###############################################################
#  Generated by:      Cadence Innovus 20.13-s083_1
#  OS:                Linux x86_64(Host ID iron-502-26)
#  Generated on:      Tue Nov 22 18:44:17 2022
#  Design:            user_proj_example
#  Command:           write_lef_abstract -specifyTopLayer 5 -PGPinLayers {5 6} -extractBlockObs -stripePin results/user_proj_example.lef
###############################################################

VERSION 5.8 ;

BUSBITCHARS "[]" ;
DIVIDERCHAR "/" ;

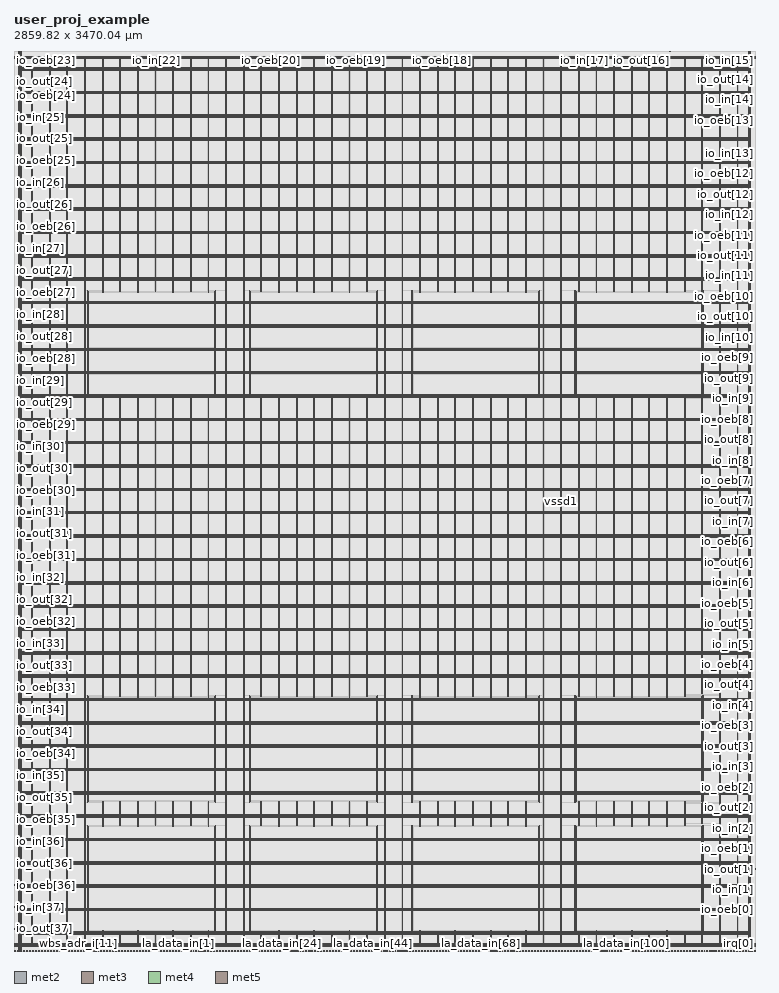
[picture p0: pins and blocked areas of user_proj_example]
MACRO user_proj_example
  CLASS BLOCK ;
  SIZE 2859.820000 BY 3470.040000 ;
  FOREIGN user_proj_example 0.000000 0.000000 ;
  ORIGIN 0 0 ;
  SYMMETRY X Y R90 ;
  PIN la_data_in[127]
    DIRECTION INPUT ;
    USE SIGNAL ;
    PORT
      LAYER met2 ;
        RECT 2830.540000 0.000000 2830.680000 0.485000 ;
    END
  END la_data_in[127]
  PIN la_data_in[126]
    DIRECTION INPUT ;
    USE SIGNAL ;
    PORT
      LAYER met2 ;
        RECT 2813.060000 0.000000 2813.200000 0.485000 ;
    END
  END la_data_in[126]
  PIN la_data_in[125]
    DIRECTION INPUT ;
    USE SIGNAL ;
    PORT
      LAYER met2 ;
        RECT 2796.040000 0.000000 2796.180000 0.485000 ;
    END
  END la_data_in[125]
  PIN la_data_in[124]
    DIRECTION INPUT ;
    USE SIGNAL ;
    PORT
      LAYER met2 ;
        RECT 2778.560000 0.000000 2778.700000 0.485000 ;
    END
  END la_data_in[124]
  PIN la_data_in[123]
    DIRECTION INPUT ;
    USE SIGNAL ;
    PORT
      LAYER met2 ;
        RECT 2761.080000 0.000000 2761.220000 0.485000 ;
    END
  END la_data_in[123]
  PIN la_data_in[122]
    DIRECTION INPUT ;
    USE SIGNAL ;
    PORT
      LAYER met2 ;
        RECT 2743.600000 0.000000 2743.740000 0.485000 ;
    END
  END la_data_in[122]
  PIN la_data_in[121]
    DIRECTION INPUT ;
    USE SIGNAL ;
    PORT
      LAYER met2 ;
        RECT 2726.120000 0.000000 2726.260000 0.485000 ;
    END
  END la_data_in[121]
  PIN la_data_in[120]
    DIRECTION INPUT ;
    USE SIGNAL ;
    PORT
      LAYER met2 ;
        RECT 2708.640000 0.000000 2708.780000 0.485000 ;
    END
  END la_data_in[120]
  PIN la_data_in[119]
    DIRECTION INPUT ;
    USE SIGNAL ;
    PORT
      LAYER met2 ;
        RECT 2691.160000 0.000000 2691.300000 0.485000 ;
    END
  END la_data_in[119]
  PIN la_data_in[118]
    DIRECTION INPUT ;
    USE SIGNAL ;
    PORT
      LAYER met2 ;
        RECT 2673.680000 0.000000 2673.820000 0.485000 ;
    END
  END la_data_in[118]
  PIN la_data_in[117]
    DIRECTION INPUT ;
    USE SIGNAL ;
    PORT
      LAYER met2 ;
        RECT 2656.200000 0.000000 2656.340000 0.485000 ;
    END
  END la_data_in[117]
  PIN la_data_in[116]
    DIRECTION INPUT ;
    USE SIGNAL ;
    PORT
      LAYER met2 ;
        RECT 2638.720000 0.000000 2638.860000 0.485000 ;
    END
  END la_data_in[116]
  PIN la_data_in[115]
    DIRECTION INPUT ;
    USE SIGNAL ;
    PORT
      LAYER met2 ;
        RECT 2621.700000 0.000000 2621.840000 0.485000 ;
    END
  END la_data_in[115]
  PIN la_data_in[114]
    DIRECTION INPUT ;
    USE SIGNAL ;
    PORT
      LAYER met2 ;
        RECT 2604.220000 0.000000 2604.360000 0.485000 ;
    END
  END la_data_in[114]
  PIN la_data_in[113]
    DIRECTION INPUT ;
    USE SIGNAL ;
    PORT
      LAYER met2 ;
        RECT 2586.740000 0.000000 2586.880000 0.485000 ;
    END
  END la_data_in[113]
  PIN la_data_in[112]
    DIRECTION INPUT ;
    USE SIGNAL ;
    PORT
      LAYER met2 ;
        RECT 2569.260000 0.000000 2569.400000 0.485000 ;
    END
  END la_data_in[112]
  PIN la_data_in[111]
    DIRECTION INPUT ;
    USE SIGNAL ;
    PORT
      LAYER met2 ;
        RECT 2551.780000 0.000000 2551.920000 0.485000 ;
    END
  END la_data_in[111]
  PIN la_data_in[110]
    DIRECTION INPUT ;
    USE SIGNAL ;
    PORT
      LAYER met2 ;
        RECT 2534.300000 0.000000 2534.440000 0.485000 ;
    END
  END la_data_in[110]
  PIN la_data_in[109]
    DIRECTION INPUT ;
    USE SIGNAL ;
    PORT
      LAYER met2 ;
        RECT 2516.820000 0.000000 2516.960000 0.485000 ;
    END
  END la_data_in[109]
  PIN la_data_in[108]
    DIRECTION INPUT ;
    USE SIGNAL ;
    PORT
      LAYER met2 ;
        RECT 2499.340000 0.000000 2499.480000 0.485000 ;
    END
  END la_data_in[108]
  PIN la_data_in[107]
    DIRECTION INPUT ;
    USE SIGNAL ;
    PORT
      LAYER met2 ;
        RECT 2481.860000 0.000000 2482.000000 0.485000 ;
    END
  END la_data_in[107]
  PIN la_data_in[106]
    DIRECTION INPUT ;
    USE SIGNAL ;
    PORT
      LAYER met2 ;
        RECT 2464.380000 0.000000 2464.520000 0.485000 ;
    END
  END la_data_in[106]
  PIN la_data_in[105]
    DIRECTION INPUT ;
    USE SIGNAL ;
    PORT
      LAYER met2 ;
        RECT 2446.900000 0.000000 2447.040000 0.485000 ;
    END
  END la_data_in[105]
  PIN la_data_in[104]
    DIRECTION INPUT ;
    USE SIGNAL ;
    PORT
      LAYER met2 ;
        RECT 2429.880000 0.000000 2430.020000 0.485000 ;
    END
  END la_data_in[104]
  PIN la_data_in[103]
    DIRECTION INPUT ;
    USE SIGNAL ;
    PORT
      LAYER met2 ;
        RECT 2412.400000 0.000000 2412.540000 0.485000 ;
    END
  END la_data_in[103]
  PIN la_data_in[102]
    DIRECTION INPUT ;
    USE SIGNAL ;
    PORT
      LAYER met2 ;
        RECT 2394.920000 0.000000 2395.060000 0.485000 ;
    END
  END la_data_in[102]
  PIN la_data_in[101]
    DIRECTION INPUT ;
    USE SIGNAL ;
    PORT
      LAYER met2 ;
        RECT 2377.440000 0.000000 2377.580000 0.485000 ;
    END
  END la_data_in[101]
  PIN la_data_in[100]
    DIRECTION INPUT ;
    USE SIGNAL ;
    PORT
      LAYER met2 ;
        RECT 2359.960000 0.000000 2360.100000 0.485000 ;
    END
  END la_data_in[100]
  PIN la_data_in[99]
    DIRECTION INPUT ;
    USE SIGNAL ;
    PORT
      LAYER met2 ;
        RECT 2342.480000 0.000000 2342.620000 0.485000 ;
    END
  END la_data_in[99]
  PIN la_data_in[98]
    DIRECTION INPUT ;
    USE SIGNAL ;
    PORT
      LAYER met2 ;
        RECT 2325.000000 0.000000 2325.140000 0.485000 ;
    END
  END la_data_in[98]
  PIN la_data_in[97]
    DIRECTION INPUT ;
    USE SIGNAL ;
    PORT
      LAYER met2 ;
        RECT 2307.520000 0.000000 2307.660000 0.485000 ;
    END
  END la_data_in[97]
  PIN la_data_in[96]
    DIRECTION INPUT ;
    USE SIGNAL ;
    PORT
      LAYER met2 ;
        RECT 2290.040000 0.000000 2290.180000 0.485000 ;
    END
  END la_data_in[96]
  PIN la_data_in[95]
    DIRECTION INPUT ;
    USE SIGNAL ;
    PORT
      LAYER met2 ;
        RECT 2272.560000 0.000000 2272.700000 0.485000 ;
    END
  END la_data_in[95]
  PIN la_data_in[94]
    DIRECTION INPUT ;
    USE SIGNAL ;
    PORT
      LAYER met2 ;
        RECT 2255.540000 0.000000 2255.680000 0.485000 ;
    END
  END la_data_in[94]
  PIN la_data_in[93]
    DIRECTION INPUT ;
    USE SIGNAL ;
    PORT
      LAYER met2 ;
        RECT 2238.060000 0.000000 2238.200000 0.485000 ;
    END
  END la_data_in[93]
  PIN la_data_in[92]
    DIRECTION INPUT ;
    USE SIGNAL ;
    PORT
      LAYER met2 ;
        RECT 2220.580000 0.000000 2220.720000 0.485000 ;
    END
  END la_data_in[92]
  PIN la_data_in[91]
    DIRECTION INPUT ;
    USE SIGNAL ;
    PORT
      LAYER met2 ;
        RECT 2203.100000 0.000000 2203.240000 0.485000 ;
    END
  END la_data_in[91]
  PIN la_data_in[90]
    DIRECTION INPUT ;
    USE SIGNAL ;
    PORT
      LAYER met2 ;
        RECT 2185.620000 0.000000 2185.760000 0.485000 ;
    END
  END la_data_in[90]
  PIN la_data_in[89]
    DIRECTION INPUT ;
    USE SIGNAL ;
    PORT
      LAYER met2 ;
        RECT 2168.140000 0.000000 2168.280000 0.485000 ;
    END
  END la_data_in[89]
  PIN la_data_in[88]
    DIRECTION INPUT ;
    USE SIGNAL ;
    PORT
      LAYER met2 ;
        RECT 2150.660000 0.000000 2150.800000 0.485000 ;
    END
  END la_data_in[88]
  PIN la_data_in[87]
    DIRECTION INPUT ;
    USE SIGNAL ;
    PORT
      LAYER met2 ;
        RECT 2133.180000 0.000000 2133.320000 0.485000 ;
    END
  END la_data_in[87]
  PIN la_data_in[86]
    DIRECTION INPUT ;
    USE SIGNAL ;
    PORT
      LAYER met2 ;
        RECT 2115.700000 0.000000 2115.840000 0.485000 ;
    END
  END la_data_in[86]
  PIN la_data_in[85]
    DIRECTION INPUT ;
    USE SIGNAL ;
    PORT
      LAYER met2 ;
        RECT 2098.220000 0.000000 2098.360000 0.485000 ;
    END
  END la_data_in[85]
  PIN la_data_in[84]
    DIRECTION INPUT ;
    USE SIGNAL ;
    PORT
      LAYER met2 ;
        RECT 2081.200000 0.000000 2081.340000 0.485000 ;
    END
  END la_data_in[84]
  PIN la_data_in[83]
    DIRECTION INPUT ;
    USE SIGNAL ;
    PORT
      LAYER met2 ;
        RECT 2063.720000 0.000000 2063.860000 0.485000 ;
    END
  END la_data_in[83]
  PIN la_data_in[82]
    DIRECTION INPUT ;
    USE SIGNAL ;
    PORT
      LAYER met2 ;
        RECT 2046.240000 0.000000 2046.380000 0.485000 ;
    END
  END la_data_in[82]
  PIN la_data_in[81]
    DIRECTION INPUT ;
    USE SIGNAL ;
    PORT
      LAYER met2 ;
        RECT 2028.760000 0.000000 2028.900000 0.485000 ;
    END
  END la_data_in[81]
  PIN la_data_in[80]
    DIRECTION INPUT ;
    USE SIGNAL ;
    PORT
      LAYER met2 ;
        RECT 2011.280000 0.000000 2011.420000 0.485000 ;
    END
  END la_data_in[80]
  PIN la_data_in[79]
    DIRECTION INPUT ;
    USE SIGNAL ;
    PORT
      LAYER met2 ;
        RECT 1993.800000 0.000000 1993.940000 0.485000 ;
    END
  END la_data_in[79]
  PIN la_data_in[78]
    DIRECTION INPUT ;
    USE SIGNAL ;
    PORT
      LAYER met2 ;
        RECT 1976.320000 0.000000 1976.460000 0.485000 ;
    END
  END la_data_in[78]
  PIN la_data_in[77]
    DIRECTION INPUT ;
    USE SIGNAL ;
    PORT
      LAYER met2 ;
        RECT 1958.840000 0.000000 1958.980000 0.485000 ;
    END
  END la_data_in[77]
  PIN la_data_in[76]
    DIRECTION INPUT ;
    USE SIGNAL ;
    PORT
      LAYER met2 ;
        RECT 1941.360000 0.000000 1941.500000 0.485000 ;
    END
  END la_data_in[76]
  PIN la_data_in[75]
    DIRECTION INPUT ;
    USE SIGNAL ;
    PORT
      LAYER met2 ;
        RECT 1923.880000 0.000000 1924.020000 0.485000 ;
    END
  END la_data_in[75]
  PIN la_data_in[74]
    DIRECTION INPUT ;
    USE SIGNAL ;
    PORT
      LAYER met2 ;
        RECT 1906.400000 0.000000 1906.540000 0.485000 ;
    END
  END la_data_in[74]
  PIN la_data_in[73]
    DIRECTION INPUT ;
    USE SIGNAL ;
    PORT
      LAYER met2 ;
        RECT 1889.380000 0.000000 1889.520000 0.485000 ;
    END
  END la_data_in[73]
  PIN la_data_in[72]
    DIRECTION INPUT ;
    USE SIGNAL ;
    PORT
      LAYER met2 ;
        RECT 1871.900000 0.000000 1872.040000 0.485000 ;
    END
  END la_data_in[72]
  PIN la_data_in[71]
    DIRECTION INPUT ;
    USE SIGNAL ;
    PORT
      LAYER met2 ;
        RECT 1854.420000 0.000000 1854.560000 0.485000 ;
    END
  END la_data_in[71]
  PIN la_data_in[70]
    DIRECTION INPUT ;
    USE SIGNAL ;
    PORT
      LAYER met2 ;
        RECT 1836.940000 0.000000 1837.080000 0.485000 ;
    END
  END la_data_in[70]
  PIN la_data_in[69]
    DIRECTION INPUT ;
    USE SIGNAL ;
    PORT
      LAYER met2 ;
        RECT 1819.460000 0.000000 1819.600000 0.485000 ;
    END
  END la_data_in[69]
  PIN la_data_in[68]
    DIRECTION INPUT ;
    USE SIGNAL ;
    PORT
      LAYER met2 ;
        RECT 1801.980000 0.000000 1802.120000 0.485000 ;
    END
  END la_data_in[68]
  PIN la_data_in[67]
    DIRECTION INPUT ;
    USE SIGNAL ;
    PORT
      LAYER met2 ;
        RECT 1784.500000 0.000000 1784.640000 0.485000 ;
    END
  END la_data_in[67]
  PIN la_data_in[66]
    DIRECTION INPUT ;
    USE SIGNAL ;
    PORT
      LAYER met2 ;
        RECT 1767.020000 0.000000 1767.160000 0.485000 ;
    END
  END la_data_in[66]
  PIN la_data_in[65]
    DIRECTION INPUT ;
    USE SIGNAL ;
    PORT
      LAYER met2 ;
        RECT 1749.540000 0.000000 1749.680000 0.485000 ;
    END
  END la_data_in[65]
  PIN la_data_in[64]
    DIRECTION INPUT ;
    USE SIGNAL ;
    PORT
      LAYER met2 ;
        RECT 1732.060000 0.000000 1732.200000 0.485000 ;
    END
  END la_data_in[64]
  PIN la_data_in[63]
    DIRECTION INPUT ;
    USE SIGNAL ;
    PORT
      LAYER met2 ;
        RECT 1715.040000 0.000000 1715.180000 0.485000 ;
    END
  END la_data_in[63]
  PIN la_data_in[62]
    DIRECTION INPUT ;
    USE SIGNAL ;
    PORT
      LAYER met2 ;
        RECT 1697.560000 0.000000 1697.700000 0.485000 ;
    END
  END la_data_in[62]
  PIN la_data_in[61]
    DIRECTION INPUT ;
    USE SIGNAL ;
    PORT
      LAYER met2 ;
        RECT 1680.080000 0.000000 1680.220000 0.485000 ;
    END
  END la_data_in[61]
  PIN la_data_in[60]
    DIRECTION INPUT ;
    USE SIGNAL ;
    PORT
      LAYER met2 ;
        RECT 1662.600000 0.000000 1662.740000 0.485000 ;
    END
  END la_data_in[60]
  PIN la_data_in[59]
    DIRECTION INPUT ;
    USE SIGNAL ;
    PORT
      LAYER met2 ;
        RECT 1645.120000 0.000000 1645.260000 0.485000 ;
    END
  END la_data_in[59]
  PIN la_data_in[58]
    DIRECTION INPUT ;
    USE SIGNAL ;
    PORT
      LAYER met2 ;
        RECT 1627.640000 0.000000 1627.780000 0.485000 ;
    END
  END la_data_in[58]
  PIN la_data_in[57]
    DIRECTION INPUT ;
    USE SIGNAL ;
    PORT
      LAYER met2 ;
        RECT 1610.160000 0.000000 1610.300000 0.485000 ;
    END
  END la_data_in[57]
  PIN la_data_in[56]
    DIRECTION INPUT ;
    USE SIGNAL ;
    PORT
      LAYER met2 ;
        RECT 1592.680000 0.000000 1592.820000 0.485000 ;
    END
  END la_data_in[56]
  PIN la_data_in[55]
    DIRECTION INPUT ;
    USE SIGNAL ;
    PORT
      LAYER met2 ;
        RECT 1575.200000 0.000000 1575.340000 0.485000 ;
    END
  END la_data_in[55]
  PIN la_data_in[54]
    DIRECTION INPUT ;
    USE SIGNAL ;
    PORT
      LAYER met2 ;
        RECT 1557.720000 0.000000 1557.860000 0.485000 ;
    END
  END la_data_in[54]
  PIN la_data_in[53]
    DIRECTION INPUT ;
    USE SIGNAL ;
    PORT
      LAYER met2 ;
        RECT 1540.700000 0.000000 1540.840000 0.485000 ;
    END
  END la_data_in[53]
  PIN la_data_in[52]
    DIRECTION INPUT ;
    USE SIGNAL ;
    PORT
      LAYER met2 ;
        RECT 1523.220000 0.000000 1523.360000 0.485000 ;
    END
  END la_data_in[52]
  PIN la_data_in[51]
    DIRECTION INPUT ;
    USE SIGNAL ;
    PORT
      LAYER met2 ;
        RECT 1505.740000 0.000000 1505.880000 0.485000 ;
    END
  END la_data_in[51]
  PIN la_data_in[50]
    DIRECTION INPUT ;
    USE SIGNAL ;
    PORT
      LAYER met2 ;
        RECT 1488.260000 0.000000 1488.400000 0.485000 ;
    END
  END la_data_in[50]
  PIN la_data_in[49]
    DIRECTION INPUT ;
    USE SIGNAL ;
    PORT
      LAYER met2 ;
        RECT 1470.780000 0.000000 1470.920000 0.485000 ;
    END
  END la_data_in[49]
  PIN la_data_in[48]
    DIRECTION INPUT ;
    USE SIGNAL ;
    PORT
      LAYER met2 ;
        RECT 1453.300000 0.000000 1453.440000 0.485000 ;
    END
  END la_data_in[48]
  PIN la_data_in[47]
    DIRECTION INPUT ;
    USE SIGNAL ;
    PORT
      LAYER met2 ;
        RECT 1435.820000 0.000000 1435.960000 0.485000 ;
    END
  END la_data_in[47]
  PIN la_data_in[46]
    DIRECTION INPUT ;
    USE SIGNAL ;
    PORT
      LAYER met2 ;
        RECT 1418.340000 0.000000 1418.480000 0.485000 ;
    END
  END la_data_in[46]
  PIN la_data_in[45]
    DIRECTION INPUT ;
    USE SIGNAL ;
    PORT
      LAYER met2 ;
        RECT 1400.860000 0.000000 1401.000000 0.485000 ;
    END
  END la_data_in[45]
  PIN la_data_in[44]
    DIRECTION INPUT ;
    USE SIGNAL ;
    PORT
      LAYER met2 ;
        RECT 1383.380000 0.000000 1383.520000 0.485000 ;
    END
  END la_data_in[44]
  PIN la_data_in[43]
    DIRECTION INPUT ;
    USE SIGNAL ;
    PORT
      LAYER met2 ;
        RECT 1366.360000 0.000000 1366.500000 0.485000 ;
    END
  END la_data_in[43]
  PIN la_data_in[42]
    DIRECTION INPUT ;
    USE SIGNAL ;
    PORT
      LAYER met2 ;
        RECT 1348.880000 0.000000 1349.020000 0.485000 ;
    END
  END la_data_in[42]
  PIN la_data_in[41]
    DIRECTION INPUT ;
    USE SIGNAL ;
    PORT
      LAYER met2 ;
        RECT 1331.400000 0.000000 1331.540000 0.485000 ;
    END
  END la_data_in[41]
  PIN la_data_in[40]
    DIRECTION INPUT ;
    USE SIGNAL ;
    PORT
      LAYER met2 ;
        RECT 1313.920000 0.000000 1314.060000 0.485000 ;
    END
  END la_data_in[40]
  PIN la_data_in[39]
    DIRECTION INPUT ;
    USE SIGNAL ;
    PORT
      LAYER met2 ;
        RECT 1296.440000 0.000000 1296.580000 0.485000 ;
    END
  END la_data_in[39]
  PIN la_data_in[38]
    DIRECTION INPUT ;
    USE SIGNAL ;
    PORT
      LAYER met2 ;
        RECT 1278.960000 0.000000 1279.100000 0.485000 ;
    END
  END la_data_in[38]
  PIN la_data_in[37]
    DIRECTION INPUT ;
    USE SIGNAL ;
    PORT
      LAYER met2 ;
        RECT 1261.480000 0.000000 1261.620000 0.485000 ;
    END
  END la_data_in[37]
  PIN la_data_in[36]
    DIRECTION INPUT ;
    USE SIGNAL ;
    PORT
      LAYER met2 ;
        RECT 1244.000000 0.000000 1244.140000 0.485000 ;
    END
  END la_data_in[36]
  PIN la_data_in[35]
    DIRECTION INPUT ;
    USE SIGNAL ;
    PORT
      LAYER met2 ;
        RECT 1226.520000 0.000000 1226.660000 0.485000 ;
    END
  END la_data_in[35]
  PIN la_data_in[34]
    DIRECTION INPUT ;
    USE SIGNAL ;
    PORT
      LAYER met2 ;
        RECT 1209.040000 0.000000 1209.180000 0.485000 ;
    END
  END la_data_in[34]
  PIN la_data_in[33]
    DIRECTION INPUT ;
    USE SIGNAL ;
    PORT
      LAYER met2 ;
        RECT 1192.020000 0.000000 1192.160000 0.485000 ;
    END
  END la_data_in[33]
  PIN la_data_in[32]
    DIRECTION INPUT ;
    USE SIGNAL ;
    PORT
      LAYER met2 ;
        RECT 1174.540000 0.000000 1174.680000 0.485000 ;
    END
  END la_data_in[32]
  PIN la_data_in[31]
    DIRECTION INPUT ;
    USE SIGNAL ;
    PORT
      LAYER met2 ;
        RECT 1157.060000 0.000000 1157.200000 0.485000 ;
    END
  END la_data_in[31]
  PIN la_data_in[30]
    DIRECTION INPUT ;
    USE SIGNAL ;
    PORT
      LAYER met2 ;
        RECT 1139.580000 0.000000 1139.720000 0.485000 ;
    END
  END la_data_in[30]
  PIN la_data_in[29]
    DIRECTION INPUT ;
    USE SIGNAL ;
    PORT
      LAYER met2 ;
        RECT 1122.100000 0.000000 1122.240000 0.485000 ;
    END
  END la_data_in[29]
  PIN la_data_in[28]
    DIRECTION INPUT ;
    USE SIGNAL ;
    PORT
      LAYER met2 ;
        RECT 1104.620000 0.000000 1104.760000 0.485000 ;
    END
  END la_data_in[28]
  PIN la_data_in[27]
    DIRECTION INPUT ;
    USE SIGNAL ;
    PORT
      LAYER met2 ;
        RECT 1087.140000 0.000000 1087.280000 0.485000 ;
    END
  END la_data_in[27]
  PIN la_data_in[26]
    DIRECTION INPUT ;
    USE SIGNAL ;
    PORT
      LAYER met2 ;
        RECT 1069.660000 0.000000 1069.800000 0.485000 ;
    END
  END la_data_in[26]
  PIN la_data_in[25]
    DIRECTION INPUT ;
    USE SIGNAL ;
    PORT
      LAYER met2 ;
        RECT 1052.180000 0.000000 1052.320000 0.485000 ;
    END
  END la_data_in[25]
  PIN la_data_in[24]
    DIRECTION INPUT ;
    USE SIGNAL ;
    PORT
      LAYER met2 ;
        RECT 1034.700000 0.000000 1034.840000 0.485000 ;
    END
  END la_data_in[24]
  PIN la_data_in[23]
    DIRECTION INPUT ;
    USE SIGNAL ;
    PORT
      LAYER met2 ;
        RECT 1017.220000 0.000000 1017.360000 0.485000 ;
    END
  END la_data_in[23]
  PIN la_data_in[22]
    DIRECTION INPUT ;
    USE SIGNAL ;
    PORT
      LAYER met2 ;
        RECT 1000.200000 0.000000 1000.340000 0.485000 ;
    END
  END la_data_in[22]
  PIN la_data_in[21]
    DIRECTION INPUT ;
    USE SIGNAL ;
    PORT
      LAYER met2 ;
        RECT 982.720000 0.000000 982.860000 0.485000 ;
    END
  END la_data_in[21]
  PIN la_data_in[20]
    DIRECTION INPUT ;
    USE SIGNAL ;
    PORT
      LAYER met2 ;
        RECT 965.240000 0.000000 965.380000 0.485000 ;
    END
  END la_data_in[20]
  PIN la_data_in[19]
    DIRECTION INPUT ;
    USE SIGNAL ;
    PORT
      LAYER met2 ;
        RECT 947.760000 0.000000 947.900000 0.485000 ;
    END
  END la_data_in[19]
  PIN la_data_in[18]
    DIRECTION INPUT ;
    USE SIGNAL ;
    PORT
      LAYER met2 ;
        RECT 930.280000 0.000000 930.420000 0.485000 ;
    END
  END la_data_in[18]
  PIN la_data_in[17]
    DIRECTION INPUT ;
    USE SIGNAL ;
    PORT
      LAYER met2 ;
        RECT 912.800000 0.000000 912.940000 0.485000 ;
    END
  END la_data_in[17]
  PIN la_data_in[16]
    DIRECTION INPUT ;
    USE SIGNAL ;
    PORT
      LAYER met2 ;
        RECT 895.320000 0.000000 895.460000 0.485000 ;
    END
  END la_data_in[16]
  PIN la_data_in[15]
    DIRECTION INPUT ;
    USE SIGNAL ;
    PORT
      LAYER met2 ;
        RECT 877.840000 0.000000 877.980000 0.485000 ;
    END
  END la_data_in[15]
  PIN la_data_in[14]
    DIRECTION INPUT ;
    USE SIGNAL ;
    PORT
      LAYER met2 ;
        RECT 860.360000 0.000000 860.500000 0.485000 ;
    END
  END la_data_in[14]
  PIN la_data_in[13]
    DIRECTION INPUT ;
    USE SIGNAL ;
    PORT
      LAYER met2 ;
        RECT 842.880000 0.000000 843.020000 0.485000 ;
    END
  END la_data_in[13]
  PIN la_data_in[12]
    DIRECTION INPUT ;
    USE SIGNAL ;
    PORT
      LAYER met2 ;
        RECT 825.860000 0.000000 826.000000 0.485000 ;
    END
  END la_data_in[12]
  PIN la_data_in[11]
    DIRECTION INPUT ;
    USE SIGNAL ;
    PORT
      LAYER met2 ;
        RECT 808.380000 0.000000 808.520000 0.485000 ;
    END
  END la_data_in[11]
  PIN la_data_in[10]
    DIRECTION INPUT ;
    USE SIGNAL ;
    PORT
      LAYER met2 ;
        RECT 790.900000 0.000000 791.040000 0.485000 ;
    END
  END la_data_in[10]
  PIN la_data_in[9]
    DIRECTION INPUT ;
    USE SIGNAL ;
    PORT
      LAYER met2 ;
        RECT 773.420000 0.000000 773.560000 0.485000 ;
    END
  END la_data_in[9]
  PIN la_data_in[8]
    DIRECTION INPUT ;
    USE SIGNAL ;
    PORT
      LAYER met2 ;
        RECT 755.940000 0.000000 756.080000 0.485000 ;
    END
  END la_data_in[8]
  PIN la_data_in[7]
    DIRECTION INPUT ;
    USE SIGNAL ;
    PORT
      LAYER met2 ;
        RECT 738.460000 0.000000 738.600000 0.485000 ;
    END
  END la_data_in[7]
  PIN la_data_in[6]
    DIRECTION INPUT ;
    USE SIGNAL ;
    PORT
      LAYER met2 ;
        RECT 720.980000 0.000000 721.120000 0.485000 ;
    END
  END la_data_in[6]
  PIN la_data_in[5]
    DIRECTION INPUT ;
    USE SIGNAL ;
    PORT
      LAYER met2 ;
        RECT 703.500000 0.000000 703.640000 0.485000 ;
    END
  END la_data_in[5]
  PIN la_data_in[4]
    DIRECTION INPUT ;
    USE SIGNAL ;
    PORT
      LAYER met2 ;
        RECT 686.020000 0.000000 686.160000 0.485000 ;
    END
  END la_data_in[4]
  PIN la_data_in[3]
    DIRECTION INPUT ;
    USE SIGNAL ;
    PORT
      LAYER met2 ;
        RECT 668.540000 0.000000 668.680000 0.485000 ;
    END
  END la_data_in[3]
  PIN la_data_in[2]
    DIRECTION INPUT ;
    USE SIGNAL ;
    PORT
      LAYER met2 ;
        RECT 651.520000 0.000000 651.660000 0.485000 ;
    END
  END la_data_in[2]
  PIN la_data_in[1]
    DIRECTION INPUT ;
    USE SIGNAL ;
    ANTENNAPARTIALMETALAREA 4.1103 LAYER met2  ;
    ANTENNAPARTIALMETALSIDEAREA 20.4435 LAYER met2  ;
    ANTENNAMODEL OXIDE1 ;
    ANTENNAGATEAREA 0.126 LAYER met2  ;
    ANTENNAMAXAREACAR 46.0325 LAYER met2  ;
    ANTENNAMAXSIDEAREACAR 224.643 LAYER met2  ;
    ANTENNAMAXCUTCAR 0.407937 LAYER via2  ;
    PORT
      LAYER met2 ;
        RECT 634.040000 0.000000 634.180000 0.485000 ;
    END
  END la_data_in[1]
  PIN la_data_in[0]
    DIRECTION INPUT ;
    USE SIGNAL ;
    PORT
      LAYER met2 ;
        RECT 616.560000 0.000000 616.700000 0.485000 ;
    END
  END la_data_in[0]
  PIN la_data_out[127]
    DIRECTION OUTPUT ;
    USE SIGNAL ;
    ANTENNADIFFAREA 0.336 LAYER met2  ;
    ANTENNAPARTIALMETALAREA 4.0627 LAYER met2  ;
    ANTENNAPARTIALMETALSIDEAREA 20.2055 LAYER met2  ;
    PORT
      LAYER met2 ;
        RECT 2836.520000 0.000000 2836.660000 0.485000 ;
    END
  END la_data_out[127]
  PIN la_data_out[126]
    DIRECTION OUTPUT ;
    USE SIGNAL ;
    ANTENNADIFFAREA 0.336 LAYER met2  ;
    ANTENNAPARTIALMETALAREA 4.4435 LAYER met2  ;
    ANTENNAPARTIALMETALSIDEAREA 22.1095 LAYER met2  ;
    PORT
      LAYER met2 ;
        RECT 2819.040000 0.000000 2819.180000 0.485000 ;
    END
  END la_data_out[126]
  PIN la_data_out[125]
    DIRECTION OUTPUT ;
    USE SIGNAL ;
    ANTENNADIFFAREA 0.336 LAYER met2  ;
    ANTENNAPARTIALMETALAREA 4.4435 LAYER met2  ;
    ANTENNAPARTIALMETALSIDEAREA 22.1095 LAYER met2  ;
    PORT
      LAYER met2 ;
        RECT 2801.560000 0.000000 2801.700000 0.485000 ;
    END
  END la_data_out[125]
  PIN la_data_out[124]
    DIRECTION OUTPUT ;
    USE SIGNAL ;
    ANTENNADIFFAREA 0.336 LAYER met2  ;
    ANTENNAPARTIALMETALAREA 4.4435 LAYER met2  ;
    ANTENNAPARTIALMETALSIDEAREA 22.1095 LAYER met2  ;
    PORT
      LAYER met2 ;
        RECT 2784.080000 0.000000 2784.220000 0.485000 ;
    END
  END la_data_out[124]
  PIN la_data_out[123]
    DIRECTION OUTPUT ;
    USE SIGNAL ;
    ANTENNADIFFAREA 0.336 LAYER met2  ;
    ANTENNAPARTIALMETALAREA 4.0627 LAYER met2  ;
    ANTENNAPARTIALMETALSIDEAREA 20.2055 LAYER met2  ;
    PORT
      LAYER met2 ;
        RECT 2766.600000 0.000000 2766.740000 0.485000 ;
    END
  END la_data_out[123]
  PIN la_data_out[122]
    DIRECTION OUTPUT ;
    USE SIGNAL ;
    ANTENNADIFFAREA 0.336 LAYER met2  ;
    ANTENNAPARTIALMETALAREA 4.0627 LAYER met2  ;
    ANTENNAPARTIALMETALSIDEAREA 20.2055 LAYER met2  ;
    PORT
      LAYER met2 ;
        RECT 2749.120000 0.000000 2749.260000 0.485000 ;
    END
  END la_data_out[122]
  PIN la_data_out[121]
    DIRECTION OUTPUT ;
    USE SIGNAL ;
    ANTENNADIFFAREA 0.336 LAYER met2  ;
    ANTENNAPARTIALMETALAREA 4.4435 LAYER met2  ;
    ANTENNAPARTIALMETALSIDEAREA 22.1095 LAYER met2  ;
    PORT
      LAYER met2 ;
        RECT 2732.100000 0.000000 2732.240000 0.485000 ;
    END
  END la_data_out[121]
  PIN la_data_out[120]
    DIRECTION OUTPUT ;
    USE SIGNAL ;
    ANTENNADIFFAREA 0.336 LAYER met2  ;
    ANTENNAPARTIALMETALAREA 4.0627 LAYER met2  ;
    ANTENNAPARTIALMETALSIDEAREA 20.2055 LAYER met2  ;
    PORT
      LAYER met2 ;
        RECT 2714.620000 0.000000 2714.760000 0.485000 ;
    END
  END la_data_out[120]
  PIN la_data_out[119]
    DIRECTION OUTPUT ;
    USE SIGNAL ;
    ANTENNADIFFAREA 0.336 LAYER met2  ;
    ANTENNAPARTIALMETALAREA 4.4435 LAYER met2  ;
    ANTENNAPARTIALMETALSIDEAREA 22.1095 LAYER met2  ;
    PORT
      LAYER met2 ;
        RECT 2697.140000 0.000000 2697.280000 0.485000 ;
    END
  END la_data_out[119]
  PIN la_data_out[118]
    DIRECTION OUTPUT ;
    USE SIGNAL ;
    ANTENNADIFFAREA 0.336 LAYER met2  ;
    ANTENNAPARTIALMETALAREA 4.4435 LAYER met2  ;
    ANTENNAPARTIALMETALSIDEAREA 22.1095 LAYER met2  ;
    PORT
      LAYER met2 ;
        RECT 2679.660000 0.000000 2679.800000 0.485000 ;
    END
  END la_data_out[118]
  PIN la_data_out[117]
    DIRECTION OUTPUT ;
    USE SIGNAL ;
    ANTENNADIFFAREA 0.336 LAYER met2  ;
    ANTENNAPARTIALMETALAREA 4.0627 LAYER met2  ;
    ANTENNAPARTIALMETALSIDEAREA 20.2055 LAYER met2  ;
    PORT
      LAYER met2 ;
        RECT 2662.180000 0.000000 2662.320000 0.485000 ;
    END
  END la_data_out[117]
  PIN la_data_out[116]
    DIRECTION OUTPUT ;
    USE SIGNAL ;
    ANTENNADIFFAREA 0.336 LAYER met2  ;
    ANTENNAPARTIALMETALAREA 4.0627 LAYER met2  ;
    ANTENNAPARTIALMETALSIDEAREA 20.2055 LAYER met2  ;
    PORT
      LAYER met2 ;
        RECT 2644.700000 0.000000 2644.840000 0.485000 ;
    END
  END la_data_out[116]
  PIN la_data_out[115]
    DIRECTION OUTPUT ;
    USE SIGNAL ;
    ANTENNADIFFAREA 0.336 LAYER met2  ;
    ANTENNAPARTIALMETALAREA 4.0627 LAYER met2  ;
    ANTENNAPARTIALMETALSIDEAREA 20.2055 LAYER met2  ;
    PORT
      LAYER met2 ;
        RECT 2627.220000 0.000000 2627.360000 0.485000 ;
    END
  END la_data_out[115]
  PIN la_data_out[114]
    DIRECTION OUTPUT ;
    USE SIGNAL ;
    ANTENNADIFFAREA 0.336 LAYER met2  ;
    ANTENNAPARTIALMETALAREA 4.0627 LAYER met2  ;
    ANTENNAPARTIALMETALSIDEAREA 20.2055 LAYER met2  ;
    PORT
      LAYER met2 ;
        RECT 2609.740000 0.000000 2609.880000 0.485000 ;
    END
  END la_data_out[114]
  PIN la_data_out[113]
    DIRECTION OUTPUT ;
    USE SIGNAL ;
    ANTENNADIFFAREA 0.336 LAYER met2  ;
    ANTENNAPARTIALMETALAREA 4.0627 LAYER met2  ;
    ANTENNAPARTIALMETALSIDEAREA 20.2055 LAYER met2  ;
    PORT
      LAYER met2 ;
        RECT 2592.260000 0.000000 2592.400000 0.485000 ;
    END
  END la_data_out[113]
  PIN la_data_out[112]
    DIRECTION OUTPUT ;
    USE SIGNAL ;
    ANTENNADIFFAREA 0.336 LAYER met2  ;
    ANTENNAPARTIALMETALAREA 4.0627 LAYER met2  ;
    ANTENNAPARTIALMETALSIDEAREA 20.2055 LAYER met2  ;
    PORT
      LAYER met2 ;
        RECT 2574.780000 0.000000 2574.920000 0.485000 ;
    END
  END la_data_out[112]
  PIN la_data_out[111]
    DIRECTION OUTPUT ;
    USE SIGNAL ;
    ANTENNADIFFAREA 0.336 LAYER met2  ;
    ANTENNAPARTIALMETALAREA 4.0627 LAYER met2  ;
    ANTENNAPARTIALMETALSIDEAREA 20.2055 LAYER met2  ;
    PORT
      LAYER met2 ;
        RECT 2557.760000 0.000000 2557.900000 0.485000 ;
    END
  END la_data_out[111]
  PIN la_data_out[110]
    DIRECTION OUTPUT ;
    USE SIGNAL ;
    ANTENNADIFFAREA 0.336 LAYER met2  ;
    ANTENNAPARTIALMETALAREA 4.0627 LAYER met2  ;
    ANTENNAPARTIALMETALSIDEAREA 20.2055 LAYER met2  ;
    PORT
      LAYER met2 ;
        RECT 2540.280000 0.000000 2540.420000 0.485000 ;
    END
  END la_data_out[110]
  PIN la_data_out[109]
    DIRECTION OUTPUT ;
    USE SIGNAL ;
    ANTENNADIFFAREA 0.336 LAYER met2  ;
    ANTENNAPARTIALMETALAREA 4.0627 LAYER met2  ;
    ANTENNAPARTIALMETALSIDEAREA 20.2055 LAYER met2  ;
    PORT
      LAYER met2 ;
        RECT 2522.800000 0.000000 2522.940000 0.485000 ;
    END
  END la_data_out[109]
  PIN la_data_out[108]
    DIRECTION OUTPUT ;
    USE SIGNAL ;
    ANTENNADIFFAREA 0.336 LAYER met2  ;
    ANTENNAPARTIALMETALAREA 4.0627 LAYER met2  ;
    ANTENNAPARTIALMETALSIDEAREA 20.2055 LAYER met2  ;
    PORT
      LAYER met2 ;
        RECT 2505.320000 0.000000 2505.460000 0.485000 ;
    END
  END la_data_out[108]
  PIN la_data_out[107]
    DIRECTION OUTPUT ;
    USE SIGNAL ;
    ANTENNADIFFAREA 0.336 LAYER met2  ;
    ANTENNAPARTIALMETALAREA 4.0627 LAYER met2  ;
    ANTENNAPARTIALMETALSIDEAREA 20.2055 LAYER met2  ;
    PORT
      LAYER met2 ;
        RECT 2487.840000 0.000000 2487.980000 0.485000 ;
    END
  END la_data_out[107]
  PIN la_data_out[106]
    DIRECTION OUTPUT ;
    USE SIGNAL ;
    ANTENNADIFFAREA 0.336 LAYER met2  ;
    ANTENNAPARTIALMETALAREA 4.0627 LAYER met2  ;
    ANTENNAPARTIALMETALSIDEAREA 20.2055 LAYER met2  ;
    PORT
      LAYER met2 ;
        RECT 2470.360000 0.000000 2470.500000 0.485000 ;
    END
  END la_data_out[106]
  PIN la_data_out[105]
    DIRECTION OUTPUT ;
    USE SIGNAL ;
    ANTENNADIFFAREA 0.336 LAYER met2  ;
    ANTENNAPARTIALMETALAREA 4.0627 LAYER met2  ;
    ANTENNAPARTIALMETALSIDEAREA 20.2055 LAYER met2  ;
    PORT
      LAYER met2 ;
        RECT 2452.880000 0.000000 2453.020000 0.485000 ;
    END
  END la_data_out[105]
  PIN la_data_out[104]
    DIRECTION OUTPUT ;
    USE SIGNAL ;
    ANTENNADIFFAREA 0.336 LAYER met2  ;
    ANTENNAPARTIALMETALAREA 4.0627 LAYER met2  ;
    ANTENNAPARTIALMETALSIDEAREA 20.2055 LAYER met2  ;
    PORT
      LAYER met2 ;
        RECT 2435.400000 0.000000 2435.540000 0.485000 ;
    END
  END la_data_out[104]
  PIN la_data_out[103]
    DIRECTION OUTPUT ;
    USE SIGNAL ;
    ANTENNADIFFAREA 0.336 LAYER met2  ;
    ANTENNAPARTIALMETALAREA 4.0627 LAYER met2  ;
    ANTENNAPARTIALMETALSIDEAREA 20.2055 LAYER met2  ;
    PORT
      LAYER met2 ;
        RECT 2417.920000 0.000000 2418.060000 0.485000 ;
    END
  END la_data_out[103]
  PIN la_data_out[102]
    DIRECTION OUTPUT ;
    USE SIGNAL ;
    ANTENNADIFFAREA 0.336 LAYER met2  ;
    ANTENNAPARTIALMETALAREA 4.0627 LAYER met2  ;
    ANTENNAPARTIALMETALSIDEAREA 20.2055 LAYER met2  ;
    PORT
      LAYER met2 ;
        RECT 2400.440000 0.000000 2400.580000 0.485000 ;
    END
  END la_data_out[102]
  PIN la_data_out[101]
    DIRECTION OUTPUT ;
    USE SIGNAL ;
    ANTENNADIFFAREA 0.336 LAYER met2  ;
    ANTENNAPARTIALMETALAREA 4.1271 LAYER met2  ;
    ANTENNAPARTIALMETALSIDEAREA 20.5275 LAYER met2  ;
    PORT
      LAYER met2 ;
        RECT 2383.420000 0.000000 2383.560000 0.485000 ;
    END
  END la_data_out[101]
  PIN la_data_out[100]
    DIRECTION OUTPUT ;
    USE SIGNAL ;
    ANTENNADIFFAREA 0.336 LAYER met2  ;
    ANTENNAPARTIALMETALAREA 4.0627 LAYER met2  ;
    ANTENNAPARTIALMETALSIDEAREA 20.2055 LAYER met2  ;
    PORT
      LAYER met2 ;
        RECT 2365.940000 0.000000 2366.080000 0.485000 ;
    END
  END la_data_out[100]
  PIN la_data_out[99]
    DIRECTION OUTPUT ;
    USE SIGNAL ;
    ANTENNADIFFAREA 0.336 LAYER met2  ;
    ANTENNAPARTIALMETALAREA 4.0627 LAYER met2  ;
    ANTENNAPARTIALMETALSIDEAREA 20.2055 LAYER met2  ;
    PORT
      LAYER met2 ;
        RECT 2348.460000 0.000000 2348.600000 0.485000 ;
    END
  END la_data_out[99]
  PIN la_data_out[98]
    DIRECTION OUTPUT ;
    USE SIGNAL ;
    ANTENNADIFFAREA 0.336 LAYER met2  ;
    ANTENNAPARTIALMETALAREA 4.0627 LAYER met2  ;
    ANTENNAPARTIALMETALSIDEAREA 20.2055 LAYER met2  ;
    PORT
      LAYER met2 ;
        RECT 2330.980000 0.000000 2331.120000 0.485000 ;
    END
  END la_data_out[98]
  PIN la_data_out[97]
    DIRECTION OUTPUT ;
    USE SIGNAL ;
    ANTENNADIFFAREA 0.336 LAYER met2  ;
    ANTENNAPARTIALMETALAREA 4.0627 LAYER met2  ;
    ANTENNAPARTIALMETALSIDEAREA 20.2055 LAYER met2  ;
    PORT
      LAYER met2 ;
        RECT 2313.500000 0.000000 2313.640000 0.485000 ;
    END
  END la_data_out[97]
  PIN la_data_out[96]
    DIRECTION OUTPUT ;
    USE SIGNAL ;
    ANTENNADIFFAREA 0.336 LAYER met2  ;
    ANTENNAPARTIALMETALAREA 4.0627 LAYER met2  ;
    ANTENNAPARTIALMETALSIDEAREA 20.2055 LAYER met2  ;
    PORT
      LAYER met2 ;
        RECT 2296.020000 0.000000 2296.160000 0.485000 ;
    END
  END la_data_out[96]
  PIN la_data_out[95]
    DIRECTION OUTPUT ;
    USE SIGNAL ;
    ANTENNADIFFAREA 0.336 LAYER met2  ;
    ANTENNAPARTIALMETALAREA 4.0627 LAYER met2  ;
    ANTENNAPARTIALMETALSIDEAREA 20.2055 LAYER met2  ;
    PORT
      LAYER met2 ;
        RECT 2278.540000 0.000000 2278.680000 0.485000 ;
    END
  END la_data_out[95]
  PIN la_data_out[94]
    DIRECTION OUTPUT ;
    USE SIGNAL ;
    ANTENNADIFFAREA 0.336 LAYER met2  ;
    ANTENNAPARTIALMETALAREA 4.0627 LAYER met2  ;
    ANTENNAPARTIALMETALSIDEAREA 20.2055 LAYER met2  ;
    PORT
      LAYER met2 ;
        RECT 2261.060000 0.000000 2261.200000 0.485000 ;
    END
  END la_data_out[94]
  PIN la_data_out[93]
    DIRECTION OUTPUT ;
    USE SIGNAL ;
    ANTENNADIFFAREA 0.336 LAYER met2  ;
    ANTENNAPARTIALMETALAREA 4.0627 LAYER met2  ;
    ANTENNAPARTIALMETALSIDEAREA 20.2055 LAYER met2  ;
    PORT
      LAYER met2 ;
        RECT 2243.580000 0.000000 2243.720000 0.485000 ;
    END
  END la_data_out[93]
  PIN la_data_out[92]
    DIRECTION OUTPUT ;
    USE SIGNAL ;
    ANTENNADIFFAREA 0.336 LAYER met2  ;
    ANTENNAPARTIALMETALAREA 4.0627 LAYER met2  ;
    ANTENNAPARTIALMETALSIDEAREA 20.2055 LAYER met2  ;
    PORT
      LAYER met2 ;
        RECT 2226.100000 0.000000 2226.240000 0.485000 ;
    END
  END la_data_out[92]
  PIN la_data_out[91]
    DIRECTION OUTPUT ;
    USE SIGNAL ;
    ANTENNADIFFAREA 0.336 LAYER met2  ;
    ANTENNAPARTIALMETALAREA 4.0627 LAYER met2  ;
    ANTENNAPARTIALMETALSIDEAREA 20.2055 LAYER met2  ;
    PORT
      LAYER met2 ;
        RECT 2208.620000 0.000000 2208.760000 0.485000 ;
    END
  END la_data_out[91]
  PIN la_data_out[90]
    DIRECTION OUTPUT ;
    USE SIGNAL ;
    ANTENNADIFFAREA 0.336 LAYER met2  ;
    ANTENNAPARTIALMETALAREA 4.0627 LAYER met2  ;
    ANTENNAPARTIALMETALSIDEAREA 20.2055 LAYER met2  ;
    PORT
      LAYER met2 ;
        RECT 2191.600000 0.000000 2191.740000 0.485000 ;
    END
  END la_data_out[90]
  PIN la_data_out[89]
    DIRECTION OUTPUT ;
    USE SIGNAL ;
    ANTENNADIFFAREA 0.336 LAYER met2  ;
    ANTENNAPARTIALMETALAREA 4.0627 LAYER met2  ;
    ANTENNAPARTIALMETALSIDEAREA 20.2055 LAYER met2  ;
    PORT
      LAYER met2 ;
        RECT 2174.120000 0.000000 2174.260000 0.485000 ;
    END
  END la_data_out[89]
  PIN la_data_out[88]
    DIRECTION OUTPUT ;
    USE SIGNAL ;
    ANTENNADIFFAREA 0.336 LAYER met2  ;
    ANTENNAPARTIALMETALAREA 4.4435 LAYER met2  ;
    ANTENNAPARTIALMETALSIDEAREA 22.1095 LAYER met2  ;
    PORT
      LAYER met2 ;
        RECT 2156.640000 0.000000 2156.780000 0.485000 ;
    END
  END la_data_out[88]
  PIN la_data_out[87]
    DIRECTION OUTPUT ;
    USE SIGNAL ;
    ANTENNADIFFAREA 0.336 LAYER met2  ;
    ANTENNAPARTIALMETALAREA 4.4435 LAYER met2  ;
    ANTENNAPARTIALMETALSIDEAREA 22.1095 LAYER met2  ;
    PORT
      LAYER met2 ;
        RECT 2139.160000 0.000000 2139.300000 0.485000 ;
    END
  END la_data_out[87]
  PIN la_data_out[86]
    DIRECTION OUTPUT ;
    USE SIGNAL ;
    ANTENNADIFFAREA 0.336 LAYER met2  ;
    ANTENNAPARTIALMETALAREA 4.0627 LAYER met2  ;
    ANTENNAPARTIALMETALSIDEAREA 20.2055 LAYER met2  ;
    PORT
      LAYER met2 ;
        RECT 2121.680000 0.000000 2121.820000 0.485000 ;
    END
  END la_data_out[86]
  PIN la_data_out[85]
    DIRECTION OUTPUT ;
    USE SIGNAL ;
    ANTENNADIFFAREA 0.336 LAYER met2  ;
    ANTENNAPARTIALMETALAREA 4.4435 LAYER met2  ;
    ANTENNAPARTIALMETALSIDEAREA 22.1095 LAYER met2  ;
    PORT
      LAYER met2 ;
        RECT 2104.200000 0.000000 2104.340000 0.485000 ;
    END
  END la_data_out[85]
  PIN la_data_out[84]
    DIRECTION OUTPUT ;
    USE SIGNAL ;
    ANTENNADIFFAREA 0.336 LAYER met2  ;
    ANTENNAPARTIALMETALAREA 4.0627 LAYER met2  ;
    ANTENNAPARTIALMETALSIDEAREA 20.2055 LAYER met2  ;
    PORT
      LAYER met2 ;
        RECT 2086.720000 0.000000 2086.860000 0.485000 ;
    END
  END la_data_out[84]
  PIN la_data_out[83]
    DIRECTION OUTPUT ;
    USE SIGNAL ;
    ANTENNADIFFAREA 0.336 LAYER met2  ;
    ANTENNAPARTIALMETALAREA 4.4435 LAYER met2  ;
    ANTENNAPARTIALMETALSIDEAREA 22.1095 LAYER met2  ;
    PORT
      LAYER met2 ;
        RECT 2069.240000 0.000000 2069.380000 0.485000 ;
    END
  END la_data_out[83]
  PIN la_data_out[82]
    DIRECTION OUTPUT ;
    USE SIGNAL ;
    ANTENNADIFFAREA 0.336 LAYER met2  ;
    ANTENNAPARTIALMETALAREA 4.0627 LAYER met2  ;
    ANTENNAPARTIALMETALSIDEAREA 20.2055 LAYER met2  ;
    PORT
      LAYER met2 ;
        RECT 2051.760000 0.000000 2051.900000 0.485000 ;
    END
  END la_data_out[82]
  PIN la_data_out[81]
    DIRECTION OUTPUT ;
    USE SIGNAL ;
    ANTENNADIFFAREA 0.336 LAYER met2  ;
    ANTENNAPARTIALMETALAREA 4.0627 LAYER met2  ;
    ANTENNAPARTIALMETALSIDEAREA 20.2055 LAYER met2  ;
    PORT
      LAYER met2 ;
        RECT 2034.280000 0.000000 2034.420000 0.485000 ;
    END
  END la_data_out[81]
  PIN la_data_out[80]
    DIRECTION OUTPUT ;
    USE SIGNAL ;
    ANTENNADIFFAREA 0.336 LAYER met2  ;
    ANTENNAPARTIALMETALAREA 4.0627 LAYER met2  ;
    ANTENNAPARTIALMETALSIDEAREA 20.2055 LAYER met2  ;
    PORT
      LAYER met2 ;
        RECT 2017.260000 0.000000 2017.400000 0.485000 ;
    END
  END la_data_out[80]
  PIN la_data_out[79]
    DIRECTION OUTPUT ;
    USE SIGNAL ;
    ANTENNADIFFAREA 0.336 LAYER met2  ;
    ANTENNAPARTIALMETALAREA 4.0627 LAYER met2  ;
    ANTENNAPARTIALMETALSIDEAREA 20.2055 LAYER met2  ;
    PORT
      LAYER met2 ;
        RECT 1999.780000 0.000000 1999.920000 0.485000 ;
    END
  END la_data_out[79]
  PIN la_data_out[78]
    DIRECTION OUTPUT ;
    USE SIGNAL ;
    ANTENNADIFFAREA 0.336 LAYER met2  ;
    ANTENNAPARTIALMETALAREA 4.0627 LAYER met2  ;
    ANTENNAPARTIALMETALSIDEAREA 20.2055 LAYER met2  ;
    PORT
      LAYER met2 ;
        RECT 1982.300000 0.000000 1982.440000 0.485000 ;
    END
  END la_data_out[78]
  PIN la_data_out[77]
    DIRECTION OUTPUT ;
    USE SIGNAL ;
    ANTENNADIFFAREA 0.336 LAYER met2  ;
    ANTENNAPARTIALMETALAREA 4.0627 LAYER met2  ;
    ANTENNAPARTIALMETALSIDEAREA 20.2055 LAYER met2  ;
    PORT
      LAYER met2 ;
        RECT 1964.820000 0.000000 1964.960000 0.485000 ;
    END
  END la_data_out[77]
  PIN la_data_out[76]
    DIRECTION OUTPUT ;
    USE SIGNAL ;
    ANTENNADIFFAREA 0.336 LAYER met2  ;
    ANTENNAPARTIALMETALAREA 4.0627 LAYER met2  ;
    ANTENNAPARTIALMETALSIDEAREA 20.2055 LAYER met2  ;
    PORT
      LAYER met2 ;
        RECT 1947.340000 0.000000 1947.480000 0.485000 ;
    END
  END la_data_out[76]
  PIN la_data_out[75]
    DIRECTION OUTPUT ;
    USE SIGNAL ;
    ANTENNADIFFAREA 0.336 LAYER met2  ;
    ANTENNAPARTIALMETALAREA 4.0627 LAYER met2  ;
    ANTENNAPARTIALMETALSIDEAREA 20.2055 LAYER met2  ;
    PORT
      LAYER met2 ;
        RECT 1929.860000 0.000000 1930.000000 0.485000 ;
    END
  END la_data_out[75]
  PIN la_data_out[74]
    DIRECTION OUTPUT ;
    USE SIGNAL ;
    ANTENNADIFFAREA 0.336 LAYER met2  ;
    ANTENNAPARTIALMETALAREA 4.0627 LAYER met2  ;
    ANTENNAPARTIALMETALSIDEAREA 20.2055 LAYER met2  ;
    PORT
      LAYER met2 ;
        RECT 1912.380000 0.000000 1912.520000 0.485000 ;
    END
  END la_data_out[74]
  PIN la_data_out[73]
    DIRECTION OUTPUT ;
    USE SIGNAL ;
    ANTENNADIFFAREA 0.336 LAYER met2  ;
    ANTENNAPARTIALMETALAREA 4.0627 LAYER met2  ;
    ANTENNAPARTIALMETALSIDEAREA 20.2055 LAYER met2  ;
    PORT
      LAYER met2 ;
        RECT 1894.900000 0.000000 1895.040000 0.485000 ;
    END
  END la_data_out[73]
  PIN la_data_out[72]
    DIRECTION OUTPUT ;
    USE SIGNAL ;
    ANTENNADIFFAREA 0.336 LAYER met2  ;
    ANTENNAPARTIALMETALAREA 4.0627 LAYER met2  ;
    ANTENNAPARTIALMETALSIDEAREA 20.2055 LAYER met2  ;
    PORT
      LAYER met2 ;
        RECT 1877.420000 0.000000 1877.560000 0.485000 ;
    END
  END la_data_out[72]
  PIN la_data_out[71]
    DIRECTION OUTPUT ;
    USE SIGNAL ;
    ANTENNADIFFAREA 0.336 LAYER met2  ;
    ANTENNAPARTIALMETALAREA 4.0627 LAYER met2  ;
    ANTENNAPARTIALMETALSIDEAREA 20.2055 LAYER met2  ;
    PORT
      LAYER met2 ;
        RECT 1859.940000 0.000000 1860.080000 0.485000 ;
    END
  END la_data_out[71]
  PIN la_data_out[70]
    DIRECTION OUTPUT ;
    USE SIGNAL ;
    ANTENNADIFFAREA 0.336 LAYER met2  ;
    ANTENNAPARTIALMETALAREA 4.0627 LAYER met2  ;
    ANTENNAPARTIALMETALSIDEAREA 20.2055 LAYER met2  ;
    PORT
      LAYER met2 ;
        RECT 1842.920000 0.000000 1843.060000 0.485000 ;
    END
  END la_data_out[70]
  PIN la_data_out[69]
    DIRECTION OUTPUT ;
    USE SIGNAL ;
    ANTENNADIFFAREA 0.336 LAYER met2  ;
    ANTENNAPARTIALMETALAREA 4.0627 LAYER met2  ;
    ANTENNAPARTIALMETALSIDEAREA 20.2055 LAYER met2  ;
    PORT
      LAYER met2 ;
        RECT 1825.440000 0.000000 1825.580000 0.485000 ;
    END
  END la_data_out[69]
  PIN la_data_out[68]
    DIRECTION OUTPUT ;
    USE SIGNAL ;
    ANTENNADIFFAREA 0.336 LAYER met2  ;
    ANTENNAPARTIALMETALAREA 4.0627 LAYER met2  ;
    ANTENNAPARTIALMETALSIDEAREA 20.2055 LAYER met2  ;
    PORT
      LAYER met2 ;
        RECT 1807.960000 0.000000 1808.100000 0.485000 ;
    END
  END la_data_out[68]
  PIN la_data_out[67]
    DIRECTION OUTPUT ;
    USE SIGNAL ;
    ANTENNADIFFAREA 0.336 LAYER met2  ;
    ANTENNAPARTIALMETALAREA 4.0627 LAYER met2  ;
    ANTENNAPARTIALMETALSIDEAREA 20.2055 LAYER met2  ;
    PORT
      LAYER met2 ;
        RECT 1790.480000 0.000000 1790.620000 0.485000 ;
    END
  END la_data_out[67]
  PIN la_data_out[66]
    DIRECTION OUTPUT ;
    USE SIGNAL ;
    ANTENNADIFFAREA 0.336 LAYER met2  ;
    ANTENNAPARTIALMETALAREA 4.0627 LAYER met2  ;
    ANTENNAPARTIALMETALSIDEAREA 20.2055 LAYER met2  ;
    PORT
      LAYER met2 ;
        RECT 1773.000000 0.000000 1773.140000 0.485000 ;
    END
  END la_data_out[66]
  PIN la_data_out[65]
    DIRECTION OUTPUT ;
    USE SIGNAL ;
    ANTENNADIFFAREA 0.336 LAYER met2  ;
    ANTENNAPARTIALMETALAREA 4.0627 LAYER met2  ;
    ANTENNAPARTIALMETALSIDEAREA 20.2055 LAYER met2  ;
    PORT
      LAYER met2 ;
        RECT 1755.520000 0.000000 1755.660000 0.485000 ;
    END
  END la_data_out[65]
  PIN la_data_out[64]
    DIRECTION OUTPUT ;
    USE SIGNAL ;
    ANTENNADIFFAREA 0.336 LAYER met2  ;
    ANTENNAPARTIALMETALAREA 4.0627 LAYER met2  ;
    ANTENNAPARTIALMETALSIDEAREA 20.2055 LAYER met2  ;
    PORT
      LAYER met2 ;
        RECT 1738.040000 0.000000 1738.180000 0.485000 ;
    END
  END la_data_out[64]
  PIN la_data_out[63]
    DIRECTION OUTPUT ;
    USE SIGNAL ;
    ANTENNADIFFAREA 0.336 LAYER met2  ;
    ANTENNAPARTIALMETALAREA 4.0627 LAYER met2  ;
    ANTENNAPARTIALMETALSIDEAREA 20.2055 LAYER met2  ;
    PORT
      LAYER met2 ;
        RECT 1720.560000 0.000000 1720.700000 0.485000 ;
    END
  END la_data_out[63]
  PIN la_data_out[62]
    DIRECTION OUTPUT ;
    USE SIGNAL ;
    ANTENNADIFFAREA 0.336 LAYER met2  ;
    ANTENNAPARTIALMETALAREA 4.1271 LAYER met2  ;
    ANTENNAPARTIALMETALSIDEAREA 20.5275 LAYER met2  ;
    PORT
      LAYER met2 ;
        RECT 1703.080000 0.000000 1703.220000 0.485000 ;
    END
  END la_data_out[62]
  PIN la_data_out[61]
    DIRECTION OUTPUT ;
    USE SIGNAL ;
    ANTENNADIFFAREA 0.336 LAYER met2  ;
    ANTENNAPARTIALMETALAREA 4.0627 LAYER met2  ;
    ANTENNAPARTIALMETALSIDEAREA 20.2055 LAYER met2  ;
    PORT
      LAYER met2 ;
        RECT 1685.600000 0.000000 1685.740000 0.485000 ;
    END
  END la_data_out[61]
  PIN la_data_out[60]
    DIRECTION OUTPUT ;
    USE SIGNAL ;
    ANTENNADIFFAREA 0.336 LAYER met2  ;
    ANTENNAPARTIALMETALAREA 4.0627 LAYER met2  ;
    ANTENNAPARTIALMETALSIDEAREA 20.2055 LAYER met2  ;
    PORT
      LAYER met2 ;
        RECT 1668.120000 0.000000 1668.260000 0.485000 ;
    END
  END la_data_out[60]
  PIN la_data_out[59]
    DIRECTION OUTPUT ;
    USE SIGNAL ;
    ANTENNADIFFAREA 0.336 LAYER met2  ;
    ANTENNAPARTIALMETALAREA 4.0627 LAYER met2  ;
    ANTENNAPARTIALMETALSIDEAREA 20.2055 LAYER met2  ;
    PORT
      LAYER met2 ;
        RECT 1651.100000 0.000000 1651.240000 0.485000 ;
    END
  END la_data_out[59]
  PIN la_data_out[58]
    DIRECTION OUTPUT ;
    USE SIGNAL ;
    ANTENNADIFFAREA 0.336 LAYER met2  ;
    ANTENNAPARTIALMETALAREA 4.0627 LAYER met2  ;
    ANTENNAPARTIALMETALSIDEAREA 20.2055 LAYER met2  ;
    PORT
      LAYER met2 ;
        RECT 1633.620000 0.000000 1633.760000 0.485000 ;
    END
  END la_data_out[58]
  PIN la_data_out[57]
    DIRECTION OUTPUT ;
    USE SIGNAL ;
    ANTENNADIFFAREA 0.336 LAYER met2  ;
    ANTENNAPARTIALMETALAREA 4.0627 LAYER met2  ;
    ANTENNAPARTIALMETALSIDEAREA 20.2055 LAYER met2  ;
    PORT
      LAYER met2 ;
        RECT 1616.140000 0.000000 1616.280000 0.485000 ;
    END
  END la_data_out[57]
  PIN la_data_out[56]
    DIRECTION OUTPUT ;
    USE SIGNAL ;
    ANTENNADIFFAREA 0.336 LAYER met2  ;
    ANTENNAPARTIALMETALAREA 4.0627 LAYER met2  ;
    ANTENNAPARTIALMETALSIDEAREA 20.2055 LAYER met2  ;
    PORT
      LAYER met2 ;
        RECT 1598.660000 0.000000 1598.800000 0.485000 ;
    END
  END la_data_out[56]
  PIN la_data_out[55]
    DIRECTION OUTPUT ;
    USE SIGNAL ;
    ANTENNADIFFAREA 0.336 LAYER met2  ;
    ANTENNAPARTIALMETALAREA 4.0627 LAYER met2  ;
    ANTENNAPARTIALMETALSIDEAREA 20.2055 LAYER met2  ;
    PORT
      LAYER met2 ;
        RECT 1581.180000 0.000000 1581.320000 0.485000 ;
    END
  END la_data_out[55]
  PIN la_data_out[54]
    DIRECTION OUTPUT ;
    USE SIGNAL ;
    ANTENNADIFFAREA 0.336 LAYER met2  ;
    ANTENNAPARTIALMETALAREA 4.0627 LAYER met2  ;
    ANTENNAPARTIALMETALSIDEAREA 20.2055 LAYER met2  ;
    PORT
      LAYER met2 ;
        RECT 1563.700000 0.000000 1563.840000 0.485000 ;
    END
  END la_data_out[54]
  PIN la_data_out[53]
    DIRECTION OUTPUT ;
    USE SIGNAL ;
    ANTENNADIFFAREA 0.336 LAYER met2  ;
    ANTENNAPARTIALMETALAREA 4.0627 LAYER met2  ;
    ANTENNAPARTIALMETALSIDEAREA 20.2055 LAYER met2  ;
    PORT
      LAYER met2 ;
        RECT 1546.220000 0.000000 1546.360000 0.485000 ;
    END
  END la_data_out[53]
  PIN la_data_out[52]
    DIRECTION OUTPUT ;
    USE SIGNAL ;
    ANTENNADIFFAREA 0.336 LAYER met2  ;
    ANTENNAPARTIALMETALAREA 4.4435 LAYER met2  ;
    ANTENNAPARTIALMETALSIDEAREA 22.1095 LAYER met2  ;
    PORT
      LAYER met2 ;
        RECT 1528.740000 0.000000 1528.880000 0.485000 ;
    END
  END la_data_out[52]
  PIN la_data_out[51]
    DIRECTION OUTPUT ;
    USE SIGNAL ;
    ANTENNADIFFAREA 0.336 LAYER met2  ;
    ANTENNAPARTIALMETALAREA 4.4435 LAYER met2  ;
    ANTENNAPARTIALMETALSIDEAREA 22.1095 LAYER met2  ;
    PORT
      LAYER met2 ;
        RECT 1511.260000 0.000000 1511.400000 0.485000 ;
    END
  END la_data_out[51]
  PIN la_data_out[50]
    DIRECTION OUTPUT ;
    USE SIGNAL ;
    ANTENNADIFFAREA 0.336 LAYER met2  ;
    ANTENNAPARTIALMETALAREA 4.0627 LAYER met2  ;
    ANTENNAPARTIALMETALSIDEAREA 20.2055 LAYER met2  ;
    PORT
      LAYER met2 ;
        RECT 1493.780000 0.000000 1493.920000 0.485000 ;
    END
  END la_data_out[50]
  PIN la_data_out[49]
    DIRECTION OUTPUT ;
    USE SIGNAL ;
    ANTENNADIFFAREA 0.336 LAYER met2  ;
    ANTENNAPARTIALMETALAREA 4.4435 LAYER met2  ;
    ANTENNAPARTIALMETALSIDEAREA 22.1095 LAYER met2  ;
    PORT
      LAYER met2 ;
        RECT 1476.760000 0.000000 1476.900000 0.485000 ;
    END
  END la_data_out[49]
  PIN la_data_out[48]
    DIRECTION OUTPUT ;
    USE SIGNAL ;
    ANTENNADIFFAREA 0.336 LAYER met2  ;
    ANTENNAPARTIALMETALAREA 4.4435 LAYER met2  ;
    ANTENNAPARTIALMETALSIDEAREA 22.1095 LAYER met2  ;
    PORT
      LAYER met2 ;
        RECT 1459.280000 0.000000 1459.420000 0.485000 ;
    END
  END la_data_out[48]
  PIN la_data_out[47]
    DIRECTION OUTPUT ;
    USE SIGNAL ;
    ANTENNADIFFAREA 0.336 LAYER met2  ;
    ANTENNAPARTIALMETALAREA 4.4435 LAYER met2  ;
    ANTENNAPARTIALMETALSIDEAREA 22.1095 LAYER met2  ;
    PORT
      LAYER met2 ;
        RECT 1441.800000 0.000000 1441.940000 0.485000 ;
    END
  END la_data_out[47]
  PIN la_data_out[46]
    DIRECTION OUTPUT ;
    USE SIGNAL ;
    ANTENNADIFFAREA 0.336 LAYER met2  ;
    ANTENNAPARTIALMETALAREA 4.4435 LAYER met2  ;
    ANTENNAPARTIALMETALSIDEAREA 22.1095 LAYER met2  ;
    PORT
      LAYER met2 ;
        RECT 1424.320000 0.000000 1424.460000 0.485000 ;
    END
  END la_data_out[46]
  PIN la_data_out[45]
    DIRECTION OUTPUT ;
    USE SIGNAL ;
    ANTENNADIFFAREA 0.336 LAYER met2  ;
    ANTENNAPARTIALMETALAREA 4.0627 LAYER met2  ;
    ANTENNAPARTIALMETALSIDEAREA 20.2055 LAYER met2  ;
    PORT
      LAYER met2 ;
        RECT 1406.840000 0.000000 1406.980000 0.485000 ;
    END
  END la_data_out[45]
  PIN la_data_out[44]
    DIRECTION OUTPUT ;
    USE SIGNAL ;
    ANTENNADIFFAREA 0.336 LAYER met2  ;
    ANTENNAPARTIALMETALAREA 4.0627 LAYER met2  ;
    ANTENNAPARTIALMETALSIDEAREA 20.2055 LAYER met2  ;
    PORT
      LAYER met2 ;
        RECT 1389.360000 0.000000 1389.500000 0.485000 ;
    END
  END la_data_out[44]
  PIN la_data_out[43]
    DIRECTION OUTPUT ;
    USE SIGNAL ;
    ANTENNADIFFAREA 0.336 LAYER met2  ;
    ANTENNAPARTIALMETALAREA 4.0627 LAYER met2  ;
    ANTENNAPARTIALMETALSIDEAREA 20.2055 LAYER met2  ;
    PORT
      LAYER met2 ;
        RECT 1371.880000 0.000000 1372.020000 0.485000 ;
    END
  END la_data_out[43]
  PIN la_data_out[42]
    DIRECTION OUTPUT ;
    USE SIGNAL ;
    ANTENNADIFFAREA 0.336 LAYER met2  ;
    ANTENNAPARTIALMETALAREA 4.0627 LAYER met2  ;
    ANTENNAPARTIALMETALSIDEAREA 20.2055 LAYER met2  ;
    PORT
      LAYER met2 ;
        RECT 1354.400000 0.000000 1354.540000 0.485000 ;
    END
  END la_data_out[42]
  PIN la_data_out[41]
    DIRECTION OUTPUT ;
    USE SIGNAL ;
    ANTENNADIFFAREA 0.336 LAYER met2  ;
    ANTENNAPARTIALMETALAREA 4.0627 LAYER met2  ;
    ANTENNAPARTIALMETALSIDEAREA 20.2055 LAYER met2  ;
    PORT
      LAYER met2 ;
        RECT 1336.920000 0.000000 1337.060000 0.485000 ;
    END
  END la_data_out[41]
  PIN la_data_out[40]
    DIRECTION OUTPUT ;
    USE SIGNAL ;
    ANTENNADIFFAREA 0.336 LAYER met2  ;
    ANTENNAPARTIALMETALAREA 4.0627 LAYER met2  ;
    ANTENNAPARTIALMETALSIDEAREA 20.2055 LAYER met2  ;
    PORT
      LAYER met2 ;
        RECT 1319.440000 0.000000 1319.580000 0.485000 ;
    END
  END la_data_out[40]
  PIN la_data_out[39]
    DIRECTION OUTPUT ;
    USE SIGNAL ;
    ANTENNADIFFAREA 0.336 LAYER met2  ;
    ANTENNAPARTIALMETALAREA 4.0627 LAYER met2  ;
    ANTENNAPARTIALMETALSIDEAREA 20.2055 LAYER met2  ;
    PORT
      LAYER met2 ;
        RECT 1302.420000 0.000000 1302.560000 0.485000 ;
    END
  END la_data_out[39]
  PIN la_data_out[38]
    DIRECTION OUTPUT ;
    USE SIGNAL ;
    ANTENNADIFFAREA 0.336 LAYER met2  ;
    ANTENNAPARTIALMETALAREA 4.0627 LAYER met2  ;
    ANTENNAPARTIALMETALSIDEAREA 20.2055 LAYER met2  ;
    PORT
      LAYER met2 ;
        RECT 1284.940000 0.000000 1285.080000 0.485000 ;
    END
  END la_data_out[38]
  PIN la_data_out[37]
    DIRECTION OUTPUT ;
    USE SIGNAL ;
    ANTENNADIFFAREA 0.336 LAYER met2  ;
    ANTENNAPARTIALMETALAREA 4.0627 LAYER met2  ;
    ANTENNAPARTIALMETALSIDEAREA 20.2055 LAYER met2  ;
    PORT
      LAYER met2 ;
        RECT 1267.460000 0.000000 1267.600000 0.485000 ;
    END
  END la_data_out[37]
  PIN la_data_out[36]
    DIRECTION OUTPUT ;
    USE SIGNAL ;
    ANTENNADIFFAREA 0.336 LAYER met2  ;
    ANTENNAPARTIALMETALAREA 4.0627 LAYER met2  ;
    ANTENNAPARTIALMETALSIDEAREA 20.2055 LAYER met2  ;
    PORT
      LAYER met2 ;
        RECT 1249.980000 0.000000 1250.120000 0.485000 ;
    END
  END la_data_out[36]
  PIN la_data_out[35]
    DIRECTION OUTPUT ;
    USE SIGNAL ;
    ANTENNADIFFAREA 0.336 LAYER met2  ;
    ANTENNAPARTIALMETALAREA 4.0627 LAYER met2  ;
    ANTENNAPARTIALMETALSIDEAREA 20.2055 LAYER met2  ;
    PORT
      LAYER met2 ;
        RECT 1232.500000 0.000000 1232.640000 0.485000 ;
    END
  END la_data_out[35]
  PIN la_data_out[34]
    DIRECTION OUTPUT ;
    USE SIGNAL ;
    ANTENNADIFFAREA 0.336 LAYER met2  ;
    ANTENNAPARTIALMETALAREA 4.0627 LAYER met2  ;
    ANTENNAPARTIALMETALSIDEAREA 20.2055 LAYER met2  ;
    PORT
      LAYER met2 ;
        RECT 1215.020000 0.000000 1215.160000 0.485000 ;
    END
  END la_data_out[34]
  PIN la_data_out[33]
    DIRECTION OUTPUT ;
    USE SIGNAL ;
    ANTENNADIFFAREA 0.336 LAYER met2  ;
    ANTENNAPARTIALMETALAREA 4.0627 LAYER met2  ;
    ANTENNAPARTIALMETALSIDEAREA 20.2055 LAYER met2  ;
    PORT
      LAYER met2 ;
        RECT 1197.540000 0.000000 1197.680000 0.485000 ;
    END
  END la_data_out[33]
  PIN la_data_out[32]
    DIRECTION OUTPUT ;
    USE SIGNAL ;
    ANTENNADIFFAREA 0.336 LAYER met2  ;
    ANTENNAPARTIALMETALAREA 4.0627 LAYER met2  ;
    ANTENNAPARTIALMETALSIDEAREA 20.2055 LAYER met2  ;
    PORT
      LAYER met2 ;
        RECT 1180.060000 0.000000 1180.200000 0.485000 ;
    END
  END la_data_out[32]
  PIN la_data_out[31]
    DIRECTION OUTPUT ;
    USE SIGNAL ;
    ANTENNADIFFAREA 0.336 LAYER met2  ;
    ANTENNAPARTIALMETALAREA 4.0627 LAYER met2  ;
    ANTENNAPARTIALMETALSIDEAREA 20.2055 LAYER met2  ;
    PORT
      LAYER met2 ;
        RECT 1162.580000 0.000000 1162.720000 0.485000 ;
    END
  END la_data_out[31]
  PIN la_data_out[30]
    DIRECTION OUTPUT ;
    USE SIGNAL ;
    ANTENNADIFFAREA 0.336 LAYER met2  ;
    ANTENNAPARTIALMETALAREA 4.0627 LAYER met2  ;
    ANTENNAPARTIALMETALSIDEAREA 20.2055 LAYER met2  ;
    PORT
      LAYER met2 ;
        RECT 1145.100000 0.000000 1145.240000 0.485000 ;
    END
  END la_data_out[30]
  PIN la_data_out[29]
    DIRECTION OUTPUT ;
    USE SIGNAL ;
    ANTENNADIFFAREA 0.336 LAYER met2  ;
    ANTENNAPARTIALMETALAREA 4.0627 LAYER met2  ;
    ANTENNAPARTIALMETALSIDEAREA 20.2055 LAYER met2  ;
    PORT
      LAYER met2 ;
        RECT 1128.080000 0.000000 1128.220000 0.485000 ;
    END
  END la_data_out[29]
  PIN la_data_out[28]
    DIRECTION OUTPUT ;
    USE SIGNAL ;
    ANTENNADIFFAREA 0.336 LAYER met2  ;
    ANTENNAPARTIALMETALAREA 4.0627 LAYER met2  ;
    ANTENNAPARTIALMETALSIDEAREA 20.2055 LAYER met2  ;
    PORT
      LAYER met2 ;
        RECT 1110.600000 0.000000 1110.740000 0.485000 ;
    END
  END la_data_out[28]
  PIN la_data_out[27]
    DIRECTION OUTPUT ;
    USE SIGNAL ;
    ANTENNADIFFAREA 0.336 LAYER met2  ;
    ANTENNAPARTIALMETALAREA 4.0627 LAYER met2  ;
    ANTENNAPARTIALMETALSIDEAREA 20.2055 LAYER met2  ;
    PORT
      LAYER met2 ;
        RECT 1093.120000 0.000000 1093.260000 0.485000 ;
    END
  END la_data_out[27]
  PIN la_data_out[26]
    DIRECTION OUTPUT ;
    USE SIGNAL ;
    ANTENNADIFFAREA 0.336 LAYER met2  ;
    ANTENNAPARTIALMETALAREA 4.0627 LAYER met2  ;
    ANTENNAPARTIALMETALSIDEAREA 20.2055 LAYER met2  ;
    PORT
      LAYER met2 ;
        RECT 1075.640000 0.000000 1075.780000 0.485000 ;
    END
  END la_data_out[26]
  PIN la_data_out[25]
    DIRECTION OUTPUT ;
    USE SIGNAL ;
    ANTENNADIFFAREA 0.336 LAYER met2  ;
    ANTENNAPARTIALMETALAREA 4.0627 LAYER met2  ;
    ANTENNAPARTIALMETALSIDEAREA 20.2055 LAYER met2  ;
    PORT
      LAYER met2 ;
        RECT 1058.160000 0.000000 1058.300000 0.485000 ;
    END
  END la_data_out[25]
  PIN la_data_out[24]
    DIRECTION OUTPUT ;
    USE SIGNAL ;
    ANTENNADIFFAREA 0.336 LAYER met2  ;
    ANTENNAPARTIALMETALAREA 4.0627 LAYER met2  ;
    ANTENNAPARTIALMETALSIDEAREA 20.2055 LAYER met2  ;
    PORT
      LAYER met2 ;
        RECT 1040.680000 0.000000 1040.820000 0.485000 ;
    END
  END la_data_out[24]
  PIN la_data_out[23]
    DIRECTION OUTPUT ;
    USE SIGNAL ;
    ANTENNADIFFAREA 0.336 LAYER met2  ;
    ANTENNAPARTIALMETALAREA 4.1271 LAYER met2  ;
    ANTENNAPARTIALMETALSIDEAREA 20.5275 LAYER met2  ;
    PORT
      LAYER met2 ;
        RECT 1023.200000 0.000000 1023.340000 0.485000 ;
    END
  END la_data_out[23]
  PIN la_data_out[22]
    DIRECTION OUTPUT ;
    USE SIGNAL ;
    ANTENNADIFFAREA 0.336 LAYER met2  ;
    ANTENNAPARTIALMETALAREA 4.0627 LAYER met2  ;
    ANTENNAPARTIALMETALSIDEAREA 20.2055 LAYER met2  ;
    PORT
      LAYER met2 ;
        RECT 1005.720000 0.000000 1005.860000 0.485000 ;
    END
  END la_data_out[22]
  PIN la_data_out[21]
    DIRECTION OUTPUT ;
    USE SIGNAL ;
    ANTENNADIFFAREA 0.336 LAYER met2  ;
    ANTENNAPARTIALMETALAREA 4.0627 LAYER met2  ;
    ANTENNAPARTIALMETALSIDEAREA 20.2055 LAYER met2  ;
    PORT
      LAYER met2 ;
        RECT 988.240000 0.000000 988.380000 0.485000 ;
    END
  END la_data_out[21]
  PIN la_data_out[20]
    DIRECTION OUTPUT ;
    USE SIGNAL ;
    ANTENNADIFFAREA 0.336 LAYER met2  ;
    ANTENNAPARTIALMETALAREA 4.0627 LAYER met2  ;
    ANTENNAPARTIALMETALSIDEAREA 20.2055 LAYER met2  ;
    PORT
      LAYER met2 ;
        RECT 970.760000 0.000000 970.900000 0.485000 ;
    END
  END la_data_out[20]
  PIN la_data_out[19]
    DIRECTION OUTPUT ;
    USE SIGNAL ;
    ANTENNADIFFAREA 0.336 LAYER met2  ;
    ANTENNAPARTIALMETALAREA 4.0627 LAYER met2  ;
    ANTENNAPARTIALMETALSIDEAREA 20.2055 LAYER met2  ;
    PORT
      LAYER met2 ;
        RECT 953.740000 0.000000 953.880000 0.485000 ;
    END
  END la_data_out[19]
  PIN la_data_out[18]
    DIRECTION OUTPUT ;
    USE SIGNAL ;
    ANTENNADIFFAREA 0.336 LAYER met2  ;
    ANTENNAPARTIALMETALAREA 4.0627 LAYER met2  ;
    ANTENNAPARTIALMETALSIDEAREA 20.2055 LAYER met2  ;
    PORT
      LAYER met2 ;
        RECT 936.260000 0.000000 936.400000 0.485000 ;
    END
  END la_data_out[18]
  PIN la_data_out[17]
    DIRECTION OUTPUT ;
    USE SIGNAL ;
    ANTENNADIFFAREA 0.336 LAYER met2  ;
    ANTENNAPARTIALMETALAREA 4.0627 LAYER met2  ;
    ANTENNAPARTIALMETALSIDEAREA 20.2055 LAYER met2  ;
    PORT
      LAYER met2 ;
        RECT 918.780000 0.000000 918.920000 0.485000 ;
    END
  END la_data_out[17]
  PIN la_data_out[16]
    DIRECTION OUTPUT ;
    USE SIGNAL ;
    ANTENNADIFFAREA 0.336 LAYER met2  ;
    ANTENNAPARTIALMETALAREA 4.4435 LAYER met2  ;
    ANTENNAPARTIALMETALSIDEAREA 22.1095 LAYER met2  ;
    PORT
      LAYER met2 ;
        RECT 901.300000 0.000000 901.440000 0.485000 ;
    END
  END la_data_out[16]
  PIN la_data_out[15]
    DIRECTION OUTPUT ;
    USE SIGNAL ;
    ANTENNADIFFAREA 0.336 LAYER met2  ;
    ANTENNAPARTIALMETALAREA 4.5079 LAYER met2  ;
    ANTENNAPARTIALMETALSIDEAREA 22.4315 LAYER met2  ;
    PORT
      LAYER met2 ;
        RECT 883.820000 0.000000 883.960000 0.485000 ;
    END
  END la_data_out[15]
  PIN la_data_out[14]
    DIRECTION OUTPUT ;
    USE SIGNAL ;
    ANTENNADIFFAREA 0.336 LAYER met2  ;
    ANTENNAPARTIALMETALAREA 4.4435 LAYER met2  ;
    ANTENNAPARTIALMETALSIDEAREA 22.1095 LAYER met2  ;
    PORT
      LAYER met2 ;
        RECT 866.340000 0.000000 866.480000 0.485000 ;
    END
  END la_data_out[14]
  PIN la_data_out[13]
    DIRECTION OUTPUT ;
    USE SIGNAL ;
    ANTENNADIFFAREA 0.336 LAYER met2  ;
    ANTENNAPARTIALMETALAREA 4.4435 LAYER met2  ;
    ANTENNAPARTIALMETALSIDEAREA 22.1095 LAYER met2  ;
    PORT
      LAYER met2 ;
        RECT 848.860000 0.000000 849.000000 0.485000 ;
    END
  END la_data_out[13]
  PIN la_data_out[12]
    DIRECTION OUTPUT ;
    USE SIGNAL ;
    ANTENNADIFFAREA 0.336 LAYER met2  ;
    ANTENNAPARTIALMETALAREA 4.4435 LAYER met2  ;
    ANTENNAPARTIALMETALSIDEAREA 22.1095 LAYER met2  ;
    PORT
      LAYER met2 ;
        RECT 831.380000 0.000000 831.520000 0.485000 ;
    END
  END la_data_out[12]
  PIN la_data_out[11]
    DIRECTION OUTPUT ;
    USE SIGNAL ;
    ANTENNADIFFAREA 0.336 LAYER met2  ;
    ANTENNAPARTIALMETALAREA 4.4435 LAYER met2  ;
    ANTENNAPARTIALMETALSIDEAREA 22.1095 LAYER met2  ;
    PORT
      LAYER met2 ;
        RECT 813.900000 0.000000 814.040000 0.485000 ;
    END
  END la_data_out[11]
  PIN la_data_out[10]
    DIRECTION OUTPUT ;
    USE SIGNAL ;
    ANTENNADIFFAREA 0.336 LAYER met2  ;
    ANTENNAPARTIALMETALAREA 4.4435 LAYER met2  ;
    ANTENNAPARTIALMETALSIDEAREA 22.1095 LAYER met2  ;
    PORT
      LAYER met2 ;
        RECT 796.420000 0.000000 796.560000 0.485000 ;
    END
  END la_data_out[10]
  PIN la_data_out[9]
    DIRECTION OUTPUT ;
    USE SIGNAL ;
    ANTENNADIFFAREA 0.336 LAYER met2  ;
    ANTENNAPARTIALMETALAREA 4.0627 LAYER met2  ;
    ANTENNAPARTIALMETALSIDEAREA 20.2055 LAYER met2  ;
    PORT
      LAYER met2 ;
        RECT 778.940000 0.000000 779.080000 0.485000 ;
    END
  END la_data_out[9]
  PIN la_data_out[8]
    DIRECTION OUTPUT ;
    USE SIGNAL ;
    ANTENNADIFFAREA 0.336 LAYER met2  ;
    ANTENNAPARTIALMETALAREA 4.0627 LAYER met2  ;
    ANTENNAPARTIALMETALSIDEAREA 20.2055 LAYER met2  ;
    PORT
      LAYER met2 ;
        RECT 761.920000 0.000000 762.060000 0.485000 ;
    END
  END la_data_out[8]
  PIN la_data_out[7]
    DIRECTION OUTPUT ;
    USE SIGNAL ;
    ANTENNADIFFAREA 0.336 LAYER met2  ;
    ANTENNAPARTIALMETALAREA 4.0627 LAYER met2  ;
    ANTENNAPARTIALMETALSIDEAREA 20.2055 LAYER met2  ;
    PORT
      LAYER met2 ;
        RECT 744.440000 0.000000 744.580000 0.485000 ;
    END
  END la_data_out[7]
  PIN la_data_out[6]
    DIRECTION OUTPUT ;
    USE SIGNAL ;
    ANTENNADIFFAREA 0.336 LAYER met2  ;
    ANTENNAPARTIALMETALAREA 4.0627 LAYER met2  ;
    ANTENNAPARTIALMETALSIDEAREA 20.2055 LAYER met2  ;
    PORT
      LAYER met2 ;
        RECT 726.960000 0.000000 727.100000 0.485000 ;
    END
  END la_data_out[6]
  PIN la_data_out[5]
    DIRECTION OUTPUT ;
    USE SIGNAL ;
    ANTENNADIFFAREA 0.336 LAYER met2  ;
    ANTENNAPARTIALMETALAREA 4.0627 LAYER met2  ;
    ANTENNAPARTIALMETALSIDEAREA 20.2055 LAYER met2  ;
    PORT
      LAYER met2 ;
        RECT 709.480000 0.000000 709.620000 0.485000 ;
    END
  END la_data_out[5]
  PIN la_data_out[4]
    DIRECTION OUTPUT ;
    USE SIGNAL ;
    ANTENNADIFFAREA 0.336 LAYER met2  ;
    ANTENNAPARTIALMETALAREA 4.0627 LAYER met2  ;
    ANTENNAPARTIALMETALSIDEAREA 20.2055 LAYER met2  ;
    PORT
      LAYER met2 ;
        RECT 692.000000 0.000000 692.140000 0.485000 ;
    END
  END la_data_out[4]
  PIN la_data_out[3]
    DIRECTION OUTPUT ;
    USE SIGNAL ;
    ANTENNADIFFAREA 0.336 LAYER met2  ;
    ANTENNAPARTIALMETALAREA 4.0627 LAYER met2  ;
    ANTENNAPARTIALMETALSIDEAREA 20.2055 LAYER met2  ;
    PORT
      LAYER met2 ;
        RECT 674.520000 0.000000 674.660000 0.485000 ;
    END
  END la_data_out[3]
  PIN la_data_out[2]
    DIRECTION OUTPUT ;
    USE SIGNAL ;
    ANTENNADIFFAREA 0.336 LAYER met2  ;
    ANTENNAPARTIALMETALAREA 4.0627 LAYER met2  ;
    ANTENNAPARTIALMETALSIDEAREA 20.2055 LAYER met2  ;
    PORT
      LAYER met2 ;
        RECT 657.040000 0.000000 657.180000 0.485000 ;
    END
  END la_data_out[2]
  PIN la_data_out[1]
    DIRECTION OUTPUT ;
    USE SIGNAL ;
    ANTENNADIFFAREA 0.336 LAYER met2  ;
    ANTENNAPARTIALMETALAREA 4.0627 LAYER met2  ;
    ANTENNAPARTIALMETALSIDEAREA 20.2055 LAYER met2  ;
    PORT
      LAYER met2 ;
        RECT 639.560000 0.000000 639.700000 0.485000 ;
    END
  END la_data_out[1]
  PIN la_data_out[0]
    DIRECTION OUTPUT ;
    USE SIGNAL ;
    ANTENNADIFFAREA 0.336 LAYER met2  ;
    ANTENNAPARTIALMETALAREA 4.0627 LAYER met2  ;
    ANTENNAPARTIALMETALSIDEAREA 20.2055 LAYER met2  ;
    PORT
      LAYER met2 ;
        RECT 622.080000 0.000000 622.220000 0.485000 ;
    END
  END la_data_out[0]
  PIN la_oenb[127]
    DIRECTION INPUT ;
    USE SIGNAL ;
    PORT
      LAYER met2 ;
        RECT 2842.500000 0.000000 2842.640000 0.485000 ;
    END
  END la_oenb[127]
  PIN la_oenb[126]
    DIRECTION INPUT ;
    USE SIGNAL ;
    PORT
      LAYER met2 ;
        RECT 2825.020000 0.000000 2825.160000 0.485000 ;
    END
  END la_oenb[126]
  PIN la_oenb[125]
    DIRECTION INPUT ;
    USE SIGNAL ;
    PORT
      LAYER met2 ;
        RECT 2807.540000 0.000000 2807.680000 0.485000 ;
    END
  END la_oenb[125]
  PIN la_oenb[124]
    DIRECTION INPUT ;
    USE SIGNAL ;
    PORT
      LAYER met2 ;
        RECT 2790.060000 0.000000 2790.200000 0.485000 ;
    END
  END la_oenb[124]
  PIN la_oenb[123]
    DIRECTION INPUT ;
    USE SIGNAL ;
    PORT
      LAYER met2 ;
        RECT 2772.580000 0.000000 2772.720000 0.485000 ;
    END
  END la_oenb[123]
  PIN la_oenb[122]
    DIRECTION INPUT ;
    USE SIGNAL ;
    PORT
      LAYER met2 ;
        RECT 2755.100000 0.000000 2755.240000 0.485000 ;
    END
  END la_oenb[122]
  PIN la_oenb[121]
    DIRECTION INPUT ;
    USE SIGNAL ;
    PORT
      LAYER met2 ;
        RECT 2737.620000 0.000000 2737.760000 0.485000 ;
    END
  END la_oenb[121]
  PIN la_oenb[120]
    DIRECTION INPUT ;
    USE SIGNAL ;
    PORT
      LAYER met2 ;
        RECT 2720.140000 0.000000 2720.280000 0.485000 ;
    END
  END la_oenb[120]
  PIN la_oenb[119]
    DIRECTION INPUT ;
    USE SIGNAL ;
    PORT
      LAYER met2 ;
        RECT 2702.660000 0.000000 2702.800000 0.485000 ;
    END
  END la_oenb[119]
  PIN la_oenb[118]
    DIRECTION INPUT ;
    USE SIGNAL ;
    PORT
      LAYER met2 ;
        RECT 2685.180000 0.000000 2685.320000 0.485000 ;
    END
  END la_oenb[118]
  PIN la_oenb[117]
    DIRECTION INPUT ;
    USE SIGNAL ;
    PORT
      LAYER met2 ;
        RECT 2668.160000 0.000000 2668.300000 0.485000 ;
    END
  END la_oenb[117]
  PIN la_oenb[116]
    DIRECTION INPUT ;
    USE SIGNAL ;
    PORT
      LAYER met2 ;
        RECT 2650.680000 0.000000 2650.820000 0.485000 ;
    END
  END la_oenb[116]
  PIN la_oenb[115]
    DIRECTION INPUT ;
    USE SIGNAL ;
    PORT
      LAYER met2 ;
        RECT 2633.200000 0.000000 2633.340000 0.485000 ;
    END
  END la_oenb[115]
  PIN la_oenb[114]
    DIRECTION INPUT ;
    USE SIGNAL ;
    PORT
      LAYER met2 ;
        RECT 2615.720000 0.000000 2615.860000 0.485000 ;
    END
  END la_oenb[114]
  PIN la_oenb[113]
    DIRECTION INPUT ;
    USE SIGNAL ;
    PORT
      LAYER met2 ;
        RECT 2598.240000 0.000000 2598.380000 0.485000 ;
    END
  END la_oenb[113]
  PIN la_oenb[112]
    DIRECTION INPUT ;
    USE SIGNAL ;
    PORT
      LAYER met2 ;
        RECT 2580.760000 0.000000 2580.900000 0.485000 ;
    END
  END la_oenb[112]
  PIN la_oenb[111]
    DIRECTION INPUT ;
    USE SIGNAL ;
    PORT
      LAYER met2 ;
        RECT 2563.280000 0.000000 2563.420000 0.485000 ;
    END
  END la_oenb[111]
  PIN la_oenb[110]
    DIRECTION INPUT ;
    USE SIGNAL ;
    PORT
      LAYER met2 ;
        RECT 2545.800000 0.000000 2545.940000 0.485000 ;
    END
  END la_oenb[110]
  PIN la_oenb[109]
    DIRECTION INPUT ;
    USE SIGNAL ;
    PORT
      LAYER met2 ;
        RECT 2528.320000 0.000000 2528.460000 0.485000 ;
    END
  END la_oenb[109]
  PIN la_oenb[108]
    DIRECTION INPUT ;
    USE SIGNAL ;
    PORT
      LAYER met2 ;
        RECT 2510.840000 0.000000 2510.980000 0.485000 ;
    END
  END la_oenb[108]
  PIN la_oenb[107]
    DIRECTION INPUT ;
    USE SIGNAL ;
    PORT
      LAYER met2 ;
        RECT 2493.820000 0.000000 2493.960000 0.485000 ;
    END
  END la_oenb[107]
  PIN la_oenb[106]
    DIRECTION INPUT ;
    USE SIGNAL ;
    PORT
      LAYER met2 ;
        RECT 2476.340000 0.000000 2476.480000 0.485000 ;
    END
  END la_oenb[106]
  PIN la_oenb[105]
    DIRECTION INPUT ;
    USE SIGNAL ;
    PORT
      LAYER met2 ;
        RECT 2458.860000 0.000000 2459.000000 0.485000 ;
    END
  END la_oenb[105]
  PIN la_oenb[104]
    DIRECTION INPUT ;
    USE SIGNAL ;
    PORT
      LAYER met2 ;
        RECT 2441.380000 0.000000 2441.520000 0.485000 ;
    END
  END la_oenb[104]
  PIN la_oenb[103]
    DIRECTION INPUT ;
    USE SIGNAL ;
    PORT
      LAYER met2 ;
        RECT 2423.900000 0.000000 2424.040000 0.485000 ;
    END
  END la_oenb[103]
  PIN la_oenb[102]
    DIRECTION INPUT ;
    USE SIGNAL ;
    PORT
      LAYER met2 ;
        RECT 2406.420000 0.000000 2406.560000 0.485000 ;
    END
  END la_oenb[102]
  PIN la_oenb[101]
    DIRECTION INPUT ;
    USE SIGNAL ;
    PORT
      LAYER met2 ;
        RECT 2388.940000 0.000000 2389.080000 0.485000 ;
    END
  END la_oenb[101]
  PIN la_oenb[100]
    DIRECTION INPUT ;
    USE SIGNAL ;
    PORT
      LAYER met2 ;
        RECT 2371.460000 0.000000 2371.600000 0.485000 ;
    END
  END la_oenb[100]
  PIN la_oenb[99]
    DIRECTION INPUT ;
    USE SIGNAL ;
    PORT
      LAYER met2 ;
        RECT 2353.980000 0.000000 2354.120000 0.485000 ;
    END
  END la_oenb[99]
  PIN la_oenb[98]
    DIRECTION INPUT ;
    USE SIGNAL ;
    PORT
      LAYER met2 ;
        RECT 2336.500000 0.000000 2336.640000 0.485000 ;
    END
  END la_oenb[98]
  PIN la_oenb[97]
    DIRECTION INPUT ;
    USE SIGNAL ;
    PORT
      LAYER met2 ;
        RECT 2319.480000 0.000000 2319.620000 0.485000 ;
    END
  END la_oenb[97]
  PIN la_oenb[96]
    DIRECTION INPUT ;
    USE SIGNAL ;
    PORT
      LAYER met2 ;
        RECT 2302.000000 0.000000 2302.140000 0.485000 ;
    END
  END la_oenb[96]
  PIN la_oenb[95]
    DIRECTION INPUT ;
    USE SIGNAL ;
    PORT
      LAYER met2 ;
        RECT 2284.520000 0.000000 2284.660000 0.485000 ;
    END
  END la_oenb[95]
  PIN la_oenb[94]
    DIRECTION INPUT ;
    USE SIGNAL ;
    PORT
      LAYER met2 ;
        RECT 2267.040000 0.000000 2267.180000 0.485000 ;
    END
  END la_oenb[94]
  PIN la_oenb[93]
    DIRECTION INPUT ;
    USE SIGNAL ;
    PORT
      LAYER met2 ;
        RECT 2249.560000 0.000000 2249.700000 0.485000 ;
    END
  END la_oenb[93]
  PIN la_oenb[92]
    DIRECTION INPUT ;
    USE SIGNAL ;
    PORT
      LAYER met2 ;
        RECT 2232.080000 0.000000 2232.220000 0.485000 ;
    END
  END la_oenb[92]
  PIN la_oenb[91]
    DIRECTION INPUT ;
    USE SIGNAL ;
    PORT
      LAYER met2 ;
        RECT 2214.600000 0.000000 2214.740000 0.485000 ;
    END
  END la_oenb[91]
  PIN la_oenb[90]
    DIRECTION INPUT ;
    USE SIGNAL ;
    PORT
      LAYER met2 ;
        RECT 2197.120000 0.000000 2197.260000 0.485000 ;
    END
  END la_oenb[90]
  PIN la_oenb[89]
    DIRECTION INPUT ;
    USE SIGNAL ;
    PORT
      LAYER met2 ;
        RECT 2179.640000 0.000000 2179.780000 0.485000 ;
    END
  END la_oenb[89]
  PIN la_oenb[88]
    DIRECTION INPUT ;
    USE SIGNAL ;
    PORT
      LAYER met2 ;
        RECT 2162.160000 0.000000 2162.300000 0.485000 ;
    END
  END la_oenb[88]
  PIN la_oenb[87]
    DIRECTION INPUT ;
    USE SIGNAL ;
    PORT
      LAYER met2 ;
        RECT 2144.680000 0.000000 2144.820000 0.485000 ;
    END
  END la_oenb[87]
  PIN la_oenb[86]
    DIRECTION INPUT ;
    USE SIGNAL ;
    PORT
      LAYER met2 ;
        RECT 2127.660000 0.000000 2127.800000 0.485000 ;
    END
  END la_oenb[86]
  PIN la_oenb[85]
    DIRECTION INPUT ;
    USE SIGNAL ;
    PORT
      LAYER met2 ;
        RECT 2110.180000 0.000000 2110.320000 0.485000 ;
    END
  END la_oenb[85]
  PIN la_oenb[84]
    DIRECTION INPUT ;
    USE SIGNAL ;
    PORT
      LAYER met2 ;
        RECT 2092.700000 0.000000 2092.840000 0.485000 ;
    END
  END la_oenb[84]
  PIN la_oenb[83]
    DIRECTION INPUT ;
    USE SIGNAL ;
    PORT
      LAYER met2 ;
        RECT 2075.220000 0.000000 2075.360000 0.485000 ;
    END
  END la_oenb[83]
  PIN la_oenb[82]
    DIRECTION INPUT ;
    USE SIGNAL ;
    PORT
      LAYER met2 ;
        RECT 2057.740000 0.000000 2057.880000 0.485000 ;
    END
  END la_oenb[82]
  PIN la_oenb[81]
    DIRECTION INPUT ;
    USE SIGNAL ;
    PORT
      LAYER met2 ;
        RECT 2040.260000 0.000000 2040.400000 0.485000 ;
    END
  END la_oenb[81]
  PIN la_oenb[80]
    DIRECTION INPUT ;
    USE SIGNAL ;
    PORT
      LAYER met2 ;
        RECT 2022.780000 0.000000 2022.920000 0.485000 ;
    END
  END la_oenb[80]
  PIN la_oenb[79]
    DIRECTION INPUT ;
    USE SIGNAL ;
    PORT
      LAYER met2 ;
        RECT 2005.300000 0.000000 2005.440000 0.485000 ;
    END
  END la_oenb[79]
  PIN la_oenb[78]
    DIRECTION INPUT ;
    USE SIGNAL ;
    PORT
      LAYER met2 ;
        RECT 1987.820000 0.000000 1987.960000 0.485000 ;
    END
  END la_oenb[78]
  PIN la_oenb[77]
    DIRECTION INPUT ;
    USE SIGNAL ;
    PORT
      LAYER met2 ;
        RECT 1970.340000 0.000000 1970.480000 0.485000 ;
    END
  END la_oenb[77]
  PIN la_oenb[76]
    DIRECTION INPUT ;
    USE SIGNAL ;
    PORT
      LAYER met2 ;
        RECT 1953.320000 0.000000 1953.460000 0.485000 ;
    END
  END la_oenb[76]
  PIN la_oenb[75]
    DIRECTION INPUT ;
    USE SIGNAL ;
    PORT
      LAYER met2 ;
        RECT 1935.840000 0.000000 1935.980000 0.485000 ;
    END
  END la_oenb[75]
  PIN la_oenb[74]
    DIRECTION INPUT ;
    USE SIGNAL ;
    PORT
      LAYER met2 ;
        RECT 1918.360000 0.000000 1918.500000 0.485000 ;
    END
  END la_oenb[74]
  PIN la_oenb[73]
    DIRECTION INPUT ;
    USE SIGNAL ;
    PORT
      LAYER met2 ;
        RECT 1900.880000 0.000000 1901.020000 0.485000 ;
    END
  END la_oenb[73]
  PIN la_oenb[72]
    DIRECTION INPUT ;
    USE SIGNAL ;
    PORT
      LAYER met2 ;
        RECT 1883.400000 0.000000 1883.540000 0.485000 ;
    END
  END la_oenb[72]
  PIN la_oenb[71]
    DIRECTION INPUT ;
    USE SIGNAL ;
    PORT
      LAYER met2 ;
        RECT 1865.920000 0.000000 1866.060000 0.485000 ;
    END
  END la_oenb[71]
  PIN la_oenb[70]
    DIRECTION INPUT ;
    USE SIGNAL ;
    PORT
      LAYER met2 ;
        RECT 1848.440000 0.000000 1848.580000 0.485000 ;
    END
  END la_oenb[70]
  PIN la_oenb[69]
    DIRECTION INPUT ;
    USE SIGNAL ;
    PORT
      LAYER met2 ;
        RECT 1830.960000 0.000000 1831.100000 0.485000 ;
    END
  END la_oenb[69]
  PIN la_oenb[68]
    DIRECTION INPUT ;
    USE SIGNAL ;
    PORT
      LAYER met2 ;
        RECT 1813.480000 0.000000 1813.620000 0.485000 ;
    END
  END la_oenb[68]
  PIN la_oenb[67]
    DIRECTION INPUT ;
    USE SIGNAL ;
    PORT
      LAYER met2 ;
        RECT 1796.000000 0.000000 1796.140000 0.485000 ;
    END
  END la_oenb[67]
  PIN la_oenb[66]
    DIRECTION INPUT ;
    USE SIGNAL ;
    PORT
      LAYER met2 ;
        RECT 1778.980000 0.000000 1779.120000 0.485000 ;
    END
  END la_oenb[66]
  PIN la_oenb[65]
    DIRECTION INPUT ;
    USE SIGNAL ;
    PORT
      LAYER met2 ;
        RECT 1761.500000 0.000000 1761.640000 0.485000 ;
    END
  END la_oenb[65]
  PIN la_oenb[64]
    DIRECTION INPUT ;
    USE SIGNAL ;
    PORT
      LAYER met2 ;
        RECT 1744.020000 0.000000 1744.160000 0.485000 ;
    END
  END la_oenb[64]
  PIN la_oenb[63]
    DIRECTION INPUT ;
    USE SIGNAL ;
    PORT
      LAYER met2 ;
        RECT 1726.540000 0.000000 1726.680000 0.485000 ;
    END
  END la_oenb[63]
  PIN la_oenb[62]
    DIRECTION INPUT ;
    USE SIGNAL ;
    PORT
      LAYER met2 ;
        RECT 1709.060000 0.000000 1709.200000 0.485000 ;
    END
  END la_oenb[62]
  PIN la_oenb[61]
    DIRECTION INPUT ;
    USE SIGNAL ;
    PORT
      LAYER met2 ;
        RECT 1691.580000 0.000000 1691.720000 0.485000 ;
    END
  END la_oenb[61]
  PIN la_oenb[60]
    DIRECTION INPUT ;
    USE SIGNAL ;
    PORT
      LAYER met2 ;
        RECT 1674.100000 0.000000 1674.240000 0.485000 ;
    END
  END la_oenb[60]
  PIN la_oenb[59]
    DIRECTION INPUT ;
    USE SIGNAL ;
    PORT
      LAYER met2 ;
        RECT 1656.620000 0.000000 1656.760000 0.485000 ;
    END
  END la_oenb[59]
  PIN la_oenb[58]
    DIRECTION INPUT ;
    USE SIGNAL ;
    PORT
      LAYER met2 ;
        RECT 1639.140000 0.000000 1639.280000 0.485000 ;
    END
  END la_oenb[58]
  PIN la_oenb[57]
    DIRECTION INPUT ;
    USE SIGNAL ;
    PORT
      LAYER met2 ;
        RECT 1621.660000 0.000000 1621.800000 0.485000 ;
    END
  END la_oenb[57]
  PIN la_oenb[56]
    DIRECTION INPUT ;
    USE SIGNAL ;
    PORT
      LAYER met2 ;
        RECT 1604.640000 0.000000 1604.780000 0.485000 ;
    END
  END la_oenb[56]
  PIN la_oenb[55]
    DIRECTION INPUT ;
    USE SIGNAL ;
    PORT
      LAYER met2 ;
        RECT 1587.160000 0.000000 1587.300000 0.485000 ;
    END
  END la_oenb[55]
  PIN la_oenb[54]
    DIRECTION INPUT ;
    USE SIGNAL ;
    PORT
      LAYER met2 ;
        RECT 1569.680000 0.000000 1569.820000 0.485000 ;
    END
  END la_oenb[54]
  PIN la_oenb[53]
    DIRECTION INPUT ;
    USE SIGNAL ;
    PORT
      LAYER met2 ;
        RECT 1552.200000 0.000000 1552.340000 0.485000 ;
    END
  END la_oenb[53]
  PIN la_oenb[52]
    DIRECTION INPUT ;
    USE SIGNAL ;
    PORT
      LAYER met2 ;
        RECT 1534.720000 0.000000 1534.860000 0.485000 ;
    END
  END la_oenb[52]
  PIN la_oenb[51]
    DIRECTION INPUT ;
    USE SIGNAL ;
    PORT
      LAYER met2 ;
        RECT 1517.240000 0.000000 1517.380000 0.485000 ;
    END
  END la_oenb[51]
  PIN la_oenb[50]
    DIRECTION INPUT ;
    USE SIGNAL ;
    PORT
      LAYER met2 ;
        RECT 1499.760000 0.000000 1499.900000 0.485000 ;
    END
  END la_oenb[50]
  PIN la_oenb[49]
    DIRECTION INPUT ;
    USE SIGNAL ;
    PORT
      LAYER met2 ;
        RECT 1482.280000 0.000000 1482.420000 0.485000 ;
    END
  END la_oenb[49]
  PIN la_oenb[48]
    DIRECTION INPUT ;
    USE SIGNAL ;
    PORT
      LAYER met2 ;
        RECT 1464.800000 0.000000 1464.940000 0.485000 ;
    END
  END la_oenb[48]
  PIN la_oenb[47]
    DIRECTION INPUT ;
    USE SIGNAL ;
    PORT
      LAYER met2 ;
        RECT 1447.320000 0.000000 1447.460000 0.485000 ;
    END
  END la_oenb[47]
  PIN la_oenb[46]
    DIRECTION INPUT ;
    USE SIGNAL ;
    PORT
      LAYER met2 ;
        RECT 1430.300000 0.000000 1430.440000 0.485000 ;
    END
  END la_oenb[46]
  PIN la_oenb[45]
    DIRECTION INPUT ;
    USE SIGNAL ;
    PORT
      LAYER met2 ;
        RECT 1412.820000 0.000000 1412.960000 0.485000 ;
    END
  END la_oenb[45]
  PIN la_oenb[44]
    DIRECTION INPUT ;
    USE SIGNAL ;
    PORT
      LAYER met2 ;
        RECT 1395.340000 0.000000 1395.480000 0.485000 ;
    END
  END la_oenb[44]
  PIN la_oenb[43]
    DIRECTION INPUT ;
    USE SIGNAL ;
    PORT
      LAYER met2 ;
        RECT 1377.860000 0.000000 1378.000000 0.485000 ;
    END
  END la_oenb[43]
  PIN la_oenb[42]
    DIRECTION INPUT ;
    USE SIGNAL ;
    PORT
      LAYER met2 ;
        RECT 1360.380000 0.000000 1360.520000 0.485000 ;
    END
  END la_oenb[42]
  PIN la_oenb[41]
    DIRECTION INPUT ;
    USE SIGNAL ;
    PORT
      LAYER met2 ;
        RECT 1342.900000 0.000000 1343.040000 0.485000 ;
    END
  END la_oenb[41]
  PIN la_oenb[40]
    DIRECTION INPUT ;
    USE SIGNAL ;
    PORT
      LAYER met2 ;
        RECT 1325.420000 0.000000 1325.560000 0.485000 ;
    END
  END la_oenb[40]
  PIN la_oenb[39]
    DIRECTION INPUT ;
    USE SIGNAL ;
    PORT
      LAYER met2 ;
        RECT 1307.940000 0.000000 1308.080000 0.485000 ;
    END
  END la_oenb[39]
  PIN la_oenb[38]
    DIRECTION INPUT ;
    USE SIGNAL ;
    PORT
      LAYER met2 ;
        RECT 1290.460000 0.000000 1290.600000 0.485000 ;
    END
  END la_oenb[38]
  PIN la_oenb[37]
    DIRECTION INPUT ;
    USE SIGNAL ;
    PORT
      LAYER met2 ;
        RECT 1272.980000 0.000000 1273.120000 0.485000 ;
    END
  END la_oenb[37]
  PIN la_oenb[36]
    DIRECTION INPUT ;
    USE SIGNAL ;
    PORT
      LAYER met2 ;
        RECT 1255.500000 0.000000 1255.640000 0.485000 ;
    END
  END la_oenb[36]
  PIN la_oenb[35]
    DIRECTION INPUT ;
    USE SIGNAL ;
    PORT
      LAYER met2 ;
        RECT 1238.480000 0.000000 1238.620000 0.485000 ;
    END
  END la_oenb[35]
  PIN la_oenb[34]
    DIRECTION INPUT ;
    USE SIGNAL ;
    PORT
      LAYER met2 ;
        RECT 1221.000000 0.000000 1221.140000 0.485000 ;
    END
  END la_oenb[34]
  PIN la_oenb[33]
    DIRECTION INPUT ;
    USE SIGNAL ;
    PORT
      LAYER met2 ;
        RECT 1203.520000 0.000000 1203.660000 0.485000 ;
    END
  END la_oenb[33]
  PIN la_oenb[32]
    DIRECTION INPUT ;
    USE SIGNAL ;
    PORT
      LAYER met2 ;
        RECT 1186.040000 0.000000 1186.180000 0.485000 ;
    END
  END la_oenb[32]
  PIN la_oenb[31]
    DIRECTION INPUT ;
    USE SIGNAL ;
    PORT
      LAYER met2 ;
        RECT 1168.560000 0.000000 1168.700000 0.485000 ;
    END
  END la_oenb[31]
  PIN la_oenb[30]
    DIRECTION INPUT ;
    USE SIGNAL ;
    PORT
      LAYER met2 ;
        RECT 1151.080000 0.000000 1151.220000 0.485000 ;
    END
  END la_oenb[30]
  PIN la_oenb[29]
    DIRECTION INPUT ;
    USE SIGNAL ;
    PORT
      LAYER met2 ;
        RECT 1133.600000 0.000000 1133.740000 0.485000 ;
    END
  END la_oenb[29]
  PIN la_oenb[28]
    DIRECTION INPUT ;
    USE SIGNAL ;
    PORT
      LAYER met2 ;
        RECT 1116.120000 0.000000 1116.260000 0.485000 ;
    END
  END la_oenb[28]
  PIN la_oenb[27]
    DIRECTION INPUT ;
    USE SIGNAL ;
    PORT
      LAYER met2 ;
        RECT 1098.640000 0.000000 1098.780000 0.485000 ;
    END
  END la_oenb[27]
  PIN la_oenb[26]
    DIRECTION INPUT ;
    USE SIGNAL ;
    PORT
      LAYER met2 ;
        RECT 1081.160000 0.000000 1081.300000 0.485000 ;
    END
  END la_oenb[26]
  PIN la_oenb[25]
    DIRECTION INPUT ;
    USE SIGNAL ;
    PORT
      LAYER met2 ;
        RECT 1064.140000 0.000000 1064.280000 0.485000 ;
    END
  END la_oenb[25]
  PIN la_oenb[24]
    DIRECTION INPUT ;
    USE SIGNAL ;
    PORT
      LAYER met2 ;
        RECT 1046.660000 0.000000 1046.800000 0.485000 ;
    END
  END la_oenb[24]
  PIN la_oenb[23]
    DIRECTION INPUT ;
    USE SIGNAL ;
    PORT
      LAYER met2 ;
        RECT 1029.180000 0.000000 1029.320000 0.485000 ;
    END
  END la_oenb[23]
  PIN la_oenb[22]
    DIRECTION INPUT ;
    USE SIGNAL ;
    PORT
      LAYER met2 ;
        RECT 1011.700000 0.000000 1011.840000 0.485000 ;
    END
  END la_oenb[22]
  PIN la_oenb[21]
    DIRECTION INPUT ;
    USE SIGNAL ;
    PORT
      LAYER met2 ;
        RECT 994.220000 0.000000 994.360000 0.485000 ;
    END
  END la_oenb[21]
  PIN la_oenb[20]
    DIRECTION INPUT ;
    USE SIGNAL ;
    PORT
      LAYER met2 ;
        RECT 976.740000 0.000000 976.880000 0.485000 ;
    END
  END la_oenb[20]
  PIN la_oenb[19]
    DIRECTION INPUT ;
    USE SIGNAL ;
    PORT
      LAYER met2 ;
        RECT 959.260000 0.000000 959.400000 0.485000 ;
    END
  END la_oenb[19]
  PIN la_oenb[18]
    DIRECTION INPUT ;
    USE SIGNAL ;
    PORT
      LAYER met2 ;
        RECT 941.780000 0.000000 941.920000 0.485000 ;
    END
  END la_oenb[18]
  PIN la_oenb[17]
    DIRECTION INPUT ;
    USE SIGNAL ;
    PORT
      LAYER met2 ;
        RECT 924.300000 0.000000 924.440000 0.485000 ;
    END
  END la_oenb[17]
  PIN la_oenb[16]
    DIRECTION INPUT ;
    USE SIGNAL ;
    PORT
      LAYER met2 ;
        RECT 906.820000 0.000000 906.960000 0.485000 ;
    END
  END la_oenb[16]
  PIN la_oenb[15]
    DIRECTION INPUT ;
    USE SIGNAL ;
    PORT
      LAYER met2 ;
        RECT 889.800000 0.000000 889.940000 0.485000 ;
    END
  END la_oenb[15]
  PIN la_oenb[14]
    DIRECTION INPUT ;
    USE SIGNAL ;
    PORT
      LAYER met2 ;
        RECT 872.320000 0.000000 872.460000 0.485000 ;
    END
  END la_oenb[14]
  PIN la_oenb[13]
    DIRECTION INPUT ;
    USE SIGNAL ;
    PORT
      LAYER met2 ;
        RECT 854.840000 0.000000 854.980000 0.485000 ;
    END
  END la_oenb[13]
  PIN la_oenb[12]
    DIRECTION INPUT ;
    USE SIGNAL ;
    PORT
      LAYER met2 ;
        RECT 837.360000 0.000000 837.500000 0.485000 ;
    END
  END la_oenb[12]
  PIN la_oenb[11]
    DIRECTION INPUT ;
    USE SIGNAL ;
    PORT
      LAYER met2 ;
        RECT 819.880000 0.000000 820.020000 0.485000 ;
    END
  END la_oenb[11]
  PIN la_oenb[10]
    DIRECTION INPUT ;
    USE SIGNAL ;
    PORT
      LAYER met2 ;
        RECT 802.400000 0.000000 802.540000 0.485000 ;
    END
  END la_oenb[10]
  PIN la_oenb[9]
    DIRECTION INPUT ;
    USE SIGNAL ;
    PORT
      LAYER met2 ;
        RECT 784.920000 0.000000 785.060000 0.485000 ;
    END
  END la_oenb[9]
  PIN la_oenb[8]
    DIRECTION INPUT ;
    USE SIGNAL ;
    PORT
      LAYER met2 ;
        RECT 767.440000 0.000000 767.580000 0.485000 ;
    END
  END la_oenb[8]
  PIN la_oenb[7]
    DIRECTION INPUT ;
    USE SIGNAL ;
    PORT
      LAYER met2 ;
        RECT 749.960000 0.000000 750.100000 0.485000 ;
    END
  END la_oenb[7]
  PIN la_oenb[6]
    DIRECTION INPUT ;
    USE SIGNAL ;
    PORT
      LAYER met2 ;
        RECT 732.480000 0.000000 732.620000 0.485000 ;
    END
  END la_oenb[6]
  PIN la_oenb[5]
    DIRECTION INPUT ;
    USE SIGNAL ;
    PORT
      LAYER met2 ;
        RECT 715.000000 0.000000 715.140000 0.485000 ;
    END
  END la_oenb[5]
  PIN la_oenb[4]
    DIRECTION INPUT ;
    USE SIGNAL ;
    PORT
      LAYER met2 ;
        RECT 697.980000 0.000000 698.120000 0.485000 ;
    END
  END la_oenb[4]
  PIN la_oenb[3]
    DIRECTION INPUT ;
    USE SIGNAL ;
    PORT
      LAYER met2 ;
        RECT 680.500000 0.000000 680.640000 0.485000 ;
    END
  END la_oenb[3]
  PIN la_oenb[2]
    DIRECTION INPUT ;
    USE SIGNAL ;
    PORT
      LAYER met2 ;
        RECT 663.020000 0.000000 663.160000 0.485000 ;
    END
  END la_oenb[2]
  PIN la_oenb[1]
    DIRECTION INPUT ;
    USE SIGNAL ;
    ANTENNAPARTIALMETALAREA 4.2223 LAYER met2  ;
    ANTENNAPARTIALMETALSIDEAREA 21.0035 LAYER met2  ;
    ANTENNAMODEL OXIDE1 ;
    ANTENNAGATEAREA 0.2475 LAYER met2  ;
    ANTENNAMAXAREACAR 18.1366 LAYER met2  ;
    ANTENNAMAXSIDEAREACAR 88.5212 LAYER met2  ;
    ANTENNAMAXCUTCAR 0.207677 LAYER via2  ;
    PORT
      LAYER met2 ;
        RECT 645.540000 0.000000 645.680000 0.485000 ;
    END
  END la_oenb[1]
  PIN la_oenb[0]
    DIRECTION INPUT ;
    USE SIGNAL ;
    PORT
      LAYER met2 ;
        RECT 628.060000 0.000000 628.200000 0.485000 ;
    END
  END la_oenb[0]
  PIN io_in[37]
    DIRECTION INPUT ;
    USE SIGNAL ;
    PORT
      LAYER met3 ;
        RECT 0.000000 169.490000 0.800000 169.790000 ;
    END
  END io_in[37]
  PIN io_in[36]
    DIRECTION INPUT ;
    USE SIGNAL ;
    PORT
      LAYER met3 ;
        RECT 0.000000 423.250000 0.800000 423.550000 ;
    END
  END io_in[36]
  PIN io_in[35]
    DIRECTION INPUT ;
    USE SIGNAL ;
    PORT
      LAYER met3 ;
        RECT 0.000000 677.010000 0.800000 677.310000 ;
    END
  END io_in[35]
  PIN io_in[34]
    DIRECTION INPUT ;
    USE SIGNAL ;
    PORT
      LAYER met3 ;
        RECT 0.000000 930.770000 0.800000 931.070000 ;
    END
  END io_in[34]
  PIN io_in[33]
    DIRECTION INPUT ;
    USE SIGNAL ;
    PORT
      LAYER met3 ;
        RECT 0.000000 1184.530000 0.800000 1184.830000 ;
    END
  END io_in[33]
  PIN io_in[32]
    DIRECTION INPUT ;
    USE SIGNAL ;
    PORT
      LAYER met3 ;
        RECT 0.000000 1438.900000 0.800000 1439.200000 ;
    END
  END io_in[32]
  PIN io_in[31]
    DIRECTION INPUT ;
    USE SIGNAL ;
    PORT
      LAYER met3 ;
        RECT 0.000000 1692.660000 0.800000 1692.960000 ;
    END
  END io_in[31]
  PIN io_in[30]
    DIRECTION INPUT ;
    USE SIGNAL ;
    PORT
      LAYER met3 ;
        RECT 0.000000 1946.420000 0.800000 1946.720000 ;
    END
  END io_in[30]
  PIN io_in[29]
    DIRECTION INPUT ;
    USE SIGNAL ;
    PORT
      LAYER met3 ;
        RECT 0.000000 2200.180000 0.800000 2200.480000 ;
    END
  END io_in[29]
  PIN io_in[28]
    DIRECTION INPUT ;
    USE SIGNAL ;
    PORT
      LAYER met3 ;
        RECT 0.000000 2453.940000 0.800000 2454.240000 ;
    END
  END io_in[28]
  PIN io_in[27]
    DIRECTION INPUT ;
    USE SIGNAL ;
    PORT
      LAYER met3 ;
        RECT 0.000000 2707.700000 0.800000 2708.000000 ;
    END
  END io_in[27]
  PIN io_in[26]
    DIRECTION INPUT ;
    USE SIGNAL ;
    PORT
      LAYER met3 ;
        RECT 0.000000 2961.460000 0.800000 2961.760000 ;
    END
  END io_in[26]
  PIN io_in[25]
    DIRECTION INPUT ;
    USE SIGNAL ;
    PORT
      LAYER met3 ;
        RECT 0.000000 3215.220000 0.800000 3215.520000 ;
    END
  END io_in[25]
  PIN io_in[24]
    DIRECTION INPUT ;
    USE SIGNAL ;
    PORT
      LAYER met3 ;
        RECT 0.000000 3469.590000 0.800000 3469.890000 ;
    END
  END io_in[24]
  PIN io_in[23]
    DIRECTION INPUT ;
    USE SIGNAL ;
    PORT
      LAYER met2 ;
        RECT 220.040000 3469.555000 220.180000 3470.040000 ;
    END
  END io_in[23]
  PIN io_in[22]
    DIRECTION INPUT ;
    USE SIGNAL ;
    PORT
      LAYER met2 ;
        RECT 549.860000 3469.555000 550.000000 3470.040000 ;
    END
  END io_in[22]
  PIN io_in[21]
    DIRECTION INPUT ;
    USE SIGNAL ;
    PORT
      LAYER met2 ;
        RECT 879.680000 3469.555000 879.820000 3470.040000 ;
    END
  END io_in[21]
  PIN io_in[20]
    DIRECTION INPUT ;
    USE SIGNAL ;
    PORT
      LAYER met2 ;
        RECT 1209.500000 3469.555000 1209.640000 3470.040000 ;
    END
  END io_in[20]
  PIN io_in[19]
    DIRECTION INPUT ;
    USE SIGNAL ;
    PORT
      LAYER met2 ;
        RECT 1539.780000 3469.555000 1539.920000 3470.040000 ;
    END
  END io_in[19]
  PIN io_in[18]
    DIRECTION INPUT ;
    USE SIGNAL ;
    PORT
      LAYER met2 ;
        RECT 1869.600000 3469.555000 1869.740000 3470.040000 ;
    END
  END io_in[18]
  PIN io_in[17]
    DIRECTION INPUT ;
    USE SIGNAL ;
    PORT
      LAYER met2 ;
        RECT 2199.420000 3469.555000 2199.560000 3470.040000 ;
    END
  END io_in[17]
  PIN io_in[16]
    DIRECTION INPUT ;
    USE SIGNAL ;
    PORT
      LAYER met2 ;
        RECT 2529.240000 3469.555000 2529.380000 3470.040000 ;
    END
  END io_in[16]
  PIN io_in[15]
    DIRECTION INPUT ;
    USE SIGNAL ;
    PORT
      LAYER met2 ;
        RECT 2859.060000 3469.555000 2859.200000 3470.040000 ;
    END
  END io_in[15]
  PIN io_in[14]
    DIRECTION INPUT ;
    USE SIGNAL ;
    PORT
      LAYER met3 ;
        RECT 2859.020000 3312.210000 2859.820000 3312.510000 ;
    END
  END io_in[14]
  PIN io_in[13]
    DIRECTION INPUT ;
    USE SIGNAL ;
    PORT
      LAYER met3 ;
        RECT 2859.020000 3075.530000 2859.820000 3075.830000 ;
    END
  END io_in[13]
  PIN io_in[12]
    DIRECTION INPUT ;
    USE SIGNAL ;
    PORT
      LAYER met3 ;
        RECT 2859.020000 2838.850000 2859.820000 2839.150000 ;
    END
  END io_in[12]
  PIN io_in[11]
    DIRECTION INPUT ;
    USE SIGNAL ;
    PORT
      LAYER met3 ;
        RECT 2859.020000 2602.780000 2859.820000 2603.080000 ;
    END
  END io_in[11]
  PIN io_in[10]
    DIRECTION INPUT ;
    USE SIGNAL ;
    PORT
      LAYER met3 ;
        RECT 2859.020000 2366.100000 2859.820000 2366.400000 ;
    END
  END io_in[10]
  PIN io_in[9]
    DIRECTION INPUT ;
    USE SIGNAL ;
    PORT
      LAYER met3 ;
        RECT 2859.020000 2129.420000 2859.820000 2129.720000 ;
    END
  END io_in[9]
  PIN io_in[8]
    DIRECTION INPUT ;
    USE SIGNAL ;
    PORT
      LAYER met3 ;
        RECT 2859.020000 1892.740000 2859.820000 1893.040000 ;
    END
  END io_in[8]
  PIN io_in[7]
    DIRECTION INPUT ;
    USE SIGNAL ;
    PORT
      LAYER met3 ;
        RECT 2859.020000 1656.670000 2859.820000 1656.970000 ;
    END
  END io_in[7]
  PIN io_in[6]
    DIRECTION INPUT ;
    USE SIGNAL ;
    PORT
      LAYER met3 ;
        RECT 2859.020000 1419.990000 2859.820000 1420.290000 ;
    END
  END io_in[6]
  PIN io_in[5]
    DIRECTION INPUT ;
    USE SIGNAL ;
    PORT
      LAYER met3 ;
        RECT 2859.020000 1183.310000 2859.820000 1183.610000 ;
    END
  END io_in[5]
  PIN io_in[4]
    DIRECTION INPUT ;
    USE SIGNAL ;
    PORT
      LAYER met3 ;
        RECT 2859.020000 946.630000 2859.820000 946.930000 ;
    END
  END io_in[4]
  PIN io_in[3]
    DIRECTION INPUT ;
    USE SIGNAL ;
    PORT
      LAYER met3 ;
        RECT 2859.020000 710.560000 2859.820000 710.860000 ;
    END
  END io_in[3]
  PIN io_in[2]
    DIRECTION INPUT ;
    USE SIGNAL ;
    PORT
      LAYER met3 ;
        RECT 2859.020000 473.880000 2859.820000 474.180000 ;
    END
  END io_in[2]
  PIN io_in[1]
    DIRECTION INPUT ;
    USE SIGNAL ;
    PORT
      LAYER met3 ;
        RECT 2859.020000 237.200000 2859.820000 237.500000 ;
    END
  END io_in[1]
  PIN io_in[0]
    DIRECTION INPUT ;
    USE SIGNAL ;
    PORT
      LAYER met3 ;
        RECT 2859.020000 0.520000 2859.820000 0.820000 ;
    END
  END io_in[0]
  PIN io_out[37]
    DIRECTION OUTPUT ;
    USE SIGNAL ;
    ANTENNADIFFAREA 0.336 LAYER met3  ;
    ANTENNAPARTIALMETALAREA 0.1644 LAYER met3  ;
    ANTENNAPARTIALMETALSIDEAREA 0.872 LAYER met3  ;
    PORT
      LAYER met3 ;
        RECT 0.000000 84.700000 0.800000 85.000000 ;
    END
  END io_out[37]
  PIN io_out[36]
    DIRECTION OUTPUT ;
    USE SIGNAL ;
    ANTENNADIFFAREA 0.336 LAYER met3  ;
    ANTENNAPARTIALMETALAREA 8.5824 LAYER met3  ;
    ANTENNAPARTIALMETALSIDEAREA 45.768 LAYER met3  ;
    PORT
      LAYER met3 ;
        RECT 0.000000 338.460000 0.800000 338.760000 ;
    END
  END io_out[36]
  PIN io_out[35]
    DIRECTION OUTPUT ;
    USE SIGNAL ;
    ANTENNADIFFAREA 0.336 LAYER met3  ;
    ANTENNAPARTIALMETALAREA 0.1644 LAYER met3  ;
    ANTENNAPARTIALMETALSIDEAREA 0.872 LAYER met3  ;
    PORT
      LAYER met3 ;
        RECT 0.000000 592.220000 0.800000 592.520000 ;
    END
  END io_out[35]
  PIN io_out[34]
    DIRECTION OUTPUT ;
    USE SIGNAL ;
    ANTENNADIFFAREA 0.336 LAYER met3  ;
    ANTENNAPARTIALMETALAREA 8.4444 LAYER met3  ;
    ANTENNAPARTIALMETALSIDEAREA 45.032 LAYER met3  ;
    PORT
      LAYER met3 ;
        RECT 0.000000 846.590000 0.800000 846.890000 ;
    END
  END io_out[34]
  PIN io_out[33]
    DIRECTION OUTPUT ;
    USE SIGNAL ;
    ANTENNADIFFAREA 0.336 LAYER met3  ;
    ANTENNAPARTIALMETALAREA 8.7204 LAYER met3  ;
    ANTENNAPARTIALMETALSIDEAREA 46.504 LAYER met3  ;
    PORT
      LAYER met3 ;
        RECT 0.000000 1100.350000 0.800000 1100.650000 ;
    END
  END io_out[33]
  PIN io_out[32]
    DIRECTION OUTPUT ;
    USE SIGNAL ;
    ANTENNADIFFAREA 0.336 LAYER met3  ;
    ANTENNAPARTIALMETALAREA 8.5824 LAYER met3  ;
    ANTENNAPARTIALMETALSIDEAREA 45.768 LAYER met3  ;
    PORT
      LAYER met3 ;
        RECT 0.000000 1354.110000 0.800000 1354.410000 ;
    END
  END io_out[32]
  PIN io_out[31]
    DIRECTION OUTPUT ;
    USE SIGNAL ;
    ANTENNADIFFAREA 0.336 LAYER met3  ;
    ANTENNAPARTIALMETALAREA 8.7204 LAYER met3  ;
    ANTENNAPARTIALMETALSIDEAREA 46.504 LAYER met3  ;
    PORT
      LAYER met3 ;
        RECT 0.000000 1607.870000 0.800000 1608.170000 ;
    END
  END io_out[31]
  PIN io_out[30]
    DIRECTION OUTPUT ;
    USE SIGNAL ;
    ANTENNADIFFAREA 0.336 LAYER met3  ;
    ANTENNAPARTIALMETALAREA 3.2004 LAYER met3  ;
    ANTENNAPARTIALMETALSIDEAREA 17.064 LAYER met3  ;
    PORT
      LAYER met3 ;
        RECT 0.000000 1861.630000 0.800000 1861.930000 ;
    END
  END io_out[30]
  PIN io_out[29]
    DIRECTION OUTPUT ;
    USE SIGNAL ;
    ANTENNADIFFAREA 0.336 LAYER met3  ;
    ANTENNAPARTIALMETALAREA 0.1644 LAYER met3  ;
    ANTENNAPARTIALMETALSIDEAREA 0.872 LAYER met3  ;
    PORT
      LAYER met3 ;
        RECT 0.000000 2115.390000 0.800000 2115.690000 ;
    END
  END io_out[29]
  PIN io_out[28]
    DIRECTION OUTPUT ;
    USE SIGNAL ;
    ANTENNADIFFAREA 0.336 LAYER met3  ;
    ANTENNAPARTIALMETALAREA 8.5824 LAYER met3  ;
    ANTENNAPARTIALMETALSIDEAREA 45.768 LAYER met3  ;
    PORT
      LAYER met3 ;
        RECT 0.000000 2369.150000 0.800000 2369.450000 ;
    END
  END io_out[28]
  PIN io_out[27]
    DIRECTION OUTPUT ;
    USE SIGNAL ;
    ANTENNADIFFAREA 0.336 LAYER met3  ;
    ANTENNAPARTIALMETALAREA 8.7204 LAYER met3  ;
    ANTENNAPARTIALMETALSIDEAREA 46.504 LAYER met3  ;
    PORT
      LAYER met3 ;
        RECT 0.000000 2622.910000 0.800000 2623.210000 ;
    END
  END io_out[27]
  PIN io_out[26]
    DIRECTION OUTPUT ;
    USE SIGNAL ;
    ANTENNADIFFAREA 0.336 LAYER met3  ;
    ANTENNAPARTIALMETALAREA 8.5824 LAYER met3  ;
    ANTENNAPARTIALMETALSIDEAREA 45.768 LAYER met3  ;
    PORT
      LAYER met3 ;
        RECT 0.000000 2877.280000 0.800000 2877.580000 ;
    END
  END io_out[26]
  PIN io_out[25]
    DIRECTION OUTPUT ;
    USE SIGNAL ;
    ANTENNADIFFAREA 0.336 LAYER met3  ;
    ANTENNAPARTIALMETALAREA 8.5824 LAYER met3  ;
    ANTENNAPARTIALMETALSIDEAREA 45.768 LAYER met3  ;
    PORT
      LAYER met3 ;
        RECT 0.000000 3131.040000 0.800000 3131.340000 ;
    END
  END io_out[25]
  PIN io_out[24]
    DIRECTION OUTPUT ;
    USE SIGNAL ;
    ANTENNADIFFAREA 0.336 LAYER met3  ;
    ANTENNAPARTIALMETALAREA 8.5824 LAYER met3  ;
    ANTENNAPARTIALMETALSIDEAREA 45.768 LAYER met3  ;
    PORT
      LAYER met3 ;
        RECT 0.000000 3384.800000 0.800000 3385.100000 ;
    END
  END io_out[24]
  PIN io_out[23]
    DIRECTION OUTPUT ;
    USE SIGNAL ;
    ANTENNADIFFAREA 0.336 LAYER met2  ;
    ANTENNAPARTIALMETALAREA 4.7291 LAYER met2  ;
    ANTENNAPARTIALMETALSIDEAREA 23.5375 LAYER met2  ;
    PORT
      LAYER met2 ;
        RECT 110.100000 3469.555000 110.240000 3470.040000 ;
    END
  END io_out[23]
  PIN io_out[22]
    DIRECTION OUTPUT ;
    USE SIGNAL ;
    ANTENNADIFFAREA 0.336 LAYER met2  ;
    ANTENNAPARTIALMETALAREA 4.7291 LAYER met2  ;
    ANTENNAPARTIALMETALSIDEAREA 23.5375 LAYER met2  ;
    PORT
      LAYER met2 ;
        RECT 439.920000 3469.555000 440.060000 3470.040000 ;
    END
  END io_out[22]
  PIN io_out[21]
    DIRECTION OUTPUT ;
    USE SIGNAL ;
    ANTENNADIFFAREA 0.336 LAYER met2  ;
    ANTENNAPARTIALMETALAREA 4.7291 LAYER met2  ;
    ANTENNAPARTIALMETALSIDEAREA 23.5375 LAYER met2  ;
    PORT
      LAYER met2 ;
        RECT 769.740000 3469.555000 769.880000 3470.040000 ;
    END
  END io_out[21]
  PIN io_out[20]
    DIRECTION OUTPUT ;
    USE SIGNAL ;
    ANTENNADIFFAREA 0.336 LAYER met2  ;
    ANTENNAPARTIALMETALAREA 4.7291 LAYER met2  ;
    ANTENNAPARTIALMETALSIDEAREA 23.5375 LAYER met2  ;
    PORT
      LAYER met2 ;
        RECT 1099.560000 3469.555000 1099.700000 3470.040000 ;
    END
  END io_out[20]
  PIN io_out[19]
    DIRECTION OUTPUT ;
    USE SIGNAL ;
    ANTENNADIFFAREA 0.336 LAYER met2  ;
    ANTENNAPARTIALMETALAREA 4.6703 LAYER met2  ;
    ANTENNAPARTIALMETALSIDEAREA 23.2435 LAYER met2  ;
    PORT
      LAYER met2 ;
        RECT 1429.380000 3469.555000 1429.520000 3470.040000 ;
    END
  END io_out[19]
  PIN io_out[18]
    DIRECTION OUTPUT ;
    USE SIGNAL ;
    ANTENNADIFFAREA 0.336 LAYER met2  ;
    ANTENNAPARTIALMETALAREA 4.7291 LAYER met2  ;
    ANTENNAPARTIALMETALSIDEAREA 23.5375 LAYER met2  ;
    PORT
      LAYER met2 ;
        RECT 1759.660000 3469.555000 1759.800000 3470.040000 ;
    END
  END io_out[18]
  PIN io_out[17]
    DIRECTION OUTPUT ;
    USE SIGNAL ;
    ANTENNADIFFAREA 0.336 LAYER met2  ;
    ANTENNAPARTIALMETALAREA 4.3483 LAYER met2  ;
    ANTENNAPARTIALMETALSIDEAREA 21.6335 LAYER met2  ;
    PORT
      LAYER met2 ;
        RECT 2089.480000 3469.555000 2089.620000 3470.040000 ;
    END
  END io_out[17]
  PIN io_out[16]
    DIRECTION OUTPUT ;
    USE SIGNAL ;
    ANTENNADIFFAREA 0.336 LAYER met2  ;
    ANTENNAPARTIALMETALAREA 4.7291 LAYER met2  ;
    ANTENNAPARTIALMETALSIDEAREA 23.5375 LAYER met2  ;
    PORT
      LAYER met2 ;
        RECT 2419.300000 3469.555000 2419.440000 3470.040000 ;
    END
  END io_out[16]
  PIN io_out[15]
    DIRECTION OUTPUT ;
    USE SIGNAL ;
    ANTENNADIFFAREA 0.336 LAYER met2  ;
    ANTENNAPARTIALMETALAREA 4.7291 LAYER met2  ;
    ANTENNAPARTIALMETALSIDEAREA 23.5375 LAYER met2  ;
    PORT
      LAYER met2 ;
        RECT 2749.120000 3469.555000 2749.260000 3470.040000 ;
    END
  END io_out[15]
  PIN io_out[14]
    DIRECTION OUTPUT ;
    USE SIGNAL ;
    ANTENNADIFFAREA 0.336 LAYER met3  ;
    ANTENNAPARTIALMETALAREA 0.1644 LAYER met3  ;
    ANTENNAPARTIALMETALSIDEAREA 0.872 LAYER met3  ;
    PORT
      LAYER met3 ;
        RECT 2859.020000 3390.900000 2859.820000 3391.200000 ;
    END
  END io_out[14]
  PIN io_out[13]
    DIRECTION OUTPUT ;
    USE SIGNAL ;
    ANTENNADIFFAREA 0.336 LAYER met3  ;
    ANTENNAPARTIALMETALAREA 8.8584 LAYER met3  ;
    ANTENNAPARTIALMETALSIDEAREA 47.24 LAYER met3  ;
    PORT
      LAYER met3 ;
        RECT 2859.020000 3154.220000 2859.820000 3154.520000 ;
    END
  END io_out[13]
  PIN io_out[12]
    DIRECTION OUTPUT ;
    USE SIGNAL ;
    ANTENNADIFFAREA 0.336 LAYER met3  ;
    ANTENNAPARTIALMETALAREA 0.1644 LAYER met3  ;
    ANTENNAPARTIALMETALSIDEAREA 0.872 LAYER met3  ;
    PORT
      LAYER met3 ;
        RECT 2859.020000 2918.150000 2859.820000 2918.450000 ;
    END
  END io_out[12]
  PIN io_out[11]
    DIRECTION OUTPUT ;
    USE SIGNAL ;
    ANTENNADIFFAREA 0.336 LAYER met3  ;
    ANTENNAPARTIALMETALAREA 8.8584 LAYER met3  ;
    ANTENNAPARTIALMETALSIDEAREA 47.24 LAYER met3  ;
    PORT
      LAYER met3 ;
        RECT 2859.020000 2681.470000 2859.820000 2681.770000 ;
    END
  END io_out[11]
  PIN io_out[10]
    DIRECTION OUTPUT ;
    USE SIGNAL ;
    ANTENNADIFFAREA 0.336 LAYER met3  ;
    ANTENNAPARTIALMETALAREA 8.8584 LAYER met3  ;
    ANTENNAPARTIALMETALSIDEAREA 47.24 LAYER met3  ;
    PORT
      LAYER met3 ;
        RECT 2859.020000 2444.790000 2859.820000 2445.090000 ;
    END
  END io_out[10]
  PIN io_out[9]
    DIRECTION OUTPUT ;
    USE SIGNAL ;
    ANTENNADIFFAREA 0.336 LAYER met3  ;
    ANTENNAPARTIALMETALAREA 8.8584 LAYER met3  ;
    ANTENNAPARTIALMETALSIDEAREA 47.24 LAYER met3  ;
    PORT
      LAYER met3 ;
        RECT 2859.020000 2208.110000 2859.820000 2208.410000 ;
    END
  END io_out[9]
  PIN io_out[8]
    DIRECTION OUTPUT ;
    USE SIGNAL ;
    ANTENNADIFFAREA 0.336 LAYER met3  ;
    ANTENNAPARTIALMETALAREA 8.8584 LAYER met3  ;
    ANTENNAPARTIALMETALSIDEAREA 47.24 LAYER met3  ;
    PORT
      LAYER met3 ;
        RECT 2859.020000 1972.040000 2859.820000 1972.340000 ;
    END
  END io_out[8]
  PIN io_out[7]
    DIRECTION OUTPUT ;
    USE SIGNAL ;
    ANTENNADIFFAREA 0.336 LAYER met3  ;
    ANTENNAPARTIALMETALAREA 0.1644 LAYER met3  ;
    ANTENNAPARTIALMETALSIDEAREA 0.872 LAYER met3  ;
    PORT
      LAYER met3 ;
        RECT 2859.020000 1735.360000 2859.820000 1735.660000 ;
    END
  END io_out[7]
  PIN io_out[6]
    DIRECTION OUTPUT ;
    USE SIGNAL ;
    ANTENNADIFFAREA 0.336 LAYER met3  ;
    ANTENNAPARTIALMETALAREA 0.1644 LAYER met3  ;
    ANTENNAPARTIALMETALSIDEAREA 0.872 LAYER met3  ;
    PORT
      LAYER met3 ;
        RECT 2859.020000 1498.680000 2859.820000 1498.980000 ;
    END
  END io_out[6]
  PIN io_out[5]
    DIRECTION OUTPUT ;
    USE SIGNAL ;
    ANTENNADIFFAREA 0.336 LAYER met3  ;
    ANTENNAPARTIALMETALAREA 0.1644 LAYER met3  ;
    ANTENNAPARTIALMETALSIDEAREA 0.872 LAYER met3  ;
    PORT
      LAYER met3 ;
        RECT 2859.020000 1262.000000 2859.820000 1262.300000 ;
    END
  END io_out[5]
  PIN io_out[4]
    DIRECTION OUTPUT ;
    USE SIGNAL ;
    ANTENNADIFFAREA 0.336 LAYER met3  ;
    ANTENNAPARTIALMETALAREA 0.1644 LAYER met3  ;
    ANTENNAPARTIALMETALSIDEAREA 0.872 LAYER met3  ;
    PORT
      LAYER met3 ;
        RECT 2859.020000 1025.930000 2859.820000 1026.230000 ;
    END
  END io_out[4]
  PIN io_out[3]
    DIRECTION OUTPUT ;
    USE SIGNAL ;
    ANTENNADIFFAREA 0.336 LAYER met3  ;
    ANTENNAPARTIALMETALAREA 0.1644 LAYER met3  ;
    ANTENNAPARTIALMETALSIDEAREA 0.872 LAYER met3  ;
    PORT
      LAYER met3 ;
        RECT 2859.020000 789.250000 2859.820000 789.550000 ;
    END
  END io_out[3]
  PIN io_out[2]
    DIRECTION OUTPUT ;
    USE SIGNAL ;
    ANTENNADIFFAREA 0.336 LAYER met3  ;
    ANTENNAPARTIALMETALAREA 0.1644 LAYER met3  ;
    ANTENNAPARTIALMETALSIDEAREA 0.872 LAYER met3  ;
    PORT
      LAYER met3 ;
        RECT 2859.020000 552.570000 2859.820000 552.870000 ;
    END
  END io_out[2]
  PIN io_out[1]
    DIRECTION OUTPUT ;
    USE SIGNAL ;
    ANTENNADIFFAREA 0.336 LAYER met3  ;
    ANTENNAPARTIALMETALAREA 0.1644 LAYER met3  ;
    ANTENNAPARTIALMETALSIDEAREA 0.872 LAYER met3  ;
    PORT
      LAYER met3 ;
        RECT 2859.020000 315.890000 2859.820000 316.190000 ;
    END
  END io_out[1]
  PIN io_out[0]
    DIRECTION OUTPUT ;
    USE SIGNAL ;
    ANTENNADIFFAREA 0.336 LAYER met3  ;
    ANTENNAPARTIALMETALAREA 0.1644 LAYER met3  ;
    ANTENNAPARTIALMETALSIDEAREA 0.872 LAYER met3  ;
    PORT
      LAYER met3 ;
        RECT 2859.020000 79.820000 2859.820000 80.120000 ;
    END
  END io_out[0]
  PIN io_oeb[37]
    DIRECTION OUTPUT ;
    USE SIGNAL ;
    ANTENNADIFFAREA 0.336 LAYER met3  ;
    ANTENNAPARTIALMETALAREA 0.7164 LAYER met3  ;
    ANTENNAPARTIALMETALSIDEAREA 3.816 LAYER met3  ;
    PORT
      LAYER met3 ;
        RECT 0.000000 0.520000 0.800000 0.820000 ;
    END
  END io_oeb[37]
  PIN io_oeb[36]
    DIRECTION OUTPUT ;
    USE SIGNAL ;
    ANTENNADIFFAREA 0.336 LAYER met3  ;
    ANTENNAPARTIALMETALAREA 8.7204 LAYER met3  ;
    ANTENNAPARTIALMETALSIDEAREA 46.504 LAYER met3  ;
    PORT
      LAYER met3 ;
        RECT 0.000000 254.280000 0.800000 254.580000 ;
    END
  END io_oeb[36]
  PIN io_oeb[35]
    DIRECTION OUTPUT ;
    USE SIGNAL ;
    ANTENNADIFFAREA 0.336 LAYER met3  ;
    ANTENNAPARTIALMETALAREA 8.5824 LAYER met3  ;
    ANTENNAPARTIALMETALSIDEAREA 45.768 LAYER met3  ;
    PORT
      LAYER met3 ;
        RECT 0.000000 508.040000 0.800000 508.340000 ;
    END
  END io_oeb[35]
  PIN io_oeb[34]
    DIRECTION OUTPUT ;
    USE SIGNAL ;
    ANTENNADIFFAREA 0.336 LAYER met3  ;
    ANTENNAPARTIALMETALAREA 8.7204 LAYER met3  ;
    ANTENNAPARTIALMETALSIDEAREA 46.504 LAYER met3  ;
    PORT
      LAYER met3 ;
        RECT 0.000000 761.800000 0.800000 762.100000 ;
    END
  END io_oeb[34]
  PIN io_oeb[33]
    DIRECTION OUTPUT ;
    USE SIGNAL ;
    ANTENNADIFFAREA 0.336 LAYER met3  ;
    ANTENNAPARTIALMETALAREA 8.5824 LAYER met3  ;
    ANTENNAPARTIALMETALSIDEAREA 45.768 LAYER met3  ;
    PORT
      LAYER met3 ;
        RECT 0.000000 1015.560000 0.800000 1015.860000 ;
    END
  END io_oeb[33]
  PIN io_oeb[32]
    DIRECTION OUTPUT ;
    USE SIGNAL ;
    ANTENNADIFFAREA 0.336 LAYER met3  ;
    ANTENNAPARTIALMETALAREA 8.5824 LAYER met3  ;
    ANTENNAPARTIALMETALSIDEAREA 45.768 LAYER met3  ;
    PORT
      LAYER met3 ;
        RECT 0.000000 1269.320000 0.800000 1269.620000 ;
    END
  END io_oeb[32]
  PIN io_oeb[31]
    DIRECTION OUTPUT ;
    USE SIGNAL ;
    ANTENNADIFFAREA 0.336 LAYER met3  ;
    ANTENNAPARTIALMETALAREA 0.1644 LAYER met3  ;
    ANTENNAPARTIALMETALSIDEAREA 0.872 LAYER met3  ;
    PORT
      LAYER met3 ;
        RECT 0.000000 1523.080000 0.800000 1523.380000 ;
    END
  END io_oeb[31]
  PIN io_oeb[30]
    DIRECTION OUTPUT ;
    USE SIGNAL ;
    ANTENNADIFFAREA 0.336 LAYER met3  ;
    ANTENNAPARTIALMETALAREA 8.5824 LAYER met3  ;
    ANTENNAPARTIALMETALSIDEAREA 45.768 LAYER met3  ;
    PORT
      LAYER met3 ;
        RECT 0.000000 1776.840000 0.800000 1777.140000 ;
    END
  END io_oeb[30]
  PIN io_oeb[29]
    DIRECTION OUTPUT ;
    USE SIGNAL ;
    ANTENNADIFFAREA 0.336 LAYER met3  ;
    ANTENNAPARTIALMETALAREA 8.5824 LAYER met3  ;
    ANTENNAPARTIALMETALSIDEAREA 45.768 LAYER met3  ;
    PORT
      LAYER met3 ;
        RECT 0.000000 2030.600000 0.800000 2030.900000 ;
    END
  END io_oeb[29]
  PIN io_oeb[28]
    DIRECTION OUTPUT ;
    USE SIGNAL ;
    ANTENNADIFFAREA 0.336 LAYER met3  ;
    ANTENNAPARTIALMETALAREA 8.7204 LAYER met3  ;
    ANTENNAPARTIALMETALSIDEAREA 46.504 LAYER met3  ;
    PORT
      LAYER met3 ;
        RECT 0.000000 2284.970000 0.800000 2285.270000 ;
    END
  END io_oeb[28]
  PIN io_oeb[27]
    DIRECTION OUTPUT ;
    USE SIGNAL ;
    ANTENNADIFFAREA 0.336 LAYER met3  ;
    ANTENNAPARTIALMETALAREA 8.5824 LAYER met3  ;
    ANTENNAPARTIALMETALSIDEAREA 45.768 LAYER met3  ;
    PORT
      LAYER met3 ;
        RECT 0.000000 2538.730000 0.800000 2539.030000 ;
    END
  END io_oeb[27]
  PIN io_oeb[26]
    DIRECTION OUTPUT ;
    USE SIGNAL ;
    ANTENNADIFFAREA 0.336 LAYER met3  ;
    ANTENNAPARTIALMETALAREA 8.4444 LAYER met3  ;
    ANTENNAPARTIALMETALSIDEAREA 45.032 LAYER met3  ;
    PORT
      LAYER met3 ;
        RECT 0.000000 2792.490000 0.800000 2792.790000 ;
    END
  END io_oeb[26]
  PIN io_oeb[25]
    DIRECTION OUTPUT ;
    USE SIGNAL ;
    ANTENNADIFFAREA 0.336 LAYER met3  ;
    ANTENNAPARTIALMETALAREA 0.1644 LAYER met3  ;
    ANTENNAPARTIALMETALSIDEAREA 0.872 LAYER met3  ;
    PORT
      LAYER met3 ;
        RECT 0.000000 3046.250000 0.800000 3046.550000 ;
    END
  END io_oeb[25]
  PIN io_oeb[24]
    DIRECTION OUTPUT ;
    USE SIGNAL ;
    ANTENNADIFFAREA 0.336 LAYER met3  ;
    ANTENNAPARTIALMETALAREA 8.4444 LAYER met3  ;
    ANTENNAPARTIALMETALSIDEAREA 45.032 LAYER met3  ;
    PORT
      LAYER met3 ;
        RECT 0.000000 3300.010000 0.800000 3300.310000 ;
    END
  END io_oeb[24]
  PIN io_oeb[23]
    DIRECTION OUTPUT ;
    USE SIGNAL ;
    ANTENNADIFFAREA 0.336 LAYER met2  ;
    ANTENNAPARTIALMETALAREA 4.8719 LAYER met2  ;
    ANTENNAPARTIALMETALSIDEAREA 24.2515 LAYER met2  ;
    PORT
      LAYER met2 ;
        RECT 0.160000 3469.555000 0.300000 3470.040000 ;
    END
  END io_oeb[23]
  PIN io_oeb[22]
    DIRECTION OUTPUT ;
    USE SIGNAL ;
    ANTENNADIFFAREA 0.336 LAYER met2  ;
    ANTENNAPARTIALMETALAREA 4.7291 LAYER met2  ;
    ANTENNAPARTIALMETALSIDEAREA 23.5375 LAYER met2  ;
    PORT
      LAYER met2 ;
        RECT 329.980000 3469.555000 330.120000 3470.040000 ;
    END
  END io_oeb[22]
  PIN io_oeb[21]
    DIRECTION OUTPUT ;
    USE SIGNAL ;
    ANTENNADIFFAREA 0.336 LAYER met2  ;
    ANTENNAPARTIALMETALAREA 4.3483 LAYER met2  ;
    ANTENNAPARTIALMETALSIDEAREA 21.6335 LAYER met2  ;
    PORT
      LAYER met2 ;
        RECT 659.800000 3469.555000 659.940000 3470.040000 ;
    END
  END io_oeb[21]
  PIN io_oeb[20]
    DIRECTION OUTPUT ;
    USE SIGNAL ;
    ANTENNADIFFAREA 0.336 LAYER met2  ;
    ANTENNAPARTIALMETALAREA 4.7291 LAYER met2  ;
    ANTENNAPARTIALMETALSIDEAREA 23.5375 LAYER met2  ;
    PORT
      LAYER met2 ;
        RECT 989.620000 3469.555000 989.760000 3470.040000 ;
    END
  END io_oeb[20]
  PIN io_oeb[19]
    DIRECTION OUTPUT ;
    USE SIGNAL ;
    ANTENNADIFFAREA 0.336 LAYER met2  ;
    ANTENNAPARTIALMETALAREA 4.7291 LAYER met2  ;
    ANTENNAPARTIALMETALSIDEAREA 23.5375 LAYER met2  ;
    PORT
      LAYER met2 ;
        RECT 1319.440000 3469.555000 1319.580000 3470.040000 ;
    END
  END io_oeb[19]
  PIN io_oeb[18]
    DIRECTION OUTPUT ;
    USE SIGNAL ;
    ANTENNADIFFAREA 0.336 LAYER met2  ;
    ANTENNAPARTIALMETALAREA 4.7291 LAYER met2  ;
    ANTENNAPARTIALMETALSIDEAREA 23.5375 LAYER met2  ;
    PORT
      LAYER met2 ;
        RECT 1649.720000 3469.555000 1649.860000 3470.040000 ;
    END
  END io_oeb[18]
  PIN io_oeb[17]
    DIRECTION OUTPUT ;
    USE SIGNAL ;
    ANTENNADIFFAREA 0.336 LAYER met2  ;
    ANTENNAPARTIALMETALAREA 4.7291 LAYER met2  ;
    ANTENNAPARTIALMETALSIDEAREA 23.5375 LAYER met2  ;
    PORT
      LAYER met2 ;
        RECT 1979.540000 3469.555000 1979.680000 3470.040000 ;
    END
  END io_oeb[17]
  PIN io_oeb[16]
    DIRECTION OUTPUT ;
    USE SIGNAL ;
    ANTENNADIFFAREA 0.336 LAYER met2  ;
    ANTENNAPARTIALMETALAREA 4.7291 LAYER met2  ;
    ANTENNAPARTIALMETALSIDEAREA 23.5375 LAYER met2  ;
    PORT
      LAYER met2 ;
        RECT 2309.360000 3469.555000 2309.500000 3470.040000 ;
    END
  END io_oeb[16]
  PIN io_oeb[15]
    DIRECTION OUTPUT ;
    USE SIGNAL ;
    ANTENNADIFFAREA 0.336 LAYER met2  ;
    ANTENNAPARTIALMETALAREA 4.7291 LAYER met2  ;
    ANTENNAPARTIALMETALSIDEAREA 23.5375 LAYER met2  ;
    PORT
      LAYER met2 ;
        RECT 2639.180000 3469.555000 2639.320000 3470.040000 ;
    END
  END io_oeb[15]
  PIN io_oeb[14]
    DIRECTION OUTPUT ;
    USE SIGNAL ;
    ANTENNADIFFAREA 0.336 LAYER met3  ;
    ANTENNAPARTIALMETALAREA 8.8584 LAYER met3  ;
    ANTENNAPARTIALMETALSIDEAREA 47.24 LAYER met3  ;
    PORT
      LAYER met3 ;
        RECT 2859.020000 3469.590000 2859.820000 3469.890000 ;
    END
  END io_oeb[14]
  PIN io_oeb[13]
    DIRECTION OUTPUT ;
    USE SIGNAL ;
    ANTENNADIFFAREA 0.336 LAYER met3  ;
    ANTENNAPARTIALMETALAREA 8.8584 LAYER met3  ;
    ANTENNAPARTIALMETALSIDEAREA 47.24 LAYER met3  ;
    PORT
      LAYER met3 ;
        RECT 2859.020000 3233.520000 2859.820000 3233.820000 ;
    END
  END io_oeb[13]
  PIN io_oeb[12]
    DIRECTION OUTPUT ;
    USE SIGNAL ;
    ANTENNADIFFAREA 0.336 LAYER met3  ;
    ANTENNAPARTIALMETALAREA 8.8584 LAYER met3  ;
    ANTENNAPARTIALMETALSIDEAREA 47.24 LAYER met3  ;
    PORT
      LAYER met3 ;
        RECT 2859.020000 2996.840000 2859.820000 2997.140000 ;
    END
  END io_oeb[12]
  PIN io_oeb[11]
    DIRECTION OUTPUT ;
    USE SIGNAL ;
    ANTENNADIFFAREA 0.336 LAYER met3  ;
    ANTENNAPARTIALMETALAREA 8.8584 LAYER met3  ;
    ANTENNAPARTIALMETALSIDEAREA 47.24 LAYER met3  ;
    PORT
      LAYER met3 ;
        RECT 2859.020000 2760.160000 2859.820000 2760.460000 ;
    END
  END io_oeb[11]
  PIN io_oeb[10]
    DIRECTION OUTPUT ;
    USE SIGNAL ;
    ANTENNADIFFAREA 0.336 LAYER met3  ;
    ANTENNAPARTIALMETALAREA 0.1644 LAYER met3  ;
    ANTENNAPARTIALMETALSIDEAREA 0.872 LAYER met3  ;
    PORT
      LAYER met3 ;
        RECT 2859.020000 2523.480000 2859.820000 2523.780000 ;
    END
  END io_oeb[10]
  PIN io_oeb[9]
    DIRECTION OUTPUT ;
    USE SIGNAL ;
    ANTENNADIFFAREA 0.336 LAYER met3  ;
    ANTENNAPARTIALMETALAREA 0.1644 LAYER met3  ;
    ANTENNAPARTIALMETALSIDEAREA 0.872 LAYER met3  ;
    PORT
      LAYER met3 ;
        RECT 2859.020000 2287.410000 2859.820000 2287.710000 ;
    END
  END io_oeb[9]
  PIN io_oeb[8]
    DIRECTION OUTPUT ;
    USE SIGNAL ;
    ANTENNADIFFAREA 0.336 LAYER met3  ;
    ANTENNAPARTIALMETALAREA 0.1644 LAYER met3  ;
    ANTENNAPARTIALMETALSIDEAREA 0.872 LAYER met3  ;
    PORT
      LAYER met3 ;
        RECT 2859.020000 2050.730000 2859.820000 2051.030000 ;
    END
  END io_oeb[8]
  PIN io_oeb[7]
    DIRECTION OUTPUT ;
    USE SIGNAL ;
    ANTENNADIFFAREA 0.336 LAYER met3  ;
    ANTENNAPARTIALMETALAREA 0.1644 LAYER met3  ;
    ANTENNAPARTIALMETALSIDEAREA 0.872 LAYER met3  ;
    PORT
      LAYER met3 ;
        RECT 2859.020000 1814.050000 2859.820000 1814.350000 ;
    END
  END io_oeb[7]
  PIN io_oeb[6]
    DIRECTION OUTPUT ;
    USE SIGNAL ;
    ANTENNADIFFAREA 0.336 LAYER met3  ;
    ANTENNAPARTIALMETALAREA 0.1644 LAYER met3  ;
    ANTENNAPARTIALMETALSIDEAREA 0.872 LAYER met3  ;
    PORT
      LAYER met3 ;
        RECT 2859.020000 1577.370000 2859.820000 1577.670000 ;
    END
  END io_oeb[6]
  PIN io_oeb[5]
    DIRECTION OUTPUT ;
    USE SIGNAL ;
    ANTENNADIFFAREA 0.336 LAYER met3  ;
    ANTENNAPARTIALMETALAREA 8.8584 LAYER met3  ;
    ANTENNAPARTIALMETALSIDEAREA 47.24 LAYER met3  ;
    PORT
      LAYER met3 ;
        RECT 2859.020000 1341.300000 2859.820000 1341.600000 ;
    END
  END io_oeb[5]
  PIN io_oeb[4]
    DIRECTION OUTPUT ;
    USE SIGNAL ;
    ANTENNADIFFAREA 0.336 LAYER met3  ;
    ANTENNAPARTIALMETALAREA 8.8584 LAYER met3  ;
    ANTENNAPARTIALMETALSIDEAREA 47.24 LAYER met3  ;
    PORT
      LAYER met3 ;
        RECT 2859.020000 1104.620000 2859.820000 1104.920000 ;
    END
  END io_oeb[4]
  PIN io_oeb[3]
    DIRECTION OUTPUT ;
    USE SIGNAL ;
    ANTENNADIFFAREA 0.336 LAYER met3  ;
    ANTENNAPARTIALMETALAREA 8.8584 LAYER met3  ;
    ANTENNAPARTIALMETALSIDEAREA 47.24 LAYER met3  ;
    PORT
      LAYER met3 ;
        RECT 2859.020000 867.940000 2859.820000 868.240000 ;
    END
  END io_oeb[3]
  PIN io_oeb[2]
    DIRECTION OUTPUT ;
    USE SIGNAL ;
    ANTENNADIFFAREA 0.336 LAYER met3  ;
    ANTENNAPARTIALMETALAREA 8.8584 LAYER met3  ;
    ANTENNAPARTIALMETALSIDEAREA 47.24 LAYER met3  ;
    PORT
      LAYER met3 ;
        RECT 2859.020000 631.260000 2859.820000 631.560000 ;
    END
  END io_oeb[2]
  PIN io_oeb[1]
    DIRECTION OUTPUT ;
    USE SIGNAL ;
    ANTENNADIFFAREA 0.336 LAYER met3  ;
    ANTENNAPARTIALMETALAREA 0.1644 LAYER met3  ;
    ANTENNAPARTIALMETALSIDEAREA 0.872 LAYER met3  ;
    PORT
      LAYER met3 ;
        RECT 2859.020000 395.190000 2859.820000 395.490000 ;
    END
  END io_oeb[1]
  PIN io_oeb[0]
    DIRECTION OUTPUT ;
    USE SIGNAL ;
    ANTENNADIFFAREA 0.336 LAYER met3  ;
    ANTENNAPARTIALMETALAREA 8.8584 LAYER met3  ;
    ANTENNAPARTIALMETALSIDEAREA 47.24 LAYER met3  ;
    PORT
      LAYER met3 ;
        RECT 2859.020000 158.510000 2859.820000 158.810000 ;
    END
  END io_oeb[0]
  PIN irq[2]
    DIRECTION OUTPUT ;
    USE SIGNAL ;
    ANTENNADIFFAREA 0.336 LAYER met2  ;
    ANTENNAPARTIALMETALAREA 4.4435 LAYER met2  ;
    ANTENNAPARTIALMETALSIDEAREA 22.1095 LAYER met2  ;
    PORT
      LAYER met2 ;
        RECT 2859.520000 0.000000 2859.660000 0.485000 ;
    END
  END irq[2]
  PIN irq[1]
    DIRECTION OUTPUT ;
    USE SIGNAL ;
    ANTENNADIFFAREA 0.336 LAYER met2  ;
    ANTENNAPARTIALMETALAREA 4.8719 LAYER met2  ;
    ANTENNAPARTIALMETALSIDEAREA 24.2515 LAYER met2  ;
    PORT
      LAYER met2 ;
        RECT 2854.000000 0.000000 2854.140000 0.485000 ;
    END
  END irq[1]
  PIN irq[0]
    DIRECTION OUTPUT ;
    USE SIGNAL ;
    ANTENNADIFFAREA 0.336 LAYER met2  ;
    ANTENNAPARTIALMETALAREA 4.1579 LAYER met2  ;
    ANTENNAPARTIALMETALSIDEAREA 20.6815 LAYER met2  ;
    PORT
      LAYER met2 ;
        RECT 2848.020000 0.000000 2848.160000 0.485000 ;
    END
  END irq[0]
  PIN wb_clk_i
    DIRECTION INPUT ;
    USE SIGNAL ;
    ANTENNAPARTIALMETALAREA 3.8402 LAYER met2  ;
    ANTENNAPARTIALMETALSIDEAREA 19.04 LAYER met2  ;
    ANTENNAPARTIALCUTAREA 0.04 LAYER via2  ;
    ANTENNAPARTIALMETALAREA 8.6748 LAYER met3  ;
    ANTENNAPARTIALMETALSIDEAREA 46.736 LAYER met3  ;
    ANTENNAMODEL OXIDE1 ;
    ANTENNAGATEAREA 0.576 LAYER met3  ;
    ANTENNAMAXAREACAR 18.0036 LAYER met3  ;
    ANTENNAMAXSIDEAREACAR 93.6597 LAYER met3  ;
    ANTENNAMAXCUTCAR 0.158681 LAYER via3  ;
    PORT
      LAYER met2 ;
        RECT 0.160000 0.000000 0.300000 0.485000 ;
    END
  END wb_clk_i
  PIN wb_rst_i
    DIRECTION INPUT ;
    USE SIGNAL ;
    ANTENNAPARTIALMETALAREA 17.2579 LAYER met2  ;
    ANTENNAPARTIALMETALSIDEAREA 84.3535 LAYER met2  ;
    ANTENNAMODEL OXIDE1 ;
    ANTENNAGATEAREA 8.2935 LAYER met2  ;
    ANTENNAMAXAREACAR 22.1735 LAYER met2  ;
    ANTENNAMAXSIDEAREACAR 108.767 LAYER met2  ;
    ANTENNAMAXCUTCAR 0.407937 LAYER via2  ;
    PORT
      LAYER met2 ;
        RECT 6.140000 0.000000 6.280000 0.485000 ;
    END
  END wb_rst_i
  PIN wbs_stb_i
    DIRECTION INPUT ;
    USE SIGNAL ;
    ANTENNAPARTIALMETALAREA 4.0627 LAYER met2  ;
    ANTENNAPARTIALMETALSIDEAREA 20.2055 LAYER met2  ;
    ANTENNAMODEL OXIDE1 ;
    ANTENNAGATEAREA 0.2475 LAYER met2  ;
    ANTENNAMAXAREACAR 25.2923 LAYER met2  ;
    ANTENNAMAXSIDEAREACAR 120.303 LAYER met2  ;
    ANTENNAMAXCUTCAR 0.207677 LAYER via2  ;
    PORT
      LAYER met2 ;
        RECT 23.620000 0.000000 23.760000 0.485000 ;
    END
  END wbs_stb_i
  PIN wbs_cyc_i
    DIRECTION INPUT ;
    USE SIGNAL ;
    ANTENNAPARTIALMETALAREA 4.1103 LAYER met2  ;
    ANTENNAPARTIALMETALSIDEAREA 20.4435 LAYER met2  ;
    ANTENNAMODEL OXIDE1 ;
    ANTENNAGATEAREA 0.2475 LAYER met2  ;
    ANTENNAMAXAREACAR 28.641 LAYER met2  ;
    ANTENNAMAXSIDEAREACAR 141.236 LAYER met2  ;
    ANTENNAMAXCUTCAR 0.207677 LAYER via2  ;
    PORT
      LAYER met2 ;
        RECT 17.640000 0.000000 17.780000 0.485000 ;
    END
  END wbs_cyc_i
  PIN wbs_we_i
    DIRECTION INPUT ;
    USE SIGNAL ;
    ANTENNAPARTIALMETALAREA 5.6487 LAYER met2  ;
    ANTENNAPARTIALMETALSIDEAREA 28.0175 LAYER met2  ;
    ANTENNAMODEL OXIDE1 ;
    ANTENNAGATEAREA 0.3735 LAYER met2  ;
    ANTENNAMAXAREACAR 85.9479 LAYER met2  ;
    ANTENNAMAXSIDEAREACAR 423.747 LAYER met2  ;
    ANTENNAMAXCUTCAR 0.407937 LAYER via2  ;
    PORT
      LAYER met2 ;
        RECT 29.600000 0.000000 29.740000 0.485000 ;
    END
  END wbs_we_i
  PIN wbs_sel_i[3]
    DIRECTION INPUT ;
    USE SIGNAL ;
    PORT
      LAYER met2 ;
        RECT 122.520000 0.000000 122.660000 0.485000 ;
    END
  END wbs_sel_i[3]
  PIN wbs_sel_i[2]
    DIRECTION INPUT ;
    USE SIGNAL ;
    PORT
      LAYER met2 ;
        RECT 99.060000 0.000000 99.200000 0.485000 ;
    END
  END wbs_sel_i[2]
  PIN wbs_sel_i[1]
    DIRECTION INPUT ;
    USE SIGNAL ;
    PORT
      LAYER met2 ;
        RECT 76.060000 0.000000 76.200000 0.485000 ;
    END
  END wbs_sel_i[1]
  PIN wbs_sel_i[0]
    DIRECTION INPUT ;
    USE SIGNAL ;
    PORT
      LAYER met2 ;
        RECT 52.600000 0.000000 52.740000 0.485000 ;
    END
  END wbs_sel_i[0]
  PIN wbs_dat_i[31]
    DIRECTION INPUT ;
    USE SIGNAL ;
    ANTENNAPARTIALMETALAREA 10.6516 LAYER met2  ;
    ANTENNAPARTIALMETALSIDEAREA 52.871 LAYER met2  ;
    ANTENNAMODEL OXIDE1 ;
    ANTENNAGATEAREA 0.702 LAYER met2  ;
    ANTENNAMAXAREACAR 46.1113 LAYER met2  ;
    ANTENNAMAXSIDEAREACAR 226.18 LAYER met2  ;
    ANTENNAPARTIALCUTAREA 0.04 LAYER via2  ;
    ANTENNAMAXCUTCAR 0.643488 LAYER via2  ;
    ANTENNAPARTIALMETALAREA 0.2509 LAYER met3  ;
    ANTENNAPARTIALMETALSIDEAREA 1.808 LAYER met3  ;
    ANTENNAGATEAREA 0.702 LAYER met3  ;
    ANTENNAMAXAREACAR 46.4687 LAYER met3  ;
    ANTENNAMAXSIDEAREACAR 228.755 LAYER met3  ;
    ANTENNAPARTIALCUTAREA 0.04 LAYER via3  ;
    ANTENNAMAXCUTCAR 0.700468 LAYER via3  ;
    ANTENNAPARTIALMETALAREA 2.1932 LAYER met4  ;
    ANTENNAPARTIALMETALSIDEAREA 11.848 LAYER met4  ;
    ANTENNAGATEAREA 0.702 LAYER met4  ;
    ANTENNAMAXAREACAR 49.5929 LAYER met4  ;
    ANTENNAMAXSIDEAREACAR 245.633 LAYER met4  ;
    ANTENNAMAXCUTCAR 0.700468 LAYER via4  ;
    PORT
      LAYER met2 ;
        RECT 604.600000 0.000000 604.740000 0.485000 ;
    END
  END wbs_dat_i[31]
  PIN wbs_dat_i[30]
    DIRECTION INPUT ;
    USE SIGNAL ;
    ANTENNAPARTIALMETALAREA 10.644 LAYER met2  ;
    ANTENNAPARTIALMETALSIDEAREA 52.941 LAYER met2  ;
    ANTENNAMODEL OXIDE1 ;
    ANTENNAGATEAREA 0.159 LAYER met2  ;
    ANTENNAMAXAREACAR 81.6318 LAYER met2  ;
    ANTENNAMAXSIDEAREACAR 402.443 LAYER met2  ;
    ANTENNAPARTIALCUTAREA 0.04 LAYER via2  ;
    ANTENNAMAXCUTCAR 0.716352 LAYER via2  ;
    ANTENNAPARTIALMETALAREA 0.26895 LAYER met3  ;
    ANTENNAPARTIALMETALSIDEAREA 1.832 LAYER met3  ;
    ANTENNAGATEAREA 0.159 LAYER met3  ;
    ANTENNAMAXAREACAR 83.3233 LAYER met3  ;
    ANTENNAMAXSIDEAREACAR 413.965 LAYER met3  ;
    ANTENNAPARTIALCUTAREA 0.04 LAYER via3  ;
    ANTENNAMAXCUTCAR 0.967925 LAYER via3  ;
    ANTENNAPARTIALMETALAREA 2.1692 LAYER met4  ;
    ANTENNAPARTIALMETALSIDEAREA 11.72 LAYER met4  ;
    ANTENNAGATEAREA 0.159 LAYER met4  ;
    ANTENNAMAXAREACAR 96.966 LAYER met4  ;
    ANTENNAMAXSIDEAREACAR 487.676 LAYER met4  ;
    ANTENNAMAXCUTCAR 0.967925 LAYER via4  ;
    PORT
      LAYER met2 ;
        RECT 587.580000 0.000000 587.720000 0.485000 ;
    END
  END wbs_dat_i[30]
  PIN wbs_dat_i[29]
    DIRECTION INPUT ;
    USE SIGNAL ;
    ANTENNAPARTIALMETALAREA 9.8594 LAYER met2  ;
    ANTENNAPARTIALMETALSIDEAREA 49.028 LAYER met2  ;
    ANTENNAMODEL OXIDE1 ;
    ANTENNAGATEAREA 0.159 LAYER met2  ;
    ANTENNAMAXAREACAR 63.6003 LAYER met2  ;
    ANTENNAMAXSIDEAREACAR 313.028 LAYER met2  ;
    ANTENNAPARTIALCUTAREA 0.04 LAYER via2  ;
    ANTENNAMAXCUTCAR 0.574843 LAYER via2  ;
    ANTENNAPARTIALMETALAREA 0.255 LAYER met3  ;
    ANTENNAPARTIALMETALSIDEAREA 1.808 LAYER met3  ;
    ANTENNAGATEAREA 0.159 LAYER met3  ;
    ANTENNAMAXAREACAR 65.2041 LAYER met3  ;
    ANTENNAMAXSIDEAREACAR 324.399 LAYER met3  ;
    ANTENNAPARTIALCUTAREA 0.04 LAYER via3  ;
    ANTENNAMAXCUTCAR 0.826415 LAYER via3  ;
    ANTENNAPARTIALMETALAREA 4.6802 LAYER met4  ;
    ANTENNAPARTIALMETALSIDEAREA 25.112 LAYER met4  ;
    ANTENNAGATEAREA 0.159 LAYER met4  ;
    ANTENNAMAXAREACAR 94.6393 LAYER met4  ;
    ANTENNAMAXSIDEAREACAR 482.336 LAYER met4  ;
    ANTENNAMAXCUTCAR 0.826415 LAYER via4  ;
    PORT
      LAYER met2 ;
        RECT 570.100000 0.000000 570.240000 0.485000 ;
    END
  END wbs_dat_i[29]
  PIN wbs_dat_i[28]
    DIRECTION INPUT ;
    USE SIGNAL ;
    ANTENNAPARTIALMETALAREA 9.4008 LAYER met2  ;
    ANTENNAPARTIALMETALSIDEAREA 46.725 LAYER met2  ;
    ANTENNAMODEL OXIDE1 ;
    ANTENNAGATEAREA 0.495 LAYER met2  ;
    ANTENNAMAXAREACAR 21.46 LAYER met2  ;
    ANTENNAMAXSIDEAREACAR 105.899 LAYER met2  ;
    ANTENNAPARTIALCUTAREA 0.04 LAYER via2  ;
    ANTENNAMAXCUTCAR 0.230101 LAYER via2  ;
    ANTENNAPARTIALMETALAREA 0.255 LAYER met3  ;
    ANTENNAPARTIALMETALSIDEAREA 1.808 LAYER met3  ;
    ANTENNAGATEAREA 0.495 LAYER met3  ;
    ANTENNAMAXAREACAR 21.9752 LAYER met3  ;
    ANTENNAMAXSIDEAREACAR 109.552 LAYER met3  ;
    ANTENNAPARTIALCUTAREA 0.04 LAYER via3  ;
    ANTENNAMAXCUTCAR 0.310909 LAYER via3  ;
    ANTENNAPARTIALMETALAREA 4.7342 LAYER met4  ;
    ANTENNAPARTIALMETALSIDEAREA 25.4 LAYER met4  ;
    ANTENNAGATEAREA 0.495 LAYER met4  ;
    ANTENNAMAXAREACAR 31.5392 LAYER met4  ;
    ANTENNAMAXSIDEAREACAR 160.865 LAYER met4  ;
    ANTENNAMAXCUTCAR 0.310909 LAYER via4  ;
    PORT
      LAYER met2 ;
        RECT 552.620000 0.000000 552.760000 0.485000 ;
    END
  END wbs_dat_i[28]
  PIN wbs_dat_i[27]
    DIRECTION INPUT ;
    USE SIGNAL ;
    ANTENNAPARTIALMETALAREA 10.3248 LAYER met2  ;
    ANTENNAPARTIALMETALSIDEAREA 51.345 LAYER met2  ;
    ANTENNAMODEL OXIDE1 ;
    ANTENNAGATEAREA 0.159 LAYER met2  ;
    ANTENNAMAXAREACAR 84.094 LAYER met2  ;
    ANTENNAMAXSIDEAREACAR 414.33 LAYER met2  ;
    ANTENNAPARTIALCUTAREA 0.04 LAYER via2  ;
    ANTENNAMAXCUTCAR 0.716352 LAYER via2  ;
    ANTENNAPARTIALMETALAREA 0.255 LAYER met3  ;
    ANTENNAPARTIALMETALSIDEAREA 1.808 LAYER met3  ;
    ANTENNAGATEAREA 0.159 LAYER met3  ;
    ANTENNAMAXAREACAR 85.6978 LAYER met3  ;
    ANTENNAMAXSIDEAREACAR 425.701 LAYER met3  ;
    ANTENNAPARTIALCUTAREA 0.04 LAYER via3  ;
    ANTENNAMAXCUTCAR 0.967925 LAYER via3  ;
    ANTENNAPARTIALMETALAREA 3.2942 LAYER met4  ;
    ANTENNAPARTIALMETALSIDEAREA 17.72 LAYER met4  ;
    ANTENNAGATEAREA 0.159 LAYER met4  ;
    ANTENNAMAXAREACAR 106.416 LAYER met4  ;
    ANTENNAMAXSIDEAREACAR 537.148 LAYER met4  ;
    ANTENNAMAXCUTCAR 0.967925 LAYER via4  ;
    PORT
      LAYER met2 ;
        RECT 535.140000 0.000000 535.280000 0.485000 ;
    END
  END wbs_dat_i[27]
  PIN wbs_dat_i[26]
    DIRECTION INPUT ;
    USE SIGNAL ;
    ANTENNAPARTIALMETALAREA 9.9888 LAYER met2  ;
    ANTENNAPARTIALMETALSIDEAREA 49.665 LAYER met2  ;
    ANTENNAMODEL OXIDE1 ;
    ANTENNAGATEAREA 0.576 LAYER met2  ;
    ANTENNAMAXAREACAR 27.0087 LAYER met2  ;
    ANTENNAMAXSIDEAREACAR 131.804 LAYER met2  ;
    ANTENNAPARTIALCUTAREA 0.04 LAYER via2  ;
    ANTENNAMAXCUTCAR 0.247917 LAYER via2  ;
    ANTENNAPARTIALMETALAREA 0.538 LAYER met3  ;
    ANTENNAPARTIALMETALSIDEAREA 3.336 LAYER met3  ;
    ANTENNAGATEAREA 0.576 LAYER met3  ;
    ANTENNAMAXAREACAR 27.9427 LAYER met3  ;
    ANTENNAMAXSIDEAREACAR 137.595 LAYER met3  ;
    ANTENNAPARTIALCUTAREA 0.04 LAYER via3  ;
    ANTENNAMAXCUTCAR 0.317361 LAYER via3  ;
    ANTENNAPARTIALMETALAREA 3.3692 LAYER met4  ;
    ANTENNAPARTIALMETALSIDEAREA 18.12 LAYER met4  ;
    ANTENNAGATEAREA 0.576 LAYER met4  ;
    ANTENNAMAXAREACAR 33.792 LAYER met4  ;
    ANTENNAMAXSIDEAREACAR 169.054 LAYER met4  ;
    ANTENNAMAXCUTCAR 0.317361 LAYER via4  ;
    PORT
      LAYER met2 ;
        RECT 517.660000 0.000000 517.800000 0.485000 ;
    END
  END wbs_dat_i[26]
  PIN wbs_dat_i[25]
    DIRECTION INPUT ;
    USE SIGNAL ;
    ANTENNAPARTIALMETALAREA 10.8112 LAYER met2  ;
    ANTENNAPARTIALMETALSIDEAREA 53.669 LAYER met2  ;
    ANTENNAMODEL OXIDE1 ;
    ANTENNAGATEAREA 0.576 LAYER met2  ;
    ANTENNAMAXAREACAR 19.8446 LAYER met2  ;
    ANTENNAMAXSIDEAREACAR 95.8134 LAYER met2  ;
    ANTENNAPARTIALCUTAREA 0.04 LAYER via2  ;
    ANTENNAMAXCUTCAR 0.158681 LAYER via2  ;
    ANTENNAPARTIALMETALAREA 0.952 LAYER met3  ;
    ANTENNAPARTIALMETALSIDEAREA 5.544 LAYER met3  ;
    ANTENNAGATEAREA 0.576 LAYER met3  ;
    ANTENNAMAXAREACAR 21.4974 LAYER met3  ;
    ANTENNAMAXSIDEAREACAR 105.438 LAYER met3  ;
    ANTENNAPARTIALCUTAREA 0.04 LAYER via3  ;
    ANTENNAMAXCUTCAR 0.228125 LAYER via3  ;
    ANTENNAPARTIALMETALAREA 2.0372 LAYER met4  ;
    ANTENNAPARTIALMETALSIDEAREA 11.016 LAYER met4  ;
    ANTENNAGATEAREA 0.576 LAYER met4  ;
    ANTENNAMAXAREACAR 25.0342 LAYER met4  ;
    ANTENNAMAXSIDEAREACAR 124.563 LAYER met4  ;
    ANTENNAMAXCUTCAR 0.228125 LAYER via4  ;
    PORT
      LAYER met2 ;
        RECT 500.180000 0.000000 500.320000 0.485000 ;
    END
  END wbs_dat_i[25]
  PIN wbs_dat_i[24]
    DIRECTION INPUT ;
    USE SIGNAL ;
    ANTENNAPARTIALMETALAREA 11.4216 LAYER met2  ;
    ANTENNAPARTIALMETALSIDEAREA 56.721 LAYER met2  ;
    ANTENNAMODEL OXIDE1 ;
    ANTENNAGATEAREA 0.159 LAYER met2  ;
    ANTENNAMAXAREACAR 74.9437 LAYER met2  ;
    ANTENNAMAXSIDEAREACAR 363.198 LAYER met2  ;
    ANTENNAPARTIALCUTAREA 0.04 LAYER via2  ;
    ANTENNAMAXCUTCAR 0.574843 LAYER via2  ;
    ANTENNAPARTIALMETALAREA 0.331 LAYER met3  ;
    ANTENNAPARTIALMETALSIDEAREA 2.232 LAYER met3  ;
    ANTENNAGATEAREA 0.159 LAYER met3  ;
    ANTENNAMAXAREACAR 77.0255 LAYER met3  ;
    ANTENNAMAXSIDEAREACAR 377.236 LAYER met3  ;
    ANTENNAPARTIALCUTAREA 0.04 LAYER via3  ;
    ANTENNAMAXCUTCAR 0.826415 LAYER via3  ;
    ANTENNAPARTIALMETALAREA 1.1762 LAYER met4  ;
    ANTENNAPARTIALMETALSIDEAREA 6.424 LAYER met4  ;
    ANTENNAGATEAREA 0.159 LAYER met4  ;
    ANTENNAMAXAREACAR 84.423 LAYER met4  ;
    ANTENNAMAXSIDEAREACAR 417.638 LAYER met4  ;
    ANTENNAMAXCUTCAR 0.826415 LAYER via4  ;
    PORT
      LAYER met2 ;
        RECT 482.700000 0.000000 482.840000 0.485000 ;
    END
  END wbs_dat_i[24]
  PIN wbs_dat_i[23]
    DIRECTION INPUT ;
    USE SIGNAL ;
    ANTENNAPARTIALMETALAREA 9.5224 LAYER met2  ;
    ANTENNAPARTIALMETALSIDEAREA 47.215 LAYER met2  ;
    ANTENNAMODEL OXIDE1 ;
    ANTENNAGATEAREA 0.576 LAYER met2  ;
    ANTENNAMAXAREACAR 24.6972 LAYER met2  ;
    ANTENNAMAXSIDEAREACAR 120.711 LAYER met2  ;
    ANTENNAPARTIALCUTAREA 0.04 LAYER via2  ;
    ANTENNAMAXCUTCAR 0.197743 LAYER via2  ;
    ANTENNAPARTIALMETALAREA 0.255 LAYER met3  ;
    ANTENNAPARTIALMETALSIDEAREA 1.808 LAYER met3  ;
    ANTENNAGATEAREA 0.576 LAYER met3  ;
    ANTENNAMAXAREACAR 25.1399 LAYER met3  ;
    ANTENNAMAXSIDEAREACAR 123.85 LAYER met3  ;
    ANTENNAPARTIALCUTAREA 0.04 LAYER via3  ;
    ANTENNAMAXCUTCAR 0.267188 LAYER via3  ;
    ANTENNAPARTIALMETALAREA 4.8602 LAYER met4  ;
    ANTENNAPARTIALMETALSIDEAREA 26.072 LAYER met4  ;
    ANTENNAGATEAREA 0.576 LAYER met4  ;
    ANTENNAMAXAREACAR 33.5778 LAYER met4  ;
    ANTENNAMAXSIDEAREACAR 169.114 LAYER met4  ;
    ANTENNAMAXCUTCAR 0.267188 LAYER via4  ;
    PORT
      LAYER met2 ;
        RECT 465.220000 0.000000 465.360000 0.485000 ;
    END
  END wbs_dat_i[23]
  PIN wbs_dat_i[22]
    DIRECTION INPUT ;
    USE SIGNAL ;
    ANTENNAPARTIALMETALAREA 10.8468 LAYER met2  ;
    ANTENNAPARTIALMETALSIDEAREA 53.837 LAYER met2  ;
    ANTENNAMODEL OXIDE1 ;
    ANTENNAGATEAREA 0.159 LAYER met2  ;
    ANTENNAMAXAREACAR 130.398 LAYER met2  ;
    ANTENNAMAXSIDEAREACAR 645.11 LAYER met2  ;
    ANTENNAPARTIALCUTAREA 0.04 LAYER via2  ;
    ANTENNAMAXCUTCAR 0.716352 LAYER via2  ;
    ANTENNAPARTIALMETALAREA 0.255 LAYER met3  ;
    ANTENNAPARTIALMETALSIDEAREA 1.808 LAYER met3  ;
    ANTENNAGATEAREA 0.159 LAYER met3  ;
    ANTENNAMAXAREACAR 132.002 LAYER met3  ;
    ANTENNAMAXSIDEAREACAR 656.481 LAYER met3  ;
    ANTENNAPARTIALCUTAREA 0.04 LAYER via3  ;
    ANTENNAMAXCUTCAR 0.967925 LAYER via3  ;
    ANTENNAPARTIALMETALAREA 2.1662 LAYER met4  ;
    ANTENNAPARTIALMETALSIDEAREA 11.704 LAYER met4  ;
    ANTENNAGATEAREA 0.159 LAYER met4  ;
    ANTENNAMAXAREACAR 145.626 LAYER met4  ;
    ANTENNAMAXSIDEAREACAR 730.091 LAYER met4  ;
    ANTENNAMAXCUTCAR 0.967925 LAYER via4  ;
    PORT
      LAYER met2 ;
        RECT 447.740000 0.000000 447.880000 0.485000 ;
    END
  END wbs_dat_i[22]
  PIN wbs_dat_i[21]
    DIRECTION INPUT ;
    USE SIGNAL ;
    ANTENNAPARTIALMETALAREA 9.5972 LAYER met2  ;
    ANTENNAPARTIALMETALSIDEAREA 47.74 LAYER met2  ;
    ANTENNAPARTIALCUTAREA 0.04 LAYER via2  ;
    ANTENNAPARTIALMETALAREA 1.2325 LAYER met3  ;
    ANTENNAPARTIALMETALSIDEAREA 6.992 LAYER met3  ;
    ANTENNAMODEL OXIDE1 ;
    ANTENNAGATEAREA 0.159 LAYER met3  ;
    ANTENNAMAXAREACAR 10.6456 LAYER met3  ;
    ANTENNAMAXSIDEAREACAR 54.0881 LAYER met3  ;
    ANTENNAPARTIALCUTAREA 0.04 LAYER via3  ;
    ANTENNAMAXCUTCAR 0.826415 LAYER via3  ;
    ANTENNAPARTIALMETALAREA 4.6802 LAYER met4  ;
    ANTENNAPARTIALMETALSIDEAREA 25.112 LAYER met4  ;
    ANTENNAGATEAREA 0.159 LAYER met4  ;
    ANTENNAMAXAREACAR 40.0808 LAYER met4  ;
    ANTENNAMAXSIDEAREACAR 212.025 LAYER met4  ;
    ANTENNAMAXCUTCAR 0.826415 LAYER via4  ;
    PORT
      LAYER met2 ;
        RECT 430.260000 0.000000 430.400000 0.485000 ;
    END
  END wbs_dat_i[21]
  PIN wbs_dat_i[20]
    DIRECTION INPUT ;
    USE SIGNAL ;
    ANTENNAPARTIALMETALAREA 9.2964 LAYER met2  ;
    ANTENNAPARTIALMETALSIDEAREA 46.095 LAYER met2  ;
    ANTENNAMODEL OXIDE1 ;
    ANTENNAGATEAREA 0.159 LAYER met2  ;
    ANTENNAMAXAREACAR 60.0594 LAYER met2  ;
    ANTENNAMAXSIDEAREACAR 294.582 LAYER met2  ;
    ANTENNAPARTIALCUTAREA 0.04 LAYER via2  ;
    ANTENNAMAXCUTCAR 0.574843 LAYER via2  ;
    ANTENNAPARTIALMETALAREA 0.255 LAYER met3  ;
    ANTENNAPARTIALMETALSIDEAREA 1.808 LAYER met3  ;
    ANTENNAGATEAREA 0.159 LAYER met3  ;
    ANTENNAMAXAREACAR 61.6632 LAYER met3  ;
    ANTENNAMAXSIDEAREACAR 305.953 LAYER met3  ;
    ANTENNAPARTIALCUTAREA 0.04 LAYER via3  ;
    ANTENNAMAXCUTCAR 0.826415 LAYER via3  ;
    ANTENNAPARTIALMETALAREA 4.7282 LAYER met4  ;
    ANTENNAPARTIALMETALSIDEAREA 25.368 LAYER met4  ;
    ANTENNAGATEAREA 0.159 LAYER met4  ;
    ANTENNAMAXAREACAR 91.4003 LAYER met4  ;
    ANTENNAMAXSIDEAREACAR 465.5 LAYER met4  ;
    ANTENNAMAXCUTCAR 0.826415 LAYER via4  ;
    PORT
      LAYER met2 ;
        RECT 413.240000 0.000000 413.380000 0.485000 ;
    END
  END wbs_dat_i[20]
  PIN wbs_dat_i[19]
    DIRECTION INPUT ;
    USE SIGNAL ;
    ANTENNAPARTIALMETALAREA 10.718 LAYER met2  ;
    ANTENNAPARTIALMETALSIDEAREA 53.193 LAYER met2  ;
    ANTENNAMODEL OXIDE1 ;
    ANTENNAGATEAREA 0.159 LAYER met2  ;
    ANTENNAMAXAREACAR 75.8664 LAYER met2  ;
    ANTENNAMAXSIDEAREACAR 369.849 LAYER met2  ;
    ANTENNAPARTIALCUTAREA 0.04 LAYER via2  ;
    ANTENNAMAXCUTCAR 0.716352 LAYER via2  ;
    ANTENNAPARTIALMETALAREA 0.255 LAYER met3  ;
    ANTENNAPARTIALMETALSIDEAREA 1.808 LAYER met3  ;
    ANTENNAGATEAREA 0.159 LAYER met3  ;
    ANTENNAMAXAREACAR 77.4701 LAYER met3  ;
    ANTENNAMAXSIDEAREACAR 381.22 LAYER met3  ;
    ANTENNAPARTIALCUTAREA 0.04 LAYER via3  ;
    ANTENNAMAXCUTCAR 0.967925 LAYER via3  ;
    ANTENNAPARTIALMETALAREA 2.1962 LAYER met4  ;
    ANTENNAPARTIALMETALSIDEAREA 11.864 LAYER met4  ;
    ANTENNAGATEAREA 0.159 LAYER met4  ;
    ANTENNAMAXAREACAR 91.2827 LAYER met4  ;
    ANTENNAMAXSIDEAREACAR 455.836 LAYER met4  ;
    ANTENNAMAXCUTCAR 0.967925 LAYER via4  ;
    PORT
      LAYER met2 ;
        RECT 395.760000 0.000000 395.900000 0.485000 ;
    END
  END wbs_dat_i[19]
  PIN wbs_dat_i[18]
    DIRECTION INPUT ;
    USE SIGNAL ;
    ANTENNAPARTIALMETALAREA 11.192 LAYER met2  ;
    ANTENNAPARTIALMETALSIDEAREA 55.573 LAYER met2  ;
    ANTENNAMODEL OXIDE1 ;
    ANTENNAGATEAREA 0.159 LAYER met2  ;
    ANTENNAMAXAREACAR 71.9814 LAYER met2  ;
    ANTENNAMAXSIDEAREACAR 354.192 LAYER met2  ;
    ANTENNAPARTIALCUTAREA 0.04 LAYER via2  ;
    ANTENNAMAXCUTCAR 0.574843 LAYER via2  ;
    ANTENNAPARTIALMETALAREA 0.255 LAYER met3  ;
    ANTENNAPARTIALMETALSIDEAREA 1.808 LAYER met3  ;
    ANTENNAGATEAREA 0.159 LAYER met3  ;
    ANTENNAMAXAREACAR 73.5852 LAYER met3  ;
    ANTENNAMAXSIDEAREACAR 365.563 LAYER met3  ;
    ANTENNAPARTIALCUTAREA 0.04 LAYER via3  ;
    ANTENNAMAXCUTCAR 0.826415 LAYER via3  ;
    ANTENNAPARTIALMETALAREA 2.2202 LAYER met4  ;
    ANTENNAPARTIALMETALSIDEAREA 11.992 LAYER met4  ;
    ANTENNAGATEAREA 0.159 LAYER met4  ;
    ANTENNAMAXAREACAR 87.5487 LAYER met4  ;
    ANTENNAMAXSIDEAREACAR 440.984 LAYER met4  ;
    ANTENNAMAXCUTCAR 0.826415 LAYER via4  ;
    PORT
      LAYER met2 ;
        RECT 378.280000 0.000000 378.420000 0.485000 ;
    END
  END wbs_dat_i[18]
  PIN wbs_dat_i[17]
    DIRECTION INPUT ;
    USE SIGNAL ;
    ANTENNAPARTIALMETALAREA 11.0212 LAYER met2  ;
    ANTENNAPARTIALMETALSIDEAREA 54.719 LAYER met2  ;
    ANTENNAMODEL OXIDE1 ;
    ANTENNAGATEAREA 0.159 LAYER met2  ;
    ANTENNAMAXAREACAR 70.9072 LAYER met2  ;
    ANTENNAMAXSIDEAREACAR 348.821 LAYER met2  ;
    ANTENNAPARTIALCUTAREA 0.04 LAYER via2  ;
    ANTENNAMAXCUTCAR 0.574843 LAYER via2  ;
    ANTENNAPARTIALMETALAREA 0.469 LAYER met3  ;
    ANTENNAPARTIALMETALSIDEAREA 2.968 LAYER met3  ;
    ANTENNAGATEAREA 0.159 LAYER met3  ;
    ANTENNAMAXAREACAR 73.8569 LAYER met3  ;
    ANTENNAMAXSIDEAREACAR 367.487 LAYER met3  ;
    ANTENNAPARTIALCUTAREA 0.04 LAYER via3  ;
    ANTENNAMAXCUTCAR 0.826415 LAYER via3  ;
    ANTENNAPARTIALMETALAREA 2.2442 LAYER met4  ;
    ANTENNAPARTIALMETALSIDEAREA 12.12 LAYER met4  ;
    ANTENNAGATEAREA 0.159 LAYER met4  ;
    ANTENNAMAXAREACAR 87.9714 LAYER met4  ;
    ANTENNAMAXSIDEAREACAR 443.714 LAYER met4  ;
    ANTENNAMAXCUTCAR 0.826415 LAYER via4  ;
    PORT
      LAYER met2 ;
        RECT 360.800000 0.000000 360.940000 0.485000 ;
    END
  END wbs_dat_i[17]
  PIN wbs_dat_i[16]
    DIRECTION INPUT ;
    USE SIGNAL ;
    ANTENNAPARTIALMETALAREA 10.5564 LAYER met2  ;
    ANTENNAPARTIALMETALSIDEAREA 52.395 LAYER met2  ;
    ANTENNAMODEL OXIDE1 ;
    ANTENNAGATEAREA 0.159 LAYER met2  ;
    ANTENNAMAXAREACAR 67.984 LAYER met2  ;
    ANTENNAMAXSIDEAREACAR 334.204 LAYER met2  ;
    ANTENNAPARTIALCUTAREA 0.04 LAYER via2  ;
    ANTENNAMAXCUTCAR 0.574843 LAYER via2  ;
    ANTENNAPARTIALMETALAREA 0.255 LAYER met3  ;
    ANTENNAPARTIALMETALSIDEAREA 1.808 LAYER met3  ;
    ANTENNAGATEAREA 0.159 LAYER met3  ;
    ANTENNAMAXAREACAR 69.5877 LAYER met3  ;
    ANTENNAMAXSIDEAREACAR 345.575 LAYER met3  ;
    ANTENNAPARTIALCUTAREA 0.04 LAYER via3  ;
    ANTENNAMAXCUTCAR 0.826415 LAYER via3  ;
    ANTENNAPARTIALMETALAREA 2.2682 LAYER met4  ;
    ANTENNAPARTIALMETALSIDEAREA 12.248 LAYER met4  ;
    ANTENNAGATEAREA 0.159 LAYER met4  ;
    ANTENNAMAXAREACAR 83.8531 LAYER met4  ;
    ANTENNAMAXSIDEAREACAR 422.607 LAYER met4  ;
    ANTENNAMAXCUTCAR 0.826415 LAYER via4  ;
    PORT
      LAYER met2 ;
        RECT 343.320000 0.000000 343.460000 0.485000 ;
    END
  END wbs_dat_i[16]
  PIN wbs_dat_i[15]
    DIRECTION INPUT ;
    USE SIGNAL ;
    ANTENNAPARTIALMETALAREA 10.716 LAYER met2  ;
    ANTENNAPARTIALMETALSIDEAREA 53.193 LAYER met2  ;
    ANTENNAMODEL OXIDE1 ;
    ANTENNAGATEAREA 0.159 LAYER met2  ;
    ANTENNAMAXAREACAR 69.7066 LAYER met2  ;
    ANTENNAMAXSIDEAREACAR 342.393 LAYER met2  ;
    ANTENNAPARTIALCUTAREA 0.04 LAYER via2  ;
    ANTENNAMAXCUTCAR 0.574843 LAYER via2  ;
    ANTENNAPARTIALMETALAREA 0.255 LAYER met3  ;
    ANTENNAPARTIALMETALSIDEAREA 1.808 LAYER met3  ;
    ANTENNAGATEAREA 0.159 LAYER met3  ;
    ANTENNAMAXAREACAR 71.3104 LAYER met3  ;
    ANTENNAMAXSIDEAREACAR 353.764 LAYER met3  ;
    ANTENNAPARTIALCUTAREA 0.04 LAYER via3  ;
    ANTENNAMAXCUTCAR 0.826415 LAYER via3  ;
    ANTENNAPARTIALMETALAREA 2.2982 LAYER met4  ;
    ANTENNAPARTIALMETALSIDEAREA 12.408 LAYER met4  ;
    ANTENNAGATEAREA 0.159 LAYER met4  ;
    ANTENNAMAXAREACAR 85.7645 LAYER met4  ;
    ANTENNAMAXSIDEAREACAR 431.802 LAYER met4  ;
    ANTENNAMAXCUTCAR 0.826415 LAYER via4  ;
    PORT
      LAYER met2 ;
        RECT 325.840000 0.000000 325.980000 0.485000 ;
    END
  END wbs_dat_i[15]
  PIN wbs_dat_i[14]
    DIRECTION INPUT ;
    USE SIGNAL ;
    ANTENNAPARTIALMETALAREA 10.0991 LAYER met2  ;
    ANTENNAPARTIALMETALSIDEAREA 50.1515 LAYER met2  ;
    ANTENNAMODEL OXIDE1 ;
    ANTENNAGATEAREA 0.3555 LAYER met2  ;
    ANTENNAMAXAREACAR 45.3883 LAYER met2  ;
    ANTENNAMAXSIDEAREACAR 217.174 LAYER met2  ;
    ANTENNAMAXCUTCAR 0.46478 LAYER via2  ;
    PORT
      LAYER met2 ;
        RECT 308.360000 0.000000 308.500000 0.485000 ;
    END
  END wbs_dat_i[14]
  PIN wbs_dat_i[13]
    DIRECTION INPUT ;
    USE SIGNAL ;
    ANTENNAPARTIALMETALAREA 9.8998 LAYER met2  ;
    ANTENNAPARTIALMETALSIDEAREA 49.112 LAYER met2  ;
    ANTENNAMODEL OXIDE1 ;
    ANTENNAGATEAREA 0.159 LAYER met2  ;
    ANTENNAMAXAREACAR 63.8544 LAYER met2  ;
    ANTENNAMAXSIDEAREACAR 313.557 LAYER met2  ;
    ANTENNAPARTIALCUTAREA 0.04 LAYER via2  ;
    ANTENNAMAXCUTCAR 0.574843 LAYER via2  ;
    ANTENNAPARTIALMETALAREA 0.814 LAYER met3  ;
    ANTENNAPARTIALMETALSIDEAREA 4.808 LAYER met3  ;
    ANTENNAGATEAREA 0.159 LAYER met3  ;
    ANTENNAMAXAREACAR 68.9739 LAYER met3  ;
    ANTENNAMAXSIDEAREACAR 343.796 LAYER met3  ;
    ANTENNAPARTIALCUTAREA 0.04 LAYER via3  ;
    ANTENNAMAXCUTCAR 0.826415 LAYER via3  ;
    ANTENNAPARTIALMETALAREA 3.5822 LAYER met4  ;
    ANTENNAPARTIALMETALSIDEAREA 19.256 LAYER met4  ;
    ANTENNAGATEAREA 0.159 LAYER met4  ;
    ANTENNAMAXAREACAR 91.5035 LAYER met4  ;
    ANTENNAMAXSIDEAREACAR 464.903 LAYER met4  ;
    ANTENNAMAXCUTCAR 0.826415 LAYER via4  ;
    PORT
      LAYER met2 ;
        RECT 290.880000 0.000000 291.020000 0.485000 ;
    END
  END wbs_dat_i[13]
  PIN wbs_dat_i[12]
    DIRECTION INPUT ;
    USE SIGNAL ;
    ANTENNAPARTIALMETALAREA 9.2775 LAYER met2  ;
    ANTENNAPARTIALMETALSIDEAREA 46.1615 LAYER met2  ;
    ANTENNAMODEL OXIDE1 ;
    ANTENNAGATEAREA 0.3555 LAYER met2  ;
    ANTENNAMAXAREACAR 27.3835 LAYER met2  ;
    ANTENNAMAXSIDEAREACAR 132.858 LAYER met2  ;
    ANTENNAMAXCUTCAR 0.144585 LAYER via2  ;
    PORT
      LAYER met2 ;
        RECT 273.400000 0.000000 273.540000 0.485000 ;
    END
  END wbs_dat_i[12]
  PIN wbs_dat_i[11]
    DIRECTION INPUT ;
    USE SIGNAL ;
    ANTENNAPARTIALMETALAREA 8.9821 LAYER met2  ;
    ANTENNAPARTIALMETALSIDEAREA 44.5235 LAYER met2  ;
    ANTENNAMODEL OXIDE1 ;
    ANTENNAGATEAREA 0.159 LAYER met2  ;
    ANTENNAMAXAREACAR 58.0827 LAYER met2  ;
    ANTENNAMAXSIDEAREACAR 284.698 LAYER met2  ;
    ANTENNAPARTIALCUTAREA 0.04 LAYER via2  ;
    ANTENNAMAXCUTCAR 0.574843 LAYER via2  ;
    ANTENNAPARTIALMETALAREA 1.021 LAYER met3  ;
    ANTENNAPARTIALMETALSIDEAREA 5.912 LAYER met3  ;
    ANTENNAGATEAREA 0.159 LAYER met3  ;
    ANTENNAMAXAREACAR 64.5041 LAYER met3  ;
    ANTENNAMAXSIDEAREACAR 321.88 LAYER met3  ;
    ANTENNAPARTIALCUTAREA 0.04 LAYER via3  ;
    ANTENNAMAXCUTCAR 0.826415 LAYER via3  ;
    ANTENNAPARTIALMETALAREA 6.2222 LAYER met4  ;
    ANTENNAPARTIALMETALSIDEAREA 33.336 LAYER met4  ;
    ANTENNAGATEAREA 0.159 LAYER met4  ;
    ANTENNAMAXAREACAR 103.637 LAYER met4  ;
    ANTENNAMAXSIDEAREACAR 531.541 LAYER met4  ;
    ANTENNAMAXCUTCAR 0.826415 LAYER via4  ;
    PORT
      LAYER met2 ;
        RECT 255.920000 0.000000 256.060000 0.485000 ;
    END
  END wbs_dat_i[11]
  PIN wbs_dat_i[10]
    DIRECTION INPUT ;
    USE SIGNAL ;
    ANTENNAPARTIALMETALAREA 9.7563 LAYER met2  ;
    ANTENNAPARTIALMETALSIDEAREA 48.5555 LAYER met2  ;
    ANTENNAMODEL OXIDE1 ;
    ANTENNAGATEAREA 0.3555 LAYER met2  ;
    ANTENNAMAXAREACAR 28.7743 LAYER met2  ;
    ANTENNAMAXSIDEAREACAR 139.179 LAYER met2  ;
    ANTENNAMAXCUTCAR 0.144585 LAYER via2  ;
    PORT
      LAYER met2 ;
        RECT 238.440000 0.000000 238.580000 0.485000 ;
    END
  END wbs_dat_i[10]
  PIN wbs_dat_i[9]
    DIRECTION INPUT ;
    USE SIGNAL ;
    ANTENNAPARTIALMETALAREA 9.6351 LAYER met2  ;
    ANTENNAPARTIALMETALSIDEAREA 47.8415 LAYER met2  ;
    ANTENNAMODEL OXIDE1 ;
    ANTENNAGATEAREA 0.3555 LAYER met2  ;
    ANTENNAMAXAREACAR 29.4133 LAYER met2  ;
    ANTENNAMAXSIDEAREACAR 142.421 LAYER met2  ;
    ANTENNAMAXCUTCAR 0.32327 LAYER via2  ;
    PORT
      LAYER met2 ;
        RECT 221.420000 0.000000 221.560000 0.485000 ;
    END
  END wbs_dat_i[9]
  PIN wbs_dat_i[8]
    DIRECTION INPUT ;
    USE SIGNAL ;
    ANTENNAPARTIALMETALAREA 9.8182 LAYER met2  ;
    ANTENNAPARTIALMETALSIDEAREA 48.93 LAYER met2  ;
    ANTENNAPARTIALCUTAREA 0.04 LAYER via2  ;
    ANTENNAPARTIALMETALAREA 0.255 LAYER met3  ;
    ANTENNAPARTIALMETALSIDEAREA 1.808 LAYER met3  ;
    ANTENNAPARTIALCUTAREA 0.04 LAYER via3  ;
    ANTENNADIFFAREA 0.8694 LAYER met4  ;
    ANTENNAPARTIALMETALAREA 3.6438 LAYER met4  ;
    ANTENNAPARTIALMETALSIDEAREA 19.904 LAYER met4  ;
    ANTENNAMODEL OXIDE1 ;
    ANTENNAGATEAREA 0.3555 LAYER met4  ;
    ANTENNAMAXAREACAR 167.251 LAYER met4  ;
    ANTENNAMAXSIDEAREACAR 787.988 LAYER met4  ;
    ANTENNAMAXCUTCAR 0.689815 LAYER via4  ;
    PORT
      LAYER met2 ;
        RECT 203.940000 0.000000 204.080000 0.485000 ;
    END
  END wbs_dat_i[8]
  PIN wbs_dat_i[7]
    DIRECTION INPUT ;
    USE SIGNAL ;
    ANTENNAPARTIALMETALAREA 10.2863 LAYER met2  ;
    ANTENNAPARTIALMETALSIDEAREA 50.8515 LAYER met2  ;
    ANTENNAMODEL OXIDE1 ;
    ANTENNAGATEAREA 0.3555 LAYER met2  ;
    ANTENNAMAXAREACAR 32.1414 LAYER met2  ;
    ANTENNAMAXSIDEAREACAR 156.08 LAYER met2  ;
    ANTENNAMAXCUTCAR 0.376081 LAYER via2  ;
    PORT
      LAYER met2 ;
        RECT 186.460000 0.000000 186.600000 0.485000 ;
    END
  END wbs_dat_i[7]
  PIN wbs_dat_i[6]
    DIRECTION INPUT ;
    USE SIGNAL ;
    ANTENNAPARTIALMETALAREA 9.2423 LAYER met2  ;
    ANTENNAPARTIALMETALSIDEAREA 45.8675 LAYER met2  ;
    ANTENNAMODEL OXIDE1 ;
    ANTENNAGATEAREA 0.3555 LAYER met2  ;
    ANTENNAMAXAREACAR 29.4216 LAYER met2  ;
    ANTENNAMAXSIDEAREACAR 137.951 LAYER met2  ;
    ANTENNAMAXCUTCAR 0.376081 LAYER via2  ;
    PORT
      LAYER met2 ;
        RECT 168.980000 0.000000 169.120000 0.485000 ;
    END
  END wbs_dat_i[6]
  PIN wbs_dat_i[5]
    DIRECTION INPUT ;
    USE SIGNAL ;
    ANTENNAPARTIALMETALAREA 1.3283 LAYER met2  ;
    ANTENNAPARTIALMETALSIDEAREA 6.4155 LAYER met2  ;
    ANTENNAMODEL OXIDE1 ;
    ANTENNAGATEAREA 0.1965 LAYER met2  ;
    ANTENNAMAXAREACAR 9.20611 LAYER met2  ;
    ANTENNAMAXSIDEAREACAR 38.4529 LAYER met2  ;
    ANTENNAMAXCUTCAR 0.261578 LAYER via2  ;
    PORT
      LAYER met2 ;
        RECT 151.500000 0.000000 151.640000 0.485000 ;
    END
  END wbs_dat_i[5]
  PIN wbs_dat_i[4]
    DIRECTION INPUT ;
    USE SIGNAL ;
    ANTENNAPARTIALMETALAREA 4.1843 LAYER met2  ;
    ANTENNAPARTIALMETALSIDEAREA 20.6955 LAYER met2  ;
    ANTENNAMODEL OXIDE1 ;
    ANTENNAGATEAREA 0.1965 LAYER met2  ;
    ANTENNAMAXAREACAR 23.4865 LAYER met2  ;
    ANTENNAMAXSIDEAREACAR 110.198 LAYER met2  ;
    ANTENNAMAXCUTCAR 0.261578 LAYER via2  ;
    PORT
      LAYER met2 ;
        RECT 134.020000 0.000000 134.160000 0.485000 ;
    END
  END wbs_dat_i[4]
  PIN wbs_dat_i[3]
    DIRECTION INPUT ;
    USE SIGNAL ;
    ANTENNAPARTIALMETALAREA 24.1871 LAYER met2  ;
    ANTENNAPARTIALMETALSIDEAREA 120.474 LAYER met2  ;
    ANTENNAMODEL OXIDE1 ;
    ANTENNAGATEAREA 0.3555 LAYER met2  ;
    ANTENNAMAXAREACAR 71.8038 LAYER met2  ;
    ANTENNAMAXSIDEAREACAR 353.334 LAYER met2  ;
    ANTENNAMAXCUTCAR 0.46478 LAYER via2  ;
    PORT
      LAYER met2 ;
        RECT 111.020000 0.000000 111.160000 0.485000 ;
    END
  END wbs_dat_i[3]
  PIN wbs_dat_i[2]
    DIRECTION INPUT ;
    USE SIGNAL ;
    ANTENNAPARTIALMETALAREA 8.7831 LAYER met2  ;
    ANTENNAPARTIALMETALSIDEAREA 43.5715 LAYER met2  ;
    ANTENNAMODEL OXIDE1 ;
    ANTENNAGATEAREA 0.159 LAYER met2  ;
    ANTENNAMAXAREACAR 60.3852 LAYER met2  ;
    ANTENNAMAXSIDEAREACAR 296.057 LAYER met2  ;
    ANTENNAMAXCUTCAR 0.32327 LAYER via2  ;
    PORT
      LAYER met2 ;
        RECT 87.560000 0.000000 87.700000 0.485000 ;
    END
  END wbs_dat_i[2]
  PIN wbs_dat_i[1]
    DIRECTION INPUT ;
    USE SIGNAL ;
    ANTENNAPARTIALMETALAREA 7.2014 LAYER met2  ;
    ANTENNAPARTIALMETALSIDEAREA 35.728 LAYER met2  ;
    ANTENNAPARTIALCUTAREA 0.04 LAYER via2  ;
    ANTENNAPARTIALMETALAREA 2.0508 LAYER met3  ;
    ANTENNAPARTIALMETALSIDEAREA 11.408 LAYER met3  ;
    ANTENNAMODEL OXIDE1 ;
    ANTENNAGATEAREA 0.315 LAYER met3  ;
    ANTENNAMAXAREACAR 8.9254 LAYER met3  ;
    ANTENNAMAXSIDEAREACAR 44.6381 LAYER met3  ;
    ANTENNAMAXCUTCAR 0.290159 LAYER via3  ;
    PORT
      LAYER met2 ;
        RECT 64.100000 0.000000 64.240000 0.485000 ;
    END
  END wbs_dat_i[1]
  PIN wbs_dat_i[0]
    DIRECTION INPUT ;
    USE SIGNAL ;
    ANTENNAPARTIALMETALAREA 10.5799 LAYER met2  ;
    ANTENNAPARTIALMETALSIDEAREA 52.4475 LAYER met2  ;
    ANTENNAMODEL OXIDE1 ;
    ANTENNAGATEAREA 0.393 LAYER met2  ;
    ANTENNAMAXAREACAR 33.3316 LAYER met2  ;
    ANTENNAMAXSIDEAREACAR 162.719 LAYER met2  ;
    ANTENNAMAXCUTCAR 0.261578 LAYER via2  ;
    PORT
      LAYER met2 ;
        RECT 41.100000 0.000000 41.240000 0.485000 ;
    END
  END wbs_dat_i[0]
  PIN wbs_adr_i[31]
    DIRECTION INPUT ;
    USE SIGNAL ;
    ANTENNAPARTIALMETALAREA 4.4699 LAYER met2  ;
    ANTENNAPARTIALMETALSIDEAREA 22.1235 LAYER met2  ;
    ANTENNAMODEL OXIDE1 ;
    ANTENNAGATEAREA 0.2475 LAYER met2  ;
    ANTENNAMAXAREACAR 31.8044 LAYER met2  ;
    ANTENNAMAXSIDEAREACAR 151.883 LAYER met2  ;
    ANTENNAMAXCUTCAR 0.207677 LAYER via2  ;
    PORT
      LAYER met2 ;
        RECT 599.080000 0.000000 599.220000 0.485000 ;
    END
  END wbs_adr_i[31]
  PIN wbs_adr_i[30]
    DIRECTION INPUT ;
    USE SIGNAL ;
    ANTENNAPARTIALMETALAREA 1.5187 LAYER met2  ;
    ANTENNAPARTIALMETALSIDEAREA 7.3675 LAYER met2  ;
    ANTENNAMODEL OXIDE1 ;
    ANTENNAGATEAREA 0.2475 LAYER met2  ;
    ANTENNAMAXAREACAR 8.39879 LAYER met2  ;
    ANTENNAMAXSIDEAREACAR 34.5455 LAYER met2  ;
    ANTENNAMAXCUTCAR 0.207677 LAYER via2  ;
    PORT
      LAYER met2 ;
        RECT 581.600000 0.000000 581.740000 0.485000 ;
    END
  END wbs_adr_i[30]
  PIN wbs_adr_i[29]
    DIRECTION INPUT ;
    USE SIGNAL ;
    ANTENNAPARTIALMETALAREA 4.1103 LAYER met2  ;
    ANTENNAPARTIALMETALSIDEAREA 20.4435 LAYER met2  ;
    ANTENNAMODEL OXIDE1 ;
    ANTENNAGATEAREA 0.2475 LAYER met2  ;
    ANTENNAMAXAREACAR 30.2022 LAYER met2  ;
    ANTENNAMAXSIDEAREACAR 149.042 LAYER met2  ;
    ANTENNAMAXCUTCAR 0.207677 LAYER via2  ;
    PORT
      LAYER met2 ;
        RECT 564.120000 0.000000 564.260000 0.485000 ;
    END
  END wbs_adr_i[29]
  PIN wbs_adr_i[28]
    DIRECTION INPUT ;
    USE SIGNAL ;
    ANTENNAPARTIALMETALAREA 4.0627 LAYER met2  ;
    ANTENNAPARTIALMETALSIDEAREA 20.2055 LAYER met2  ;
    ANTENNAMODEL OXIDE1 ;
    ANTENNAGATEAREA 0.2475 LAYER met2  ;
    ANTENNAMAXAREACAR 21.0846 LAYER met2  ;
    ANTENNAMAXSIDEAREACAR 100.473 LAYER met2  ;
    ANTENNAMAXCUTCAR 0.207677 LAYER via2  ;
    PORT
      LAYER met2 ;
        RECT 546.640000 0.000000 546.780000 0.485000 ;
    END
  END wbs_adr_i[28]
  PIN wbs_adr_i[27]
    DIRECTION INPUT ;
    USE SIGNAL ;
    ANTENNAPARTIALMETALAREA 4.1843 LAYER met2  ;
    ANTENNAPARTIALMETALSIDEAREA 20.6955 LAYER met2  ;
    ANTENNAMODEL OXIDE1 ;
    ANTENNAGATEAREA 0.2475 LAYER met2  ;
    ANTENNAMAXAREACAR 18.1855 LAYER met2  ;
    ANTENNAMAXSIDEAREACAR 87.4424 LAYER met2  ;
    ANTENNAMAXCUTCAR 0.207677 LAYER via2  ;
    PORT
      LAYER met2 ;
        RECT 529.160000 0.000000 529.300000 0.485000 ;
    END
  END wbs_adr_i[27]
  PIN wbs_adr_i[26]
    DIRECTION INPUT ;
    USE SIGNAL ;
    ANTENNAPARTIALMETALAREA 4.2055 LAYER met2  ;
    ANTENNAPARTIALMETALSIDEAREA 20.9195 LAYER met2  ;
    ANTENNAMODEL OXIDE1 ;
    ANTENNAGATEAREA 0.2475 LAYER met2  ;
    ANTENNAMAXAREACAR 27.5859 LAYER met2  ;
    ANTENNAMAXSIDEAREACAR 129.749 LAYER met2  ;
    ANTENNAMAXCUTCAR 0.207677 LAYER via2  ;
    PORT
      LAYER met2 ;
        RECT 511.680000 0.000000 511.820000 0.485000 ;
    END
  END wbs_adr_i[26]
  PIN wbs_adr_i[25]
    DIRECTION INPUT ;
    USE SIGNAL ;
    ANTENNAPARTIALMETALAREA 4.3819 LAYER met2  ;
    ANTENNAPARTIALMETALSIDEAREA 21.8015 LAYER met2  ;
    ANTENNAMODEL OXIDE1 ;
    ANTENNAGATEAREA 0.2475 LAYER met2  ;
    ANTENNAMAXAREACAR 20.5245 LAYER met2  ;
    ANTENNAMAXSIDEAREACAR 95.3737 LAYER met2  ;
    ANTENNAMAXCUTCAR 0.207677 LAYER via2  ;
    PORT
      LAYER met2 ;
        RECT 494.200000 0.000000 494.340000 0.485000 ;
    END
  END wbs_adr_i[25]
  PIN wbs_adr_i[24]
    DIRECTION INPUT ;
    USE SIGNAL ;
    ANTENNAPARTIALMETALAREA 4.3271 LAYER met2  ;
    ANTENNAPARTIALMETALSIDEAREA 21.4095 LAYER met2  ;
    ANTENNAMODEL OXIDE1 ;
    ANTENNAGATEAREA 0.2475 LAYER met2  ;
    ANTENNAMAXAREACAR 19.4525 LAYER met2  ;
    ANTENNAMAXSIDEAREACAR 90.396 LAYER met2  ;
    ANTENNAMAXCUTCAR 0.207677 LAYER via2  ;
    PORT
      LAYER met2 ;
        RECT 476.720000 0.000000 476.860000 0.485000 ;
    END
  END wbs_adr_i[24]
  PIN wbs_adr_i[23]
    DIRECTION INPUT ;
    USE SIGNAL ;
    ANTENNAPARTIALMETALAREA 4.0627 LAYER met2  ;
    ANTENNAPARTIALMETALSIDEAREA 20.2055 LAYER met2  ;
    ANTENNAMODEL OXIDE1 ;
    ANTENNAGATEAREA 0.2475 LAYER met2  ;
    ANTENNAMAXAREACAR 30.036 LAYER met2  ;
    ANTENNAMAXSIDEAREACAR 145.228 LAYER met2  ;
    ANTENNAMAXCUTCAR 0.207677 LAYER via2  ;
    PORT
      LAYER met2 ;
        RECT 459.700000 0.000000 459.840000 0.485000 ;
    END
  END wbs_adr_i[23]
  PIN wbs_adr_i[22]
    DIRECTION INPUT ;
    USE SIGNAL ;
    ANTENNAPARTIALMETALAREA 4.2055 LAYER met2  ;
    ANTENNAPARTIALMETALSIDEAREA 20.9195 LAYER met2  ;
    ANTENNAMODEL OXIDE1 ;
    ANTENNAGATEAREA 0.2475 LAYER met2  ;
    ANTENNAMAXAREACAR 21.6332 LAYER met2  ;
    ANTENNAMAXSIDEAREACAR 100.917 LAYER met2  ;
    ANTENNAMAXCUTCAR 0.207677 LAYER via2  ;
    PORT
      LAYER met2 ;
        RECT 442.220000 0.000000 442.360000 0.485000 ;
    END
  END wbs_adr_i[22]
  PIN wbs_adr_i[21]
    DIRECTION INPUT ;
    USE SIGNAL ;
    ANTENNAPARTIALMETALAREA 4.2055 LAYER met2  ;
    ANTENNAPARTIALMETALSIDEAREA 20.9195 LAYER met2  ;
    ANTENNAMODEL OXIDE1 ;
    ANTENNAGATEAREA 0.2475 LAYER met2  ;
    ANTENNAMAXAREACAR 26.3297 LAYER met2  ;
    ANTENNAMAXSIDEAREACAR 124.986 LAYER met2  ;
    ANTENNAMAXCUTCAR 0.207677 LAYER via2  ;
    PORT
      LAYER met2 ;
        RECT 424.740000 0.000000 424.880000 0.485000 ;
    END
  END wbs_adr_i[21]
  PIN wbs_adr_i[20]
    DIRECTION INPUT ;
    USE SIGNAL ;
    ANTENNAPARTIALMETALAREA 4.9935 LAYER met2  ;
    ANTENNAPARTIALMETALSIDEAREA 24.7415 LAYER met2  ;
    ANTENNAMODEL OXIDE1 ;
    ANTENNAGATEAREA 0.2475 LAYER met2  ;
    ANTENNAMAXAREACAR 22.4505 LAYER met2  ;
    ANTENNAMAXSIDEAREACAR 106.747 LAYER met2  ;
    ANTENNAMAXCUTCAR 0.207677 LAYER via2  ;
    PORT
      LAYER met2 ;
        RECT 407.260000 0.000000 407.400000 0.485000 ;
    END
  END wbs_adr_i[20]
  PIN wbs_adr_i[19]
    DIRECTION INPUT ;
    USE SIGNAL ;
    ANTENNAPARTIALMETALAREA 4.9935 LAYER met2  ;
    ANTENNAPARTIALMETALSIDEAREA 24.7415 LAYER met2  ;
    ANTENNAMODEL OXIDE1 ;
    ANTENNAGATEAREA 0.2475 LAYER met2  ;
    ANTENNAMAXAREACAR 23.2311 LAYER met2  ;
    ANTENNAMAXSIDEAREACAR 110.651 LAYER met2  ;
    ANTENNAMAXCUTCAR 0.207677 LAYER via2  ;
    PORT
      LAYER met2 ;
        RECT 389.780000 0.000000 389.920000 0.485000 ;
    END
  END wbs_adr_i[19]
  PIN wbs_adr_i[18]
    DIRECTION INPUT ;
    USE SIGNAL ;
    ANTENNAPARTIALMETALAREA 4.0627 LAYER met2  ;
    ANTENNAPARTIALMETALSIDEAREA 20.2055 LAYER met2  ;
    ANTENNAMODEL OXIDE1 ;
    ANTENNAGATEAREA 0.2475 LAYER met2  ;
    ANTENNAMAXAREACAR 32.1131 LAYER met2  ;
    ANTENNAMAXSIDEAREACAR 153.398 LAYER met2  ;
    ANTENNAMAXCUTCAR 0.207677 LAYER via2  ;
    PORT
      LAYER met2 ;
        RECT 372.300000 0.000000 372.440000 0.485000 ;
    END
  END wbs_adr_i[18]
  PIN wbs_adr_i[17]
    DIRECTION INPUT ;
    USE SIGNAL ;
    ANTENNAPARTIALMETALAREA 4.3607 LAYER met2  ;
    ANTENNAPARTIALMETALSIDEAREA 21.5775 LAYER met2  ;
    ANTENNAMODEL OXIDE1 ;
    ANTENNAGATEAREA 0.2475 LAYER met2  ;
    ANTENNAMAXAREACAR 19.5883 LAYER met2  ;
    ANTENNAMAXSIDEAREACAR 91.0747 LAYER met2  ;
    ANTENNAMAXCUTCAR 0.207677 LAYER via2  ;
    PORT
      LAYER met2 ;
        RECT 354.820000 0.000000 354.960000 0.485000 ;
    END
  END wbs_adr_i[17]
  PIN wbs_adr_i[16]
    DIRECTION INPUT ;
    USE SIGNAL ;
    ANTENNAPARTIALMETALAREA 4.1103 LAYER met2  ;
    ANTENNAPARTIALMETALSIDEAREA 20.4435 LAYER met2  ;
    ANTENNAMODEL OXIDE1 ;
    ANTENNAGATEAREA 0.2475 LAYER met2  ;
    ANTENNAMAXAREACAR 39.8432 LAYER met2  ;
    ANTENNAMAXSIDEAREACAR 192.554 LAYER met2  ;
    ANTENNAMAXCUTCAR 0.207677 LAYER via2  ;
    PORT
      LAYER met2 ;
        RECT 337.340000 0.000000 337.480000 0.485000 ;
    END
  END wbs_adr_i[16]
  PIN wbs_adr_i[15]
    DIRECTION INPUT ;
    USE SIGNAL ;
    ANTENNAPARTIALMETALAREA 4.2867 LAYER met2  ;
    ANTENNAPARTIALMETALSIDEAREA 21.3255 LAYER met2  ;
    ANTENNAMODEL OXIDE1 ;
    ANTENNAGATEAREA 0.2475 LAYER met2  ;
    ANTENNAMAXAREACAR 27.6432 LAYER met2  ;
    ANTENNAMAXSIDEAREACAR 133.265 LAYER met2  ;
    ANTENNAMAXCUTCAR 0.207677 LAYER via2  ;
    PORT
      LAYER met2 ;
        RECT 319.860000 0.000000 320.000000 0.485000 ;
    END
  END wbs_adr_i[15]
  PIN wbs_adr_i[14]
    DIRECTION INPUT ;
    USE SIGNAL ;
    ANTENNAPARTIALMETALAREA 4.1579 LAYER met2  ;
    ANTENNAPARTIALMETALSIDEAREA 20.6815 LAYER met2  ;
    ANTENNAMODEL OXIDE1 ;
    ANTENNAGATEAREA 0.2475 LAYER met2  ;
    ANTENNAMAXAREACAR 19.5686 LAYER met2  ;
    ANTENNAMAXSIDEAREACAR 90.5939 LAYER met2  ;
    ANTENNAMAXCUTCAR 0.207677 LAYER via2  ;
    PORT
      LAYER met2 ;
        RECT 302.380000 0.000000 302.520000 0.485000 ;
    END
  END wbs_adr_i[14]
  PIN wbs_adr_i[13]
    DIRECTION INPUT ;
    USE SIGNAL ;
    ANTENNAPARTIALMETALAREA 4.2055 LAYER met2  ;
    ANTENNAPARTIALMETALSIDEAREA 20.9195 LAYER met2  ;
    ANTENNAMODEL OXIDE1 ;
    ANTENNAGATEAREA 0.2475 LAYER met2  ;
    ANTENNAMAXAREACAR 32.375 LAYER met2  ;
    ANTENNAMAXSIDEAREACAR 154.626 LAYER met2  ;
    ANTENNAMAXCUTCAR 0.207677 LAYER via2  ;
    PORT
      LAYER met2 ;
        RECT 285.360000 0.000000 285.500000 0.485000 ;
    END
  END wbs_adr_i[13]
  PIN wbs_adr_i[12]
    DIRECTION INPUT ;
    USE SIGNAL ;
    ANTENNAPARTIALMETALAREA 4.0891 LAYER met2  ;
    ANTENNAPARTIALMETALSIDEAREA 20.2195 LAYER met2  ;
    ANTENNAMODEL OXIDE1 ;
    ANTENNAGATEAREA 0.2475 LAYER met2  ;
    ANTENNAMAXAREACAR 18.7842 LAYER met2  ;
    ANTENNAMAXSIDEAREACAR 86.4727 LAYER met2  ;
    ANTENNAMAXCUTCAR 0.207677 LAYER via2  ;
    PORT
      LAYER met2 ;
        RECT 267.880000 0.000000 268.020000 0.485000 ;
    END
  END wbs_adr_i[12]
  PIN wbs_adr_i[11]
    DIRECTION INPUT ;
    USE SIGNAL ;
    ANTENNAPARTIALMETALAREA 4.0627 LAYER met2  ;
    ANTENNAPARTIALMETALSIDEAREA 20.2055 LAYER met2  ;
    ANTENNAMODEL OXIDE1 ;
    ANTENNAGATEAREA 0.2475 LAYER met2  ;
    ANTENNAMAXAREACAR 44.9835 LAYER met2  ;
    ANTENNAMAXSIDEAREACAR 217.669 LAYER met2  ;
    ANTENNAMAXCUTCAR 0.207677 LAYER via2  ;
    PORT
      LAYER met2 ;
        RECT 250.400000 0.000000 250.540000 0.485000 ;
    END
  END wbs_adr_i[11]
  PIN wbs_adr_i[10]
    DIRECTION INPUT ;
    USE SIGNAL ;
    ANTENNAPARTIALMETALAREA 4.9714 LAYER met2  ;
    ANTENNAPARTIALMETALSIDEAREA 24.696 LAYER met2  ;
    ANTENNAPARTIALCUTAREA 0.04 LAYER via2  ;
    ANTENNAPARTIALMETALAREA 9.5928 LAYER met3  ;
    ANTENNAPARTIALMETALSIDEAREA 51.632 LAYER met3  ;
    ANTENNAMODEL OXIDE1 ;
    ANTENNAGATEAREA 0.7425 LAYER met3  ;
    ANTENNAMAXAREACAR 17.8117 LAYER met3  ;
    ANTENNAMAXSIDEAREACAR 90.0249 LAYER met3  ;
    ANTENNAMAXCUTCAR 0.261549 LAYER via3  ;
    PORT
      LAYER met2 ;
        RECT 232.920000 0.000000 233.060000 0.485000 ;
    END
  END wbs_adr_i[10]
  PIN wbs_adr_i[9]
    DIRECTION INPUT ;
    USE SIGNAL ;
    ANTENNAPARTIALMETALAREA 4.8983 LAYER met2  ;
    ANTENNAPARTIALMETALSIDEAREA 24.2655 LAYER met2  ;
    ANTENNAMODEL OXIDE1 ;
    ANTENNAGATEAREA 0.495 LAYER met2  ;
    ANTENNAMAXAREACAR 34.3679 LAYER met2  ;
    ANTENNAMAXSIDEAREACAR 169.623 LAYER met2  ;
    ANTENNAMAXCUTCAR 0.298586 LAYER via2  ;
    PORT
      LAYER met2 ;
        RECT 215.440000 0.000000 215.580000 0.485000 ;
    END
  END wbs_adr_i[9]
  PIN wbs_adr_i[8]
    DIRECTION INPUT ;
    USE SIGNAL ;
    ANTENNAPARTIALMETALAREA 5.2051 LAYER met2  ;
    ANTENNAPARTIALMETALSIDEAREA 25.9175 LAYER met2  ;
    ANTENNAMODEL OXIDE1 ;
    ANTENNAGATEAREA 0.315 LAYER met2  ;
    ANTENNAMAXAREACAR 24.5857 LAYER met2  ;
    ANTENNAMAXSIDEAREACAR 116.546 LAYER met2  ;
    ANTENNAMAXCUTCAR 0.163175 LAYER via2  ;
    PORT
      LAYER met2 ;
        RECT 197.960000 0.000000 198.100000 0.485000 ;
    END
  END wbs_adr_i[8]
  PIN wbs_adr_i[7]
    DIRECTION INPUT ;
    USE SIGNAL ;
    ANTENNAPARTIALMETALAREA 6.3123 LAYER met2  ;
    ANTENNAPARTIALMETALSIDEAREA 31.3355 LAYER met2  ;
    ANTENNAMODEL OXIDE1 ;
    ANTENNAGATEAREA 0.495 LAYER met2  ;
    ANTENNAMAXAREACAR 56.5994 LAYER met2  ;
    ANTENNAMAXSIDEAREACAR 279.458 LAYER met2  ;
    ANTENNAMAXCUTCAR 0.298586 LAYER via2  ;
    PORT
      LAYER met2 ;
        RECT 180.480000 0.000000 180.620000 0.485000 ;
    END
  END wbs_adr_i[7]
  PIN wbs_adr_i[6]
    DIRECTION INPUT ;
    USE SIGNAL ;
    ANTENNAPARTIALMETALAREA 5.5859 LAYER met2  ;
    ANTENNAPARTIALMETALSIDEAREA 27.8215 LAYER met2  ;
    ANTENNAMODEL OXIDE1 ;
    ANTENNAGATEAREA 0.315 LAYER met2  ;
    ANTENNAMAXAREACAR 21.3483 LAYER met2  ;
    ANTENNAMAXSIDEAREACAR 103.289 LAYER met2  ;
    ANTENNAMAXCUTCAR 0.163175 LAYER via2  ;
    PORT
      LAYER met2 ;
        RECT 163.000000 0.000000 163.140000 0.485000 ;
    END
  END wbs_adr_i[6]
  PIN wbs_adr_i[5]
    DIRECTION INPUT ;
    USE SIGNAL ;
    ANTENNAPARTIALMETALAREA 7.9307 LAYER met2  ;
    ANTENNAPARTIALMETALSIDEAREA 39.4275 LAYER met2  ;
    ANTENNAMODEL OXIDE1 ;
    ANTENNAGATEAREA 0.495 LAYER met2  ;
    ANTENNAMAXAREACAR 19.0131 LAYER met2  ;
    ANTENNAMAXSIDEAREACAR 88.1657 LAYER met2  ;
    ANTENNAMAXCUTCAR 0.162222 LAYER via2  ;
    PORT
      LAYER met2 ;
        RECT 145.520000 0.000000 145.660000 0.485000 ;
    END
  END wbs_adr_i[5]
  PIN wbs_adr_i[4]
    DIRECTION INPUT ;
    USE SIGNAL ;
    ANTENNAPARTIALMETALAREA 7.5719 LAYER met2  ;
    ANTENNAPARTIALMETALSIDEAREA 37.3975 LAYER met2  ;
    ANTENNAMODEL OXIDE1 ;
    ANTENNAGATEAREA 0.441 LAYER met2  ;
    ANTENNAMAXAREACAR 25.9627 LAYER met2  ;
    ANTENNAMAXSIDEAREACAR 116.54 LAYER met2  ;
    ANTENNAMAXCUTCAR 0.586508 LAYER via2  ;
    PORT
      LAYER met2 ;
        RECT 128.040000 0.000000 128.180000 0.485000 ;
    END
  END wbs_adr_i[4]
  PIN wbs_adr_i[3]
    DIRECTION INPUT ;
    USE SIGNAL ;
    ANTENNAPARTIALMETALAREA 8.6143 LAYER met2  ;
    ANTENNAPARTIALMETALSIDEAREA 42.6195 LAYER met2  ;
    ANTENNAMODEL OXIDE1 ;
    ANTENNAGATEAREA 0.621 LAYER met2  ;
    ANTENNAMAXAREACAR 21.1534 LAYER met2  ;
    ANTENNAMAXSIDEAREACAR 92.7574 LAYER met2  ;
    ANTENNAMAXCUTCAR 0.586508 LAYER via2  ;
    PORT
      LAYER met2 ;
        RECT 105.040000 0.000000 105.180000 0.485000 ;
    END
  END wbs_adr_i[3]
  PIN wbs_adr_i[2]
    DIRECTION INPUT ;
    USE SIGNAL ;
    ANTENNAPARTIALMETALAREA 9.2471 LAYER met2  ;
    ANTENNAPARTIALMETALSIDEAREA 45.7835 LAYER met2  ;
    ANTENNAMODEL OXIDE1 ;
    ANTENNAGATEAREA 0.936 LAYER met2  ;
    ANTENNAMAXAREACAR 17.5152 LAYER met2  ;
    ANTENNAMAXSIDEAREACAR 83.7798 LAYER met2  ;
    ANTENNAMAXCUTCAR 0.407937 LAYER via2  ;
    PORT
      LAYER met2 ;
        RECT 81.580000 0.000000 81.720000 0.485000 ;
    END
  END wbs_adr_i[2]
  PIN wbs_adr_i[1]
    DIRECTION INPUT ;
    USE SIGNAL ;
    ANTENNAPARTIALMETALAREA 4.3607 LAYER met2  ;
    ANTENNAPARTIALMETALSIDEAREA 21.5775 LAYER met2  ;
    ANTENNAMODEL OXIDE1 ;
    ANTENNAGATEAREA 0.2475 LAYER met2  ;
    ANTENNAMAXAREACAR 18.6966 LAYER met2  ;
    ANTENNAMAXSIDEAREACAR 90.2707 LAYER met2  ;
    ANTENNAMAXCUTCAR 0.207677 LAYER via2  ;
    PORT
      LAYER met2 ;
        RECT 58.580000 0.000000 58.720000 0.485000 ;
    END
  END wbs_adr_i[1]
  PIN wbs_adr_i[0]
    DIRECTION INPUT ;
    USE SIGNAL ;
    ANTENNAPARTIALMETALAREA 1.4235 LAYER met2  ;
    ANTENNAPARTIALMETALSIDEAREA 6.8915 LAYER met2  ;
    ANTENNAMODEL OXIDE1 ;
    ANTENNAGATEAREA 0.2475 LAYER met2  ;
    ANTENNAMAXAREACAR 7.39556 LAYER met2  ;
    ANTENNAMAXSIDEAREACAR 31.3859 LAYER met2  ;
    ANTENNAMAXCUTCAR 0.207677 LAYER via2  ;
    PORT
      LAYER met2 ;
        RECT 35.120000 0.000000 35.260000 0.485000 ;
    END
  END wbs_adr_i[0]
  PIN wbs_ack_o
    DIRECTION OUTPUT ;
    USE SIGNAL ;
    ANTENNADIFFAREA 0.429 LAYER met2  ;
    ANTENNAPARTIALMETALAREA 5.8237 LAYER met2  ;
    ANTENNAPARTIALMETALSIDEAREA 28.8925 LAYER met2  ;
    ANTENNAMODEL OXIDE1 ;
    ANTENNAGATEAREA 0.495 LAYER met2  ;
    ANTENNAMAXAREACAR 91.4467 LAYER met2  ;
    ANTENNAMAXSIDEAREACAR 452.544 LAYER met2  ;
    ANTENNAMAXCUTCAR 0.298586 LAYER via2  ;
    PORT
      LAYER met2 ;
        RECT 12.120000 0.000000 12.260000 0.485000 ;
    END
  END wbs_ack_o
  PIN wbs_dat_o[31]
    DIRECTION OUTPUT ;
    USE SIGNAL ;
    ANTENNADIFFAREA 0.429 LAYER met2  ;
    ANTENNAPARTIALMETALAREA 4.8719 LAYER met2  ;
    ANTENNAPARTIALMETALSIDEAREA 24.2515 LAYER met2  ;
    PORT
      LAYER met2 ;
        RECT 610.580000 0.000000 610.720000 0.485000 ;
    END
  END wbs_dat_o[31]
  PIN wbs_dat_o[30]
    DIRECTION OUTPUT ;
    USE SIGNAL ;
    ANTENNADIFFAREA 0.429 LAYER met2  ;
    ANTENNAPARTIALMETALAREA 5.2527 LAYER met2  ;
    ANTENNAPARTIALMETALSIDEAREA 26.1555 LAYER met2  ;
    PORT
      LAYER met2 ;
        RECT 593.100000 0.000000 593.240000 0.485000 ;
    END
  END wbs_dat_o[30]
  PIN wbs_dat_o[29]
    DIRECTION OUTPUT ;
    USE SIGNAL ;
    ANTENNADIFFAREA 0.429 LAYER met2  ;
    ANTENNAPARTIALMETALAREA 5.9667 LAYER met2  ;
    ANTENNAPARTIALMETALSIDEAREA 29.7255 LAYER met2  ;
    PORT
      LAYER met2 ;
        RECT 575.620000 0.000000 575.760000 0.485000 ;
    END
  END wbs_dat_o[29]
  PIN wbs_dat_o[28]
    DIRECTION OUTPUT ;
    USE SIGNAL ;
    ANTENNADIFFAREA 0.429 LAYER met2  ;
    ANTENNAPARTIALMETALAREA 6.3475 LAYER met2  ;
    ANTENNAPARTIALMETALSIDEAREA 31.6295 LAYER met2  ;
    PORT
      LAYER met2 ;
        RECT 558.140000 0.000000 558.280000 0.485000 ;
    END
  END wbs_dat_o[28]
  PIN wbs_dat_o[27]
    DIRECTION OUTPUT ;
    USE SIGNAL ;
    ANTENNADIFFAREA 0.429 LAYER met2  ;
    ANTENNAPARTIALMETALAREA 6.3475 LAYER met2  ;
    ANTENNAPARTIALMETALSIDEAREA 31.6295 LAYER met2  ;
    PORT
      LAYER met2 ;
        RECT 540.660000 0.000000 540.800000 0.485000 ;
    END
  END wbs_dat_o[27]
  PIN wbs_dat_o[26]
    DIRECTION OUTPUT ;
    USE SIGNAL ;
    ANTENNADIFFAREA 0.429 LAYER met2  ;
    ANTENNAPARTIALMETALAREA 6.0955 LAYER met2  ;
    ANTENNAPARTIALMETALSIDEAREA 30.3695 LAYER met2  ;
    PORT
      LAYER met2 ;
        RECT 523.640000 0.000000 523.780000 0.485000 ;
    END
  END wbs_dat_o[26]
  PIN wbs_dat_o[25]
    DIRECTION OUTPUT ;
    USE SIGNAL ;
    ANTENNADIFFAREA 0.429 LAYER met2  ;
    ANTENNAPARTIALMETALAREA 5.9667 LAYER met2  ;
    ANTENNAPARTIALMETALSIDEAREA 29.7255 LAYER met2  ;
    PORT
      LAYER met2 ;
        RECT 506.160000 0.000000 506.300000 0.485000 ;
    END
  END wbs_dat_o[25]
  PIN wbs_dat_o[24]
    DIRECTION OUTPUT ;
    USE SIGNAL ;
    ANTENNADIFFAREA 0.429 LAYER met2  ;
    ANTENNAPARTIALMETALAREA 5.9667 LAYER met2  ;
    ANTENNAPARTIALMETALSIDEAREA 29.7255 LAYER met2  ;
    PORT
      LAYER met2 ;
        RECT 488.680000 0.000000 488.820000 0.485000 ;
    END
  END wbs_dat_o[24]
  PIN wbs_dat_o[23]
    DIRECTION OUTPUT ;
    USE SIGNAL ;
    ANTENNADIFFAREA 0.429 LAYER met2  ;
    ANTENNAPARTIALMETALAREA 6.1599 LAYER met2  ;
    ANTENNAPARTIALMETALSIDEAREA 30.6915 LAYER met2  ;
    PORT
      LAYER met2 ;
        RECT 471.200000 0.000000 471.340000 0.485000 ;
    END
  END wbs_dat_o[23]
  PIN wbs_dat_o[22]
    DIRECTION OUTPUT ;
    USE SIGNAL ;
    ANTENNADIFFAREA 0.429 LAYER met2  ;
    ANTENNAPARTIALMETALAREA 5.9667 LAYER met2  ;
    ANTENNAPARTIALMETALSIDEAREA 29.7255 LAYER met2  ;
    PORT
      LAYER met2 ;
        RECT 453.720000 0.000000 453.860000 0.485000 ;
    END
  END wbs_dat_o[22]
  PIN wbs_dat_o[21]
    DIRECTION OUTPUT ;
    USE SIGNAL ;
    ANTENNADIFFAREA 0.429 LAYER met2  ;
    ANTENNAPARTIALMETALAREA 6.2243 LAYER met2  ;
    ANTENNAPARTIALMETALSIDEAREA 31.0135 LAYER met2  ;
    PORT
      LAYER met2 ;
        RECT 436.240000 0.000000 436.380000 0.485000 ;
    END
  END wbs_dat_o[21]
  PIN wbs_dat_o[20]
    DIRECTION OUTPUT ;
    USE SIGNAL ;
    ANTENNADIFFAREA 0.429 LAYER met2  ;
    ANTENNAPARTIALMETALAREA 5.5859 LAYER met2  ;
    ANTENNAPARTIALMETALSIDEAREA 27.8215 LAYER met2  ;
    PORT
      LAYER met2 ;
        RECT 418.760000 0.000000 418.900000 0.485000 ;
    END
  END wbs_dat_o[20]
  PIN wbs_dat_o[19]
    DIRECTION OUTPUT ;
    USE SIGNAL ;
    ANTENNADIFFAREA 0.429 LAYER met2  ;
    ANTENNAPARTIALMETALAREA 7.1215 LAYER met2  ;
    ANTENNAPARTIALMETALSIDEAREA 35.3815 LAYER met2  ;
    PORT
      LAYER met2 ;
        RECT 401.280000 0.000000 401.420000 0.485000 ;
    END
  END wbs_dat_o[19]
  PIN wbs_dat_o[18]
    DIRECTION OUTPUT ;
    USE SIGNAL ;
    ANTENNADIFFAREA 0.429 LAYER met2  ;
    ANTENNAPARTIALMETALAREA 5.9667 LAYER met2  ;
    ANTENNAPARTIALMETALSIDEAREA 29.7255 LAYER met2  ;
    PORT
      LAYER met2 ;
        RECT 383.800000 0.000000 383.940000 0.485000 ;
    END
  END wbs_dat_o[18]
  PIN wbs_dat_o[17]
    DIRECTION OUTPUT ;
    USE SIGNAL ;
    ANTENNADIFFAREA 0.429 LAYER met2  ;
    ANTENNAPARTIALMETALAREA 5.6335 LAYER met2  ;
    ANTENNAPARTIALMETALSIDEAREA 28.0595 LAYER met2  ;
    PORT
      LAYER met2 ;
        RECT 366.320000 0.000000 366.460000 0.485000 ;
    END
  END wbs_dat_o[17]
  PIN wbs_dat_o[16]
    DIRECTION OUTPUT ;
    USE SIGNAL ;
    ANTENNADIFFAREA 0.429 LAYER met2  ;
    ANTENNAPARTIALMETALAREA 4.8719 LAYER met2  ;
    ANTENNAPARTIALMETALSIDEAREA 24.2515 LAYER met2  ;
    PORT
      LAYER met2 ;
        RECT 349.300000 0.000000 349.440000 0.485000 ;
    END
  END wbs_dat_o[16]
  PIN wbs_dat_o[15]
    DIRECTION OUTPUT ;
    USE SIGNAL ;
    ANTENNADIFFAREA 0.429 LAYER met2  ;
    ANTENNAPARTIALMETALAREA 5.7147 LAYER met2  ;
    ANTENNAPARTIALMETALSIDEAREA 28.4655 LAYER met2  ;
    PORT
      LAYER met2 ;
        RECT 331.820000 0.000000 331.960000 0.485000 ;
    END
  END wbs_dat_o[15]
  PIN wbs_dat_o[14]
    DIRECTION OUTPUT ;
    USE SIGNAL ;
    ANTENNADIFFAREA 0.429 LAYER met2  ;
    ANTENNAPARTIALMETALAREA 5.9667 LAYER met2  ;
    ANTENNAPARTIALMETALSIDEAREA 29.7255 LAYER met2  ;
    PORT
      LAYER met2 ;
        RECT 314.340000 0.000000 314.480000 0.485000 ;
    END
  END wbs_dat_o[14]
  PIN wbs_dat_o[13]
    DIRECTION OUTPUT ;
    USE SIGNAL ;
    ANTENNADIFFAREA 0.429 LAYER met2  ;
    ANTENNAPARTIALMETALAREA 5.8435 LAYER met2  ;
    ANTENNAPARTIALMETALSIDEAREA 29.1095 LAYER met2  ;
    PORT
      LAYER met2 ;
        RECT 296.860000 0.000000 297.000000 0.485000 ;
    END
  END wbs_dat_o[13]
  PIN wbs_dat_o[12]
    DIRECTION OUTPUT ;
    USE SIGNAL ;
    ANTENNADIFFAREA 0.429 LAYER met2  ;
    ANTENNAPARTIALMETALAREA 5.4079 LAYER met2  ;
    ANTENNAPARTIALMETALSIDEAREA 26.8135 LAYER met2  ;
    PORT
      LAYER met2 ;
        RECT 279.380000 0.000000 279.520000 0.485000 ;
    END
  END wbs_dat_o[12]
  PIN wbs_dat_o[11]
    DIRECTION OUTPUT ;
    USE SIGNAL ;
    ANTENNAPARTIALMETALAREA 0.1099 LAYER met2  ;
    ANTENNAPARTIALMETALSIDEAREA 0.3885 LAYER met2  ;
    ANTENNAPARTIALCUTAREA 0.04 LAYER via2  ;
    ANTENNADIFFAREA 0.429 LAYER met3  ;
    ANTENNAPARTIALMETALAREA 18.3348 LAYER met3  ;
    ANTENNAPARTIALMETALSIDEAREA 98.256 LAYER met3  ;
    PORT
      LAYER met2 ;
        RECT 261.900000 0.000000 262.040000 0.485000 ;
    END
  END wbs_dat_o[11]
  PIN wbs_dat_o[10]
    DIRECTION OUTPUT ;
    USE SIGNAL ;
    ANTENNADIFFAREA 0.429 LAYER met2  ;
    ANTENNAPARTIALMETALAREA 5.8713 LAYER met2  ;
    ANTENNAPARTIALMETALSIDEAREA 29.1305 LAYER met2  ;
    PORT
      LAYER met2 ;
        RECT 244.420000 0.000000 244.560000 0.485000 ;
    END
  END wbs_dat_o[10]
  PIN wbs_dat_o[9]
    DIRECTION OUTPUT ;
    USE SIGNAL ;
    ANTENNADIFFAREA 0.429 LAYER met2  ;
    ANTENNAPARTIALMETALAREA 6.1623 LAYER met2  ;
    ANTENNAPARTIALMETALSIDEAREA 30.4675 LAYER met2  ;
    PORT
      LAYER met2 ;
        RECT 226.940000 0.000000 227.080000 0.485000 ;
    END
  END wbs_dat_o[9]
  PIN wbs_dat_o[8]
    DIRECTION OUTPUT ;
    USE SIGNAL ;
    ANTENNADIFFAREA 0.429 LAYER met2  ;
    ANTENNAPARTIALMETALAREA 5.5367 LAYER met2  ;
    ANTENNAPARTIALMETALSIDEAREA 27.4575 LAYER met2  ;
    PORT
      LAYER met2 ;
        RECT 209.460000 0.000000 209.600000 0.485000 ;
    END
  END wbs_dat_o[8]
  PIN wbs_dat_o[7]
    DIRECTION OUTPUT ;
    USE SIGNAL ;
    ANTENNADIFFAREA 0.429 LAYER met2  ;
    ANTENNAPARTIALMETALAREA 5.4555 LAYER met2  ;
    ANTENNAPARTIALMETALSIDEAREA 27.0515 LAYER met2  ;
    PORT
      LAYER met2 ;
        RECT 191.980000 0.000000 192.120000 0.485000 ;
    END
  END wbs_dat_o[7]
  PIN wbs_dat_o[6]
    DIRECTION OUTPUT ;
    USE SIGNAL ;
    ANTENNADIFFAREA 0.429 LAYER met2  ;
    ANTENNAPARTIALMETALAREA 5.4079 LAYER met2  ;
    ANTENNAPARTIALMETALSIDEAREA 26.8135 LAYER met2  ;
    PORT
      LAYER met2 ;
        RECT 174.960000 0.000000 175.100000 0.485000 ;
    END
  END wbs_dat_o[6]
  PIN wbs_dat_o[5]
    DIRECTION OUTPUT ;
    USE SIGNAL ;
    ANTENNADIFFAREA 0.429 LAYER met2  ;
    ANTENNAPARTIALMETALAREA 4.9459 LAYER met2  ;
    ANTENNAPARTIALMETALSIDEAREA 24.5035 LAYER met2  ;
    PORT
      LAYER met2 ;
        RECT 157.480000 0.000000 157.620000 0.485000 ;
    END
  END wbs_dat_o[5]
  PIN wbs_dat_o[4]
    DIRECTION OUTPUT ;
    USE SIGNAL ;
    ANTENNADIFFAREA 0.429 LAYER met2  ;
    ANTENNAPARTIALMETALAREA 6.0883 LAYER met2  ;
    ANTENNAPARTIALMETALSIDEAREA 30.2155 LAYER met2  ;
    PORT
      LAYER met2 ;
        RECT 140.000000 0.000000 140.140000 0.485000 ;
    END
  END wbs_dat_o[4]
  PIN wbs_dat_o[3]
    DIRECTION OUTPUT ;
    USE SIGNAL ;
    ANTENNADIFFAREA 0.429 LAYER met2  ;
    ANTENNAPARTIALMETALAREA 6.5239 LAYER met2  ;
    ANTENNAPARTIALMETALSIDEAREA 32.5115 LAYER met2  ;
    PORT
      LAYER met2 ;
        RECT 116.540000 0.000000 116.680000 0.485000 ;
    END
  END wbs_dat_o[3]
  PIN wbs_dat_o[2]
    DIRECTION OUTPUT ;
    USE SIGNAL ;
    ANTENNADIFFAREA 0.429 LAYER met2  ;
    ANTENNAPARTIALMETALAREA 5.3267 LAYER met2  ;
    ANTENNAPARTIALMETALSIDEAREA 26.4075 LAYER met2  ;
    PORT
      LAYER met2 ;
        RECT 93.540000 0.000000 93.680000 0.485000 ;
    END
  END wbs_dat_o[2]
  PIN wbs_dat_o[1]
    DIRECTION OUTPUT ;
    USE SIGNAL ;
    ANTENNADIFFAREA 0.429 LAYER met2  ;
    ANTENNAPARTIALMETALAREA 4.9459 LAYER met2  ;
    ANTENNAPARTIALMETALSIDEAREA 24.5035 LAYER met2  ;
    PORT
      LAYER met2 ;
        RECT 70.080000 0.000000 70.220000 0.485000 ;
    END
  END wbs_dat_o[1]
  PIN wbs_dat_o[0]
    DIRECTION OUTPUT ;
    USE SIGNAL ;
    ANTENNADIFFAREA 0.429 LAYER met2  ;
    ANTENNAPARTIALMETALAREA 5.7075 LAYER met2  ;
    ANTENNAPARTIALMETALSIDEAREA 28.3115 LAYER met2  ;
    PORT
      LAYER met2 ;
        RECT 47.080000 0.000000 47.220000 0.485000 ;
    END
  END wbs_dat_o[0]
  PIN vssd1
    DIRECTION INOUT ;
    USE GROUND ;
    PORT
      LAYER met4 ;
        RECT 2837.500000 3466.940000 2840.600000 3470.040000 ;
    END
    PORT
      LAYER met4 ;
        RECT 2837.500000 0.000000 2840.600000 3.100000 ;
    END
    PORT
      LAYER met4 ;
        RECT 19.220000 3466.940000 22.320000 3470.040000 ;
    END
    PORT
      LAYER met4 ;
        RECT 19.220000 0.000000 22.320000 3.100000 ;
    END
    PORT
      LAYER met5 ;
        RECT 2856.720000 3445.640000 2859.820000 3448.740000 ;
    END
    PORT
      LAYER met5 ;
        RECT 0.000000 3445.640000 3.100000 3448.740000 ;
    END
    PORT
      LAYER met5 ;
        RECT 2856.720000 19.260000 2859.820000 22.360000 ;
    END
    PORT
      LAYER met5 ;
        RECT 0.000000 19.260000 3.100000 22.360000 ;
    END

# P/G power stripe data as pin
    PORT
      LAYER met4 ;
        RECT 1428.000000 19.260000 1431.360000 3448.740000 ;
        RECT 19.220000 0.000000 22.320000 3470.040000 ;
        RECT 340.000000 979.300000 343.360000 2138.200000 ;
        RECT 476.000000 979.300000 479.360000 2138.200000 ;
        RECT 612.000000 979.300000 615.360000 2138.200000 ;
        RECT 748.000000 979.300000 751.360000 2138.200000 ;
        RECT 1020.000000 979.300000 1023.360000 2138.200000 ;
        RECT 1156.000000 979.300000 1159.360000 2138.200000 ;
        RECT 1292.000000 979.300000 1295.360000 2138.200000 ;
        RECT 68.000000 19.260000 71.360000 3448.740000 ;
        RECT 204.000000 19.260000 207.360000 3448.740000 ;
        RECT 884.000000 19.260000 887.360000 3448.740000 ;
        RECT 2837.500000 0.000000 2840.600000 3470.040000 ;
        RECT 2652.000000 991.200000 2655.360000 2128.640000 ;
        RECT 1564.000000 979.300000 1567.360000 2138.200000 ;
        RECT 1700.000000 979.300000 1703.360000 2138.200000 ;
        RECT 1836.000000 979.300000 1839.360000 2138.200000 ;
        RECT 1972.000000 979.300000 1975.360000 2138.200000 ;
        RECT 2244.000000 979.300000 2247.360000 2138.200000 ;
        RECT 2380.000000 979.300000 2383.360000 2138.200000 ;
        RECT 2516.000000 979.300000 2519.360000 2138.200000 ;
        RECT 2108.000000 19.260000 2111.360000 3448.740000 ;
        RECT 2788.000000 19.260000 2791.360000 3448.740000 ;
        RECT 1396.580000 576.400000 1398.380000 981.100000 ;
        RECT 911.400000 576.400000 913.200000 981.100000 ;
        RECT 771.580000 576.400000 773.380000 981.100000 ;
        RECT 286.400000 576.400000 288.200000 981.100000 ;
        RECT 286.400000 76.400000 288.200000 481.100000 ;
        RECT 340.000000 19.260000 343.360000 78.200000 ;
        RECT 476.000000 19.260000 479.360000 78.200000 ;
        RECT 340.000000 479.300000 343.360000 578.200000 ;
        RECT 476.000000 479.300000 479.360000 578.200000 ;
        RECT 1396.580000 76.400000 1398.380000 481.100000 ;
        RECT 911.400000 76.400000 913.200000 481.100000 ;
        RECT 771.580000 76.400000 773.380000 481.100000 ;
        RECT 612.000000 19.260000 615.360000 78.200000 ;
        RECT 748.000000 19.260000 751.360000 78.200000 ;
        RECT 1020.000000 19.260000 1023.360000 78.200000 ;
        RECT 1156.000000 19.260000 1159.360000 78.200000 ;
        RECT 1292.000000 19.260000 1295.360000 78.200000 ;
        RECT 748.000000 479.300000 751.360000 578.200000 ;
        RECT 612.000000 479.300000 615.360000 578.200000 ;
        RECT 1156.000000 479.300000 1159.360000 578.200000 ;
        RECT 1020.000000 479.300000 1023.360000 578.200000 ;
        RECT 1292.000000 479.300000 1295.360000 578.200000 ;
        RECT 2651.580000 576.400000 2653.380000 981.100000 ;
        RECT 2166.400000 576.400000 2168.200000 981.100000 ;
        RECT 2021.580000 576.400000 2023.380000 981.100000 ;
        RECT 1536.400000 576.400000 1538.200000 981.100000 ;
        RECT 2166.400000 76.400000 2168.200000 481.100000 ;
        RECT 2021.580000 76.400000 2023.380000 481.100000 ;
        RECT 1536.400000 76.400000 1538.200000 481.100000 ;
        RECT 1564.000000 19.260000 1567.360000 78.200000 ;
        RECT 1700.000000 19.260000 1703.360000 78.200000 ;
        RECT 1836.000000 19.260000 1839.360000 78.200000 ;
        RECT 1972.000000 19.260000 1975.360000 78.200000 ;
        RECT 2244.000000 19.260000 2247.360000 78.200000 ;
        RECT 1564.000000 479.300000 1567.360000 578.200000 ;
        RECT 1836.000000 479.300000 1839.360000 578.200000 ;
        RECT 1700.000000 479.300000 1703.360000 578.200000 ;
        RECT 1972.000000 479.300000 1975.360000 578.200000 ;
        RECT 2244.000000 479.300000 2247.360000 578.200000 ;
        RECT 2651.580000 76.400000 2653.380000 481.100000 ;
        RECT 2380.000000 19.260000 2383.360000 78.200000 ;
        RECT 2516.000000 19.260000 2519.360000 78.200000 ;
        RECT 2652.000000 19.260000 2655.360000 68.360000 ;
        RECT 2380.000000 479.300000 2383.360000 578.200000 ;
        RECT 2516.000000 479.300000 2519.360000 578.200000 ;
        RECT 2652.000000 490.720000 2655.360000 567.360000 ;
        RECT 340.000000 2539.300000 343.360000 3448.740000 ;
        RECT 476.000000 2539.300000 479.360000 3448.740000 ;
        RECT 612.000000 2539.300000 615.360000 3448.740000 ;
        RECT 748.000000 2539.300000 751.360000 3448.740000 ;
        RECT 1020.000000 2539.300000 1023.360000 3448.740000 ;
        RECT 1156.000000 2539.300000 1159.360000 3448.740000 ;
        RECT 1292.000000 2539.300000 1295.360000 3448.740000 ;
        RECT 286.400000 2136.400000 288.200000 2541.100000 ;
        RECT 1396.580000 2136.400000 1398.380000 2541.100000 ;
        RECT 911.400000 2136.400000 913.200000 2541.100000 ;
        RECT 771.580000 2136.400000 773.380000 2541.100000 ;
        RECT 2516.000000 2539.300000 2519.360000 3448.740000 ;
        RECT 2380.000000 2539.300000 2383.360000 3448.740000 ;
        RECT 2244.000000 2539.300000 2247.360000 3448.740000 ;
        RECT 1972.000000 2539.300000 1975.360000 3448.740000 ;
        RECT 1836.000000 2539.300000 1839.360000 3448.740000 ;
        RECT 2652.000000 2547.100000 2655.360000 3448.740000 ;
        RECT 1564.000000 2539.300000 1567.360000 3448.740000 ;
        RECT 1700.000000 2539.300000 1703.360000 3448.740000 ;
        RECT 2166.400000 2136.400000 2168.200000 2541.100000 ;
        RECT 2021.580000 2136.400000 2023.380000 2541.100000 ;
        RECT 1536.400000 2136.400000 1538.200000 2541.100000 ;
        RECT 2651.580000 2136.400000 2653.380000 2541.100000 ;
        RECT 291.360000 155.000000 293.100000 158.360000 ;
        RECT 291.360000 245.000000 293.100000 248.360000 ;
        RECT 291.360000 335.000000 293.100000 338.360000 ;
        RECT 291.360000 425.000000 293.100000 428.360000 ;
        RECT 291.360000 605.000000 293.100000 608.360000 ;
        RECT 291.360000 695.000000 293.100000 698.360000 ;
        RECT 291.360000 785.000000 293.100000 788.360000 ;
        RECT 766.680000 155.000000 768.420000 158.360000 ;
        RECT 916.360000 155.000000 918.100000 158.360000 ;
        RECT 766.680000 425.000000 768.420000 428.360000 ;
        RECT 766.680000 335.000000 768.420000 338.360000 ;
        RECT 766.680000 245.000000 768.420000 248.360000 ;
        RECT 916.360000 245.000000 918.100000 248.360000 ;
        RECT 916.360000 425.000000 918.100000 428.360000 ;
        RECT 916.360000 335.000000 918.100000 338.360000 ;
        RECT 1391.680000 155.000000 1393.420000 158.360000 ;
        RECT 1391.680000 425.000000 1393.420000 428.360000 ;
        RECT 1391.680000 335.000000 1393.420000 338.360000 ;
        RECT 1391.680000 245.000000 1393.420000 248.360000 ;
        RECT 766.680000 605.000000 768.420000 608.360000 ;
        RECT 916.360000 605.000000 918.100000 608.360000 ;
        RECT 766.680000 785.000000 768.420000 788.360000 ;
        RECT 766.680000 695.000000 768.420000 698.360000 ;
        RECT 916.360000 695.000000 918.100000 698.360000 ;
        RECT 916.360000 785.000000 918.100000 788.360000 ;
        RECT 1391.680000 605.000000 1393.420000 608.360000 ;
        RECT 1391.680000 785.000000 1393.420000 788.360000 ;
        RECT 1391.680000 695.000000 1393.420000 698.360000 ;
        RECT 291.360000 875.000000 293.100000 878.360000 ;
        RECT 291.360000 965.000000 293.100000 968.360000 ;
        RECT 766.680000 965.000000 768.420000 968.360000 ;
        RECT 766.680000 875.000000 768.420000 878.360000 ;
        RECT 916.360000 965.000000 918.100000 968.360000 ;
        RECT 916.360000 875.000000 918.100000 878.360000 ;
        RECT 1391.680000 965.000000 1393.420000 968.360000 ;
        RECT 1391.680000 875.000000 1393.420000 878.360000 ;
        RECT 1541.360000 155.000000 1543.100000 158.360000 ;
        RECT 1541.360000 245.000000 1543.100000 248.360000 ;
        RECT 1541.360000 335.000000 1543.100000 338.360000 ;
        RECT 1541.360000 425.000000 1543.100000 428.360000 ;
        RECT 2016.680000 155.000000 2018.420000 158.360000 ;
        RECT 2171.360000 155.000000 2173.100000 158.360000 ;
        RECT 2016.680000 245.000000 2018.420000 248.360000 ;
        RECT 2016.680000 335.000000 2018.420000 338.360000 ;
        RECT 2016.680000 425.000000 2018.420000 428.360000 ;
        RECT 2171.360000 245.000000 2173.100000 248.360000 ;
        RECT 2171.360000 335.000000 2173.100000 338.360000 ;
        RECT 2171.360000 425.000000 2173.100000 428.360000 ;
        RECT 1541.360000 605.000000 1543.100000 608.360000 ;
        RECT 1541.360000 695.000000 1543.100000 698.360000 ;
        RECT 1541.360000 785.000000 1543.100000 788.360000 ;
        RECT 2016.680000 605.000000 2018.420000 608.360000 ;
        RECT 2171.360000 605.000000 2173.100000 608.360000 ;
        RECT 2016.680000 695.000000 2018.420000 698.360000 ;
        RECT 2016.680000 785.000000 2018.420000 788.360000 ;
        RECT 2171.360000 695.000000 2173.100000 698.360000 ;
        RECT 2171.360000 785.000000 2173.100000 788.360000 ;
        RECT 2646.680000 155.000000 2648.420000 158.360000 ;
        RECT 2646.680000 245.000000 2648.420000 248.360000 ;
        RECT 2646.680000 335.000000 2648.420000 338.360000 ;
        RECT 2646.680000 425.000000 2648.420000 428.360000 ;
        RECT 2646.680000 605.000000 2648.420000 608.360000 ;
        RECT 2646.680000 695.000000 2648.420000 698.360000 ;
        RECT 2646.680000 785.000000 2648.420000 788.360000 ;
        RECT 1541.360000 875.000000 1543.100000 878.360000 ;
        RECT 1541.360000 965.000000 1543.100000 968.360000 ;
        RECT 2016.680000 875.000000 2018.420000 878.360000 ;
        RECT 2016.680000 965.000000 2018.420000 968.360000 ;
        RECT 2171.360000 875.000000 2173.100000 878.360000 ;
        RECT 2171.360000 965.000000 2173.100000 968.360000 ;
        RECT 2646.680000 875.000000 2648.420000 878.360000 ;
        RECT 2646.680000 965.000000 2648.420000 968.360000 ;
        RECT 291.360000 2225.000000 293.100000 2228.360000 ;
        RECT 291.360000 2315.000000 293.100000 2318.360000 ;
        RECT 291.360000 2405.000000 293.100000 2408.360000 ;
        RECT 291.360000 2495.000000 293.100000 2498.360000 ;
        RECT 766.680000 2315.000000 768.420000 2318.360000 ;
        RECT 766.680000 2225.000000 768.420000 2228.360000 ;
        RECT 916.360000 2225.000000 918.100000 2228.360000 ;
        RECT 916.360000 2315.000000 918.100000 2318.360000 ;
        RECT 766.680000 2405.000000 768.420000 2408.360000 ;
        RECT 766.680000 2495.000000 768.420000 2498.360000 ;
        RECT 916.360000 2405.000000 918.100000 2408.360000 ;
        RECT 916.360000 2495.000000 918.100000 2498.360000 ;
        RECT 1391.680000 2315.000000 1393.420000 2318.360000 ;
        RECT 1391.680000 2225.000000 1393.420000 2228.360000 ;
        RECT 1391.680000 2405.000000 1393.420000 2408.360000 ;
        RECT 1391.680000 2495.000000 1393.420000 2498.360000 ;
        RECT 1541.360000 2225.000000 1543.100000 2228.360000 ;
        RECT 1541.360000 2315.000000 1543.100000 2318.360000 ;
        RECT 1541.360000 2405.000000 1543.100000 2408.360000 ;
        RECT 1541.360000 2495.000000 1543.100000 2498.360000 ;
        RECT 2016.680000 2225.000000 2018.420000 2228.360000 ;
        RECT 2016.680000 2315.000000 2018.420000 2318.360000 ;
        RECT 2171.360000 2225.000000 2173.100000 2228.360000 ;
        RECT 2171.360000 2315.000000 2173.100000 2318.360000 ;
        RECT 2016.680000 2405.000000 2018.420000 2408.360000 ;
        RECT 2016.680000 2495.000000 2018.420000 2498.360000 ;
        RECT 2171.360000 2405.000000 2173.100000 2408.360000 ;
        RECT 2171.360000 2495.000000 2173.100000 2498.360000 ;
        RECT 2646.680000 2225.000000 2648.420000 2228.360000 ;
        RECT 2646.680000 2315.000000 2648.420000 2318.360000 ;
        RECT 2646.680000 2405.000000 2648.420000 2408.360000 ;
        RECT 2646.680000 2495.000000 2648.420000 2498.360000 ;
      LAYER met5 ;
        RECT 0.000000 19.260000 2859.820000 22.360000 ;
        RECT 19.220000 65.000000 2840.600000 68.360000 ;
        RECT 19.220000 155.000000 2840.600000 158.360000 ;
        RECT 19.220000 245.000000 2840.600000 248.360000 ;
        RECT 19.220000 335.000000 2840.600000 338.360000 ;
        RECT 19.220000 425.000000 2840.600000 428.360000 ;
        RECT 19.220000 515.000000 2840.600000 518.360000 ;
        RECT 19.220000 605.000000 2840.600000 608.360000 ;
        RECT 19.220000 695.000000 2840.600000 698.360000 ;
        RECT 19.220000 785.000000 2840.600000 788.360000 ;
        RECT 19.220000 875.000000 2840.600000 878.360000 ;
        RECT 19.220000 965.000000 2840.600000 968.360000 ;
        RECT 19.220000 1055.000000 2840.600000 1058.360000 ;
        RECT 19.220000 1145.000000 2840.600000 1148.360000 ;
        RECT 19.220000 1235.000000 2840.600000 1238.360000 ;
        RECT 19.220000 1325.000000 2840.600000 1328.360000 ;
        RECT 19.220000 1415.000000 2840.600000 1418.360000 ;
        RECT 19.220000 1505.000000 2840.600000 1508.360000 ;
        RECT 19.220000 1595.000000 2840.600000 1598.360000 ;
        RECT 19.220000 1685.000000 2840.600000 1688.360000 ;
        RECT 19.220000 1775.000000 2840.600000 1778.360000 ;
        RECT 19.220000 1865.000000 2840.600000 1868.360000 ;
        RECT 19.220000 1955.000000 2840.600000 1958.360000 ;
        RECT 19.220000 2045.000000 2840.600000 2048.360000 ;
        RECT 19.220000 2135.000000 2840.600000 2138.360000 ;
        RECT 19.220000 2225.000000 2840.600000 2228.360000 ;
        RECT 19.220000 2315.000000 2840.600000 2318.360000 ;
        RECT 19.220000 2405.000000 2840.600000 2408.360000 ;
        RECT 19.220000 2495.000000 2840.600000 2498.360000 ;
        RECT 19.220000 2585.000000 2840.600000 2588.360000 ;
        RECT 19.220000 3035.000000 2840.600000 3038.360000 ;
        RECT 19.220000 2675.000000 2840.600000 2678.360000 ;
        RECT 19.220000 2765.000000 2840.600000 2768.360000 ;
        RECT 19.220000 2855.000000 2840.600000 2858.360000 ;
        RECT 19.220000 2945.000000 2840.600000 2948.360000 ;
        RECT 19.220000 3125.000000 2840.600000 3128.360000 ;
        RECT 19.220000 3215.000000 2840.600000 3218.360000 ;
        RECT 19.220000 3305.000000 2840.600000 3308.360000 ;
        RECT 19.220000 3395.000000 2840.600000 3398.360000 ;
        RECT 0.000000 3445.640000 2859.820000 3448.740000 ;
    END
# end of P/G power stripe data as pin

  END vssd1
  PIN vccd1
    DIRECTION INOUT ;
    USE POWER ;
    PORT
      LAYER met4 ;
        RECT 2831.300000 3466.940000 2834.400000 3470.040000 ;
    END
    PORT
      LAYER met4 ;
        RECT 2831.300000 0.000000 2834.400000 3.100000 ;
    END
    PORT
      LAYER met4 ;
        RECT 25.420000 3466.940000 28.520000 3470.040000 ;
    END
    PORT
      LAYER met4 ;
        RECT 25.420000 0.000000 28.520000 3.100000 ;
    END
    PORT
      LAYER met5 ;
        RECT 2856.720000 3439.440000 2859.820000 3442.540000 ;
    END
    PORT
      LAYER met5 ;
        RECT 0.000000 3439.440000 3.100000 3442.540000 ;
    END
    PORT
      LAYER met5 ;
        RECT 2856.720000 25.460000 2859.820000 28.560000 ;
    END
    PORT
      LAYER met5 ;
        RECT 0.000000 25.460000 3.100000 28.560000 ;
    END

# P/G power stripe data as pin
    PORT
      LAYER met4 ;
        RECT 816.000000 25.460000 819.360000 3442.540000 ;
        RECT 272.000000 25.460000 275.360000 3442.540000 ;
        RECT 136.000000 25.460000 139.360000 3442.540000 ;
        RECT 1360.000000 982.900000 1363.360000 2134.600000 ;
        RECT 1224.000000 982.900000 1227.360000 2134.600000 ;
        RECT 25.420000 0.000000 28.520000 3470.040000 ;
        RECT 408.000000 982.900000 411.360000 2134.600000 ;
        RECT 544.000000 982.900000 547.360000 2134.600000 ;
        RECT 680.000000 982.900000 683.360000 2134.600000 ;
        RECT 952.000000 982.900000 955.360000 2134.600000 ;
        RECT 1088.000000 982.900000 1091.360000 2134.600000 ;
        RECT 2720.000000 25.460000 2723.360000 3442.540000 ;
        RECT 2040.000000 25.460000 2043.360000 3442.540000 ;
        RECT 1496.000000 25.460000 1499.360000 3442.540000 ;
        RECT 2584.000000 982.900000 2587.360000 2134.600000 ;
        RECT 2448.000000 982.900000 2451.360000 2134.600000 ;
        RECT 2312.000000 982.900000 2315.360000 2134.600000 ;
        RECT 2176.000000 982.900000 2179.360000 2134.600000 ;
        RECT 1904.000000 982.900000 1907.360000 2134.600000 ;
        RECT 1768.000000 982.900000 1771.360000 2134.600000 ;
        RECT 1632.000000 982.900000 1635.360000 2134.600000 ;
        RECT 2831.300000 0.000000 2834.400000 3470.040000 ;
        RECT 1400.180000 572.800000 1401.980000 984.700000 ;
        RECT 907.800000 572.800000 909.600000 984.700000 ;
        RECT 775.180000 572.800000 776.980000 984.700000 ;
        RECT 282.800000 572.800000 284.600000 984.700000 ;
        RECT 282.800000 72.800000 284.600000 484.700000 ;
        RECT 408.000000 25.460000 411.360000 74.600000 ;
        RECT 544.000000 25.460000 547.360000 74.600000 ;
        RECT 544.000000 482.900000 547.360000 574.600000 ;
        RECT 408.000000 482.900000 411.360000 574.600000 ;
        RECT 1400.180000 72.800000 1401.980000 484.700000 ;
        RECT 907.800000 72.800000 909.600000 484.700000 ;
        RECT 775.180000 72.800000 776.980000 484.700000 ;
        RECT 680.000000 25.460000 683.360000 74.600000 ;
        RECT 952.000000 25.460000 955.360000 74.600000 ;
        RECT 1088.000000 25.460000 1091.360000 74.600000 ;
        RECT 1224.000000 25.460000 1227.360000 74.600000 ;
        RECT 1360.000000 25.460000 1363.360000 74.600000 ;
        RECT 680.000000 482.900000 683.360000 574.600000 ;
        RECT 952.000000 482.900000 955.360000 574.600000 ;
        RECT 1088.000000 482.900000 1091.360000 574.600000 ;
        RECT 1360.000000 482.900000 1363.360000 574.600000 ;
        RECT 1224.000000 482.900000 1227.360000 574.600000 ;
        RECT 2655.180000 572.800000 2656.980000 984.700000 ;
        RECT 2162.800000 572.800000 2164.600000 984.700000 ;
        RECT 2025.180000 572.800000 2026.980000 984.700000 ;
        RECT 1532.800000 572.800000 1534.600000 984.700000 ;
        RECT 2162.800000 72.800000 2164.600000 484.700000 ;
        RECT 2025.180000 72.800000 2026.980000 484.700000 ;
        RECT 1532.800000 72.800000 1534.600000 484.700000 ;
        RECT 1632.000000 25.460000 1635.360000 74.600000 ;
        RECT 1768.000000 25.460000 1771.360000 74.600000 ;
        RECT 1904.000000 25.460000 1907.360000 74.600000 ;
        RECT 2176.000000 25.460000 2179.360000 74.600000 ;
        RECT 1632.000000 482.900000 1635.360000 574.600000 ;
        RECT 1768.000000 482.900000 1771.360000 574.600000 ;
        RECT 1904.000000 482.900000 1907.360000 574.600000 ;
        RECT 2176.000000 482.900000 2179.360000 574.600000 ;
        RECT 2655.180000 72.800000 2656.980000 484.700000 ;
        RECT 2312.000000 25.460000 2315.360000 74.600000 ;
        RECT 2448.000000 25.460000 2451.360000 74.600000 ;
        RECT 2584.000000 25.460000 2587.360000 74.600000 ;
        RECT 2448.000000 482.900000 2451.360000 574.600000 ;
        RECT 2312.000000 482.900000 2315.360000 574.600000 ;
        RECT 2584.000000 482.900000 2587.360000 574.600000 ;
        RECT 1360.000000 2542.900000 1363.360000 3442.540000 ;
        RECT 1224.000000 2542.900000 1227.360000 3442.540000 ;
        RECT 1088.000000 2542.900000 1091.360000 3442.540000 ;
        RECT 952.000000 2542.900000 955.360000 3442.540000 ;
        RECT 680.000000 2542.900000 683.360000 3442.540000 ;
        RECT 544.000000 2542.900000 547.360000 3442.540000 ;
        RECT 408.000000 2542.900000 411.360000 3442.540000 ;
        RECT 282.800000 2132.800000 284.600000 2544.700000 ;
        RECT 1400.180000 2132.800000 1401.980000 2544.700000 ;
        RECT 907.800000 2132.800000 909.600000 2544.700000 ;
        RECT 775.180000 2132.800000 776.980000 2544.700000 ;
        RECT 2584.000000 2542.900000 2587.360000 3442.540000 ;
        RECT 2448.000000 2542.900000 2451.360000 3442.540000 ;
        RECT 2312.000000 2542.900000 2315.360000 3442.540000 ;
        RECT 2176.000000 2542.900000 2179.360000 3442.540000 ;
        RECT 1904.000000 2542.900000 1907.360000 3442.540000 ;
        RECT 1768.000000 2542.900000 1771.360000 3442.540000 ;
        RECT 1632.000000 2542.900000 1635.360000 3442.540000 ;
        RECT 2162.800000 2132.800000 2164.600000 2544.700000 ;
        RECT 2025.180000 2132.800000 2026.980000 2544.700000 ;
        RECT 1532.800000 2132.800000 1534.600000 2544.700000 ;
        RECT 2655.180000 2132.800000 2656.980000 2544.700000 ;
        RECT 294.760000 431.460000 296.500000 434.820000 ;
        RECT 294.760000 161.460000 296.500000 164.820000 ;
        RECT 294.760000 251.460000 296.500000 254.820000 ;
        RECT 294.760000 341.460000 296.500000 344.820000 ;
        RECT 294.760000 611.460000 296.500000 614.820000 ;
        RECT 294.760000 701.460000 296.500000 704.820000 ;
        RECT 294.760000 791.460000 296.500000 794.820000 ;
        RECT 1388.280000 431.460000 1390.020000 434.820000 ;
        RECT 919.760000 431.460000 921.500000 434.820000 ;
        RECT 763.280000 431.460000 765.020000 434.820000 ;
        RECT 763.280000 161.460000 765.020000 164.820000 ;
        RECT 919.760000 161.460000 921.500000 164.820000 ;
        RECT 763.280000 341.460000 765.020000 344.820000 ;
        RECT 763.280000 251.460000 765.020000 254.820000 ;
        RECT 919.760000 251.460000 921.500000 254.820000 ;
        RECT 919.760000 341.460000 921.500000 344.820000 ;
        RECT 1388.280000 161.460000 1390.020000 164.820000 ;
        RECT 1388.280000 341.460000 1390.020000 344.820000 ;
        RECT 1388.280000 251.460000 1390.020000 254.820000 ;
        RECT 763.280000 611.460000 765.020000 614.820000 ;
        RECT 919.760000 611.460000 921.500000 614.820000 ;
        RECT 763.280000 791.460000 765.020000 794.820000 ;
        RECT 763.280000 701.460000 765.020000 704.820000 ;
        RECT 919.760000 701.460000 921.500000 704.820000 ;
        RECT 919.760000 791.460000 921.500000 794.820000 ;
        RECT 1388.280000 611.460000 1390.020000 614.820000 ;
        RECT 1388.280000 791.460000 1390.020000 794.820000 ;
        RECT 1388.280000 701.460000 1390.020000 704.820000 ;
        RECT 294.760000 881.460000 296.500000 884.820000 ;
        RECT 294.760000 971.390000 296.500000 972.810000 ;
        RECT 763.280000 971.390000 765.020000 972.810000 ;
        RECT 763.280000 881.460000 765.020000 884.820000 ;
        RECT 919.760000 971.390000 921.500000 972.810000 ;
        RECT 919.760000 881.460000 921.500000 884.820000 ;
        RECT 1388.280000 971.390000 1390.020000 972.810000 ;
        RECT 1388.280000 881.460000 1390.020000 884.820000 ;
        RECT 2174.760000 431.460000 2176.500000 434.820000 ;
        RECT 2013.280000 431.460000 2015.020000 434.820000 ;
        RECT 1544.760000 431.460000 1546.500000 434.820000 ;
        RECT 1544.760000 161.460000 1546.500000 164.820000 ;
        RECT 1544.760000 251.460000 1546.500000 254.820000 ;
        RECT 1544.760000 341.460000 1546.500000 344.820000 ;
        RECT 2013.280000 161.460000 2015.020000 164.820000 ;
        RECT 2174.760000 161.460000 2176.500000 164.820000 ;
        RECT 2013.280000 251.460000 2015.020000 254.820000 ;
        RECT 2013.280000 341.460000 2015.020000 344.820000 ;
        RECT 2174.760000 251.460000 2176.500000 254.820000 ;
        RECT 2174.760000 341.460000 2176.500000 344.820000 ;
        RECT 1544.760000 611.460000 1546.500000 614.820000 ;
        RECT 1544.760000 701.460000 1546.500000 704.820000 ;
        RECT 1544.760000 791.460000 1546.500000 794.820000 ;
        RECT 2013.280000 611.460000 2015.020000 614.820000 ;
        RECT 2174.760000 611.460000 2176.500000 614.820000 ;
        RECT 2013.280000 701.460000 2015.020000 704.820000 ;
        RECT 2013.280000 791.460000 2015.020000 794.820000 ;
        RECT 2174.760000 701.460000 2176.500000 704.820000 ;
        RECT 2174.760000 791.460000 2176.500000 794.820000 ;
        RECT 2643.280000 431.460000 2645.020000 434.820000 ;
        RECT 2643.280000 161.460000 2645.020000 164.820000 ;
        RECT 2643.280000 251.460000 2645.020000 254.820000 ;
        RECT 2643.280000 341.460000 2645.020000 344.820000 ;
        RECT 2643.280000 611.460000 2645.020000 614.820000 ;
        RECT 2643.280000 701.460000 2645.020000 704.820000 ;
        RECT 2643.280000 791.460000 2645.020000 794.820000 ;
        RECT 1544.760000 971.390000 1546.500000 972.810000 ;
        RECT 1544.760000 881.460000 1546.500000 884.820000 ;
        RECT 2013.280000 881.460000 2015.020000 884.820000 ;
        RECT 2013.280000 971.390000 2015.020000 972.810000 ;
        RECT 2174.760000 881.460000 2176.500000 884.820000 ;
        RECT 2174.760000 971.390000 2176.500000 972.810000 ;
        RECT 2643.280000 881.460000 2645.020000 884.820000 ;
        RECT 2643.280000 971.390000 2645.020000 972.810000 ;
        RECT 294.760000 2144.760000 296.500000 2146.180000 ;
        RECT 294.760000 2231.460000 296.500000 2234.820000 ;
        RECT 294.760000 2321.460000 296.500000 2324.820000 ;
        RECT 294.760000 2411.460000 296.500000 2414.820000 ;
        RECT 294.760000 2501.460000 296.500000 2504.820000 ;
        RECT 763.280000 2144.760000 765.020000 2146.180000 ;
        RECT 919.760000 2144.760000 921.500000 2146.180000 ;
        RECT 1388.280000 2144.760000 1390.020000 2146.180000 ;
        RECT 763.280000 2321.460000 765.020000 2324.820000 ;
        RECT 763.280000 2231.460000 765.020000 2234.820000 ;
        RECT 919.760000 2231.460000 921.500000 2234.820000 ;
        RECT 919.760000 2321.460000 921.500000 2324.820000 ;
        RECT 763.280000 2411.460000 765.020000 2414.820000 ;
        RECT 763.280000 2501.460000 765.020000 2504.820000 ;
        RECT 919.760000 2411.460000 921.500000 2414.820000 ;
        RECT 919.760000 2501.460000 921.500000 2504.820000 ;
        RECT 1388.280000 2321.460000 1390.020000 2324.820000 ;
        RECT 1388.280000 2231.460000 1390.020000 2234.820000 ;
        RECT 1388.280000 2411.460000 1390.020000 2414.820000 ;
        RECT 1388.280000 2501.460000 1390.020000 2504.820000 ;
        RECT 1544.760000 2144.760000 1546.500000 2146.180000 ;
        RECT 2013.280000 2144.760000 2015.020000 2146.180000 ;
        RECT 2174.760000 2144.760000 2176.500000 2146.180000 ;
        RECT 1544.760000 2231.460000 1546.500000 2234.820000 ;
        RECT 1544.760000 2321.460000 1546.500000 2324.820000 ;
        RECT 1544.760000 2411.460000 1546.500000 2414.820000 ;
        RECT 1544.760000 2501.460000 1546.500000 2504.820000 ;
        RECT 2013.280000 2231.460000 2015.020000 2234.820000 ;
        RECT 2013.280000 2321.460000 2015.020000 2324.820000 ;
        RECT 2174.760000 2231.460000 2176.500000 2234.820000 ;
        RECT 2174.760000 2321.460000 2176.500000 2324.820000 ;
        RECT 2013.280000 2411.460000 2015.020000 2414.820000 ;
        RECT 2013.280000 2501.460000 2015.020000 2504.820000 ;
        RECT 2174.760000 2411.460000 2176.500000 2414.820000 ;
        RECT 2174.760000 2501.460000 2176.500000 2504.820000 ;
        RECT 2643.280000 2144.760000 2645.020000 2146.180000 ;
        RECT 2643.280000 2231.460000 2645.020000 2234.820000 ;
        RECT 2643.280000 2321.460000 2645.020000 2324.820000 ;
        RECT 2643.280000 2411.460000 2645.020000 2414.820000 ;
        RECT 2643.280000 2501.460000 2645.020000 2504.820000 ;
      LAYER met5 ;
        RECT 25.420000 431.460000 2834.400000 434.820000 ;
        RECT 0.000000 25.460000 2859.820000 28.560000 ;
        RECT 25.420000 71.460000 2834.400000 74.820000 ;
        RECT 25.420000 161.460000 2834.400000 164.820000 ;
        RECT 25.420000 251.460000 2834.400000 254.820000 ;
        RECT 25.420000 341.460000 2834.400000 344.820000 ;
        RECT 25.420000 521.460000 2834.400000 524.820000 ;
        RECT 25.420000 611.460000 2834.400000 614.820000 ;
        RECT 25.420000 701.460000 2834.400000 704.820000 ;
        RECT 25.420000 791.460000 2834.400000 794.820000 ;
        RECT 25.420000 881.460000 2834.400000 884.820000 ;
        RECT 25.420000 971.460000 2834.400000 974.820000 ;
        RECT 25.420000 1061.460000 2834.400000 1064.820000 ;
        RECT 25.420000 1151.460000 2834.400000 1154.820000 ;
        RECT 25.420000 1241.460000 2834.400000 1244.820000 ;
        RECT 25.420000 1331.460000 2834.400000 1334.820000 ;
        RECT 25.420000 1421.460000 2834.400000 1424.820000 ;
        RECT 25.420000 1511.460000 2834.400000 1514.820000 ;
        RECT 25.420000 1601.460000 2834.400000 1604.820000 ;
        RECT 25.420000 1691.460000 2834.400000 1694.820000 ;
        RECT 25.420000 1781.460000 2834.400000 1784.820000 ;
        RECT 25.420000 1871.460000 2834.400000 1874.820000 ;
        RECT 25.420000 1961.460000 2834.400000 1964.820000 ;
        RECT 25.420000 2051.460000 2834.400000 2054.820000 ;
        RECT 25.420000 2141.460000 2834.400000 2144.820000 ;
        RECT 25.420000 2231.460000 2834.400000 2234.820000 ;
        RECT 25.420000 2321.460000 2834.400000 2324.820000 ;
        RECT 25.420000 2411.460000 2834.400000 2414.820000 ;
        RECT 25.420000 2501.460000 2834.400000 2504.820000 ;
        RECT 25.420000 2591.460000 2834.400000 2594.820000 ;
        RECT 25.420000 2681.460000 2834.400000 2684.820000 ;
        RECT 25.420000 2771.460000 2834.400000 2774.820000 ;
        RECT 25.420000 2861.460000 2834.400000 2864.820000 ;
        RECT 25.420000 2951.460000 2834.400000 2954.820000 ;
        RECT 25.420000 3041.460000 2834.400000 3044.820000 ;
        RECT 25.420000 3131.460000 2834.400000 3134.820000 ;
        RECT 25.420000 3221.460000 2834.400000 3224.820000 ;
        RECT 25.420000 3311.460000 2834.400000 3314.820000 ;
        RECT 25.420000 3401.460000 2834.400000 3404.820000 ;
        RECT 0.000000 3439.440000 2859.820000 3442.540000 ;
        RECT 294.760000 971.390000 296.500000 972.810000 ;
        RECT 763.280000 971.390000 765.020000 972.810000 ;
        RECT 919.760000 971.390000 921.500000 972.810000 ;
        RECT 1388.280000 971.390000 1390.020000 972.810000 ;
        RECT 1544.760000 971.390000 1546.500000 972.810000 ;
        RECT 2013.280000 971.390000 2015.020000 972.810000 ;
        RECT 2174.760000 971.390000 2176.500000 972.810000 ;
        RECT 2643.280000 971.390000 2645.020000 972.810000 ;
        RECT 294.760000 2144.760000 296.500000 2146.180000 ;
        RECT 763.280000 2144.760000 765.020000 2146.180000 ;
        RECT 919.760000 2144.760000 921.500000 2146.180000 ;
        RECT 1388.280000 2144.760000 1390.020000 2146.180000 ;
        RECT 1544.760000 2144.760000 1546.500000 2146.180000 ;
        RECT 2013.280000 2144.760000 2015.020000 2146.180000 ;
        RECT 2174.760000 2144.760000 2176.500000 2146.180000 ;
        RECT 2643.280000 2144.760000 2645.020000 2146.180000 ;
    END
# end of P/G power stripe data as pin

  END vccd1
  OBS
    LAYER li1 ;
      RECT 0.000000 0.000000 2859.820000 3470.040000 ;
    LAYER met1 ;
      RECT 0.000000 0.000000 2859.820000 3470.040000 ;
    LAYER met2 ;
      RECT 2859.480000 3469.275000 2859.820000 3470.040000 ;
      RECT 2749.540000 3469.275000 2858.780000 3470.040000 ;
      RECT 2639.600000 3469.275000 2748.840000 3470.040000 ;
      RECT 2529.660000 3469.275000 2638.900000 3470.040000 ;
      RECT 2419.720000 3469.275000 2528.960000 3470.040000 ;
      RECT 2309.780000 3469.275000 2419.020000 3470.040000 ;
      RECT 2199.840000 3469.275000 2309.080000 3470.040000 ;
      RECT 2089.900000 3469.275000 2199.140000 3470.040000 ;
      RECT 1979.960000 3469.275000 2089.200000 3470.040000 ;
      RECT 1870.020000 3469.275000 1979.260000 3470.040000 ;
      RECT 1760.080000 3469.275000 1869.320000 3470.040000 ;
      RECT 1650.140000 3469.275000 1759.380000 3470.040000 ;
      RECT 1540.200000 3469.275000 1649.440000 3470.040000 ;
      RECT 1429.800000 3469.275000 1539.500000 3470.040000 ;
      RECT 1319.860000 3469.275000 1429.100000 3470.040000 ;
      RECT 1209.920000 3469.275000 1319.160000 3470.040000 ;
      RECT 1099.980000 3469.275000 1209.220000 3470.040000 ;
      RECT 990.040000 3469.275000 1099.280000 3470.040000 ;
      RECT 880.100000 3469.275000 989.340000 3470.040000 ;
      RECT 770.160000 3469.275000 879.400000 3470.040000 ;
      RECT 660.220000 3469.275000 769.460000 3470.040000 ;
      RECT 550.280000 3469.275000 659.520000 3470.040000 ;
      RECT 440.340000 3469.275000 549.580000 3470.040000 ;
      RECT 330.400000 3469.275000 439.640000 3470.040000 ;
      RECT 220.460000 3469.275000 329.700000 3470.040000 ;
      RECT 110.520000 3469.275000 219.760000 3470.040000 ;
      RECT 0.580000 3469.275000 109.820000 3470.040000 ;
      RECT 0.000000 0.765000 2859.820000 3469.275000 ;
      RECT 2854.420000 0.000000 2859.240000 0.765000 ;
      RECT 2848.440000 0.000000 2853.720000 0.765000 ;
      RECT 2842.920000 0.000000 2847.740000 0.765000 ;
      RECT 2836.940000 0.000000 2842.220000 0.765000 ;
      RECT 2830.960000 0.000000 2836.240000 0.765000 ;
      RECT 2825.440000 0.000000 2830.260000 0.765000 ;
      RECT 2819.460000 0.000000 2824.740000 0.765000 ;
      RECT 2813.480000 0.000000 2818.760000 0.765000 ;
      RECT 2807.960000 0.000000 2812.780000 0.765000 ;
      RECT 2801.980000 0.000000 2807.260000 0.765000 ;
      RECT 2796.460000 0.000000 2801.280000 0.765000 ;
      RECT 2790.480000 0.000000 2795.760000 0.765000 ;
      RECT 2784.500000 0.000000 2789.780000 0.765000 ;
      RECT 2778.980000 0.000000 2783.800000 0.765000 ;
      RECT 2773.000000 0.000000 2778.280000 0.765000 ;
      RECT 2767.020000 0.000000 2772.300000 0.765000 ;
      RECT 2761.500000 0.000000 2766.320000 0.765000 ;
      RECT 2755.520000 0.000000 2760.800000 0.765000 ;
      RECT 2749.540000 0.000000 2754.820000 0.765000 ;
      RECT 2744.020000 0.000000 2748.840000 0.765000 ;
      RECT 2738.040000 0.000000 2743.320000 0.765000 ;
      RECT 2732.520000 0.000000 2737.340000 0.765000 ;
      RECT 2726.540000 0.000000 2731.820000 0.765000 ;
      RECT 2720.560000 0.000000 2725.840000 0.765000 ;
      RECT 2715.040000 0.000000 2719.860000 0.765000 ;
      RECT 2709.060000 0.000000 2714.340000 0.765000 ;
      RECT 2703.080000 0.000000 2708.360000 0.765000 ;
      RECT 2697.560000 0.000000 2702.380000 0.765000 ;
      RECT 2691.580000 0.000000 2696.860000 0.765000 ;
      RECT 2685.600000 0.000000 2690.880000 0.765000 ;
      RECT 2680.080000 0.000000 2684.900000 0.765000 ;
      RECT 2674.100000 0.000000 2679.380000 0.765000 ;
      RECT 2668.580000 0.000000 2673.400000 0.765000 ;
      RECT 2662.600000 0.000000 2667.880000 0.765000 ;
      RECT 2656.620000 0.000000 2661.900000 0.765000 ;
      RECT 2651.100000 0.000000 2655.920000 0.765000 ;
      RECT 2645.120000 0.000000 2650.400000 0.765000 ;
      RECT 2639.140000 0.000000 2644.420000 0.765000 ;
      RECT 2633.620000 0.000000 2638.440000 0.765000 ;
      RECT 2627.640000 0.000000 2632.920000 0.765000 ;
      RECT 2622.120000 0.000000 2626.940000 0.765000 ;
      RECT 2616.140000 0.000000 2621.420000 0.765000 ;
      RECT 2610.160000 0.000000 2615.440000 0.765000 ;
      RECT 2604.640000 0.000000 2609.460000 0.765000 ;
      RECT 2598.660000 0.000000 2603.940000 0.765000 ;
      RECT 2592.680000 0.000000 2597.960000 0.765000 ;
      RECT 2587.160000 0.000000 2591.980000 0.765000 ;
      RECT 2581.180000 0.000000 2586.460000 0.765000 ;
      RECT 2575.200000 0.000000 2580.480000 0.765000 ;
      RECT 2569.680000 0.000000 2574.500000 0.765000 ;
      RECT 2563.700000 0.000000 2568.980000 0.765000 ;
      RECT 2558.180000 0.000000 2563.000000 0.765000 ;
      RECT 2552.200000 0.000000 2557.480000 0.765000 ;
      RECT 2546.220000 0.000000 2551.500000 0.765000 ;
      RECT 2540.700000 0.000000 2545.520000 0.765000 ;
      RECT 2534.720000 0.000000 2540.000000 0.765000 ;
      RECT 2528.740000 0.000000 2534.020000 0.765000 ;
      RECT 2523.220000 0.000000 2528.040000 0.765000 ;
      RECT 2517.240000 0.000000 2522.520000 0.765000 ;
      RECT 2511.260000 0.000000 2516.540000 0.765000 ;
      RECT 2505.740000 0.000000 2510.560000 0.765000 ;
      RECT 2499.760000 0.000000 2505.040000 0.765000 ;
      RECT 2494.240000 0.000000 2499.060000 0.765000 ;
      RECT 2488.260000 0.000000 2493.540000 0.765000 ;
      RECT 2482.280000 0.000000 2487.560000 0.765000 ;
      RECT 2476.760000 0.000000 2481.580000 0.765000 ;
      RECT 2470.780000 0.000000 2476.060000 0.765000 ;
      RECT 2464.800000 0.000000 2470.080000 0.765000 ;
      RECT 2459.280000 0.000000 2464.100000 0.765000 ;
      RECT 2453.300000 0.000000 2458.580000 0.765000 ;
      RECT 2447.320000 0.000000 2452.600000 0.765000 ;
      RECT 2441.800000 0.000000 2446.620000 0.765000 ;
      RECT 2435.820000 0.000000 2441.100000 0.765000 ;
      RECT 2430.300000 0.000000 2435.120000 0.765000 ;
      RECT 2424.320000 0.000000 2429.600000 0.765000 ;
      RECT 2418.340000 0.000000 2423.620000 0.765000 ;
      RECT 2412.820000 0.000000 2417.640000 0.765000 ;
      RECT 2406.840000 0.000000 2412.120000 0.765000 ;
      RECT 2400.860000 0.000000 2406.140000 0.765000 ;
      RECT 2395.340000 0.000000 2400.160000 0.765000 ;
      RECT 2389.360000 0.000000 2394.640000 0.765000 ;
      RECT 2383.840000 0.000000 2388.660000 0.765000 ;
      RECT 2377.860000 0.000000 2383.140000 0.765000 ;
      RECT 2371.880000 0.000000 2377.160000 0.765000 ;
      RECT 2366.360000 0.000000 2371.180000 0.765000 ;
      RECT 2360.380000 0.000000 2365.660000 0.765000 ;
      RECT 2354.400000 0.000000 2359.680000 0.765000 ;
      RECT 2348.880000 0.000000 2353.700000 0.765000 ;
      RECT 2342.900000 0.000000 2348.180000 0.765000 ;
      RECT 2336.920000 0.000000 2342.200000 0.765000 ;
      RECT 2331.400000 0.000000 2336.220000 0.765000 ;
      RECT 2325.420000 0.000000 2330.700000 0.765000 ;
      RECT 2319.900000 0.000000 2324.720000 0.765000 ;
      RECT 2313.920000 0.000000 2319.200000 0.765000 ;
      RECT 2307.940000 0.000000 2313.220000 0.765000 ;
      RECT 2302.420000 0.000000 2307.240000 0.765000 ;
      RECT 2296.440000 0.000000 2301.720000 0.765000 ;
      RECT 2290.460000 0.000000 2295.740000 0.765000 ;
      RECT 2284.940000 0.000000 2289.760000 0.765000 ;
      RECT 2278.960000 0.000000 2284.240000 0.765000 ;
      RECT 2272.980000 0.000000 2278.260000 0.765000 ;
      RECT 2267.460000 0.000000 2272.280000 0.765000 ;
      RECT 2261.480000 0.000000 2266.760000 0.765000 ;
      RECT 2255.960000 0.000000 2260.780000 0.765000 ;
      RECT 2249.980000 0.000000 2255.260000 0.765000 ;
      RECT 2244.000000 0.000000 2249.280000 0.765000 ;
      RECT 2238.480000 0.000000 2243.300000 0.765000 ;
      RECT 2232.500000 0.000000 2237.780000 0.765000 ;
      RECT 2226.520000 0.000000 2231.800000 0.765000 ;
      RECT 2221.000000 0.000000 2225.820000 0.765000 ;
      RECT 2215.020000 0.000000 2220.300000 0.765000 ;
      RECT 2209.040000 0.000000 2214.320000 0.765000 ;
      RECT 2203.520000 0.000000 2208.340000 0.765000 ;
      RECT 2197.540000 0.000000 2202.820000 0.765000 ;
      RECT 2192.020000 0.000000 2196.840000 0.765000 ;
      RECT 2186.040000 0.000000 2191.320000 0.765000 ;
      RECT 2180.060000 0.000000 2185.340000 0.765000 ;
      RECT 2174.540000 0.000000 2179.360000 0.765000 ;
      RECT 2168.560000 0.000000 2173.840000 0.765000 ;
      RECT 2162.580000 0.000000 2167.860000 0.765000 ;
      RECT 2157.060000 0.000000 2161.880000 0.765000 ;
      RECT 2151.080000 0.000000 2156.360000 0.765000 ;
      RECT 2145.100000 0.000000 2150.380000 0.765000 ;
      RECT 2139.580000 0.000000 2144.400000 0.765000 ;
      RECT 2133.600000 0.000000 2138.880000 0.765000 ;
      RECT 2128.080000 0.000000 2132.900000 0.765000 ;
      RECT 2122.100000 0.000000 2127.380000 0.765000 ;
      RECT 2116.120000 0.000000 2121.400000 0.765000 ;
      RECT 2110.600000 0.000000 2115.420000 0.765000 ;
      RECT 2104.620000 0.000000 2109.900000 0.765000 ;
      RECT 2098.640000 0.000000 2103.920000 0.765000 ;
      RECT 2093.120000 0.000000 2097.940000 0.765000 ;
      RECT 2087.140000 0.000000 2092.420000 0.765000 ;
      RECT 2081.620000 0.000000 2086.440000 0.765000 ;
      RECT 2075.640000 0.000000 2080.920000 0.765000 ;
      RECT 2069.660000 0.000000 2074.940000 0.765000 ;
      RECT 2064.140000 0.000000 2068.960000 0.765000 ;
      RECT 2058.160000 0.000000 2063.440000 0.765000 ;
      RECT 2052.180000 0.000000 2057.460000 0.765000 ;
      RECT 2046.660000 0.000000 2051.480000 0.765000 ;
      RECT 2040.680000 0.000000 2045.960000 0.765000 ;
      RECT 2034.700000 0.000000 2039.980000 0.765000 ;
      RECT 2029.180000 0.000000 2034.000000 0.765000 ;
      RECT 2023.200000 0.000000 2028.480000 0.765000 ;
      RECT 2017.680000 0.000000 2022.500000 0.765000 ;
      RECT 2011.700000 0.000000 2016.980000 0.765000 ;
      RECT 2005.720000 0.000000 2011.000000 0.765000 ;
      RECT 2000.200000 0.000000 2005.020000 0.765000 ;
      RECT 1994.220000 0.000000 1999.500000 0.765000 ;
      RECT 1988.240000 0.000000 1993.520000 0.765000 ;
      RECT 1982.720000 0.000000 1987.540000 0.765000 ;
      RECT 1976.740000 0.000000 1982.020000 0.765000 ;
      RECT 1970.760000 0.000000 1976.040000 0.765000 ;
      RECT 1965.240000 0.000000 1970.060000 0.765000 ;
      RECT 1959.260000 0.000000 1964.540000 0.765000 ;
      RECT 1953.740000 0.000000 1958.560000 0.765000 ;
      RECT 1947.760000 0.000000 1953.040000 0.765000 ;
      RECT 1941.780000 0.000000 1947.060000 0.765000 ;
      RECT 1936.260000 0.000000 1941.080000 0.765000 ;
      RECT 1930.280000 0.000000 1935.560000 0.765000 ;
      RECT 1924.300000 0.000000 1929.580000 0.765000 ;
      RECT 1918.780000 0.000000 1923.600000 0.765000 ;
      RECT 1912.800000 0.000000 1918.080000 0.765000 ;
      RECT 1906.820000 0.000000 1912.100000 0.765000 ;
      RECT 1901.300000 0.000000 1906.120000 0.765000 ;
      RECT 1895.320000 0.000000 1900.600000 0.765000 ;
      RECT 1889.800000 0.000000 1894.620000 0.765000 ;
      RECT 1883.820000 0.000000 1889.100000 0.765000 ;
      RECT 1877.840000 0.000000 1883.120000 0.765000 ;
      RECT 1872.320000 0.000000 1877.140000 0.765000 ;
      RECT 1866.340000 0.000000 1871.620000 0.765000 ;
      RECT 1860.360000 0.000000 1865.640000 0.765000 ;
      RECT 1854.840000 0.000000 1859.660000 0.765000 ;
      RECT 1848.860000 0.000000 1854.140000 0.765000 ;
      RECT 1843.340000 0.000000 1848.160000 0.765000 ;
      RECT 1837.360000 0.000000 1842.640000 0.765000 ;
      RECT 1831.380000 0.000000 1836.660000 0.765000 ;
      RECT 1825.860000 0.000000 1830.680000 0.765000 ;
      RECT 1819.880000 0.000000 1825.160000 0.765000 ;
      RECT 1813.900000 0.000000 1819.180000 0.765000 ;
      RECT 1808.380000 0.000000 1813.200000 0.765000 ;
      RECT 1802.400000 0.000000 1807.680000 0.765000 ;
      RECT 1796.420000 0.000000 1801.700000 0.765000 ;
      RECT 1790.900000 0.000000 1795.720000 0.765000 ;
      RECT 1784.920000 0.000000 1790.200000 0.765000 ;
      RECT 1779.400000 0.000000 1784.220000 0.765000 ;
      RECT 1773.420000 0.000000 1778.700000 0.765000 ;
      RECT 1767.440000 0.000000 1772.720000 0.765000 ;
      RECT 1761.920000 0.000000 1766.740000 0.765000 ;
      RECT 1755.940000 0.000000 1761.220000 0.765000 ;
      RECT 1749.960000 0.000000 1755.240000 0.765000 ;
      RECT 1744.440000 0.000000 1749.260000 0.765000 ;
      RECT 1738.460000 0.000000 1743.740000 0.765000 ;
      RECT 1732.480000 0.000000 1737.760000 0.765000 ;
      RECT 1726.960000 0.000000 1731.780000 0.765000 ;
      RECT 1720.980000 0.000000 1726.260000 0.765000 ;
      RECT 1715.460000 0.000000 1720.280000 0.765000 ;
      RECT 1709.480000 0.000000 1714.760000 0.765000 ;
      RECT 1703.500000 0.000000 1708.780000 0.765000 ;
      RECT 1697.980000 0.000000 1702.800000 0.765000 ;
      RECT 1692.000000 0.000000 1697.280000 0.765000 ;
      RECT 1686.020000 0.000000 1691.300000 0.765000 ;
      RECT 1680.500000 0.000000 1685.320000 0.765000 ;
      RECT 1674.520000 0.000000 1679.800000 0.765000 ;
      RECT 1668.540000 0.000000 1673.820000 0.765000 ;
      RECT 1663.020000 0.000000 1667.840000 0.765000 ;
      RECT 1657.040000 0.000000 1662.320000 0.765000 ;
      RECT 1651.520000 0.000000 1656.340000 0.765000 ;
      RECT 1645.540000 0.000000 1650.820000 0.765000 ;
      RECT 1639.560000 0.000000 1644.840000 0.765000 ;
      RECT 1634.040000 0.000000 1638.860000 0.765000 ;
      RECT 1628.060000 0.000000 1633.340000 0.765000 ;
      RECT 1622.080000 0.000000 1627.360000 0.765000 ;
      RECT 1616.560000 0.000000 1621.380000 0.765000 ;
      RECT 1610.580000 0.000000 1615.860000 0.765000 ;
      RECT 1605.060000 0.000000 1609.880000 0.765000 ;
      RECT 1599.080000 0.000000 1604.360000 0.765000 ;
      RECT 1593.100000 0.000000 1598.380000 0.765000 ;
      RECT 1587.580000 0.000000 1592.400000 0.765000 ;
      RECT 1581.600000 0.000000 1586.880000 0.765000 ;
      RECT 1575.620000 0.000000 1580.900000 0.765000 ;
      RECT 1570.100000 0.000000 1574.920000 0.765000 ;
      RECT 1564.120000 0.000000 1569.400000 0.765000 ;
      RECT 1558.140000 0.000000 1563.420000 0.765000 ;
      RECT 1552.620000 0.000000 1557.440000 0.765000 ;
      RECT 1546.640000 0.000000 1551.920000 0.765000 ;
      RECT 1541.120000 0.000000 1545.940000 0.765000 ;
      RECT 1535.140000 0.000000 1540.420000 0.765000 ;
      RECT 1529.160000 0.000000 1534.440000 0.765000 ;
      RECT 1523.640000 0.000000 1528.460000 0.765000 ;
      RECT 1517.660000 0.000000 1522.940000 0.765000 ;
      RECT 1511.680000 0.000000 1516.960000 0.765000 ;
      RECT 1506.160000 0.000000 1510.980000 0.765000 ;
      RECT 1500.180000 0.000000 1505.460000 0.765000 ;
      RECT 1494.200000 0.000000 1499.480000 0.765000 ;
      RECT 1488.680000 0.000000 1493.500000 0.765000 ;
      RECT 1482.700000 0.000000 1487.980000 0.765000 ;
      RECT 1477.180000 0.000000 1482.000000 0.765000 ;
      RECT 1471.200000 0.000000 1476.480000 0.765000 ;
      RECT 1465.220000 0.000000 1470.500000 0.765000 ;
      RECT 1459.700000 0.000000 1464.520000 0.765000 ;
      RECT 1453.720000 0.000000 1459.000000 0.765000 ;
      RECT 1447.740000 0.000000 1453.020000 0.765000 ;
      RECT 1442.220000 0.000000 1447.040000 0.765000 ;
      RECT 1436.240000 0.000000 1441.520000 0.765000 ;
      RECT 1430.720000 0.000000 1435.540000 0.765000 ;
      RECT 1424.740000 0.000000 1430.020000 0.765000 ;
      RECT 1418.760000 0.000000 1424.040000 0.765000 ;
      RECT 1413.240000 0.000000 1418.060000 0.765000 ;
      RECT 1407.260000 0.000000 1412.540000 0.765000 ;
      RECT 1401.280000 0.000000 1406.560000 0.765000 ;
      RECT 1395.760000 0.000000 1400.580000 0.765000 ;
      RECT 1389.780000 0.000000 1395.060000 0.765000 ;
      RECT 1383.800000 0.000000 1389.080000 0.765000 ;
      RECT 1378.280000 0.000000 1383.100000 0.765000 ;
      RECT 1372.300000 0.000000 1377.580000 0.765000 ;
      RECT 1366.780000 0.000000 1371.600000 0.765000 ;
      RECT 1360.800000 0.000000 1366.080000 0.765000 ;
      RECT 1354.820000 0.000000 1360.100000 0.765000 ;
      RECT 1349.300000 0.000000 1354.120000 0.765000 ;
      RECT 1343.320000 0.000000 1348.600000 0.765000 ;
      RECT 1337.340000 0.000000 1342.620000 0.765000 ;
      RECT 1331.820000 0.000000 1336.640000 0.765000 ;
      RECT 1325.840000 0.000000 1331.120000 0.765000 ;
      RECT 1319.860000 0.000000 1325.140000 0.765000 ;
      RECT 1314.340000 0.000000 1319.160000 0.765000 ;
      RECT 1308.360000 0.000000 1313.640000 0.765000 ;
      RECT 1302.840000 0.000000 1307.660000 0.765000 ;
      RECT 1296.860000 0.000000 1302.140000 0.765000 ;
      RECT 1290.880000 0.000000 1296.160000 0.765000 ;
      RECT 1285.360000 0.000000 1290.180000 0.765000 ;
      RECT 1279.380000 0.000000 1284.660000 0.765000 ;
      RECT 1273.400000 0.000000 1278.680000 0.765000 ;
      RECT 1267.880000 0.000000 1272.700000 0.765000 ;
      RECT 1261.900000 0.000000 1267.180000 0.765000 ;
      RECT 1255.920000 0.000000 1261.200000 0.765000 ;
      RECT 1250.400000 0.000000 1255.220000 0.765000 ;
      RECT 1244.420000 0.000000 1249.700000 0.765000 ;
      RECT 1238.900000 0.000000 1243.720000 0.765000 ;
      RECT 1232.920000 0.000000 1238.200000 0.765000 ;
      RECT 1226.940000 0.000000 1232.220000 0.765000 ;
      RECT 1221.420000 0.000000 1226.240000 0.765000 ;
      RECT 1215.440000 0.000000 1220.720000 0.765000 ;
      RECT 1209.460000 0.000000 1214.740000 0.765000 ;
      RECT 1203.940000 0.000000 1208.760000 0.765000 ;
      RECT 1197.960000 0.000000 1203.240000 0.765000 ;
      RECT 1192.440000 0.000000 1197.260000 0.765000 ;
      RECT 1186.460000 0.000000 1191.740000 0.765000 ;
      RECT 1180.480000 0.000000 1185.760000 0.765000 ;
      RECT 1174.960000 0.000000 1179.780000 0.765000 ;
      RECT 1168.980000 0.000000 1174.260000 0.765000 ;
      RECT 1163.000000 0.000000 1168.280000 0.765000 ;
      RECT 1157.480000 0.000000 1162.300000 0.765000 ;
      RECT 1151.500000 0.000000 1156.780000 0.765000 ;
      RECT 1145.520000 0.000000 1150.800000 0.765000 ;
      RECT 1140.000000 0.000000 1144.820000 0.765000 ;
      RECT 1134.020000 0.000000 1139.300000 0.765000 ;
      RECT 1128.500000 0.000000 1133.320000 0.765000 ;
      RECT 1122.520000 0.000000 1127.800000 0.765000 ;
      RECT 1116.540000 0.000000 1121.820000 0.765000 ;
      RECT 1111.020000 0.000000 1115.840000 0.765000 ;
      RECT 1105.040000 0.000000 1110.320000 0.765000 ;
      RECT 1099.060000 0.000000 1104.340000 0.765000 ;
      RECT 1093.540000 0.000000 1098.360000 0.765000 ;
      RECT 1087.560000 0.000000 1092.840000 0.765000 ;
      RECT 1081.580000 0.000000 1086.860000 0.765000 ;
      RECT 1076.060000 0.000000 1080.880000 0.765000 ;
      RECT 1070.080000 0.000000 1075.360000 0.765000 ;
      RECT 1064.560000 0.000000 1069.380000 0.765000 ;
      RECT 1058.580000 0.000000 1063.860000 0.765000 ;
      RECT 1052.600000 0.000000 1057.880000 0.765000 ;
      RECT 1047.080000 0.000000 1051.900000 0.765000 ;
      RECT 1041.100000 0.000000 1046.380000 0.765000 ;
      RECT 1035.120000 0.000000 1040.400000 0.765000 ;
      RECT 1029.600000 0.000000 1034.420000 0.765000 ;
      RECT 1023.620000 0.000000 1028.900000 0.765000 ;
      RECT 1017.640000 0.000000 1022.920000 0.765000 ;
      RECT 1012.120000 0.000000 1016.940000 0.765000 ;
      RECT 1006.140000 0.000000 1011.420000 0.765000 ;
      RECT 1000.620000 0.000000 1005.440000 0.765000 ;
      RECT 994.640000 0.000000 999.920000 0.765000 ;
      RECT 988.660000 0.000000 993.940000 0.765000 ;
      RECT 983.140000 0.000000 987.960000 0.765000 ;
      RECT 977.160000 0.000000 982.440000 0.765000 ;
      RECT 971.180000 0.000000 976.460000 0.765000 ;
      RECT 965.660000 0.000000 970.480000 0.765000 ;
      RECT 959.680000 0.000000 964.960000 0.765000 ;
      RECT 954.160000 0.000000 958.980000 0.765000 ;
      RECT 948.180000 0.000000 953.460000 0.765000 ;
      RECT 942.200000 0.000000 947.480000 0.765000 ;
      RECT 936.680000 0.000000 941.500000 0.765000 ;
      RECT 930.700000 0.000000 935.980000 0.765000 ;
      RECT 924.720000 0.000000 930.000000 0.765000 ;
      RECT 919.200000 0.000000 924.020000 0.765000 ;
      RECT 913.220000 0.000000 918.500000 0.765000 ;
      RECT 907.240000 0.000000 912.520000 0.765000 ;
      RECT 901.720000 0.000000 906.540000 0.765000 ;
      RECT 895.740000 0.000000 901.020000 0.765000 ;
      RECT 890.220000 0.000000 895.040000 0.765000 ;
      RECT 884.240000 0.000000 889.520000 0.765000 ;
      RECT 878.260000 0.000000 883.540000 0.765000 ;
      RECT 872.740000 0.000000 877.560000 0.765000 ;
      RECT 866.760000 0.000000 872.040000 0.765000 ;
      RECT 860.780000 0.000000 866.060000 0.765000 ;
      RECT 855.260000 0.000000 860.080000 0.765000 ;
      RECT 849.280000 0.000000 854.560000 0.765000 ;
      RECT 843.300000 0.000000 848.580000 0.765000 ;
      RECT 837.780000 0.000000 842.600000 0.765000 ;
      RECT 831.800000 0.000000 837.080000 0.765000 ;
      RECT 826.280000 0.000000 831.100000 0.765000 ;
      RECT 820.300000 0.000000 825.580000 0.765000 ;
      RECT 814.320000 0.000000 819.600000 0.765000 ;
      RECT 808.800000 0.000000 813.620000 0.765000 ;
      RECT 802.820000 0.000000 808.100000 0.765000 ;
      RECT 796.840000 0.000000 802.120000 0.765000 ;
      RECT 791.320000 0.000000 796.140000 0.765000 ;
      RECT 785.340000 0.000000 790.620000 0.765000 ;
      RECT 779.360000 0.000000 784.640000 0.765000 ;
      RECT 773.840000 0.000000 778.660000 0.765000 ;
      RECT 767.860000 0.000000 773.140000 0.765000 ;
      RECT 762.340000 0.000000 767.160000 0.765000 ;
      RECT 756.360000 0.000000 761.640000 0.765000 ;
      RECT 750.380000 0.000000 755.660000 0.765000 ;
      RECT 744.860000 0.000000 749.680000 0.765000 ;
      RECT 738.880000 0.000000 744.160000 0.765000 ;
      RECT 732.900000 0.000000 738.180000 0.765000 ;
      RECT 727.380000 0.000000 732.200000 0.765000 ;
      RECT 721.400000 0.000000 726.680000 0.765000 ;
      RECT 715.420000 0.000000 720.700000 0.765000 ;
      RECT 709.900000 0.000000 714.720000 0.765000 ;
      RECT 703.920000 0.000000 709.200000 0.765000 ;
      RECT 698.400000 0.000000 703.220000 0.765000 ;
      RECT 692.420000 0.000000 697.700000 0.765000 ;
      RECT 686.440000 0.000000 691.720000 0.765000 ;
      RECT 680.920000 0.000000 685.740000 0.765000 ;
      RECT 674.940000 0.000000 680.220000 0.765000 ;
      RECT 668.960000 0.000000 674.240000 0.765000 ;
      RECT 663.440000 0.000000 668.260000 0.765000 ;
      RECT 657.460000 0.000000 662.740000 0.765000 ;
      RECT 651.940000 0.000000 656.760000 0.765000 ;
      RECT 645.960000 0.000000 651.240000 0.765000 ;
      RECT 639.980000 0.000000 645.260000 0.765000 ;
      RECT 634.460000 0.000000 639.280000 0.765000 ;
      RECT 628.480000 0.000000 633.760000 0.765000 ;
      RECT 622.500000 0.000000 627.780000 0.765000 ;
      RECT 616.980000 0.000000 621.800000 0.765000 ;
      RECT 611.000000 0.000000 616.280000 0.765000 ;
      RECT 605.020000 0.000000 610.300000 0.765000 ;
      RECT 599.500000 0.000000 604.320000 0.765000 ;
      RECT 593.520000 0.000000 598.800000 0.765000 ;
      RECT 588.000000 0.000000 592.820000 0.765000 ;
      RECT 582.020000 0.000000 587.300000 0.765000 ;
      RECT 576.040000 0.000000 581.320000 0.765000 ;
      RECT 570.520000 0.000000 575.340000 0.765000 ;
      RECT 564.540000 0.000000 569.820000 0.765000 ;
      RECT 558.560000 0.000000 563.840000 0.765000 ;
      RECT 553.040000 0.000000 557.860000 0.765000 ;
      RECT 547.060000 0.000000 552.340000 0.765000 ;
      RECT 541.080000 0.000000 546.360000 0.765000 ;
      RECT 535.560000 0.000000 540.380000 0.765000 ;
      RECT 529.580000 0.000000 534.860000 0.765000 ;
      RECT 524.060000 0.000000 528.880000 0.765000 ;
      RECT 518.080000 0.000000 523.360000 0.765000 ;
      RECT 512.100000 0.000000 517.380000 0.765000 ;
      RECT 506.580000 0.000000 511.400000 0.765000 ;
      RECT 500.600000 0.000000 505.880000 0.765000 ;
      RECT 494.620000 0.000000 499.900000 0.765000 ;
      RECT 489.100000 0.000000 493.920000 0.765000 ;
      RECT 483.120000 0.000000 488.400000 0.765000 ;
      RECT 477.140000 0.000000 482.420000 0.765000 ;
      RECT 471.620000 0.000000 476.440000 0.765000 ;
      RECT 465.640000 0.000000 470.920000 0.765000 ;
      RECT 460.120000 0.000000 464.940000 0.765000 ;
      RECT 454.140000 0.000000 459.420000 0.765000 ;
      RECT 448.160000 0.000000 453.440000 0.765000 ;
      RECT 442.640000 0.000000 447.460000 0.765000 ;
      RECT 436.660000 0.000000 441.940000 0.765000 ;
      RECT 430.680000 0.000000 435.960000 0.765000 ;
      RECT 425.160000 0.000000 429.980000 0.765000 ;
      RECT 419.180000 0.000000 424.460000 0.765000 ;
      RECT 413.660000 0.000000 418.480000 0.765000 ;
      RECT 407.680000 0.000000 412.960000 0.765000 ;
      RECT 401.700000 0.000000 406.980000 0.765000 ;
      RECT 396.180000 0.000000 401.000000 0.765000 ;
      RECT 390.200000 0.000000 395.480000 0.765000 ;
      RECT 384.220000 0.000000 389.500000 0.765000 ;
      RECT 378.700000 0.000000 383.520000 0.765000 ;
      RECT 372.720000 0.000000 378.000000 0.765000 ;
      RECT 366.740000 0.000000 372.020000 0.765000 ;
      RECT 361.220000 0.000000 366.040000 0.765000 ;
      RECT 355.240000 0.000000 360.520000 0.765000 ;
      RECT 349.720000 0.000000 354.540000 0.765000 ;
      RECT 343.740000 0.000000 349.020000 0.765000 ;
      RECT 337.760000 0.000000 343.040000 0.765000 ;
      RECT 332.240000 0.000000 337.060000 0.765000 ;
      RECT 326.260000 0.000000 331.540000 0.765000 ;
      RECT 320.280000 0.000000 325.560000 0.765000 ;
      RECT 314.760000 0.000000 319.580000 0.765000 ;
      RECT 308.780000 0.000000 314.060000 0.765000 ;
      RECT 302.800000 0.000000 308.080000 0.765000 ;
      RECT 297.280000 0.000000 302.100000 0.765000 ;
      RECT 291.300000 0.000000 296.580000 0.765000 ;
      RECT 285.780000 0.000000 290.600000 0.765000 ;
      RECT 279.800000 0.000000 285.080000 0.765000 ;
      RECT 273.820000 0.000000 279.100000 0.765000 ;
      RECT 268.300000 0.000000 273.120000 0.765000 ;
      RECT 262.320000 0.000000 267.600000 0.765000 ;
      RECT 256.340000 0.000000 261.620000 0.765000 ;
      RECT 250.820000 0.000000 255.640000 0.765000 ;
      RECT 244.840000 0.000000 250.120000 0.765000 ;
      RECT 238.860000 0.000000 244.140000 0.765000 ;
      RECT 233.340000 0.000000 238.160000 0.765000 ;
      RECT 227.360000 0.000000 232.640000 0.765000 ;
      RECT 221.840000 0.000000 226.660000 0.765000 ;
      RECT 215.860000 0.000000 221.140000 0.765000 ;
      RECT 209.880000 0.000000 215.160000 0.765000 ;
      RECT 204.360000 0.000000 209.180000 0.765000 ;
      RECT 198.380000 0.000000 203.660000 0.765000 ;
      RECT 192.400000 0.000000 197.680000 0.765000 ;
      RECT 186.880000 0.000000 191.700000 0.765000 ;
      RECT 180.900000 0.000000 186.180000 0.765000 ;
      RECT 175.380000 0.000000 180.200000 0.765000 ;
      RECT 169.400000 0.000000 174.680000 0.765000 ;
      RECT 163.420000 0.000000 168.700000 0.765000 ;
      RECT 157.900000 0.000000 162.720000 0.765000 ;
      RECT 151.920000 0.000000 157.200000 0.765000 ;
      RECT 145.940000 0.000000 151.220000 0.765000 ;
      RECT 140.420000 0.000000 145.240000 0.765000 ;
      RECT 134.440000 0.000000 139.720000 0.765000 ;
      RECT 128.460000 0.000000 133.740000 0.765000 ;
      RECT 122.940000 0.000000 127.760000 0.765000 ;
      RECT 116.960000 0.000000 122.240000 0.765000 ;
      RECT 111.440000 0.000000 116.260000 0.765000 ;
      RECT 105.460000 0.000000 110.740000 0.765000 ;
      RECT 99.480000 0.000000 104.760000 0.765000 ;
      RECT 93.960000 0.000000 98.780000 0.765000 ;
      RECT 87.980000 0.000000 93.260000 0.765000 ;
      RECT 82.000000 0.000000 87.280000 0.765000 ;
      RECT 76.480000 0.000000 81.300000 0.765000 ;
      RECT 70.500000 0.000000 75.780000 0.765000 ;
      RECT 64.520000 0.000000 69.800000 0.765000 ;
      RECT 59.000000 0.000000 63.820000 0.765000 ;
      RECT 53.020000 0.000000 58.300000 0.765000 ;
      RECT 47.500000 0.000000 52.320000 0.765000 ;
      RECT 41.520000 0.000000 46.800000 0.765000 ;
      RECT 35.540000 0.000000 40.820000 0.765000 ;
      RECT 30.020000 0.000000 34.840000 0.765000 ;
      RECT 24.040000 0.000000 29.320000 0.765000 ;
      RECT 18.060000 0.000000 23.340000 0.765000 ;
      RECT 12.540000 0.000000 17.360000 0.765000 ;
      RECT 6.560000 0.000000 11.840000 0.765000 ;
      RECT 0.580000 0.000000 5.860000 0.765000 ;
    LAYER met3 ;
      RECT 1.200000 3469.190000 2858.620000 3470.040000 ;
      RECT 0.000000 3391.600000 2859.820000 3469.190000 ;
      RECT 0.000000 3390.500000 2858.620000 3391.600000 ;
      RECT 0.000000 3385.500000 2859.820000 3390.500000 ;
      RECT 1.200000 3384.400000 2859.820000 3385.500000 ;
      RECT 0.000000 3312.910000 2859.820000 3384.400000 ;
      RECT 0.000000 3311.810000 2858.620000 3312.910000 ;
      RECT 0.000000 3300.710000 2859.820000 3311.810000 ;
      RECT 1.200000 3299.610000 2859.820000 3300.710000 ;
      RECT 0.000000 3234.220000 2859.820000 3299.610000 ;
      RECT 0.000000 3233.120000 2858.620000 3234.220000 ;
      RECT 0.000000 3215.920000 2859.820000 3233.120000 ;
      RECT 1.200000 3214.820000 2859.820000 3215.920000 ;
      RECT 0.000000 3154.920000 2859.820000 3214.820000 ;
      RECT 0.000000 3153.820000 2858.620000 3154.920000 ;
      RECT 0.000000 3131.740000 2859.820000 3153.820000 ;
      RECT 1.200000 3130.640000 2859.820000 3131.740000 ;
      RECT 0.000000 3076.230000 2859.820000 3130.640000 ;
      RECT 0.000000 3075.130000 2858.620000 3076.230000 ;
      RECT 0.000000 3046.950000 2859.820000 3075.130000 ;
      RECT 1.200000 3045.850000 2859.820000 3046.950000 ;
      RECT 0.000000 2997.540000 2859.820000 3045.850000 ;
      RECT 0.000000 2996.440000 2858.620000 2997.540000 ;
      RECT 0.000000 2962.160000 2859.820000 2996.440000 ;
      RECT 1.200000 2961.060000 2859.820000 2962.160000 ;
      RECT 0.000000 2918.850000 2859.820000 2961.060000 ;
      RECT 0.000000 2917.750000 2858.620000 2918.850000 ;
      RECT 0.000000 2877.980000 2859.820000 2917.750000 ;
      RECT 1.200000 2876.880000 2859.820000 2877.980000 ;
      RECT 0.000000 2839.550000 2859.820000 2876.880000 ;
      RECT 0.000000 2838.450000 2858.620000 2839.550000 ;
      RECT 0.000000 2793.190000 2859.820000 2838.450000 ;
      RECT 1.200000 2792.090000 2859.820000 2793.190000 ;
      RECT 0.000000 2760.860000 2859.820000 2792.090000 ;
      RECT 0.000000 2759.760000 2858.620000 2760.860000 ;
      RECT 0.000000 2708.400000 2859.820000 2759.760000 ;
      RECT 1.200000 2707.300000 2859.820000 2708.400000 ;
      RECT 0.000000 2682.170000 2859.820000 2707.300000 ;
      RECT 0.000000 2681.070000 2858.620000 2682.170000 ;
      RECT 0.000000 2623.610000 2859.820000 2681.070000 ;
      RECT 1.200000 2622.510000 2859.820000 2623.610000 ;
      RECT 0.000000 2603.480000 2859.820000 2622.510000 ;
      RECT 0.000000 2602.380000 2858.620000 2603.480000 ;
      RECT 0.000000 2539.430000 2859.820000 2602.380000 ;
      RECT 1.200000 2538.330000 2859.820000 2539.430000 ;
      RECT 0.000000 2524.180000 2859.820000 2538.330000 ;
      RECT 0.000000 2523.080000 2858.620000 2524.180000 ;
      RECT 0.000000 2454.640000 2859.820000 2523.080000 ;
      RECT 1.200000 2453.540000 2859.820000 2454.640000 ;
      RECT 0.000000 2445.490000 2859.820000 2453.540000 ;
      RECT 0.000000 2444.390000 2858.620000 2445.490000 ;
      RECT 0.000000 2369.850000 2859.820000 2444.390000 ;
      RECT 1.200000 2368.750000 2859.820000 2369.850000 ;
      RECT 0.000000 2366.800000 2859.820000 2368.750000 ;
      RECT 0.000000 2365.700000 2858.620000 2366.800000 ;
      RECT 0.000000 2288.110000 2859.820000 2365.700000 ;
      RECT 0.000000 2287.010000 2858.620000 2288.110000 ;
      RECT 0.000000 2285.670000 2859.820000 2287.010000 ;
      RECT 1.200000 2284.570000 2859.820000 2285.670000 ;
      RECT 0.000000 2208.810000 2859.820000 2284.570000 ;
      RECT 0.000000 2207.710000 2858.620000 2208.810000 ;
      RECT 0.000000 2200.880000 2859.820000 2207.710000 ;
      RECT 1.200000 2199.780000 2859.820000 2200.880000 ;
      RECT 0.000000 2130.120000 2859.820000 2199.780000 ;
      RECT 0.000000 2129.020000 2858.620000 2130.120000 ;
      RECT 0.000000 2116.090000 2859.820000 2129.020000 ;
      RECT 1.200000 2114.990000 2859.820000 2116.090000 ;
      RECT 0.000000 2051.430000 2859.820000 2114.990000 ;
      RECT 0.000000 2050.330000 2858.620000 2051.430000 ;
      RECT 0.000000 2031.300000 2859.820000 2050.330000 ;
      RECT 1.200000 2030.200000 2859.820000 2031.300000 ;
      RECT 0.000000 1972.740000 2859.820000 2030.200000 ;
      RECT 0.000000 1971.640000 2858.620000 1972.740000 ;
      RECT 0.000000 1947.120000 2859.820000 1971.640000 ;
      RECT 1.200000 1946.020000 2859.820000 1947.120000 ;
      RECT 0.000000 1893.440000 2859.820000 1946.020000 ;
      RECT 0.000000 1892.340000 2858.620000 1893.440000 ;
      RECT 0.000000 1862.330000 2859.820000 1892.340000 ;
      RECT 1.200000 1861.230000 2859.820000 1862.330000 ;
      RECT 0.000000 1814.750000 2859.820000 1861.230000 ;
      RECT 0.000000 1813.650000 2858.620000 1814.750000 ;
      RECT 0.000000 1777.540000 2859.820000 1813.650000 ;
      RECT 1.200000 1776.440000 2859.820000 1777.540000 ;
      RECT 0.000000 1736.060000 2859.820000 1776.440000 ;
      RECT 0.000000 1734.960000 2858.620000 1736.060000 ;
      RECT 0.000000 1693.360000 2859.820000 1734.960000 ;
      RECT 1.200000 1692.260000 2859.820000 1693.360000 ;
      RECT 0.000000 1657.370000 2859.820000 1692.260000 ;
      RECT 0.000000 1656.270000 2858.620000 1657.370000 ;
      RECT 0.000000 1608.570000 2859.820000 1656.270000 ;
      RECT 1.200000 1607.470000 2859.820000 1608.570000 ;
      RECT 0.000000 1578.070000 2859.820000 1607.470000 ;
      RECT 0.000000 1576.970000 2858.620000 1578.070000 ;
      RECT 0.000000 1523.780000 2859.820000 1576.970000 ;
      RECT 1.200000 1522.680000 2859.820000 1523.780000 ;
      RECT 0.000000 1499.380000 2859.820000 1522.680000 ;
      RECT 0.000000 1498.280000 2858.620000 1499.380000 ;
      RECT 0.000000 1439.600000 2859.820000 1498.280000 ;
      RECT 1.200000 1438.500000 2859.820000 1439.600000 ;
      RECT 0.000000 1420.690000 2859.820000 1438.500000 ;
      RECT 0.000000 1419.590000 2858.620000 1420.690000 ;
      RECT 0.000000 1354.810000 2859.820000 1419.590000 ;
      RECT 1.200000 1353.710000 2859.820000 1354.810000 ;
      RECT 0.000000 1342.000000 2859.820000 1353.710000 ;
      RECT 0.000000 1340.900000 2858.620000 1342.000000 ;
      RECT 0.000000 1270.020000 2859.820000 1340.900000 ;
      RECT 1.200000 1268.920000 2859.820000 1270.020000 ;
      RECT 0.000000 1262.700000 2859.820000 1268.920000 ;
      RECT 0.000000 1261.600000 2858.620000 1262.700000 ;
      RECT 0.000000 1185.230000 2859.820000 1261.600000 ;
      RECT 1.200000 1184.130000 2859.820000 1185.230000 ;
      RECT 0.000000 1184.010000 2859.820000 1184.130000 ;
      RECT 0.000000 1182.910000 2858.620000 1184.010000 ;
      RECT 0.000000 1105.320000 2859.820000 1182.910000 ;
      RECT 0.000000 1104.220000 2858.620000 1105.320000 ;
      RECT 0.000000 1101.050000 2859.820000 1104.220000 ;
      RECT 1.200000 1099.950000 2859.820000 1101.050000 ;
      RECT 0.000000 1026.630000 2859.820000 1099.950000 ;
      RECT 0.000000 1025.530000 2858.620000 1026.630000 ;
      RECT 0.000000 1016.260000 2859.820000 1025.530000 ;
      RECT 1.200000 1015.160000 2859.820000 1016.260000 ;
      RECT 0.000000 947.330000 2859.820000 1015.160000 ;
      RECT 0.000000 946.230000 2858.620000 947.330000 ;
      RECT 0.000000 931.470000 2859.820000 946.230000 ;
      RECT 1.200000 930.370000 2859.820000 931.470000 ;
      RECT 0.000000 868.640000 2859.820000 930.370000 ;
      RECT 0.000000 867.540000 2858.620000 868.640000 ;
      RECT 0.000000 847.290000 2859.820000 867.540000 ;
      RECT 1.200000 846.190000 2859.820000 847.290000 ;
      RECT 0.000000 789.950000 2859.820000 846.190000 ;
      RECT 0.000000 788.850000 2858.620000 789.950000 ;
      RECT 0.000000 762.500000 2859.820000 788.850000 ;
      RECT 1.200000 761.400000 2859.820000 762.500000 ;
      RECT 0.000000 711.260000 2859.820000 761.400000 ;
      RECT 0.000000 710.160000 2858.620000 711.260000 ;
      RECT 0.000000 677.710000 2859.820000 710.160000 ;
      RECT 1.200000 676.610000 2859.820000 677.710000 ;
      RECT 0.000000 631.960000 2859.820000 676.610000 ;
      RECT 0.000000 630.860000 2858.620000 631.960000 ;
      RECT 0.000000 592.920000 2859.820000 630.860000 ;
      RECT 1.200000 591.820000 2859.820000 592.920000 ;
      RECT 0.000000 553.270000 2859.820000 591.820000 ;
      RECT 0.000000 552.170000 2858.620000 553.270000 ;
      RECT 0.000000 508.740000 2859.820000 552.170000 ;
      RECT 1.200000 507.640000 2859.820000 508.740000 ;
      RECT 0.000000 474.580000 2859.820000 507.640000 ;
      RECT 0.000000 473.480000 2858.620000 474.580000 ;
      RECT 0.000000 423.950000 2859.820000 473.480000 ;
      RECT 1.200000 422.850000 2859.820000 423.950000 ;
      RECT 0.000000 395.890000 2859.820000 422.850000 ;
      RECT 0.000000 394.790000 2858.620000 395.890000 ;
      RECT 0.000000 339.160000 2859.820000 394.790000 ;
      RECT 1.200000 338.060000 2859.820000 339.160000 ;
      RECT 0.000000 316.590000 2859.820000 338.060000 ;
      RECT 0.000000 315.490000 2858.620000 316.590000 ;
      RECT 0.000000 254.980000 2859.820000 315.490000 ;
      RECT 1.200000 253.880000 2859.820000 254.980000 ;
      RECT 0.000000 237.900000 2859.820000 253.880000 ;
      RECT 0.000000 236.800000 2858.620000 237.900000 ;
      RECT 0.000000 170.190000 2859.820000 236.800000 ;
      RECT 1.200000 169.090000 2859.820000 170.190000 ;
      RECT 0.000000 159.210000 2859.820000 169.090000 ;
      RECT 0.000000 158.110000 2858.620000 159.210000 ;
      RECT 0.000000 85.400000 2859.820000 158.110000 ;
      RECT 1.200000 84.300000 2859.820000 85.400000 ;
      RECT 0.000000 80.520000 2859.820000 84.300000 ;
      RECT 0.000000 79.420000 2858.620000 80.520000 ;
      RECT 0.000000 1.220000 2859.820000 79.420000 ;
      RECT 1.200000 0.120000 2858.620000 1.220000 ;
      RECT 0.000000 0.000000 2859.820000 0.120000 ;
    LAYER met4 ;
      RECT 28.920000 3449.140000 2830.900000 3470.040000 ;
      RECT 2655.760000 3442.940000 2787.600000 3449.140000 ;
      RECT 2519.760000 3442.940000 2651.600000 3449.140000 ;
      RECT 2383.760000 3442.940000 2515.600000 3449.140000 ;
      RECT 2247.760000 3442.940000 2379.600000 3449.140000 ;
      RECT 2111.760000 3442.940000 2243.600000 3449.140000 ;
      RECT 1975.760000 3442.940000 2107.600000 3449.140000 ;
      RECT 1839.760000 3442.940000 1971.600000 3449.140000 ;
      RECT 1703.760000 3442.940000 1835.600000 3449.140000 ;
      RECT 1567.760000 3442.940000 1699.600000 3449.140000 ;
      RECT 1431.760000 3442.940000 1563.600000 3449.140000 ;
      RECT 1295.760000 3442.940000 1427.600000 3449.140000 ;
      RECT 1159.760000 3442.940000 1291.600000 3449.140000 ;
      RECT 1023.760000 3442.940000 1155.600000 3449.140000 ;
      RECT 887.760000 3442.940000 1019.600000 3449.140000 ;
      RECT 751.760000 3442.940000 883.600000 3449.140000 ;
      RECT 615.760000 3442.940000 747.600000 3449.140000 ;
      RECT 479.760000 3442.940000 611.600000 3449.140000 ;
      RECT 343.760000 3442.940000 475.600000 3449.140000 ;
      RECT 207.760000 3442.940000 339.600000 3449.140000 ;
      RECT 71.760000 3442.940000 203.600000 3449.140000 ;
      RECT 2655.760000 2546.700000 2719.600000 3442.940000 ;
      RECT 2587.760000 2546.700000 2651.600000 3442.940000 ;
      RECT 2587.760000 2545.100000 2719.600000 2546.700000 ;
      RECT 2111.760000 2545.100000 2175.600000 3442.940000 ;
      RECT 1975.760000 2545.100000 2039.600000 3442.940000 ;
      RECT 1499.760000 2545.100000 1563.600000 3442.940000 ;
      RECT 1363.760000 2545.100000 1427.600000 3442.940000 ;
      RECT 887.760000 2545.100000 951.600000 3442.940000 ;
      RECT 751.760000 2545.100000 815.600000 3442.940000 ;
      RECT 275.760000 2545.100000 339.600000 3442.940000 ;
      RECT 2587.760000 2542.500000 2654.780000 2545.100000 ;
      RECT 2519.760000 2542.500000 2583.600000 3442.940000 ;
      RECT 2451.760000 2542.500000 2515.600000 3442.940000 ;
      RECT 2383.760000 2542.500000 2447.600000 3442.940000 ;
      RECT 2315.760000 2542.500000 2379.600000 3442.940000 ;
      RECT 2247.760000 2542.500000 2311.600000 3442.940000 ;
      RECT 2179.760000 2542.500000 2243.600000 3442.940000 ;
      RECT 2165.000000 2542.500000 2175.600000 2545.100000 ;
      RECT 1907.760000 2542.500000 1971.600000 3442.940000 ;
      RECT 1839.760000 2542.500000 1903.600000 3442.940000 ;
      RECT 1771.760000 2542.500000 1835.600000 3442.940000 ;
      RECT 1703.760000 2542.500000 1767.600000 3442.940000 ;
      RECT 1635.760000 2542.500000 1699.600000 3442.940000 ;
      RECT 1567.760000 2542.500000 1631.600000 3442.940000 ;
      RECT 1363.760000 2542.500000 1399.780000 2545.100000 ;
      RECT 1295.760000 2542.500000 1359.600000 3442.940000 ;
      RECT 1227.760000 2542.500000 1291.600000 3442.940000 ;
      RECT 1159.760000 2542.500000 1223.600000 3442.940000 ;
      RECT 1091.760000 2542.500000 1155.600000 3442.940000 ;
      RECT 1023.760000 2542.500000 1087.600000 3442.940000 ;
      RECT 955.760000 2542.500000 1019.600000 3442.940000 ;
      RECT 910.000000 2542.500000 951.600000 2545.100000 ;
      RECT 683.760000 2542.500000 747.600000 3442.940000 ;
      RECT 615.760000 2542.500000 679.600000 3442.940000 ;
      RECT 547.760000 2542.500000 611.600000 3442.940000 ;
      RECT 479.760000 2542.500000 543.600000 3442.940000 ;
      RECT 411.760000 2542.500000 475.600000 3442.940000 ;
      RECT 343.760000 2542.500000 407.600000 3442.940000 ;
      RECT 2519.760000 2541.500000 2654.780000 2542.500000 ;
      RECT 2165.000000 2541.500000 2243.600000 2542.500000 ;
      RECT 1975.760000 2541.500000 2024.780000 2545.100000 ;
      RECT 1535.000000 2541.500000 1563.600000 2545.100000 ;
      RECT 1295.760000 2541.500000 1399.780000 2542.500000 ;
      RECT 910.000000 2541.500000 1019.600000 2542.500000 ;
      RECT 751.760000 2541.500000 774.780000 2545.100000 ;
      RECT 285.000000 2541.500000 339.600000 2545.100000 ;
      RECT 2519.760000 2538.900000 2651.180000 2541.500000 ;
      RECT 2383.760000 2538.900000 2515.600000 2542.500000 ;
      RECT 2247.760000 2538.900000 2379.600000 2542.500000 ;
      RECT 2168.600000 2538.900000 2243.600000 2541.500000 ;
      RECT 1975.760000 2538.900000 2021.180000 2541.500000 ;
      RECT 1839.760000 2538.900000 1971.600000 2542.500000 ;
      RECT 1703.760000 2538.900000 1835.600000 2542.500000 ;
      RECT 1567.760000 2538.900000 1699.600000 2542.500000 ;
      RECT 1538.600000 2538.900000 1563.600000 2541.500000 ;
      RECT 1295.760000 2538.900000 1396.180000 2541.500000 ;
      RECT 1159.760000 2538.900000 1291.600000 2542.500000 ;
      RECT 1023.760000 2538.900000 1155.600000 2542.500000 ;
      RECT 913.600000 2538.900000 1019.600000 2541.500000 ;
      RECT 751.760000 2538.900000 771.180000 2541.500000 ;
      RECT 615.760000 2538.900000 747.600000 2542.500000 ;
      RECT 479.760000 2538.900000 611.600000 2542.500000 ;
      RECT 343.760000 2538.900000 475.600000 2542.500000 ;
      RECT 288.600000 2538.900000 339.600000 2541.500000 ;
      RECT 2168.600000 2505.220000 2651.180000 2538.900000 ;
      RECT 1538.600000 2505.220000 2021.180000 2538.900000 ;
      RECT 913.600000 2505.220000 1396.180000 2538.900000 ;
      RECT 288.600000 2505.220000 771.180000 2538.900000 ;
      RECT 2645.420000 2501.060000 2651.180000 2505.220000 ;
      RECT 2176.900000 2501.060000 2642.880000 2505.220000 ;
      RECT 2168.600000 2501.060000 2174.360000 2505.220000 ;
      RECT 2015.420000 2501.060000 2021.180000 2505.220000 ;
      RECT 1546.900000 2501.060000 2012.880000 2505.220000 ;
      RECT 1538.600000 2501.060000 1544.360000 2505.220000 ;
      RECT 1390.420000 2501.060000 1396.180000 2505.220000 ;
      RECT 921.900000 2501.060000 1387.880000 2505.220000 ;
      RECT 913.600000 2501.060000 919.360000 2505.220000 ;
      RECT 765.420000 2501.060000 771.180000 2505.220000 ;
      RECT 296.900000 2501.060000 762.880000 2505.220000 ;
      RECT 288.600000 2501.060000 294.360000 2505.220000 ;
      RECT 2168.600000 2498.760000 2651.180000 2501.060000 ;
      RECT 1538.600000 2498.760000 2021.180000 2501.060000 ;
      RECT 913.600000 2498.760000 1396.180000 2501.060000 ;
      RECT 288.600000 2498.760000 771.180000 2501.060000 ;
      RECT 2648.820000 2494.600000 2651.180000 2498.760000 ;
      RECT 2173.500000 2494.600000 2646.280000 2498.760000 ;
      RECT 2168.600000 2494.600000 2170.960000 2498.760000 ;
      RECT 2018.820000 2494.600000 2021.180000 2498.760000 ;
      RECT 1543.500000 2494.600000 2016.280000 2498.760000 ;
      RECT 1538.600000 2494.600000 1540.960000 2498.760000 ;
      RECT 1393.820000 2494.600000 1396.180000 2498.760000 ;
      RECT 918.500000 2494.600000 1391.280000 2498.760000 ;
      RECT 913.600000 2494.600000 915.960000 2498.760000 ;
      RECT 768.820000 2494.600000 771.180000 2498.760000 ;
      RECT 293.500000 2494.600000 766.280000 2498.760000 ;
      RECT 288.600000 2494.600000 290.960000 2498.760000 ;
      RECT 2168.600000 2415.220000 2651.180000 2494.600000 ;
      RECT 1538.600000 2415.220000 2021.180000 2494.600000 ;
      RECT 913.600000 2415.220000 1396.180000 2494.600000 ;
      RECT 288.600000 2415.220000 771.180000 2494.600000 ;
      RECT 2645.420000 2411.060000 2651.180000 2415.220000 ;
      RECT 2176.900000 2411.060000 2642.880000 2415.220000 ;
      RECT 2168.600000 2411.060000 2174.360000 2415.220000 ;
      RECT 2015.420000 2411.060000 2021.180000 2415.220000 ;
      RECT 1546.900000 2411.060000 2012.880000 2415.220000 ;
      RECT 1538.600000 2411.060000 1544.360000 2415.220000 ;
      RECT 1390.420000 2411.060000 1396.180000 2415.220000 ;
      RECT 921.900000 2411.060000 1387.880000 2415.220000 ;
      RECT 913.600000 2411.060000 919.360000 2415.220000 ;
      RECT 765.420000 2411.060000 771.180000 2415.220000 ;
      RECT 296.900000 2411.060000 762.880000 2415.220000 ;
      RECT 288.600000 2411.060000 294.360000 2415.220000 ;
      RECT 2168.600000 2408.760000 2651.180000 2411.060000 ;
      RECT 1538.600000 2408.760000 2021.180000 2411.060000 ;
      RECT 913.600000 2408.760000 1396.180000 2411.060000 ;
      RECT 288.600000 2408.760000 771.180000 2411.060000 ;
      RECT 2648.820000 2404.600000 2651.180000 2408.760000 ;
      RECT 2173.500000 2404.600000 2646.280000 2408.760000 ;
      RECT 2168.600000 2404.600000 2170.960000 2408.760000 ;
      RECT 2018.820000 2404.600000 2021.180000 2408.760000 ;
      RECT 1543.500000 2404.600000 2016.280000 2408.760000 ;
      RECT 1538.600000 2404.600000 1540.960000 2408.760000 ;
      RECT 1393.820000 2404.600000 1396.180000 2408.760000 ;
      RECT 918.500000 2404.600000 1391.280000 2408.760000 ;
      RECT 913.600000 2404.600000 915.960000 2408.760000 ;
      RECT 768.820000 2404.600000 771.180000 2408.760000 ;
      RECT 293.500000 2404.600000 766.280000 2408.760000 ;
      RECT 288.600000 2404.600000 290.960000 2408.760000 ;
      RECT 2168.600000 2325.220000 2651.180000 2404.600000 ;
      RECT 1538.600000 2325.220000 2021.180000 2404.600000 ;
      RECT 913.600000 2325.220000 1396.180000 2404.600000 ;
      RECT 288.600000 2325.220000 771.180000 2404.600000 ;
      RECT 2645.420000 2321.060000 2651.180000 2325.220000 ;
      RECT 2176.900000 2321.060000 2642.880000 2325.220000 ;
      RECT 2168.600000 2321.060000 2174.360000 2325.220000 ;
      RECT 2015.420000 2321.060000 2021.180000 2325.220000 ;
      RECT 1546.900000 2321.060000 2012.880000 2325.220000 ;
      RECT 1538.600000 2321.060000 1544.360000 2325.220000 ;
      RECT 1390.420000 2321.060000 1396.180000 2325.220000 ;
      RECT 921.900000 2321.060000 1387.880000 2325.220000 ;
      RECT 913.600000 2321.060000 919.360000 2325.220000 ;
      RECT 765.420000 2321.060000 771.180000 2325.220000 ;
      RECT 296.900000 2321.060000 762.880000 2325.220000 ;
      RECT 288.600000 2321.060000 294.360000 2325.220000 ;
      RECT 2168.600000 2318.760000 2651.180000 2321.060000 ;
      RECT 1538.600000 2318.760000 2021.180000 2321.060000 ;
      RECT 913.600000 2318.760000 1396.180000 2321.060000 ;
      RECT 288.600000 2318.760000 771.180000 2321.060000 ;
      RECT 2648.820000 2314.600000 2651.180000 2318.760000 ;
      RECT 2173.500000 2314.600000 2646.280000 2318.760000 ;
      RECT 2168.600000 2314.600000 2170.960000 2318.760000 ;
      RECT 2018.820000 2314.600000 2021.180000 2318.760000 ;
      RECT 1543.500000 2314.600000 2016.280000 2318.760000 ;
      RECT 1538.600000 2314.600000 1540.960000 2318.760000 ;
      RECT 1393.820000 2314.600000 1396.180000 2318.760000 ;
      RECT 918.500000 2314.600000 1391.280000 2318.760000 ;
      RECT 913.600000 2314.600000 915.960000 2318.760000 ;
      RECT 768.820000 2314.600000 771.180000 2318.760000 ;
      RECT 293.500000 2314.600000 766.280000 2318.760000 ;
      RECT 288.600000 2314.600000 290.960000 2318.760000 ;
      RECT 2168.600000 2235.220000 2651.180000 2314.600000 ;
      RECT 1538.600000 2235.220000 2021.180000 2314.600000 ;
      RECT 913.600000 2235.220000 1396.180000 2314.600000 ;
      RECT 288.600000 2235.220000 771.180000 2314.600000 ;
      RECT 2645.420000 2231.060000 2651.180000 2235.220000 ;
      RECT 2176.900000 2231.060000 2642.880000 2235.220000 ;
      RECT 2168.600000 2231.060000 2174.360000 2235.220000 ;
      RECT 2015.420000 2231.060000 2021.180000 2235.220000 ;
      RECT 1546.900000 2231.060000 2012.880000 2235.220000 ;
      RECT 1538.600000 2231.060000 1544.360000 2235.220000 ;
      RECT 1390.420000 2231.060000 1396.180000 2235.220000 ;
      RECT 921.900000 2231.060000 1387.880000 2235.220000 ;
      RECT 913.600000 2231.060000 919.360000 2235.220000 ;
      RECT 765.420000 2231.060000 771.180000 2235.220000 ;
      RECT 296.900000 2231.060000 762.880000 2235.220000 ;
      RECT 288.600000 2231.060000 294.360000 2235.220000 ;
      RECT 2168.600000 2228.760000 2651.180000 2231.060000 ;
      RECT 1538.600000 2228.760000 2021.180000 2231.060000 ;
      RECT 913.600000 2228.760000 1396.180000 2231.060000 ;
      RECT 288.600000 2228.760000 771.180000 2231.060000 ;
      RECT 2648.820000 2224.600000 2651.180000 2228.760000 ;
      RECT 2173.500000 2224.600000 2646.280000 2228.760000 ;
      RECT 2168.600000 2224.600000 2170.960000 2228.760000 ;
      RECT 2018.820000 2224.600000 2021.180000 2228.760000 ;
      RECT 1543.500000 2224.600000 2016.280000 2228.760000 ;
      RECT 1538.600000 2224.600000 1540.960000 2228.760000 ;
      RECT 1393.820000 2224.600000 1396.180000 2228.760000 ;
      RECT 918.500000 2224.600000 1391.280000 2228.760000 ;
      RECT 913.600000 2224.600000 915.960000 2228.760000 ;
      RECT 768.820000 2224.600000 771.180000 2228.760000 ;
      RECT 293.500000 2224.600000 766.280000 2228.760000 ;
      RECT 288.600000 2224.600000 290.960000 2228.760000 ;
      RECT 2168.600000 2146.580000 2651.180000 2224.600000 ;
      RECT 1538.600000 2146.580000 2021.180000 2224.600000 ;
      RECT 913.600000 2146.580000 1396.180000 2224.600000 ;
      RECT 288.600000 2146.580000 771.180000 2224.600000 ;
      RECT 2645.420000 2144.360000 2651.180000 2146.580000 ;
      RECT 2176.900000 2144.360000 2642.880000 2146.580000 ;
      RECT 2168.600000 2144.360000 2174.360000 2146.580000 ;
      RECT 2015.420000 2144.360000 2021.180000 2146.580000 ;
      RECT 1546.900000 2144.360000 2012.880000 2146.580000 ;
      RECT 1538.600000 2144.360000 1544.360000 2146.580000 ;
      RECT 1390.420000 2144.360000 1396.180000 2146.580000 ;
      RECT 921.900000 2144.360000 1387.880000 2146.580000 ;
      RECT 913.600000 2144.360000 919.360000 2146.580000 ;
      RECT 765.420000 2144.360000 771.180000 2146.580000 ;
      RECT 296.900000 2144.360000 762.880000 2146.580000 ;
      RECT 288.600000 2144.360000 294.360000 2146.580000 ;
      RECT 2168.600000 2138.600000 2651.180000 2144.360000 ;
      RECT 1538.600000 2138.600000 2021.180000 2144.360000 ;
      RECT 913.600000 2138.600000 1396.180000 2144.360000 ;
      RECT 288.600000 2138.600000 771.180000 2144.360000 ;
      RECT 2653.780000 2136.000000 2654.780000 2541.500000 ;
      RECT 2519.760000 2136.000000 2651.180000 2138.600000 ;
      RECT 2168.600000 2136.000000 2243.600000 2138.600000 ;
      RECT 2165.000000 2136.000000 2166.000000 2541.500000 ;
      RECT 2023.780000 2136.000000 2024.780000 2541.500000 ;
      RECT 1975.760000 2136.000000 2021.180000 2138.600000 ;
      RECT 1538.600000 2136.000000 1563.600000 2138.600000 ;
      RECT 1535.000000 2136.000000 1536.000000 2541.500000 ;
      RECT 1398.780000 2136.000000 1399.780000 2541.500000 ;
      RECT 1295.760000 2136.000000 1396.180000 2138.600000 ;
      RECT 913.600000 2136.000000 1019.600000 2138.600000 ;
      RECT 910.000000 2136.000000 911.000000 2541.500000 ;
      RECT 773.780000 2136.000000 774.780000 2541.500000 ;
      RECT 751.760000 2136.000000 771.180000 2138.600000 ;
      RECT 288.600000 2136.000000 339.600000 2138.600000 ;
      RECT 285.000000 2136.000000 286.000000 2541.500000 ;
      RECT 2519.760000 2135.000000 2654.780000 2136.000000 ;
      RECT 2383.760000 2135.000000 2515.600000 2138.600000 ;
      RECT 2247.760000 2135.000000 2379.600000 2138.600000 ;
      RECT 2165.000000 2135.000000 2243.600000 2136.000000 ;
      RECT 1839.760000 2135.000000 1971.600000 2138.600000 ;
      RECT 1703.760000 2135.000000 1835.600000 2138.600000 ;
      RECT 1567.760000 2135.000000 1699.600000 2138.600000 ;
      RECT 1295.760000 2135.000000 1399.780000 2136.000000 ;
      RECT 1159.760000 2135.000000 1291.600000 2138.600000 ;
      RECT 1023.760000 2135.000000 1155.600000 2138.600000 ;
      RECT 910.000000 2135.000000 1019.600000 2136.000000 ;
      RECT 615.760000 2135.000000 747.600000 2138.600000 ;
      RECT 479.760000 2135.000000 611.600000 2138.600000 ;
      RECT 343.760000 2135.000000 475.600000 2138.600000 ;
      RECT 2657.380000 2132.400000 2719.600000 2545.100000 ;
      RECT 2587.760000 2132.400000 2654.780000 2135.000000 ;
      RECT 2165.000000 2132.400000 2175.600000 2135.000000 ;
      RECT 2111.760000 2132.400000 2162.400000 2545.100000 ;
      RECT 2027.380000 2132.400000 2039.600000 2545.100000 ;
      RECT 1975.760000 2132.400000 2024.780000 2136.000000 ;
      RECT 1535.000000 2132.400000 1563.600000 2136.000000 ;
      RECT 1499.760000 2132.400000 1532.400000 2545.100000 ;
      RECT 1402.380000 2132.400000 1427.600000 2545.100000 ;
      RECT 1363.760000 2132.400000 1399.780000 2135.000000 ;
      RECT 910.000000 2132.400000 951.600000 2135.000000 ;
      RECT 887.760000 2132.400000 907.400000 2545.100000 ;
      RECT 777.380000 2132.400000 815.600000 2545.100000 ;
      RECT 751.760000 2132.400000 774.780000 2136.000000 ;
      RECT 285.000000 2132.400000 339.600000 2136.000000 ;
      RECT 275.760000 2132.400000 282.400000 2545.100000 ;
      RECT 2587.760000 2129.040000 2719.600000 2132.400000 ;
      RECT 2655.760000 990.800000 2719.600000 2129.040000 ;
      RECT 2587.760000 990.800000 2651.600000 2129.040000 ;
      RECT 2587.760000 985.100000 2719.600000 990.800000 ;
      RECT 2111.760000 985.100000 2175.600000 2132.400000 ;
      RECT 1975.760000 985.100000 2039.600000 2132.400000 ;
      RECT 1499.760000 985.100000 1563.600000 2132.400000 ;
      RECT 1363.760000 985.100000 1427.600000 2132.400000 ;
      RECT 887.760000 985.100000 951.600000 2132.400000 ;
      RECT 751.760000 985.100000 815.600000 2132.400000 ;
      RECT 275.760000 985.100000 339.600000 2132.400000 ;
      RECT 2587.760000 982.500000 2654.780000 985.100000 ;
      RECT 2519.760000 982.500000 2583.600000 2135.000000 ;
      RECT 2451.760000 982.500000 2515.600000 2135.000000 ;
      RECT 2383.760000 982.500000 2447.600000 2135.000000 ;
      RECT 2315.760000 982.500000 2379.600000 2135.000000 ;
      RECT 2247.760000 982.500000 2311.600000 2135.000000 ;
      RECT 2179.760000 982.500000 2243.600000 2135.000000 ;
      RECT 2165.000000 982.500000 2175.600000 985.100000 ;
      RECT 1907.760000 982.500000 1971.600000 2135.000000 ;
      RECT 1839.760000 982.500000 1903.600000 2135.000000 ;
      RECT 1771.760000 982.500000 1835.600000 2135.000000 ;
      RECT 1703.760000 982.500000 1767.600000 2135.000000 ;
      RECT 1635.760000 982.500000 1699.600000 2135.000000 ;
      RECT 1567.760000 982.500000 1631.600000 2135.000000 ;
      RECT 1363.760000 982.500000 1399.780000 985.100000 ;
      RECT 1295.760000 982.500000 1359.600000 2135.000000 ;
      RECT 1227.760000 982.500000 1291.600000 2135.000000 ;
      RECT 1159.760000 982.500000 1223.600000 2135.000000 ;
      RECT 1091.760000 982.500000 1155.600000 2135.000000 ;
      RECT 1023.760000 982.500000 1087.600000 2135.000000 ;
      RECT 955.760000 982.500000 1019.600000 2135.000000 ;
      RECT 910.000000 982.500000 951.600000 985.100000 ;
      RECT 683.760000 982.500000 747.600000 2135.000000 ;
      RECT 615.760000 982.500000 679.600000 2135.000000 ;
      RECT 547.760000 982.500000 611.600000 2135.000000 ;
      RECT 479.760000 982.500000 543.600000 2135.000000 ;
      RECT 411.760000 982.500000 475.600000 2135.000000 ;
      RECT 343.760000 982.500000 407.600000 2135.000000 ;
      RECT 2519.760000 981.500000 2654.780000 982.500000 ;
      RECT 2165.000000 981.500000 2243.600000 982.500000 ;
      RECT 1975.760000 981.500000 2024.780000 985.100000 ;
      RECT 1535.000000 981.500000 1563.600000 985.100000 ;
      RECT 1295.760000 981.500000 1399.780000 982.500000 ;
      RECT 910.000000 981.500000 1019.600000 982.500000 ;
      RECT 751.760000 981.500000 774.780000 985.100000 ;
      RECT 285.000000 981.500000 339.600000 985.100000 ;
      RECT 2519.760000 978.900000 2651.180000 981.500000 ;
      RECT 2383.760000 978.900000 2515.600000 982.500000 ;
      RECT 2247.760000 978.900000 2379.600000 982.500000 ;
      RECT 2168.600000 978.900000 2243.600000 981.500000 ;
      RECT 1975.760000 978.900000 2021.180000 981.500000 ;
      RECT 1839.760000 978.900000 1971.600000 982.500000 ;
      RECT 1703.760000 978.900000 1835.600000 982.500000 ;
      RECT 1567.760000 978.900000 1699.600000 982.500000 ;
      RECT 1538.600000 978.900000 1563.600000 981.500000 ;
      RECT 1295.760000 978.900000 1396.180000 981.500000 ;
      RECT 1159.760000 978.900000 1291.600000 982.500000 ;
      RECT 1023.760000 978.900000 1155.600000 982.500000 ;
      RECT 913.600000 978.900000 1019.600000 981.500000 ;
      RECT 751.760000 978.900000 771.180000 981.500000 ;
      RECT 615.760000 978.900000 747.600000 982.500000 ;
      RECT 479.760000 978.900000 611.600000 982.500000 ;
      RECT 343.760000 978.900000 475.600000 982.500000 ;
      RECT 288.600000 978.900000 339.600000 981.500000 ;
      RECT 2168.600000 973.210000 2651.180000 978.900000 ;
      RECT 1538.600000 973.210000 2021.180000 978.900000 ;
      RECT 913.600000 973.210000 1396.180000 978.900000 ;
      RECT 288.600000 973.210000 771.180000 978.900000 ;
      RECT 2645.420000 970.990000 2651.180000 973.210000 ;
      RECT 2176.900000 970.990000 2642.880000 973.210000 ;
      RECT 2168.600000 970.990000 2174.360000 973.210000 ;
      RECT 2015.420000 970.990000 2021.180000 973.210000 ;
      RECT 1546.900000 970.990000 2012.880000 973.210000 ;
      RECT 1538.600000 970.990000 1544.360000 973.210000 ;
      RECT 1390.420000 970.990000 1396.180000 973.210000 ;
      RECT 921.900000 970.990000 1387.880000 973.210000 ;
      RECT 913.600000 970.990000 919.360000 973.210000 ;
      RECT 765.420000 970.990000 771.180000 973.210000 ;
      RECT 296.900000 970.990000 762.880000 973.210000 ;
      RECT 288.600000 970.990000 294.360000 973.210000 ;
      RECT 2168.600000 968.760000 2651.180000 970.990000 ;
      RECT 1538.600000 968.760000 2021.180000 970.990000 ;
      RECT 913.600000 968.760000 1396.180000 970.990000 ;
      RECT 288.600000 968.760000 771.180000 970.990000 ;
      RECT 2648.820000 964.600000 2651.180000 968.760000 ;
      RECT 2173.500000 964.600000 2646.280000 968.760000 ;
      RECT 2168.600000 964.600000 2170.960000 968.760000 ;
      RECT 2018.820000 964.600000 2021.180000 968.760000 ;
      RECT 1543.500000 964.600000 2016.280000 968.760000 ;
      RECT 1538.600000 964.600000 1540.960000 968.760000 ;
      RECT 1393.820000 964.600000 1396.180000 968.760000 ;
      RECT 918.500000 964.600000 1391.280000 968.760000 ;
      RECT 913.600000 964.600000 915.960000 968.760000 ;
      RECT 768.820000 964.600000 771.180000 968.760000 ;
      RECT 293.500000 964.600000 766.280000 968.760000 ;
      RECT 288.600000 964.600000 290.960000 968.760000 ;
      RECT 2168.600000 885.220000 2651.180000 964.600000 ;
      RECT 1538.600000 885.220000 2021.180000 964.600000 ;
      RECT 913.600000 885.220000 1396.180000 964.600000 ;
      RECT 288.600000 885.220000 771.180000 964.600000 ;
      RECT 2645.420000 881.060000 2651.180000 885.220000 ;
      RECT 2176.900000 881.060000 2642.880000 885.220000 ;
      RECT 2168.600000 881.060000 2174.360000 885.220000 ;
      RECT 2015.420000 881.060000 2021.180000 885.220000 ;
      RECT 1546.900000 881.060000 2012.880000 885.220000 ;
      RECT 1538.600000 881.060000 1544.360000 885.220000 ;
      RECT 1390.420000 881.060000 1396.180000 885.220000 ;
      RECT 921.900000 881.060000 1387.880000 885.220000 ;
      RECT 913.600000 881.060000 919.360000 885.220000 ;
      RECT 765.420000 881.060000 771.180000 885.220000 ;
      RECT 296.900000 881.060000 762.880000 885.220000 ;
      RECT 288.600000 881.060000 294.360000 885.220000 ;
      RECT 2168.600000 878.760000 2651.180000 881.060000 ;
      RECT 1538.600000 878.760000 2021.180000 881.060000 ;
      RECT 913.600000 878.760000 1396.180000 881.060000 ;
      RECT 288.600000 878.760000 771.180000 881.060000 ;
      RECT 2648.820000 874.600000 2651.180000 878.760000 ;
      RECT 2173.500000 874.600000 2646.280000 878.760000 ;
      RECT 2168.600000 874.600000 2170.960000 878.760000 ;
      RECT 2018.820000 874.600000 2021.180000 878.760000 ;
      RECT 1543.500000 874.600000 2016.280000 878.760000 ;
      RECT 1538.600000 874.600000 1540.960000 878.760000 ;
      RECT 1393.820000 874.600000 1396.180000 878.760000 ;
      RECT 918.500000 874.600000 1391.280000 878.760000 ;
      RECT 913.600000 874.600000 915.960000 878.760000 ;
      RECT 768.820000 874.600000 771.180000 878.760000 ;
      RECT 293.500000 874.600000 766.280000 878.760000 ;
      RECT 288.600000 874.600000 290.960000 878.760000 ;
      RECT 2168.600000 795.220000 2651.180000 874.600000 ;
      RECT 1538.600000 795.220000 2021.180000 874.600000 ;
      RECT 913.600000 795.220000 1396.180000 874.600000 ;
      RECT 288.600000 795.220000 771.180000 874.600000 ;
      RECT 2645.420000 791.060000 2651.180000 795.220000 ;
      RECT 2176.900000 791.060000 2642.880000 795.220000 ;
      RECT 2168.600000 791.060000 2174.360000 795.220000 ;
      RECT 2015.420000 791.060000 2021.180000 795.220000 ;
      RECT 1546.900000 791.060000 2012.880000 795.220000 ;
      RECT 1538.600000 791.060000 1544.360000 795.220000 ;
      RECT 1390.420000 791.060000 1396.180000 795.220000 ;
      RECT 921.900000 791.060000 1387.880000 795.220000 ;
      RECT 913.600000 791.060000 919.360000 795.220000 ;
      RECT 765.420000 791.060000 771.180000 795.220000 ;
      RECT 296.900000 791.060000 762.880000 795.220000 ;
      RECT 288.600000 791.060000 294.360000 795.220000 ;
      RECT 2168.600000 788.760000 2651.180000 791.060000 ;
      RECT 1538.600000 788.760000 2021.180000 791.060000 ;
      RECT 913.600000 788.760000 1396.180000 791.060000 ;
      RECT 288.600000 788.760000 771.180000 791.060000 ;
      RECT 2648.820000 784.600000 2651.180000 788.760000 ;
      RECT 2173.500000 784.600000 2646.280000 788.760000 ;
      RECT 2168.600000 784.600000 2170.960000 788.760000 ;
      RECT 2018.820000 784.600000 2021.180000 788.760000 ;
      RECT 1543.500000 784.600000 2016.280000 788.760000 ;
      RECT 1538.600000 784.600000 1540.960000 788.760000 ;
      RECT 1393.820000 784.600000 1396.180000 788.760000 ;
      RECT 918.500000 784.600000 1391.280000 788.760000 ;
      RECT 913.600000 784.600000 915.960000 788.760000 ;
      RECT 768.820000 784.600000 771.180000 788.760000 ;
      RECT 293.500000 784.600000 766.280000 788.760000 ;
      RECT 288.600000 784.600000 290.960000 788.760000 ;
      RECT 2168.600000 705.220000 2651.180000 784.600000 ;
      RECT 1538.600000 705.220000 2021.180000 784.600000 ;
      RECT 913.600000 705.220000 1396.180000 784.600000 ;
      RECT 288.600000 705.220000 771.180000 784.600000 ;
      RECT 2645.420000 701.060000 2651.180000 705.220000 ;
      RECT 2176.900000 701.060000 2642.880000 705.220000 ;
      RECT 2168.600000 701.060000 2174.360000 705.220000 ;
      RECT 2015.420000 701.060000 2021.180000 705.220000 ;
      RECT 1546.900000 701.060000 2012.880000 705.220000 ;
      RECT 1538.600000 701.060000 1544.360000 705.220000 ;
      RECT 1390.420000 701.060000 1396.180000 705.220000 ;
      RECT 921.900000 701.060000 1387.880000 705.220000 ;
      RECT 913.600000 701.060000 919.360000 705.220000 ;
      RECT 765.420000 701.060000 771.180000 705.220000 ;
      RECT 296.900000 701.060000 762.880000 705.220000 ;
      RECT 288.600000 701.060000 294.360000 705.220000 ;
      RECT 2168.600000 698.760000 2651.180000 701.060000 ;
      RECT 1538.600000 698.760000 2021.180000 701.060000 ;
      RECT 913.600000 698.760000 1396.180000 701.060000 ;
      RECT 288.600000 698.760000 771.180000 701.060000 ;
      RECT 2648.820000 694.600000 2651.180000 698.760000 ;
      RECT 2173.500000 694.600000 2646.280000 698.760000 ;
      RECT 2168.600000 694.600000 2170.960000 698.760000 ;
      RECT 2018.820000 694.600000 2021.180000 698.760000 ;
      RECT 1543.500000 694.600000 2016.280000 698.760000 ;
      RECT 1538.600000 694.600000 1540.960000 698.760000 ;
      RECT 1393.820000 694.600000 1396.180000 698.760000 ;
      RECT 918.500000 694.600000 1391.280000 698.760000 ;
      RECT 913.600000 694.600000 915.960000 698.760000 ;
      RECT 768.820000 694.600000 771.180000 698.760000 ;
      RECT 293.500000 694.600000 766.280000 698.760000 ;
      RECT 288.600000 694.600000 290.960000 698.760000 ;
      RECT 2168.600000 615.220000 2651.180000 694.600000 ;
      RECT 1538.600000 615.220000 2021.180000 694.600000 ;
      RECT 913.600000 615.220000 1396.180000 694.600000 ;
      RECT 288.600000 615.220000 771.180000 694.600000 ;
      RECT 2645.420000 611.060000 2651.180000 615.220000 ;
      RECT 2176.900000 611.060000 2642.880000 615.220000 ;
      RECT 2168.600000 611.060000 2174.360000 615.220000 ;
      RECT 2015.420000 611.060000 2021.180000 615.220000 ;
      RECT 1546.900000 611.060000 2012.880000 615.220000 ;
      RECT 1538.600000 611.060000 1544.360000 615.220000 ;
      RECT 1390.420000 611.060000 1396.180000 615.220000 ;
      RECT 921.900000 611.060000 1387.880000 615.220000 ;
      RECT 913.600000 611.060000 919.360000 615.220000 ;
      RECT 765.420000 611.060000 771.180000 615.220000 ;
      RECT 296.900000 611.060000 762.880000 615.220000 ;
      RECT 288.600000 611.060000 294.360000 615.220000 ;
      RECT 2168.600000 608.760000 2651.180000 611.060000 ;
      RECT 1538.600000 608.760000 2021.180000 611.060000 ;
      RECT 913.600000 608.760000 1396.180000 611.060000 ;
      RECT 288.600000 608.760000 771.180000 611.060000 ;
      RECT 2648.820000 604.600000 2651.180000 608.760000 ;
      RECT 2173.500000 604.600000 2646.280000 608.760000 ;
      RECT 2168.600000 604.600000 2170.960000 608.760000 ;
      RECT 2018.820000 604.600000 2021.180000 608.760000 ;
      RECT 1543.500000 604.600000 2016.280000 608.760000 ;
      RECT 1538.600000 604.600000 1540.960000 608.760000 ;
      RECT 1393.820000 604.600000 1396.180000 608.760000 ;
      RECT 918.500000 604.600000 1391.280000 608.760000 ;
      RECT 913.600000 604.600000 915.960000 608.760000 ;
      RECT 768.820000 604.600000 771.180000 608.760000 ;
      RECT 293.500000 604.600000 766.280000 608.760000 ;
      RECT 288.600000 604.600000 290.960000 608.760000 ;
      RECT 2168.600000 578.600000 2651.180000 604.600000 ;
      RECT 1538.600000 578.600000 2021.180000 604.600000 ;
      RECT 913.600000 578.600000 1396.180000 604.600000 ;
      RECT 288.600000 578.600000 771.180000 604.600000 ;
      RECT 2653.780000 576.000000 2654.780000 981.500000 ;
      RECT 2519.760000 576.000000 2651.180000 578.600000 ;
      RECT 2168.600000 576.000000 2243.600000 578.600000 ;
      RECT 2165.000000 576.000000 2166.000000 981.500000 ;
      RECT 2023.780000 576.000000 2024.780000 981.500000 ;
      RECT 1975.760000 576.000000 2021.180000 578.600000 ;
      RECT 1538.600000 576.000000 1563.600000 578.600000 ;
      RECT 1535.000000 576.000000 1536.000000 981.500000 ;
      RECT 1398.780000 576.000000 1399.780000 981.500000 ;
      RECT 1295.760000 576.000000 1396.180000 578.600000 ;
      RECT 913.600000 576.000000 1019.600000 578.600000 ;
      RECT 910.000000 576.000000 911.000000 981.500000 ;
      RECT 773.780000 576.000000 774.780000 981.500000 ;
      RECT 751.760000 576.000000 771.180000 578.600000 ;
      RECT 288.600000 576.000000 339.600000 578.600000 ;
      RECT 285.000000 576.000000 286.000000 981.500000 ;
      RECT 2519.760000 575.000000 2654.780000 576.000000 ;
      RECT 2383.760000 575.000000 2515.600000 578.600000 ;
      RECT 2247.760000 575.000000 2379.600000 578.600000 ;
      RECT 2165.000000 575.000000 2243.600000 576.000000 ;
      RECT 1839.760000 575.000000 1971.600000 578.600000 ;
      RECT 1703.760000 575.000000 1835.600000 578.600000 ;
      RECT 1567.760000 575.000000 1699.600000 578.600000 ;
      RECT 1295.760000 575.000000 1399.780000 576.000000 ;
      RECT 1159.760000 575.000000 1291.600000 578.600000 ;
      RECT 1023.760000 575.000000 1155.600000 578.600000 ;
      RECT 910.000000 575.000000 1019.600000 576.000000 ;
      RECT 615.760000 575.000000 747.600000 578.600000 ;
      RECT 479.760000 575.000000 611.600000 578.600000 ;
      RECT 343.760000 575.000000 475.600000 578.600000 ;
      RECT 2657.380000 572.400000 2719.600000 985.100000 ;
      RECT 2587.760000 572.400000 2654.780000 575.000000 ;
      RECT 2165.000000 572.400000 2175.600000 575.000000 ;
      RECT 2111.760000 572.400000 2162.400000 985.100000 ;
      RECT 2027.380000 572.400000 2039.600000 985.100000 ;
      RECT 1975.760000 572.400000 2024.780000 576.000000 ;
      RECT 1535.000000 572.400000 1563.600000 576.000000 ;
      RECT 1499.760000 572.400000 1532.400000 985.100000 ;
      RECT 1402.380000 572.400000 1427.600000 985.100000 ;
      RECT 1363.760000 572.400000 1399.780000 575.000000 ;
      RECT 910.000000 572.400000 951.600000 575.000000 ;
      RECT 887.760000 572.400000 907.400000 985.100000 ;
      RECT 777.380000 572.400000 815.600000 985.100000 ;
      RECT 751.760000 572.400000 774.780000 576.000000 ;
      RECT 285.000000 572.400000 339.600000 576.000000 ;
      RECT 275.760000 572.400000 282.400000 985.100000 ;
      RECT 2587.760000 567.760000 2719.600000 572.400000 ;
      RECT 2655.760000 490.320000 2719.600000 567.760000 ;
      RECT 2587.760000 490.320000 2651.600000 567.760000 ;
      RECT 2587.760000 485.100000 2719.600000 490.320000 ;
      RECT 2111.760000 485.100000 2175.600000 572.400000 ;
      RECT 1975.760000 485.100000 2039.600000 572.400000 ;
      RECT 1499.760000 485.100000 1563.600000 572.400000 ;
      RECT 1363.760000 485.100000 1427.600000 572.400000 ;
      RECT 887.760000 485.100000 951.600000 572.400000 ;
      RECT 751.760000 485.100000 815.600000 572.400000 ;
      RECT 275.760000 485.100000 339.600000 572.400000 ;
      RECT 2587.760000 482.500000 2654.780000 485.100000 ;
      RECT 2519.760000 482.500000 2583.600000 575.000000 ;
      RECT 2451.760000 482.500000 2515.600000 575.000000 ;
      RECT 2383.760000 482.500000 2447.600000 575.000000 ;
      RECT 2315.760000 482.500000 2379.600000 575.000000 ;
      RECT 2247.760000 482.500000 2311.600000 575.000000 ;
      RECT 2179.760000 482.500000 2243.600000 575.000000 ;
      RECT 2165.000000 482.500000 2175.600000 485.100000 ;
      RECT 1907.760000 482.500000 1971.600000 575.000000 ;
      RECT 1839.760000 482.500000 1903.600000 575.000000 ;
      RECT 1771.760000 482.500000 1835.600000 575.000000 ;
      RECT 1703.760000 482.500000 1767.600000 575.000000 ;
      RECT 1635.760000 482.500000 1699.600000 575.000000 ;
      RECT 1567.760000 482.500000 1631.600000 575.000000 ;
      RECT 1363.760000 482.500000 1399.780000 485.100000 ;
      RECT 1295.760000 482.500000 1359.600000 575.000000 ;
      RECT 1227.760000 482.500000 1291.600000 575.000000 ;
      RECT 1159.760000 482.500000 1223.600000 575.000000 ;
      RECT 1091.760000 482.500000 1155.600000 575.000000 ;
      RECT 1023.760000 482.500000 1087.600000 575.000000 ;
      RECT 955.760000 482.500000 1019.600000 575.000000 ;
      RECT 910.000000 482.500000 951.600000 485.100000 ;
      RECT 683.760000 482.500000 747.600000 575.000000 ;
      RECT 615.760000 482.500000 679.600000 575.000000 ;
      RECT 547.760000 482.500000 611.600000 575.000000 ;
      RECT 479.760000 482.500000 543.600000 575.000000 ;
      RECT 411.760000 482.500000 475.600000 575.000000 ;
      RECT 343.760000 482.500000 407.600000 575.000000 ;
      RECT 2519.760000 481.500000 2654.780000 482.500000 ;
      RECT 2165.000000 481.500000 2243.600000 482.500000 ;
      RECT 1975.760000 481.500000 2024.780000 485.100000 ;
      RECT 1535.000000 481.500000 1563.600000 485.100000 ;
      RECT 1295.760000 481.500000 1399.780000 482.500000 ;
      RECT 910.000000 481.500000 1019.600000 482.500000 ;
      RECT 751.760000 481.500000 774.780000 485.100000 ;
      RECT 285.000000 481.500000 339.600000 485.100000 ;
      RECT 2519.760000 478.900000 2651.180000 481.500000 ;
      RECT 2383.760000 478.900000 2515.600000 482.500000 ;
      RECT 2247.760000 478.900000 2379.600000 482.500000 ;
      RECT 2168.600000 478.900000 2243.600000 481.500000 ;
      RECT 1975.760000 478.900000 2021.180000 481.500000 ;
      RECT 1839.760000 478.900000 1971.600000 482.500000 ;
      RECT 1703.760000 478.900000 1835.600000 482.500000 ;
      RECT 1567.760000 478.900000 1699.600000 482.500000 ;
      RECT 1538.600000 478.900000 1563.600000 481.500000 ;
      RECT 1295.760000 478.900000 1396.180000 481.500000 ;
      RECT 1159.760000 478.900000 1291.600000 482.500000 ;
      RECT 1023.760000 478.900000 1155.600000 482.500000 ;
      RECT 913.600000 478.900000 1019.600000 481.500000 ;
      RECT 751.760000 478.900000 771.180000 481.500000 ;
      RECT 615.760000 478.900000 747.600000 482.500000 ;
      RECT 479.760000 478.900000 611.600000 482.500000 ;
      RECT 343.760000 478.900000 475.600000 482.500000 ;
      RECT 288.600000 478.900000 339.600000 481.500000 ;
      RECT 2168.600000 435.220000 2651.180000 478.900000 ;
      RECT 1538.600000 435.220000 2021.180000 478.900000 ;
      RECT 913.600000 435.220000 1396.180000 478.900000 ;
      RECT 288.600000 435.220000 771.180000 478.900000 ;
      RECT 2645.420000 431.060000 2651.180000 435.220000 ;
      RECT 2176.900000 431.060000 2642.880000 435.220000 ;
      RECT 2168.600000 431.060000 2174.360000 435.220000 ;
      RECT 2015.420000 431.060000 2021.180000 435.220000 ;
      RECT 1546.900000 431.060000 2012.880000 435.220000 ;
      RECT 1538.600000 431.060000 1544.360000 435.220000 ;
      RECT 1390.420000 431.060000 1396.180000 435.220000 ;
      RECT 921.900000 431.060000 1387.880000 435.220000 ;
      RECT 913.600000 431.060000 919.360000 435.220000 ;
      RECT 765.420000 431.060000 771.180000 435.220000 ;
      RECT 296.900000 431.060000 762.880000 435.220000 ;
      RECT 288.600000 431.060000 294.360000 435.220000 ;
      RECT 2168.600000 428.760000 2651.180000 431.060000 ;
      RECT 1538.600000 428.760000 2021.180000 431.060000 ;
      RECT 913.600000 428.760000 1396.180000 431.060000 ;
      RECT 288.600000 428.760000 771.180000 431.060000 ;
      RECT 2648.820000 424.600000 2651.180000 428.760000 ;
      RECT 2173.500000 424.600000 2646.280000 428.760000 ;
      RECT 2168.600000 424.600000 2170.960000 428.760000 ;
      RECT 2018.820000 424.600000 2021.180000 428.760000 ;
      RECT 1543.500000 424.600000 2016.280000 428.760000 ;
      RECT 1538.600000 424.600000 1540.960000 428.760000 ;
      RECT 1393.820000 424.600000 1396.180000 428.760000 ;
      RECT 918.500000 424.600000 1391.280000 428.760000 ;
      RECT 913.600000 424.600000 915.960000 428.760000 ;
      RECT 768.820000 424.600000 771.180000 428.760000 ;
      RECT 293.500000 424.600000 766.280000 428.760000 ;
      RECT 288.600000 424.600000 290.960000 428.760000 ;
      RECT 2168.600000 345.220000 2651.180000 424.600000 ;
      RECT 1538.600000 345.220000 2021.180000 424.600000 ;
      RECT 913.600000 345.220000 1396.180000 424.600000 ;
      RECT 288.600000 345.220000 771.180000 424.600000 ;
      RECT 2645.420000 341.060000 2651.180000 345.220000 ;
      RECT 2176.900000 341.060000 2642.880000 345.220000 ;
      RECT 2168.600000 341.060000 2174.360000 345.220000 ;
      RECT 2015.420000 341.060000 2021.180000 345.220000 ;
      RECT 1546.900000 341.060000 2012.880000 345.220000 ;
      RECT 1538.600000 341.060000 1544.360000 345.220000 ;
      RECT 1390.420000 341.060000 1396.180000 345.220000 ;
      RECT 921.900000 341.060000 1387.880000 345.220000 ;
      RECT 913.600000 341.060000 919.360000 345.220000 ;
      RECT 765.420000 341.060000 771.180000 345.220000 ;
      RECT 296.900000 341.060000 762.880000 345.220000 ;
      RECT 288.600000 341.060000 294.360000 345.220000 ;
      RECT 2168.600000 338.760000 2651.180000 341.060000 ;
      RECT 1538.600000 338.760000 2021.180000 341.060000 ;
      RECT 913.600000 338.760000 1396.180000 341.060000 ;
      RECT 288.600000 338.760000 771.180000 341.060000 ;
      RECT 2648.820000 334.600000 2651.180000 338.760000 ;
      RECT 2173.500000 334.600000 2646.280000 338.760000 ;
      RECT 2168.600000 334.600000 2170.960000 338.760000 ;
      RECT 2018.820000 334.600000 2021.180000 338.760000 ;
      RECT 1543.500000 334.600000 2016.280000 338.760000 ;
      RECT 1538.600000 334.600000 1540.960000 338.760000 ;
      RECT 1393.820000 334.600000 1396.180000 338.760000 ;
      RECT 918.500000 334.600000 1391.280000 338.760000 ;
      RECT 913.600000 334.600000 915.960000 338.760000 ;
      RECT 768.820000 334.600000 771.180000 338.760000 ;
      RECT 293.500000 334.600000 766.280000 338.760000 ;
      RECT 288.600000 334.600000 290.960000 338.760000 ;
      RECT 2168.600000 255.220000 2651.180000 334.600000 ;
      RECT 1538.600000 255.220000 2021.180000 334.600000 ;
      RECT 913.600000 255.220000 1396.180000 334.600000 ;
      RECT 288.600000 255.220000 771.180000 334.600000 ;
      RECT 2645.420000 251.060000 2651.180000 255.220000 ;
      RECT 2176.900000 251.060000 2642.880000 255.220000 ;
      RECT 2168.600000 251.060000 2174.360000 255.220000 ;
      RECT 2015.420000 251.060000 2021.180000 255.220000 ;
      RECT 1546.900000 251.060000 2012.880000 255.220000 ;
      RECT 1538.600000 251.060000 1544.360000 255.220000 ;
      RECT 1390.420000 251.060000 1396.180000 255.220000 ;
      RECT 921.900000 251.060000 1387.880000 255.220000 ;
      RECT 913.600000 251.060000 919.360000 255.220000 ;
      RECT 765.420000 251.060000 771.180000 255.220000 ;
      RECT 296.900000 251.060000 762.880000 255.220000 ;
      RECT 288.600000 251.060000 294.360000 255.220000 ;
      RECT 2168.600000 248.760000 2651.180000 251.060000 ;
      RECT 1538.600000 248.760000 2021.180000 251.060000 ;
      RECT 913.600000 248.760000 1396.180000 251.060000 ;
      RECT 288.600000 248.760000 771.180000 251.060000 ;
      RECT 2648.820000 244.600000 2651.180000 248.760000 ;
      RECT 2173.500000 244.600000 2646.280000 248.760000 ;
      RECT 2168.600000 244.600000 2170.960000 248.760000 ;
      RECT 2018.820000 244.600000 2021.180000 248.760000 ;
      RECT 1543.500000 244.600000 2016.280000 248.760000 ;
      RECT 1538.600000 244.600000 1540.960000 248.760000 ;
      RECT 1393.820000 244.600000 1396.180000 248.760000 ;
      RECT 918.500000 244.600000 1391.280000 248.760000 ;
      RECT 913.600000 244.600000 915.960000 248.760000 ;
      RECT 768.820000 244.600000 771.180000 248.760000 ;
      RECT 293.500000 244.600000 766.280000 248.760000 ;
      RECT 288.600000 244.600000 290.960000 248.760000 ;
      RECT 2168.600000 165.220000 2651.180000 244.600000 ;
      RECT 1538.600000 165.220000 2021.180000 244.600000 ;
      RECT 913.600000 165.220000 1396.180000 244.600000 ;
      RECT 288.600000 165.220000 771.180000 244.600000 ;
      RECT 2645.420000 161.060000 2651.180000 165.220000 ;
      RECT 2176.900000 161.060000 2642.880000 165.220000 ;
      RECT 2168.600000 161.060000 2174.360000 165.220000 ;
      RECT 2015.420000 161.060000 2021.180000 165.220000 ;
      RECT 1546.900000 161.060000 2012.880000 165.220000 ;
      RECT 1538.600000 161.060000 1544.360000 165.220000 ;
      RECT 1390.420000 161.060000 1396.180000 165.220000 ;
      RECT 921.900000 161.060000 1387.880000 165.220000 ;
      RECT 913.600000 161.060000 919.360000 165.220000 ;
      RECT 765.420000 161.060000 771.180000 165.220000 ;
      RECT 296.900000 161.060000 762.880000 165.220000 ;
      RECT 288.600000 161.060000 294.360000 165.220000 ;
      RECT 2168.600000 158.760000 2651.180000 161.060000 ;
      RECT 1538.600000 158.760000 2021.180000 161.060000 ;
      RECT 913.600000 158.760000 1396.180000 161.060000 ;
      RECT 288.600000 158.760000 771.180000 161.060000 ;
      RECT 2648.820000 154.600000 2651.180000 158.760000 ;
      RECT 2173.500000 154.600000 2646.280000 158.760000 ;
      RECT 2168.600000 154.600000 2170.960000 158.760000 ;
      RECT 2018.820000 154.600000 2021.180000 158.760000 ;
      RECT 1543.500000 154.600000 2016.280000 158.760000 ;
      RECT 1538.600000 154.600000 1540.960000 158.760000 ;
      RECT 1393.820000 154.600000 1396.180000 158.760000 ;
      RECT 918.500000 154.600000 1391.280000 158.760000 ;
      RECT 913.600000 154.600000 915.960000 158.760000 ;
      RECT 768.820000 154.600000 771.180000 158.760000 ;
      RECT 293.500000 154.600000 766.280000 158.760000 ;
      RECT 288.600000 154.600000 290.960000 158.760000 ;
      RECT 2168.600000 78.600000 2651.180000 154.600000 ;
      RECT 1538.600000 78.600000 2021.180000 154.600000 ;
      RECT 913.600000 78.600000 1396.180000 154.600000 ;
      RECT 288.600000 78.600000 771.180000 154.600000 ;
      RECT 2653.780000 76.000000 2654.780000 481.500000 ;
      RECT 2519.760000 76.000000 2651.180000 78.600000 ;
      RECT 2168.600000 76.000000 2243.600000 78.600000 ;
      RECT 2165.000000 76.000000 2166.000000 481.500000 ;
      RECT 2023.780000 76.000000 2024.780000 481.500000 ;
      RECT 1975.760000 76.000000 2021.180000 78.600000 ;
      RECT 1538.600000 76.000000 1563.600000 78.600000 ;
      RECT 1535.000000 76.000000 1536.000000 481.500000 ;
      RECT 1398.780000 76.000000 1399.780000 481.500000 ;
      RECT 1295.760000 76.000000 1396.180000 78.600000 ;
      RECT 913.600000 76.000000 1019.600000 78.600000 ;
      RECT 910.000000 76.000000 911.000000 481.500000 ;
      RECT 773.780000 76.000000 774.780000 481.500000 ;
      RECT 751.760000 76.000000 771.180000 78.600000 ;
      RECT 288.600000 76.000000 339.600000 78.600000 ;
      RECT 285.000000 76.000000 286.000000 481.500000 ;
      RECT 2519.760000 75.000000 2654.780000 76.000000 ;
      RECT 2383.760000 75.000000 2515.600000 78.600000 ;
      RECT 2247.760000 75.000000 2379.600000 78.600000 ;
      RECT 2165.000000 75.000000 2243.600000 76.000000 ;
      RECT 1839.760000 75.000000 1971.600000 78.600000 ;
      RECT 1703.760000 75.000000 1835.600000 78.600000 ;
      RECT 1567.760000 75.000000 1699.600000 78.600000 ;
      RECT 1295.760000 75.000000 1399.780000 76.000000 ;
      RECT 1159.760000 75.000000 1291.600000 78.600000 ;
      RECT 1023.760000 75.000000 1155.600000 78.600000 ;
      RECT 910.000000 75.000000 1019.600000 76.000000 ;
      RECT 615.760000 75.000000 747.600000 78.600000 ;
      RECT 479.760000 75.000000 611.600000 78.600000 ;
      RECT 343.760000 75.000000 475.600000 78.600000 ;
      RECT 2657.380000 72.400000 2719.600000 485.100000 ;
      RECT 2587.760000 72.400000 2654.780000 75.000000 ;
      RECT 2165.000000 72.400000 2175.600000 75.000000 ;
      RECT 2111.760000 72.400000 2162.400000 485.100000 ;
      RECT 2027.380000 72.400000 2039.600000 485.100000 ;
      RECT 1975.760000 72.400000 2024.780000 76.000000 ;
      RECT 1535.000000 72.400000 1563.600000 76.000000 ;
      RECT 1499.760000 72.400000 1532.400000 485.100000 ;
      RECT 1402.380000 72.400000 1427.600000 485.100000 ;
      RECT 1363.760000 72.400000 1399.780000 75.000000 ;
      RECT 910.000000 72.400000 951.600000 75.000000 ;
      RECT 887.760000 72.400000 907.400000 485.100000 ;
      RECT 777.380000 72.400000 815.600000 485.100000 ;
      RECT 751.760000 72.400000 774.780000 76.000000 ;
      RECT 285.000000 72.400000 339.600000 76.000000 ;
      RECT 275.760000 72.400000 282.400000 485.100000 ;
      RECT 2587.760000 68.760000 2719.600000 72.400000 ;
      RECT 2723.760000 25.060000 2787.600000 3442.940000 ;
      RECT 2655.760000 25.060000 2719.600000 68.760000 ;
      RECT 2587.760000 25.060000 2651.600000 68.760000 ;
      RECT 2519.760000 25.060000 2583.600000 75.000000 ;
      RECT 2451.760000 25.060000 2515.600000 75.000000 ;
      RECT 2383.760000 25.060000 2447.600000 75.000000 ;
      RECT 2315.760000 25.060000 2379.600000 75.000000 ;
      RECT 2247.760000 25.060000 2311.600000 75.000000 ;
      RECT 2179.760000 25.060000 2243.600000 75.000000 ;
      RECT 2111.760000 25.060000 2175.600000 72.400000 ;
      RECT 2043.760000 25.060000 2107.600000 3442.940000 ;
      RECT 1975.760000 25.060000 2039.600000 72.400000 ;
      RECT 1907.760000 25.060000 1971.600000 75.000000 ;
      RECT 1839.760000 25.060000 1903.600000 75.000000 ;
      RECT 1771.760000 25.060000 1835.600000 75.000000 ;
      RECT 1703.760000 25.060000 1767.600000 75.000000 ;
      RECT 1635.760000 25.060000 1699.600000 75.000000 ;
      RECT 1567.760000 25.060000 1631.600000 75.000000 ;
      RECT 1499.760000 25.060000 1563.600000 72.400000 ;
      RECT 1431.760000 25.060000 1495.600000 3442.940000 ;
      RECT 1363.760000 25.060000 1427.600000 72.400000 ;
      RECT 1295.760000 25.060000 1359.600000 75.000000 ;
      RECT 1227.760000 25.060000 1291.600000 75.000000 ;
      RECT 1159.760000 25.060000 1223.600000 75.000000 ;
      RECT 1091.760000 25.060000 1155.600000 75.000000 ;
      RECT 1023.760000 25.060000 1087.600000 75.000000 ;
      RECT 955.760000 25.060000 1019.600000 75.000000 ;
      RECT 887.760000 25.060000 951.600000 72.400000 ;
      RECT 819.760000 25.060000 883.600000 3442.940000 ;
      RECT 751.760000 25.060000 815.600000 72.400000 ;
      RECT 683.760000 25.060000 747.600000 75.000000 ;
      RECT 615.760000 25.060000 679.600000 75.000000 ;
      RECT 547.760000 25.060000 611.600000 75.000000 ;
      RECT 479.760000 25.060000 543.600000 75.000000 ;
      RECT 411.760000 25.060000 475.600000 75.000000 ;
      RECT 343.760000 25.060000 407.600000 75.000000 ;
      RECT 275.760000 25.060000 339.600000 72.400000 ;
      RECT 207.760000 25.060000 271.600000 3442.940000 ;
      RECT 139.760000 25.060000 203.600000 3442.940000 ;
      RECT 71.760000 25.060000 135.600000 3442.940000 ;
      RECT 2791.760000 18.860000 2830.900000 3449.140000 ;
      RECT 2655.760000 18.860000 2787.600000 25.060000 ;
      RECT 2519.760000 18.860000 2651.600000 25.060000 ;
      RECT 2383.760000 18.860000 2515.600000 25.060000 ;
      RECT 2247.760000 18.860000 2379.600000 25.060000 ;
      RECT 2111.760000 18.860000 2243.600000 25.060000 ;
      RECT 1975.760000 18.860000 2107.600000 25.060000 ;
      RECT 1839.760000 18.860000 1971.600000 25.060000 ;
      RECT 1703.760000 18.860000 1835.600000 25.060000 ;
      RECT 1567.760000 18.860000 1699.600000 25.060000 ;
      RECT 1431.760000 18.860000 1563.600000 25.060000 ;
      RECT 1295.760000 18.860000 1427.600000 25.060000 ;
      RECT 1159.760000 18.860000 1291.600000 25.060000 ;
      RECT 1023.760000 18.860000 1155.600000 25.060000 ;
      RECT 887.760000 18.860000 1019.600000 25.060000 ;
      RECT 751.760000 18.860000 883.600000 25.060000 ;
      RECT 615.760000 18.860000 747.600000 25.060000 ;
      RECT 479.760000 18.860000 611.600000 25.060000 ;
      RECT 343.760000 18.860000 475.600000 25.060000 ;
      RECT 207.760000 18.860000 339.600000 25.060000 ;
      RECT 71.760000 18.860000 203.600000 25.060000 ;
      RECT 28.920000 18.860000 67.600000 3449.140000 ;
      RECT 2841.000000 0.000000 2859.820000 3470.040000 ;
      RECT 2834.800000 0.000000 2837.100000 3470.040000 ;
      RECT 28.920000 0.000000 2830.900000 18.860000 ;
      RECT 22.720000 0.000000 25.020000 3470.040000 ;
      RECT 0.000000 0.000000 18.820000 3470.040000 ;
  END
END user_proj_example

END LIBRARY
